VERSION 5.8 ;
BUSBITCHARS "[]" ;
DIVIDERCHAR "/" ;
UNITS
    DATABASE MICRONS 1000 ;
END UNITS

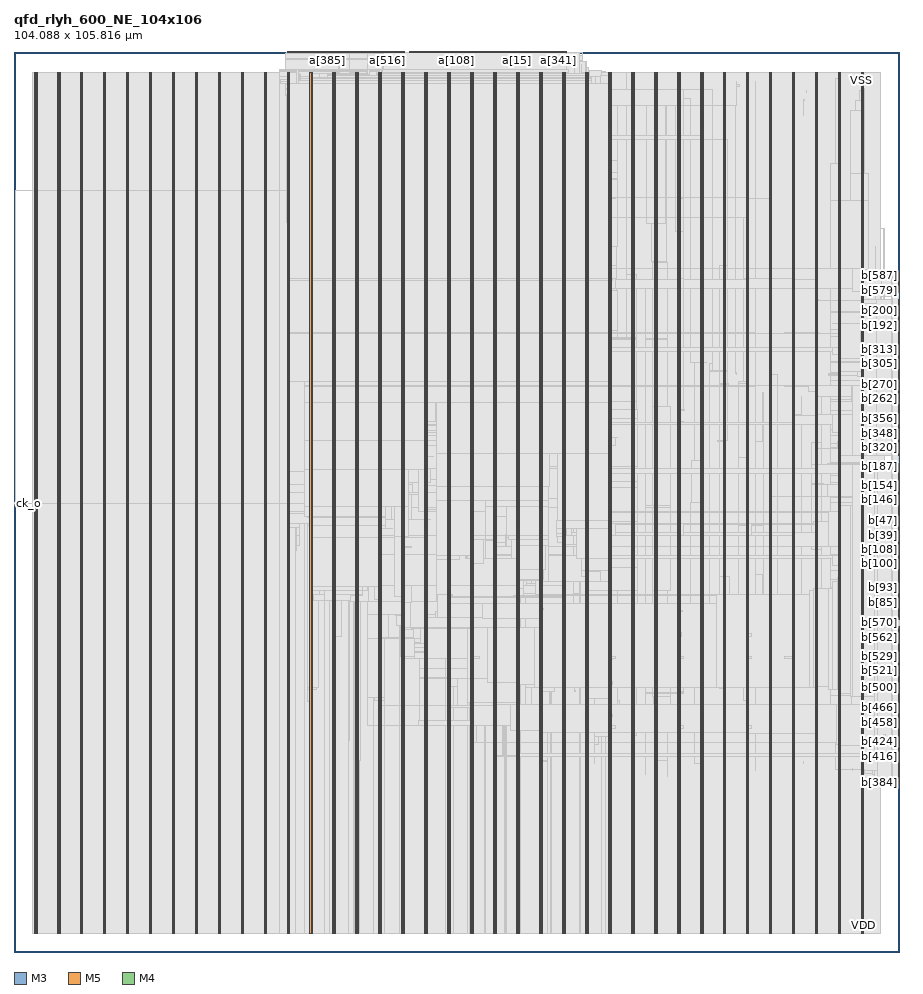
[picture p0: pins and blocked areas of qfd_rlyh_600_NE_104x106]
MACRO qfd_rlyh_600_NE_104x106
  FOREIGN qfd_rlyh_600_NE_104x106 0 0 ;
  CLASS BLOCK ;
  SIZE 104.088 BY 105.816 ;
  PIN a[0]
    DIRECTION INPUT ;
    USE SIGNAL ;
    PORT
      LAYER M3 ;
        RECT  58.068 105.779 58.086 105.816 ;
    END
  END a[0]
  PIN a[100]
    DIRECTION INPUT ;
    USE SIGNAL ;
    PORT
      LAYER M3 ;
        RECT  51.444 105.779 51.462 105.816 ;
    END
  END a[100]
  PIN a[101]
    DIRECTION INPUT ;
    USE SIGNAL ;
    PORT
      LAYER M3 ;
        RECT  51.516 105.779 51.534 105.816 ;
    END
  END a[101]
  PIN a[102]
    DIRECTION INPUT ;
    USE SIGNAL ;
    PORT
      LAYER M3 ;
        RECT  51.588 105.779 51.606 105.816 ;
    END
  END a[102]
  PIN a[103]
    DIRECTION INPUT ;
    USE SIGNAL ;
    PORT
      LAYER M3 ;
        RECT  51.66 105.779 51.678 105.816 ;
    END
  END a[103]
  PIN a[104]
    DIRECTION INPUT ;
    USE SIGNAL ;
    PORT
      LAYER M3 ;
        RECT  51.732 105.779 51.75 105.816 ;
    END
  END a[104]
  PIN a[105]
    DIRECTION INPUT ;
    USE SIGNAL ;
    PORT
      LAYER M3 ;
        RECT  51.804 105.779 51.822 105.816 ;
    END
  END a[105]
  PIN a[106]
    DIRECTION INPUT ;
    USE SIGNAL ;
    PORT
      LAYER M3 ;
        RECT  51.876 105.779 51.894 105.816 ;
    END
  END a[106]
  PIN a[107]
    DIRECTION INPUT ;
    USE SIGNAL ;
    PORT
      LAYER M3 ;
        RECT  51.948 105.779 51.966 105.816 ;
    END
  END a[107]
  PIN a[108]
    DIRECTION INPUT ;
    USE SIGNAL ;
    PORT
      LAYER M3 ;
        RECT  52.02 105.779 52.038 105.816 ;
    END
  END a[108]
  PIN a[109]
    DIRECTION INPUT ;
    USE SIGNAL ;
    PORT
      LAYER M3 ;
        RECT  52.092 105.779 52.11 105.816 ;
    END
  END a[109]
  PIN a[10]
    DIRECTION INPUT ;
    USE SIGNAL ;
    PORT
      LAYER M3 ;
        RECT  58.788 105.779 58.806 105.816 ;
    END
  END a[10]
  PIN a[110]
    DIRECTION INPUT ;
    USE SIGNAL ;
    PORT
      LAYER M3 ;
        RECT  52.164 105.779 52.182 105.816 ;
    END
  END a[110]
  PIN a[111]
    DIRECTION INPUT ;
    USE SIGNAL ;
    PORT
      LAYER M3 ;
        RECT  52.236 105.779 52.254 105.816 ;
    END
  END a[111]
  PIN a[112]
    DIRECTION INPUT ;
    USE SIGNAL ;
    PORT
      LAYER M3 ;
        RECT  52.308 105.779 52.326 105.816 ;
    END
  END a[112]
  PIN a[113]
    DIRECTION INPUT ;
    USE SIGNAL ;
    PORT
      LAYER M3 ;
        RECT  52.38 105.779 52.398 105.816 ;
    END
  END a[113]
  PIN a[114]
    DIRECTION INPUT ;
    USE SIGNAL ;
    PORT
      LAYER M3 ;
        RECT  52.452 105.779 52.47 105.816 ;
    END
  END a[114]
  PIN a[115]
    DIRECTION INPUT ;
    USE SIGNAL ;
    PORT
      LAYER M3 ;
        RECT  52.524 105.779 52.542 105.816 ;
    END
  END a[115]
  PIN a[116]
    DIRECTION INPUT ;
    USE SIGNAL ;
    PORT
      LAYER M3 ;
        RECT  52.596 105.779 52.614 105.816 ;
    END
  END a[116]
  PIN a[117]
    DIRECTION INPUT ;
    USE SIGNAL ;
    PORT
      LAYER M3 ;
        RECT  52.668 105.779 52.686 105.816 ;
    END
  END a[117]
  PIN a[118]
    DIRECTION INPUT ;
    USE SIGNAL ;
    PORT
      LAYER M3 ;
        RECT  52.74 105.779 52.758 105.816 ;
    END
  END a[118]
  PIN a[119]
    DIRECTION INPUT ;
    USE SIGNAL ;
    PORT
      LAYER M3 ;
        RECT  52.812 105.779 52.83 105.816 ;
    END
  END a[119]
  PIN a[11]
    DIRECTION INPUT ;
    USE SIGNAL ;
    PORT
      LAYER M3 ;
        RECT  58.86 105.779 58.878 105.816 ;
    END
  END a[11]
  PIN a[120]
    DIRECTION INPUT ;
    USE SIGNAL ;
    PORT
      LAYER M3 ;
        RECT  52.884 105.779 52.902 105.816 ;
    END
  END a[120]
  PIN a[121]
    DIRECTION INPUT ;
    USE SIGNAL ;
    PORT
      LAYER M3 ;
        RECT  52.956 105.779 52.974 105.816 ;
    END
  END a[121]
  PIN a[122]
    DIRECTION INPUT ;
    USE SIGNAL ;
    PORT
      LAYER M3 ;
        RECT  53.028 105.779 53.046 105.816 ;
    END
  END a[122]
  PIN a[123]
    DIRECTION INPUT ;
    USE SIGNAL ;
    PORT
      LAYER M3 ;
        RECT  53.1 105.779 53.118 105.816 ;
    END
  END a[123]
  PIN a[124]
    DIRECTION INPUT ;
    USE SIGNAL ;
    PORT
      LAYER M3 ;
        RECT  53.172 105.779 53.19 105.816 ;
    END
  END a[124]
  PIN a[125]
    DIRECTION INPUT ;
    USE SIGNAL ;
    PORT
      LAYER M3 ;
        RECT  53.244 105.779 53.262 105.816 ;
    END
  END a[125]
  PIN a[126]
    DIRECTION INPUT ;
    USE SIGNAL ;
    PORT
      LAYER M3 ;
        RECT  53.316 105.779 53.334 105.816 ;
    END
  END a[126]
  PIN a[127]
    DIRECTION INPUT ;
    USE SIGNAL ;
    PORT
      LAYER M3 ;
        RECT  53.388 105.779 53.406 105.816 ;
    END
  END a[127]
  PIN a[128]
    DIRECTION INPUT ;
    USE SIGNAL ;
    PORT
      LAYER M3 ;
        RECT  53.46 105.779 53.478 105.816 ;
    END
  END a[128]
  PIN a[129]
    DIRECTION INPUT ;
    USE SIGNAL ;
    PORT
      LAYER M3 ;
        RECT  53.532 105.779 53.55 105.816 ;
    END
  END a[129]
  PIN a[12]
    DIRECTION INPUT ;
    USE SIGNAL ;
    PORT
      LAYER M3 ;
        RECT  58.932 105.779 58.95 105.816 ;
    END
  END a[12]
  PIN a[130]
    DIRECTION INPUT ;
    USE SIGNAL ;
    PORT
      LAYER M3 ;
        RECT  53.604 105.779 53.622 105.816 ;
    END
  END a[130]
  PIN a[131]
    DIRECTION INPUT ;
    USE SIGNAL ;
    PORT
      LAYER M3 ;
        RECT  53.676 105.779 53.694 105.816 ;
    END
  END a[131]
  PIN a[132]
    DIRECTION INPUT ;
    USE SIGNAL ;
    PORT
      LAYER M3 ;
        RECT  53.748 105.779 53.766 105.816 ;
    END
  END a[132]
  PIN a[133]
    DIRECTION INPUT ;
    USE SIGNAL ;
    PORT
      LAYER M3 ;
        RECT  53.82 105.779 53.838 105.816 ;
    END
  END a[133]
  PIN a[134]
    DIRECTION INPUT ;
    USE SIGNAL ;
    PORT
      LAYER M3 ;
        RECT  53.892 105.779 53.91 105.816 ;
    END
  END a[134]
  PIN a[135]
    DIRECTION INPUT ;
    USE SIGNAL ;
    PORT
      LAYER M3 ;
        RECT  53.964 105.779 53.982 105.816 ;
    END
  END a[135]
  PIN a[136]
    DIRECTION INPUT ;
    USE SIGNAL ;
    PORT
      LAYER M3 ;
        RECT  54.036 105.779 54.054 105.816 ;
    END
  END a[136]
  PIN a[137]
    DIRECTION INPUT ;
    USE SIGNAL ;
    PORT
      LAYER M3 ;
        RECT  54.108 105.779 54.126 105.816 ;
    END
  END a[137]
  PIN a[138]
    DIRECTION INPUT ;
    USE SIGNAL ;
    PORT
      LAYER M3 ;
        RECT  54.18 105.779 54.198 105.816 ;
    END
  END a[138]
  PIN a[139]
    DIRECTION INPUT ;
    USE SIGNAL ;
    PORT
      LAYER M3 ;
        RECT  54.252 105.779 54.27 105.816 ;
    END
  END a[139]
  PIN a[13]
    DIRECTION INPUT ;
    USE SIGNAL ;
    PORT
      LAYER M3 ;
        RECT  59.004 105.779 59.022 105.816 ;
    END
  END a[13]
  PIN a[140]
    DIRECTION INPUT ;
    USE SIGNAL ;
    PORT
      LAYER M3 ;
        RECT  54.324 105.779 54.342 105.816 ;
    END
  END a[140]
  PIN a[141]
    DIRECTION INPUT ;
    USE SIGNAL ;
    PORT
      LAYER M3 ;
        RECT  54.396 105.779 54.414 105.816 ;
    END
  END a[141]
  PIN a[142]
    DIRECTION INPUT ;
    USE SIGNAL ;
    PORT
      LAYER M3 ;
        RECT  54.468 105.779 54.486 105.816 ;
    END
  END a[142]
  PIN a[143]
    DIRECTION INPUT ;
    USE SIGNAL ;
    PORT
      LAYER M3 ;
        RECT  54.54 105.779 54.558 105.816 ;
    END
  END a[143]
  PIN a[144]
    DIRECTION INPUT ;
    USE SIGNAL ;
    PORT
      LAYER M3 ;
        RECT  54.612 105.779 54.63 105.816 ;
    END
  END a[144]
  PIN a[145]
    DIRECTION INPUT ;
    USE SIGNAL ;
    PORT
      LAYER M3 ;
        RECT  54.684 105.779 54.702 105.816 ;
    END
  END a[145]
  PIN a[146]
    DIRECTION INPUT ;
    USE SIGNAL ;
    PORT
      LAYER M3 ;
        RECT  54.756 105.779 54.774 105.816 ;
    END
  END a[146]
  PIN a[147]
    DIRECTION INPUT ;
    USE SIGNAL ;
    PORT
      LAYER M3 ;
        RECT  54.828 105.779 54.846 105.816 ;
    END
  END a[147]
  PIN a[148]
    DIRECTION INPUT ;
    USE SIGNAL ;
    PORT
      LAYER M3 ;
        RECT  54.9 105.779 54.918 105.816 ;
    END
  END a[148]
  PIN a[149]
    DIRECTION INPUT ;
    USE SIGNAL ;
    PORT
      LAYER M3 ;
        RECT  54.972 105.779 54.99 105.816 ;
    END
  END a[149]
  PIN a[14]
    DIRECTION INPUT ;
    USE SIGNAL ;
    PORT
      LAYER M3 ;
        RECT  59.076 105.779 59.094 105.816 ;
    END
  END a[14]
  PIN a[150]
    DIRECTION INPUT ;
    USE SIGNAL ;
    PORT
      LAYER M3 ;
        RECT  55.044 105.779 55.062 105.816 ;
    END
  END a[150]
  PIN a[151]
    DIRECTION INPUT ;
    USE SIGNAL ;
    PORT
      LAYER M3 ;
        RECT  55.116 105.779 55.134 105.816 ;
    END
  END a[151]
  PIN a[152]
    DIRECTION INPUT ;
    USE SIGNAL ;
    PORT
      LAYER M3 ;
        RECT  55.188 105.779 55.206 105.816 ;
    END
  END a[152]
  PIN a[153]
    DIRECTION INPUT ;
    USE SIGNAL ;
    PORT
      LAYER M3 ;
        RECT  55.26 105.779 55.278 105.816 ;
    END
  END a[153]
  PIN a[154]
    DIRECTION INPUT ;
    USE SIGNAL ;
    PORT
      LAYER M3 ;
        RECT  55.332 105.779 55.35 105.816 ;
    END
  END a[154]
  PIN a[155]
    DIRECTION INPUT ;
    USE SIGNAL ;
    PORT
      LAYER M3 ;
        RECT  55.404 105.779 55.422 105.816 ;
    END
  END a[155]
  PIN a[156]
    DIRECTION INPUT ;
    USE SIGNAL ;
    PORT
      LAYER M3 ;
        RECT  55.476 105.779 55.494 105.816 ;
    END
  END a[156]
  PIN a[157]
    DIRECTION INPUT ;
    USE SIGNAL ;
    PORT
      LAYER M3 ;
        RECT  55.548 105.779 55.566 105.816 ;
    END
  END a[157]
  PIN a[158]
    DIRECTION INPUT ;
    USE SIGNAL ;
    PORT
      LAYER M3 ;
        RECT  55.62 105.779 55.638 105.816 ;
    END
  END a[158]
  PIN a[159]
    DIRECTION INPUT ;
    USE SIGNAL ;
    PORT
      LAYER M3 ;
        RECT  55.692 105.779 55.71 105.816 ;
    END
  END a[159]
  PIN a[15]
    DIRECTION INPUT ;
    USE SIGNAL ;
    PORT
      LAYER M3 ;
        RECT  59.148 105.779 59.166 105.816 ;
    END
  END a[15]
  PIN a[160]
    DIRECTION INPUT ;
    USE SIGNAL ;
    PORT
      LAYER M3 ;
        RECT  48.852 105.779 48.87 105.816 ;
    END
  END a[160]
  PIN a[161]
    DIRECTION INPUT ;
    USE SIGNAL ;
    PORT
      LAYER M3 ;
        RECT  48.924 105.779 48.942 105.816 ;
    END
  END a[161]
  PIN a[162]
    DIRECTION INPUT ;
    USE SIGNAL ;
    PORT
      LAYER M3 ;
        RECT  48.996 105.779 49.014 105.816 ;
    END
  END a[162]
  PIN a[163]
    DIRECTION INPUT ;
    USE SIGNAL ;
    PORT
      LAYER M3 ;
        RECT  49.068 105.779 49.086 105.816 ;
    END
  END a[163]
  PIN a[164]
    DIRECTION INPUT ;
    USE SIGNAL ;
    PORT
      LAYER M3 ;
        RECT  49.14 105.779 49.158 105.816 ;
    END
  END a[164]
  PIN a[165]
    DIRECTION INPUT ;
    USE SIGNAL ;
    PORT
      LAYER M3 ;
        RECT  49.212 105.779 49.23 105.816 ;
    END
  END a[165]
  PIN a[166]
    DIRECTION INPUT ;
    USE SIGNAL ;
    PORT
      LAYER M3 ;
        RECT  49.284 105.779 49.302 105.816 ;
    END
  END a[166]
  PIN a[167]
    DIRECTION INPUT ;
    USE SIGNAL ;
    PORT
      LAYER M3 ;
        RECT  49.356 105.779 49.374 105.816 ;
    END
  END a[167]
  PIN a[168]
    DIRECTION INPUT ;
    USE SIGNAL ;
    PORT
      LAYER M3 ;
        RECT  49.428 105.779 49.446 105.816 ;
    END
  END a[168]
  PIN a[169]
    DIRECTION INPUT ;
    USE SIGNAL ;
    PORT
      LAYER M3 ;
        RECT  49.5 105.779 49.518 105.816 ;
    END
  END a[169]
  PIN a[16]
    DIRECTION INPUT ;
    USE SIGNAL ;
    PORT
      LAYER M3 ;
        RECT  59.22 105.779 59.238 105.816 ;
    END
  END a[16]
  PIN a[170]
    DIRECTION INPUT ;
    USE SIGNAL ;
    PORT
      LAYER M3 ;
        RECT  49.572 105.779 49.59 105.816 ;
    END
  END a[170]
  PIN a[171]
    DIRECTION INPUT ;
    USE SIGNAL ;
    PORT
      LAYER M3 ;
        RECT  49.644 105.779 49.662 105.816 ;
    END
  END a[171]
  PIN a[172]
    DIRECTION INPUT ;
    USE SIGNAL ;
    PORT
      LAYER M3 ;
        RECT  49.716 105.779 49.734 105.816 ;
    END
  END a[172]
  PIN a[173]
    DIRECTION INPUT ;
    USE SIGNAL ;
    PORT
      LAYER M3 ;
        RECT  49.788 105.779 49.806 105.816 ;
    END
  END a[173]
  PIN a[174]
    DIRECTION INPUT ;
    USE SIGNAL ;
    PORT
      LAYER M3 ;
        RECT  49.86 105.779 49.878 105.816 ;
    END
  END a[174]
  PIN a[175]
    DIRECTION INPUT ;
    USE SIGNAL ;
    PORT
      LAYER M3 ;
        RECT  49.932 105.779 49.95 105.816 ;
    END
  END a[175]
  PIN a[176]
    DIRECTION INPUT ;
    USE SIGNAL ;
    PORT
      LAYER M3 ;
        RECT  50.004 105.779 50.022 105.816 ;
    END
  END a[176]
  PIN a[177]
    DIRECTION INPUT ;
    USE SIGNAL ;
    PORT
      LAYER M3 ;
        RECT  50.076 105.779 50.094 105.816 ;
    END
  END a[177]
  PIN a[178]
    DIRECTION INPUT ;
    USE SIGNAL ;
    PORT
      LAYER M3 ;
        RECT  50.148 105.779 50.166 105.816 ;
    END
  END a[178]
  PIN a[179]
    DIRECTION INPUT ;
    USE SIGNAL ;
    PORT
      LAYER M3 ;
        RECT  50.22 105.779 50.238 105.816 ;
    END
  END a[179]
  PIN a[17]
    DIRECTION INPUT ;
    USE SIGNAL ;
    PORT
      LAYER M3 ;
        RECT  59.292 105.779 59.31 105.816 ;
    END
  END a[17]
  PIN a[180]
    DIRECTION INPUT ;
    USE SIGNAL ;
    PORT
      LAYER M3 ;
        RECT  50.292 105.779 50.31 105.816 ;
    END
  END a[180]
  PIN a[181]
    DIRECTION INPUT ;
    USE SIGNAL ;
    PORT
      LAYER M3 ;
        RECT  50.364 105.779 50.382 105.816 ;
    END
  END a[181]
  PIN a[182]
    DIRECTION INPUT ;
    USE SIGNAL ;
    PORT
      LAYER M3 ;
        RECT  50.436 105.779 50.454 105.816 ;
    END
  END a[182]
  PIN a[183]
    DIRECTION INPUT ;
    USE SIGNAL ;
    PORT
      LAYER M3 ;
        RECT  50.508 105.779 50.526 105.816 ;
    END
  END a[183]
  PIN a[184]
    DIRECTION INPUT ;
    USE SIGNAL ;
    PORT
      LAYER M3 ;
        RECT  50.58 105.779 50.598 105.816 ;
    END
  END a[184]
  PIN a[185]
    DIRECTION INPUT ;
    USE SIGNAL ;
    PORT
      LAYER M3 ;
        RECT  50.652 105.779 50.67 105.816 ;
    END
  END a[185]
  PIN a[186]
    DIRECTION INPUT ;
    USE SIGNAL ;
    PORT
      LAYER M3 ;
        RECT  50.724 105.779 50.742 105.816 ;
    END
  END a[186]
  PIN a[187]
    DIRECTION INPUT ;
    USE SIGNAL ;
    PORT
      LAYER M3 ;
        RECT  50.796 105.779 50.814 105.816 ;
    END
  END a[187]
  PIN a[188]
    DIRECTION INPUT ;
    USE SIGNAL ;
    PORT
      LAYER M3 ;
        RECT  50.868 105.779 50.886 105.816 ;
    END
  END a[188]
  PIN a[189]
    DIRECTION INPUT ;
    USE SIGNAL ;
    PORT
      LAYER M3 ;
        RECT  50.94 105.779 50.958 105.816 ;
    END
  END a[189]
  PIN a[18]
    DIRECTION INPUT ;
    USE SIGNAL ;
    PORT
      LAYER M3 ;
        RECT  59.364 105.779 59.382 105.816 ;
    END
  END a[18]
  PIN a[190]
    DIRECTION INPUT ;
    USE SIGNAL ;
    PORT
      LAYER M3 ;
        RECT  51.012 105.779 51.03 105.816 ;
    END
  END a[190]
  PIN a[191]
    DIRECTION INPUT ;
    USE SIGNAL ;
    PORT
      LAYER M3 ;
        RECT  51.084 105.779 51.102 105.816 ;
    END
  END a[191]
  PIN a[192]
    DIRECTION INPUT ;
    USE SIGNAL ;
    PORT
      LAYER M5 ;
        RECT  49.68 105.732 49.704 105.816 ;
    END
  END a[192]
  PIN a[193]
    DIRECTION INPUT ;
    USE SIGNAL ;
    PORT
      LAYER M5 ;
        RECT  49.776 105.732 49.8 105.816 ;
    END
  END a[193]
  PIN a[194]
    DIRECTION INPUT ;
    USE SIGNAL ;
    PORT
      LAYER M5 ;
        RECT  49.872 105.732 49.896 105.816 ;
    END
  END a[194]
  PIN a[195]
    DIRECTION INPUT ;
    USE SIGNAL ;
    PORT
      LAYER M5 ;
        RECT  49.968 105.732 49.992 105.816 ;
    END
  END a[195]
  PIN a[196]
    DIRECTION INPUT ;
    USE SIGNAL ;
    PORT
      LAYER M5 ;
        RECT  50.064 105.732 50.088 105.816 ;
    END
  END a[196]
  PIN a[197]
    DIRECTION INPUT ;
    USE SIGNAL ;
    PORT
      LAYER M5 ;
        RECT  50.16 105.732 50.184 105.816 ;
    END
  END a[197]
  PIN a[198]
    DIRECTION INPUT ;
    USE SIGNAL ;
    PORT
      LAYER M5 ;
        RECT  50.256 105.732 50.28 105.816 ;
    END
  END a[198]
  PIN a[199]
    DIRECTION INPUT ;
    USE SIGNAL ;
    PORT
      LAYER M5 ;
        RECT  50.352 105.732 50.376 105.816 ;
    END
  END a[199]
  PIN a[19]
    DIRECTION INPUT ;
    USE SIGNAL ;
    PORT
      LAYER M3 ;
        RECT  59.436 105.779 59.454 105.816 ;
    END
  END a[19]
  PIN a[1]
    DIRECTION INPUT ;
    USE SIGNAL ;
    PORT
      LAYER M3 ;
        RECT  58.14 105.779 58.158 105.816 ;
    END
  END a[1]
  PIN a[200]
    DIRECTION INPUT ;
    USE SIGNAL ;
    PORT
      LAYER M5 ;
        RECT  50.448 105.732 50.472 105.816 ;
    END
  END a[200]
  PIN a[201]
    DIRECTION INPUT ;
    USE SIGNAL ;
    PORT
      LAYER M5 ;
        RECT  50.544 105.732 50.568 105.816 ;
    END
  END a[201]
  PIN a[202]
    DIRECTION INPUT ;
    USE SIGNAL ;
    PORT
      LAYER M5 ;
        RECT  50.64 105.732 50.664 105.816 ;
    END
  END a[202]
  PIN a[203]
    DIRECTION INPUT ;
    USE SIGNAL ;
    PORT
      LAYER M5 ;
        RECT  50.736 105.732 50.76 105.816 ;
    END
  END a[203]
  PIN a[204]
    DIRECTION INPUT ;
    USE SIGNAL ;
    PORT
      LAYER M5 ;
        RECT  50.832 105.732 50.856 105.816 ;
    END
  END a[204]
  PIN a[205]
    DIRECTION INPUT ;
    USE SIGNAL ;
    PORT
      LAYER M5 ;
        RECT  50.928 105.732 50.952 105.816 ;
    END
  END a[205]
  PIN a[206]
    DIRECTION INPUT ;
    USE SIGNAL ;
    PORT
      LAYER M5 ;
        RECT  51.024 105.732 51.048 105.816 ;
    END
  END a[206]
  PIN a[207]
    DIRECTION INPUT ;
    USE SIGNAL ;
    PORT
      LAYER M5 ;
        RECT  51.12 105.732 51.144 105.816 ;
    END
  END a[207]
  PIN a[208]
    DIRECTION INPUT ;
    USE SIGNAL ;
    PORT
      LAYER M5 ;
        RECT  51.216 105.732 51.24 105.816 ;
    END
  END a[208]
  PIN a[209]
    DIRECTION INPUT ;
    USE SIGNAL ;
    PORT
      LAYER M5 ;
        RECT  51.312 105.732 51.336 105.816 ;
    END
  END a[209]
  PIN a[20]
    DIRECTION INPUT ;
    USE SIGNAL ;
    PORT
      LAYER M3 ;
        RECT  59.508 105.779 59.526 105.816 ;
    END
  END a[20]
  PIN a[210]
    DIRECTION INPUT ;
    USE SIGNAL ;
    PORT
      LAYER M5 ;
        RECT  51.408 105.732 51.432 105.816 ;
    END
  END a[210]
  PIN a[211]
    DIRECTION INPUT ;
    USE SIGNAL ;
    PORT
      LAYER M5 ;
        RECT  51.504 105.732 51.528 105.816 ;
    END
  END a[211]
  PIN a[212]
    DIRECTION INPUT ;
    USE SIGNAL ;
    PORT
      LAYER M5 ;
        RECT  51.6 105.732 51.624 105.816 ;
    END
  END a[212]
  PIN a[213]
    DIRECTION INPUT ;
    USE SIGNAL ;
    PORT
      LAYER M5 ;
        RECT  51.696 105.732 51.72 105.816 ;
    END
  END a[213]
  PIN a[214]
    DIRECTION INPUT ;
    USE SIGNAL ;
    PORT
      LAYER M5 ;
        RECT  51.792 105.732 51.816 105.816 ;
    END
  END a[214]
  PIN a[215]
    DIRECTION INPUT ;
    USE SIGNAL ;
    PORT
      LAYER M5 ;
        RECT  51.888 105.732 51.912 105.816 ;
    END
  END a[215]
  PIN a[216]
    DIRECTION INPUT ;
    USE SIGNAL ;
    PORT
      LAYER M5 ;
        RECT  51.984 105.732 52.008 105.816 ;
    END
  END a[216]
  PIN a[217]
    DIRECTION INPUT ;
    USE SIGNAL ;
    PORT
      LAYER M5 ;
        RECT  52.08 105.732 52.104 105.816 ;
    END
  END a[217]
  PIN a[218]
    DIRECTION INPUT ;
    USE SIGNAL ;
    PORT
      LAYER M5 ;
        RECT  52.176 105.732 52.2 105.816 ;
    END
  END a[218]
  PIN a[219]
    DIRECTION INPUT ;
    USE SIGNAL ;
    PORT
      LAYER M5 ;
        RECT  52.272 105.732 52.296 105.816 ;
    END
  END a[219]
  PIN a[21]
    DIRECTION INPUT ;
    USE SIGNAL ;
    PORT
      LAYER M3 ;
        RECT  59.58 105.779 59.598 105.816 ;
    END
  END a[21]
  PIN a[220]
    DIRECTION INPUT ;
    USE SIGNAL ;
    PORT
      LAYER M5 ;
        RECT  52.368 105.732 52.392 105.816 ;
    END
  END a[220]
  PIN a[221]
    DIRECTION INPUT ;
    USE SIGNAL ;
    PORT
      LAYER M5 ;
        RECT  52.464 105.732 52.488 105.816 ;
    END
  END a[221]
  PIN a[222]
    DIRECTION INPUT ;
    USE SIGNAL ;
    PORT
      LAYER M5 ;
        RECT  52.56 105.732 52.584 105.816 ;
    END
  END a[222]
  PIN a[223]
    DIRECTION INPUT ;
    USE SIGNAL ;
    PORT
      LAYER M5 ;
        RECT  52.656 105.732 52.68 105.816 ;
    END
  END a[223]
  PIN a[224]
    DIRECTION INPUT ;
    USE SIGNAL ;
    PORT
      LAYER M5 ;
        RECT  46.608 105.732 46.632 105.816 ;
    END
  END a[224]
  PIN a[225]
    DIRECTION INPUT ;
    USE SIGNAL ;
    PORT
      LAYER M5 ;
        RECT  46.704 105.732 46.728 105.816 ;
    END
  END a[225]
  PIN a[226]
    DIRECTION INPUT ;
    USE SIGNAL ;
    PORT
      LAYER M5 ;
        RECT  46.8 105.732 46.824 105.816 ;
    END
  END a[226]
  PIN a[227]
    DIRECTION INPUT ;
    USE SIGNAL ;
    PORT
      LAYER M5 ;
        RECT  46.896 105.732 46.92 105.816 ;
    END
  END a[227]
  PIN a[228]
    DIRECTION INPUT ;
    USE SIGNAL ;
    PORT
      LAYER M5 ;
        RECT  46.992 105.732 47.016 105.816 ;
    END
  END a[228]
  PIN a[229]
    DIRECTION INPUT ;
    USE SIGNAL ;
    PORT
      LAYER M5 ;
        RECT  47.088 105.732 47.112 105.816 ;
    END
  END a[229]
  PIN a[22]
    DIRECTION INPUT ;
    USE SIGNAL ;
    PORT
      LAYER M3 ;
        RECT  59.652 105.779 59.67 105.816 ;
    END
  END a[22]
  PIN a[230]
    DIRECTION INPUT ;
    USE SIGNAL ;
    PORT
      LAYER M5 ;
        RECT  47.184 105.732 47.208 105.816 ;
    END
  END a[230]
  PIN a[231]
    DIRECTION INPUT ;
    USE SIGNAL ;
    PORT
      LAYER M5 ;
        RECT  47.28 105.732 47.304 105.816 ;
    END
  END a[231]
  PIN a[232]
    DIRECTION INPUT ;
    USE SIGNAL ;
    PORT
      LAYER M5 ;
        RECT  47.376 105.732 47.4 105.816 ;
    END
  END a[232]
  PIN a[233]
    DIRECTION INPUT ;
    USE SIGNAL ;
    PORT
      LAYER M5 ;
        RECT  47.472 105.732 47.496 105.816 ;
    END
  END a[233]
  PIN a[234]
    DIRECTION INPUT ;
    USE SIGNAL ;
    PORT
      LAYER M5 ;
        RECT  47.568 105.732 47.592 105.816 ;
    END
  END a[234]
  PIN a[235]
    DIRECTION INPUT ;
    USE SIGNAL ;
    PORT
      LAYER M5 ;
        RECT  47.664 105.732 47.688 105.816 ;
    END
  END a[235]
  PIN a[236]
    DIRECTION INPUT ;
    USE SIGNAL ;
    PORT
      LAYER M5 ;
        RECT  47.76 105.732 47.784 105.816 ;
    END
  END a[236]
  PIN a[237]
    DIRECTION INPUT ;
    USE SIGNAL ;
    PORT
      LAYER M5 ;
        RECT  47.856 105.732 47.88 105.816 ;
    END
  END a[237]
  PIN a[238]
    DIRECTION INPUT ;
    USE SIGNAL ;
    PORT
      LAYER M5 ;
        RECT  47.952 105.732 47.976 105.816 ;
    END
  END a[238]
  PIN a[239]
    DIRECTION INPUT ;
    USE SIGNAL ;
    PORT
      LAYER M5 ;
        RECT  48.048 105.732 48.072 105.816 ;
    END
  END a[239]
  PIN a[23]
    DIRECTION INPUT ;
    USE SIGNAL ;
    PORT
      LAYER M3 ;
        RECT  59.724 105.779 59.742 105.816 ;
    END
  END a[23]
  PIN a[240]
    DIRECTION INPUT ;
    USE SIGNAL ;
    PORT
      LAYER M5 ;
        RECT  48.144 105.732 48.168 105.816 ;
    END
  END a[240]
  PIN a[241]
    DIRECTION INPUT ;
    USE SIGNAL ;
    PORT
      LAYER M5 ;
        RECT  48.24 105.732 48.264 105.816 ;
    END
  END a[241]
  PIN a[242]
    DIRECTION INPUT ;
    USE SIGNAL ;
    PORT
      LAYER M5 ;
        RECT  48.336 105.732 48.36 105.816 ;
    END
  END a[242]
  PIN a[243]
    DIRECTION INPUT ;
    USE SIGNAL ;
    PORT
      LAYER M5 ;
        RECT  48.432 105.732 48.456 105.816 ;
    END
  END a[243]
  PIN a[244]
    DIRECTION INPUT ;
    USE SIGNAL ;
    PORT
      LAYER M5 ;
        RECT  48.528 105.732 48.552 105.816 ;
    END
  END a[244]
  PIN a[245]
    DIRECTION INPUT ;
    USE SIGNAL ;
    PORT
      LAYER M5 ;
        RECT  48.624 105.732 48.648 105.816 ;
    END
  END a[245]
  PIN a[246]
    DIRECTION INPUT ;
    USE SIGNAL ;
    PORT
      LAYER M5 ;
        RECT  48.72 105.732 48.744 105.816 ;
    END
  END a[246]
  PIN a[247]
    DIRECTION INPUT ;
    USE SIGNAL ;
    PORT
      LAYER M5 ;
        RECT  48.816 105.732 48.84 105.816 ;
    END
  END a[247]
  PIN a[248]
    DIRECTION INPUT ;
    USE SIGNAL ;
    PORT
      LAYER M5 ;
        RECT  48.912 105.732 48.936 105.816 ;
    END
  END a[248]
  PIN a[249]
    DIRECTION INPUT ;
    USE SIGNAL ;
    PORT
      LAYER M5 ;
        RECT  49.008 105.732 49.032 105.816 ;
    END
  END a[249]
  PIN a[24]
    DIRECTION INPUT ;
    USE SIGNAL ;
    PORT
      LAYER M3 ;
        RECT  59.796 105.779 59.814 105.816 ;
    END
  END a[24]
  PIN a[250]
    DIRECTION INPUT ;
    USE SIGNAL ;
    PORT
      LAYER M5 ;
        RECT  49.104 105.732 49.128 105.816 ;
    END
  END a[250]
  PIN a[251]
    DIRECTION INPUT ;
    USE SIGNAL ;
    PORT
      LAYER M5 ;
        RECT  49.2 105.732 49.224 105.816 ;
    END
  END a[251]
  PIN a[252]
    DIRECTION INPUT ;
    USE SIGNAL ;
    PORT
      LAYER M5 ;
        RECT  49.296 105.732 49.32 105.816 ;
    END
  END a[252]
  PIN a[253]
    DIRECTION INPUT ;
    USE SIGNAL ;
    PORT
      LAYER M5 ;
        RECT  49.392 105.732 49.416 105.816 ;
    END
  END a[253]
  PIN a[254]
    DIRECTION INPUT ;
    USE SIGNAL ;
    PORT
      LAYER M5 ;
        RECT  49.488 105.732 49.512 105.816 ;
    END
  END a[254]
  PIN a[255]
    DIRECTION INPUT ;
    USE SIGNAL ;
    PORT
      LAYER M5 ;
        RECT  49.584 105.732 49.608 105.816 ;
    END
  END a[255]
  PIN a[256]
    DIRECTION INPUT ;
    USE SIGNAL ;
    PORT
      LAYER M5 ;
        RECT  55.824 105.732 55.848 105.816 ;
    END
  END a[256]
  PIN a[257]
    DIRECTION INPUT ;
    USE SIGNAL ;
    PORT
      LAYER M5 ;
        RECT  55.92 105.732 55.944 105.816 ;
    END
  END a[257]
  PIN a[258]
    DIRECTION INPUT ;
    USE SIGNAL ;
    PORT
      LAYER M5 ;
        RECT  56.016 105.732 56.04 105.816 ;
    END
  END a[258]
  PIN a[259]
    DIRECTION INPUT ;
    USE SIGNAL ;
    PORT
      LAYER M5 ;
        RECT  56.112 105.732 56.136 105.816 ;
    END
  END a[259]
  PIN a[25]
    DIRECTION INPUT ;
    USE SIGNAL ;
    PORT
      LAYER M3 ;
        RECT  59.868 105.779 59.886 105.816 ;
    END
  END a[25]
  PIN a[260]
    DIRECTION INPUT ;
    USE SIGNAL ;
    PORT
      LAYER M5 ;
        RECT  56.208 105.732 56.232 105.816 ;
    END
  END a[260]
  PIN a[261]
    DIRECTION INPUT ;
    USE SIGNAL ;
    PORT
      LAYER M5 ;
        RECT  56.304 105.732 56.328 105.816 ;
    END
  END a[261]
  PIN a[262]
    DIRECTION INPUT ;
    USE SIGNAL ;
    PORT
      LAYER M5 ;
        RECT  56.4 105.732 56.424 105.816 ;
    END
  END a[262]
  PIN a[263]
    DIRECTION INPUT ;
    USE SIGNAL ;
    PORT
      LAYER M5 ;
        RECT  56.496 105.732 56.52 105.816 ;
    END
  END a[263]
  PIN a[264]
    DIRECTION INPUT ;
    USE SIGNAL ;
    PORT
      LAYER M5 ;
        RECT  56.592 105.732 56.616 105.816 ;
    END
  END a[264]
  PIN a[265]
    DIRECTION INPUT ;
    USE SIGNAL ;
    PORT
      LAYER M5 ;
        RECT  56.688 105.732 56.712 105.816 ;
    END
  END a[265]
  PIN a[266]
    DIRECTION INPUT ;
    USE SIGNAL ;
    PORT
      LAYER M5 ;
        RECT  56.784 105.732 56.808 105.816 ;
    END
  END a[266]
  PIN a[267]
    DIRECTION INPUT ;
    USE SIGNAL ;
    PORT
      LAYER M5 ;
        RECT  56.88 105.732 56.904 105.816 ;
    END
  END a[267]
  PIN a[268]
    DIRECTION INPUT ;
    USE SIGNAL ;
    PORT
      LAYER M5 ;
        RECT  56.976 105.732 57 105.816 ;
    END
  END a[268]
  PIN a[269]
    DIRECTION INPUT ;
    USE SIGNAL ;
    PORT
      LAYER M5 ;
        RECT  57.072 105.732 57.096 105.816 ;
    END
  END a[269]
  PIN a[26]
    DIRECTION INPUT ;
    USE SIGNAL ;
    PORT
      LAYER M3 ;
        RECT  59.94 105.779 59.958 105.816 ;
    END
  END a[26]
  PIN a[270]
    DIRECTION INPUT ;
    USE SIGNAL ;
    PORT
      LAYER M5 ;
        RECT  57.168 105.732 57.192 105.816 ;
    END
  END a[270]
  PIN a[271]
    DIRECTION INPUT ;
    USE SIGNAL ;
    PORT
      LAYER M5 ;
        RECT  57.264 105.732 57.288 105.816 ;
    END
  END a[271]
  PIN a[272]
    DIRECTION INPUT ;
    USE SIGNAL ;
    PORT
      LAYER M5 ;
        RECT  57.36 105.732 57.384 105.816 ;
    END
  END a[272]
  PIN a[273]
    DIRECTION INPUT ;
    USE SIGNAL ;
    PORT
      LAYER M5 ;
        RECT  57.456 105.732 57.48 105.816 ;
    END
  END a[273]
  PIN a[274]
    DIRECTION INPUT ;
    USE SIGNAL ;
    PORT
      LAYER M5 ;
        RECT  57.552 105.732 57.576 105.816 ;
    END
  END a[274]
  PIN a[275]
    DIRECTION INPUT ;
    USE SIGNAL ;
    PORT
      LAYER M5 ;
        RECT  57.648 105.732 57.672 105.816 ;
    END
  END a[275]
  PIN a[276]
    DIRECTION INPUT ;
    USE SIGNAL ;
    PORT
      LAYER M5 ;
        RECT  57.744 105.732 57.768 105.816 ;
    END
  END a[276]
  PIN a[277]
    DIRECTION INPUT ;
    USE SIGNAL ;
    PORT
      LAYER M5 ;
        RECT  57.84 105.732 57.864 105.816 ;
    END
  END a[277]
  PIN a[278]
    DIRECTION INPUT ;
    USE SIGNAL ;
    PORT
      LAYER M5 ;
        RECT  57.936 105.732 57.96 105.816 ;
    END
  END a[278]
  PIN a[279]
    DIRECTION INPUT ;
    USE SIGNAL ;
    PORT
      LAYER M5 ;
        RECT  58.032 105.732 58.056 105.816 ;
    END
  END a[279]
  PIN a[27]
    DIRECTION INPUT ;
    USE SIGNAL ;
    PORT
      LAYER M3 ;
        RECT  60.012 105.779 60.03 105.816 ;
    END
  END a[27]
  PIN a[280]
    DIRECTION INPUT ;
    USE SIGNAL ;
    PORT
      LAYER M5 ;
        RECT  58.128 105.732 58.152 105.816 ;
    END
  END a[280]
  PIN a[281]
    DIRECTION INPUT ;
    USE SIGNAL ;
    PORT
      LAYER M5 ;
        RECT  58.224 105.732 58.248 105.816 ;
    END
  END a[281]
  PIN a[282]
    DIRECTION INPUT ;
    USE SIGNAL ;
    PORT
      LAYER M5 ;
        RECT  58.32 105.732 58.344 105.816 ;
    END
  END a[282]
  PIN a[283]
    DIRECTION INPUT ;
    USE SIGNAL ;
    PORT
      LAYER M5 ;
        RECT  58.416 105.732 58.44 105.816 ;
    END
  END a[283]
  PIN a[284]
    DIRECTION INPUT ;
    USE SIGNAL ;
    PORT
      LAYER M5 ;
        RECT  58.512 105.732 58.536 105.816 ;
    END
  END a[284]
  PIN a[285]
    DIRECTION INPUT ;
    USE SIGNAL ;
    PORT
      LAYER M5 ;
        RECT  58.608 105.732 58.632 105.816 ;
    END
  END a[285]
  PIN a[286]
    DIRECTION INPUT ;
    USE SIGNAL ;
    PORT
      LAYER M5 ;
        RECT  58.704 105.732 58.728 105.816 ;
    END
  END a[286]
  PIN a[287]
    DIRECTION INPUT ;
    USE SIGNAL ;
    PORT
      LAYER M5 ;
        RECT  58.8 105.732 58.824 105.816 ;
    END
  END a[287]
  PIN a[288]
    DIRECTION INPUT ;
    USE SIGNAL ;
    PORT
      LAYER M5 ;
        RECT  58.896 105.732 58.92 105.816 ;
    END
  END a[288]
  PIN a[289]
    DIRECTION INPUT ;
    USE SIGNAL ;
    PORT
      LAYER M5 ;
        RECT  58.992 105.732 59.016 105.816 ;
    END
  END a[289]
  PIN a[28]
    DIRECTION INPUT ;
    USE SIGNAL ;
    PORT
      LAYER M3 ;
        RECT  60.084 105.779 60.102 105.816 ;
    END
  END a[28]
  PIN a[290]
    DIRECTION INPUT ;
    USE SIGNAL ;
    PORT
      LAYER M5 ;
        RECT  59.088 105.732 59.112 105.816 ;
    END
  END a[290]
  PIN a[291]
    DIRECTION INPUT ;
    USE SIGNAL ;
    PORT
      LAYER M5 ;
        RECT  59.184 105.732 59.208 105.816 ;
    END
  END a[291]
  PIN a[292]
    DIRECTION INPUT ;
    USE SIGNAL ;
    PORT
      LAYER M5 ;
        RECT  59.28 105.732 59.304 105.816 ;
    END
  END a[292]
  PIN a[293]
    DIRECTION INPUT ;
    USE SIGNAL ;
    PORT
      LAYER M5 ;
        RECT  59.376 105.732 59.4 105.816 ;
    END
  END a[293]
  PIN a[294]
    DIRECTION INPUT ;
    USE SIGNAL ;
    PORT
      LAYER M5 ;
        RECT  59.472 105.732 59.496 105.816 ;
    END
  END a[294]
  PIN a[295]
    DIRECTION INPUT ;
    USE SIGNAL ;
    PORT
      LAYER M5 ;
        RECT  59.568 105.732 59.592 105.816 ;
    END
  END a[295]
  PIN a[296]
    DIRECTION INPUT ;
    USE SIGNAL ;
    PORT
      LAYER M5 ;
        RECT  59.664 105.732 59.688 105.816 ;
    END
  END a[296]
  PIN a[297]
    DIRECTION INPUT ;
    USE SIGNAL ;
    PORT
      LAYER M5 ;
        RECT  59.76 105.732 59.784 105.816 ;
    END
  END a[297]
  PIN a[298]
    DIRECTION INPUT ;
    USE SIGNAL ;
    PORT
      LAYER M5 ;
        RECT  59.856 105.732 59.88 105.816 ;
    END
  END a[298]
  PIN a[299]
    DIRECTION INPUT ;
    USE SIGNAL ;
    PORT
      LAYER M5 ;
        RECT  59.952 105.732 59.976 105.816 ;
    END
  END a[299]
  PIN a[29]
    DIRECTION INPUT ;
    USE SIGNAL ;
    PORT
      LAYER M3 ;
        RECT  60.156 105.779 60.174 105.816 ;
    END
  END a[29]
  PIN a[2]
    DIRECTION INPUT ;
    USE SIGNAL ;
    PORT
      LAYER M3 ;
        RECT  58.212 105.779 58.23 105.816 ;
    END
  END a[2]
  PIN a[300]
    DIRECTION INPUT ;
    USE SIGNAL ;
    PORT
      LAYER M5 ;
        RECT  60.048 105.732 60.072 105.816 ;
    END
  END a[300]
  PIN a[301]
    DIRECTION INPUT ;
    USE SIGNAL ;
    PORT
      LAYER M5 ;
        RECT  60.144 105.732 60.168 105.816 ;
    END
  END a[301]
  PIN a[302]
    DIRECTION INPUT ;
    USE SIGNAL ;
    PORT
      LAYER M5 ;
        RECT  60.24 105.732 60.264 105.816 ;
    END
  END a[302]
  PIN a[303]
    DIRECTION INPUT ;
    USE SIGNAL ;
    PORT
      LAYER M5 ;
        RECT  60.336 105.732 60.36 105.816 ;
    END
  END a[303]
  PIN a[304]
    DIRECTION INPUT ;
    USE SIGNAL ;
    PORT
      LAYER M5 ;
        RECT  60.432 105.732 60.456 105.816 ;
    END
  END a[304]
  PIN a[305]
    DIRECTION INPUT ;
    USE SIGNAL ;
    PORT
      LAYER M5 ;
        RECT  60.528 105.732 60.552 105.816 ;
    END
  END a[305]
  PIN a[306]
    DIRECTION INPUT ;
    USE SIGNAL ;
    PORT
      LAYER M5 ;
        RECT  60.624 105.732 60.648 105.816 ;
    END
  END a[306]
  PIN a[307]
    DIRECTION INPUT ;
    USE SIGNAL ;
    PORT
      LAYER M5 ;
        RECT  60.72 105.732 60.744 105.816 ;
    END
  END a[307]
  PIN a[308]
    DIRECTION INPUT ;
    USE SIGNAL ;
    PORT
      LAYER M5 ;
        RECT  60.816 105.732 60.84 105.816 ;
    END
  END a[308]
  PIN a[309]
    DIRECTION INPUT ;
    USE SIGNAL ;
    PORT
      LAYER M5 ;
        RECT  60.912 105.732 60.936 105.816 ;
    END
  END a[309]
  PIN a[30]
    DIRECTION INPUT ;
    USE SIGNAL ;
    PORT
      LAYER M3 ;
        RECT  60.228 105.779 60.246 105.816 ;
    END
  END a[30]
  PIN a[310]
    DIRECTION INPUT ;
    USE SIGNAL ;
    PORT
      LAYER M5 ;
        RECT  61.008 105.732 61.032 105.816 ;
    END
  END a[310]
  PIN a[311]
    DIRECTION INPUT ;
    USE SIGNAL ;
    PORT
      LAYER M5 ;
        RECT  61.104 105.732 61.128 105.816 ;
    END
  END a[311]
  PIN a[312]
    DIRECTION INPUT ;
    USE SIGNAL ;
    PORT
      LAYER M5 ;
        RECT  61.2 105.732 61.224 105.816 ;
    END
  END a[312]
  PIN a[313]
    DIRECTION INPUT ;
    USE SIGNAL ;
    PORT
      LAYER M5 ;
        RECT  61.296 105.732 61.32 105.816 ;
    END
  END a[313]
  PIN a[314]
    DIRECTION INPUT ;
    USE SIGNAL ;
    PORT
      LAYER M5 ;
        RECT  61.392 105.732 61.416 105.816 ;
    END
  END a[314]
  PIN a[315]
    DIRECTION INPUT ;
    USE SIGNAL ;
    PORT
      LAYER M5 ;
        RECT  61.488 105.732 61.512 105.816 ;
    END
  END a[315]
  PIN a[316]
    DIRECTION INPUT ;
    USE SIGNAL ;
    PORT
      LAYER M5 ;
        RECT  61.584 105.732 61.608 105.816 ;
    END
  END a[316]
  PIN a[317]
    DIRECTION INPUT ;
    USE SIGNAL ;
    PORT
      LAYER M5 ;
        RECT  61.68 105.732 61.704 105.816 ;
    END
  END a[317]
  PIN a[318]
    DIRECTION INPUT ;
    USE SIGNAL ;
    PORT
      LAYER M5 ;
        RECT  61.776 105.732 61.8 105.816 ;
    END
  END a[318]
  PIN a[319]
    DIRECTION INPUT ;
    USE SIGNAL ;
    PORT
      LAYER M5 ;
        RECT  61.872 105.732 61.896 105.816 ;
    END
  END a[319]
  PIN a[31]
    DIRECTION INPUT ;
    USE SIGNAL ;
    PORT
      LAYER M3 ;
        RECT  60.3 105.779 60.318 105.816 ;
    END
  END a[31]
  PIN a[320]
    DIRECTION INPUT ;
    USE SIGNAL ;
    PORT
      LAYER M5 ;
        RECT  61.968 105.732 61.992 105.816 ;
    END
  END a[320]
  PIN a[321]
    DIRECTION INPUT ;
    USE SIGNAL ;
    PORT
      LAYER M5 ;
        RECT  62.064 105.732 62.088 105.816 ;
    END
  END a[321]
  PIN a[322]
    DIRECTION INPUT ;
    USE SIGNAL ;
    PORT
      LAYER M5 ;
        RECT  62.16 105.732 62.184 105.816 ;
    END
  END a[322]
  PIN a[323]
    DIRECTION INPUT ;
    USE SIGNAL ;
    PORT
      LAYER M5 ;
        RECT  62.256 105.732 62.28 105.816 ;
    END
  END a[323]
  PIN a[324]
    DIRECTION INPUT ;
    USE SIGNAL ;
    PORT
      LAYER M5 ;
        RECT  62.352 105.732 62.376 105.816 ;
    END
  END a[324]
  PIN a[325]
    DIRECTION INPUT ;
    USE SIGNAL ;
    PORT
      LAYER M5 ;
        RECT  62.448 105.732 62.472 105.816 ;
    END
  END a[325]
  PIN a[326]
    DIRECTION INPUT ;
    USE SIGNAL ;
    PORT
      LAYER M5 ;
        RECT  62.544 105.732 62.568 105.816 ;
    END
  END a[326]
  PIN a[327]
    DIRECTION INPUT ;
    USE SIGNAL ;
    PORT
      LAYER M5 ;
        RECT  62.64 105.732 62.664 105.816 ;
    END
  END a[327]
  PIN a[328]
    DIRECTION INPUT ;
    USE SIGNAL ;
    PORT
      LAYER M5 ;
        RECT  62.736 105.732 62.76 105.816 ;
    END
  END a[328]
  PIN a[329]
    DIRECTION INPUT ;
    USE SIGNAL ;
    PORT
      LAYER M5 ;
        RECT  62.832 105.732 62.856 105.816 ;
    END
  END a[329]
  PIN a[32]
    DIRECTION INPUT ;
    USE SIGNAL ;
    PORT
      LAYER M3 ;
        RECT  55.764 105.779 55.782 105.816 ;
    END
  END a[32]
  PIN a[330]
    DIRECTION INPUT ;
    USE SIGNAL ;
    PORT
      LAYER M5 ;
        RECT  62.928 105.732 62.952 105.816 ;
    END
  END a[330]
  PIN a[331]
    DIRECTION INPUT ;
    USE SIGNAL ;
    PORT
      LAYER M5 ;
        RECT  63.024 105.732 63.048 105.816 ;
    END
  END a[331]
  PIN a[332]
    DIRECTION INPUT ;
    USE SIGNAL ;
    PORT
      LAYER M5 ;
        RECT  63.12 105.732 63.144 105.816 ;
    END
  END a[332]
  PIN a[333]
    DIRECTION INPUT ;
    USE SIGNAL ;
    PORT
      LAYER M5 ;
        RECT  63.216 105.732 63.24 105.816 ;
    END
  END a[333]
  PIN a[334]
    DIRECTION INPUT ;
    USE SIGNAL ;
    PORT
      LAYER M5 ;
        RECT  63.312 105.732 63.336 105.816 ;
    END
  END a[334]
  PIN a[335]
    DIRECTION INPUT ;
    USE SIGNAL ;
    PORT
      LAYER M5 ;
        RECT  63.408 105.732 63.432 105.816 ;
    END
  END a[335]
  PIN a[336]
    DIRECTION INPUT ;
    USE SIGNAL ;
    PORT
      LAYER M5 ;
        RECT  63.504 105.732 63.528 105.816 ;
    END
  END a[336]
  PIN a[337]
    DIRECTION INPUT ;
    USE SIGNAL ;
    PORT
      LAYER M5 ;
        RECT  63.6 105.732 63.624 105.816 ;
    END
  END a[337]
  PIN a[338]
    DIRECTION INPUT ;
    USE SIGNAL ;
    PORT
      LAYER M5 ;
        RECT  63.696 105.732 63.72 105.816 ;
    END
  END a[338]
  PIN a[339]
    DIRECTION INPUT ;
    USE SIGNAL ;
    PORT
      LAYER M5 ;
        RECT  63.792 105.732 63.816 105.816 ;
    END
  END a[339]
  PIN a[33]
    DIRECTION INPUT ;
    USE SIGNAL ;
    PORT
      LAYER M3 ;
        RECT  55.836 105.779 55.854 105.816 ;
    END
  END a[33]
  PIN a[340]
    DIRECTION INPUT ;
    USE SIGNAL ;
    PORT
      LAYER M5 ;
        RECT  63.888 105.732 63.912 105.816 ;
    END
  END a[340]
  PIN a[341]
    DIRECTION INPUT ;
    USE SIGNAL ;
    PORT
      LAYER M5 ;
        RECT  63.984 105.732 64.008 105.816 ;
    END
  END a[341]
  PIN a[342]
    DIRECTION INPUT ;
    USE SIGNAL ;
    PORT
      LAYER M5 ;
        RECT  64.08 105.732 64.104 105.816 ;
    END
  END a[342]
  PIN a[343]
    DIRECTION INPUT ;
    USE SIGNAL ;
    PORT
      LAYER M5 ;
        RECT  64.176 105.732 64.2 105.816 ;
    END
  END a[343]
  PIN a[344]
    DIRECTION INPUT ;
    USE SIGNAL ;
    PORT
      LAYER M5 ;
        RECT  64.272 105.732 64.296 105.816 ;
    END
  END a[344]
  PIN a[345]
    DIRECTION INPUT ;
    USE SIGNAL ;
    PORT
      LAYER M5 ;
        RECT  64.368 105.732 64.392 105.816 ;
    END
  END a[345]
  PIN a[346]
    DIRECTION INPUT ;
    USE SIGNAL ;
    PORT
      LAYER M5 ;
        RECT  64.464 105.732 64.488 105.816 ;
    END
  END a[346]
  PIN a[347]
    DIRECTION INPUT ;
    USE SIGNAL ;
    PORT
      LAYER M5 ;
        RECT  64.56 105.732 64.584 105.816 ;
    END
  END a[347]
  PIN a[348]
    DIRECTION INPUT ;
    USE SIGNAL ;
    PORT
      LAYER M5 ;
        RECT  64.656 105.732 64.68 105.816 ;
    END
  END a[348]
  PIN a[349]
    DIRECTION INPUT ;
    USE SIGNAL ;
    PORT
      LAYER M5 ;
        RECT  64.752 105.732 64.776 105.816 ;
    END
  END a[349]
  PIN a[34]
    DIRECTION INPUT ;
    USE SIGNAL ;
    PORT
      LAYER M3 ;
        RECT  55.908 105.779 55.926 105.816 ;
    END
  END a[34]
  PIN a[350]
    DIRECTION INPUT ;
    USE SIGNAL ;
    PORT
      LAYER M5 ;
        RECT  64.848 105.732 64.872 105.816 ;
    END
  END a[350]
  PIN a[351]
    DIRECTION INPUT ;
    USE SIGNAL ;
    PORT
      LAYER M5 ;
        RECT  64.944 105.732 64.968 105.816 ;
    END
  END a[351]
  PIN a[352]
    DIRECTION INPUT ;
    USE SIGNAL ;
    PORT
      LAYER M5 ;
        RECT  52.752 105.732 52.776 105.816 ;
    END
  END a[352]
  PIN a[353]
    DIRECTION INPUT ;
    USE SIGNAL ;
    PORT
      LAYER M5 ;
        RECT  52.848 105.732 52.872 105.816 ;
    END
  END a[353]
  PIN a[354]
    DIRECTION INPUT ;
    USE SIGNAL ;
    PORT
      LAYER M5 ;
        RECT  52.944 105.732 52.968 105.816 ;
    END
  END a[354]
  PIN a[355]
    DIRECTION INPUT ;
    USE SIGNAL ;
    PORT
      LAYER M5 ;
        RECT  53.04 105.732 53.064 105.816 ;
    END
  END a[355]
  PIN a[356]
    DIRECTION INPUT ;
    USE SIGNAL ;
    PORT
      LAYER M5 ;
        RECT  53.136 105.732 53.16 105.816 ;
    END
  END a[356]
  PIN a[357]
    DIRECTION INPUT ;
    USE SIGNAL ;
    PORT
      LAYER M5 ;
        RECT  53.232 105.732 53.256 105.816 ;
    END
  END a[357]
  PIN a[358]
    DIRECTION INPUT ;
    USE SIGNAL ;
    PORT
      LAYER M5 ;
        RECT  53.328 105.732 53.352 105.816 ;
    END
  END a[358]
  PIN a[359]
    DIRECTION INPUT ;
    USE SIGNAL ;
    PORT
      LAYER M5 ;
        RECT  53.424 105.732 53.448 105.816 ;
    END
  END a[359]
  PIN a[35]
    DIRECTION INPUT ;
    USE SIGNAL ;
    PORT
      LAYER M3 ;
        RECT  55.98 105.779 55.998 105.816 ;
    END
  END a[35]
  PIN a[360]
    DIRECTION INPUT ;
    USE SIGNAL ;
    PORT
      LAYER M5 ;
        RECT  53.52 105.732 53.544 105.816 ;
    END
  END a[360]
  PIN a[361]
    DIRECTION INPUT ;
    USE SIGNAL ;
    PORT
      LAYER M5 ;
        RECT  53.616 105.732 53.64 105.816 ;
    END
  END a[361]
  PIN a[362]
    DIRECTION INPUT ;
    USE SIGNAL ;
    PORT
      LAYER M5 ;
        RECT  53.712 105.732 53.736 105.816 ;
    END
  END a[362]
  PIN a[363]
    DIRECTION INPUT ;
    USE SIGNAL ;
    PORT
      LAYER M5 ;
        RECT  53.808 105.732 53.832 105.816 ;
    END
  END a[363]
  PIN a[364]
    DIRECTION INPUT ;
    USE SIGNAL ;
    PORT
      LAYER M5 ;
        RECT  53.904 105.732 53.928 105.816 ;
    END
  END a[364]
  PIN a[365]
    DIRECTION INPUT ;
    USE SIGNAL ;
    PORT
      LAYER M5 ;
        RECT  54 105.732 54.024 105.816 ;
    END
  END a[365]
  PIN a[366]
    DIRECTION INPUT ;
    USE SIGNAL ;
    PORT
      LAYER M5 ;
        RECT  54.096 105.732 54.12 105.816 ;
    END
  END a[366]
  PIN a[367]
    DIRECTION INPUT ;
    USE SIGNAL ;
    PORT
      LAYER M5 ;
        RECT  54.192 105.732 54.216 105.816 ;
    END
  END a[367]
  PIN a[368]
    DIRECTION INPUT ;
    USE SIGNAL ;
    PORT
      LAYER M5 ;
        RECT  54.288 105.732 54.312 105.816 ;
    END
  END a[368]
  PIN a[369]
    DIRECTION INPUT ;
    USE SIGNAL ;
    PORT
      LAYER M5 ;
        RECT  54.384 105.732 54.408 105.816 ;
    END
  END a[369]
  PIN a[36]
    DIRECTION INPUT ;
    USE SIGNAL ;
    PORT
      LAYER M3 ;
        RECT  56.052 105.779 56.07 105.816 ;
    END
  END a[36]
  PIN a[370]
    DIRECTION INPUT ;
    USE SIGNAL ;
    PORT
      LAYER M5 ;
        RECT  54.48 105.732 54.504 105.816 ;
    END
  END a[370]
  PIN a[371]
    DIRECTION INPUT ;
    USE SIGNAL ;
    PORT
      LAYER M5 ;
        RECT  54.576 105.732 54.6 105.816 ;
    END
  END a[371]
  PIN a[372]
    DIRECTION INPUT ;
    USE SIGNAL ;
    PORT
      LAYER M5 ;
        RECT  54.672 105.732 54.696 105.816 ;
    END
  END a[372]
  PIN a[373]
    DIRECTION INPUT ;
    USE SIGNAL ;
    PORT
      LAYER M5 ;
        RECT  54.768 105.732 54.792 105.816 ;
    END
  END a[373]
  PIN a[374]
    DIRECTION INPUT ;
    USE SIGNAL ;
    PORT
      LAYER M5 ;
        RECT  54.864 105.732 54.888 105.816 ;
    END
  END a[374]
  PIN a[375]
    DIRECTION INPUT ;
    USE SIGNAL ;
    PORT
      LAYER M5 ;
        RECT  54.96 105.732 54.984 105.816 ;
    END
  END a[375]
  PIN a[376]
    DIRECTION INPUT ;
    USE SIGNAL ;
    PORT
      LAYER M5 ;
        RECT  55.056 105.732 55.08 105.816 ;
    END
  END a[376]
  PIN a[377]
    DIRECTION INPUT ;
    USE SIGNAL ;
    PORT
      LAYER M5 ;
        RECT  55.152 105.732 55.176 105.816 ;
    END
  END a[377]
  PIN a[378]
    DIRECTION INPUT ;
    USE SIGNAL ;
    PORT
      LAYER M5 ;
        RECT  55.248 105.732 55.272 105.816 ;
    END
  END a[378]
  PIN a[379]
    DIRECTION INPUT ;
    USE SIGNAL ;
    PORT
      LAYER M5 ;
        RECT  55.344 105.732 55.368 105.816 ;
    END
  END a[379]
  PIN a[37]
    DIRECTION INPUT ;
    USE SIGNAL ;
    PORT
      LAYER M3 ;
        RECT  56.124 105.779 56.142 105.816 ;
    END
  END a[37]
  PIN a[380]
    DIRECTION INPUT ;
    USE SIGNAL ;
    PORT
      LAYER M5 ;
        RECT  55.44 105.732 55.464 105.816 ;
    END
  END a[380]
  PIN a[381]
    DIRECTION INPUT ;
    USE SIGNAL ;
    PORT
      LAYER M5 ;
        RECT  55.536 105.732 55.56 105.816 ;
    END
  END a[381]
  PIN a[382]
    DIRECTION INPUT ;
    USE SIGNAL ;
    PORT
      LAYER M5 ;
        RECT  55.632 105.732 55.656 105.816 ;
    END
  END a[382]
  PIN a[383]
    DIRECTION INPUT ;
    USE SIGNAL ;
    PORT
      LAYER M5 ;
        RECT  55.728 105.732 55.752 105.816 ;
    END
  END a[383]
  PIN a[384]
    DIRECTION INPUT ;
    USE SIGNAL ;
    PORT
      LAYER M3 ;
        RECT  36.756 105.779 36.774 105.816 ;
    END
  END a[384]
  PIN a[385]
    DIRECTION INPUT ;
    USE SIGNAL ;
    PORT
      LAYER M3 ;
        RECT  36.828 105.779 36.846 105.816 ;
    END
  END a[385]
  PIN a[386]
    DIRECTION INPUT ;
    USE SIGNAL ;
    PORT
      LAYER M3 ;
        RECT  36.9 105.779 36.918 105.816 ;
    END
  END a[386]
  PIN a[387]
    DIRECTION INPUT ;
    USE SIGNAL ;
    PORT
      LAYER M3 ;
        RECT  36.972 105.779 36.99 105.816 ;
    END
  END a[387]
  PIN a[388]
    DIRECTION INPUT ;
    USE SIGNAL ;
    PORT
      LAYER M3 ;
        RECT  37.044 105.779 37.062 105.816 ;
    END
  END a[388]
  PIN a[389]
    DIRECTION INPUT ;
    USE SIGNAL ;
    PORT
      LAYER M3 ;
        RECT  37.116 105.779 37.134 105.816 ;
    END
  END a[389]
  PIN a[38]
    DIRECTION INPUT ;
    USE SIGNAL ;
    PORT
      LAYER M3 ;
        RECT  56.196 105.779 56.214 105.816 ;
    END
  END a[38]
  PIN a[390]
    DIRECTION INPUT ;
    USE SIGNAL ;
    PORT
      LAYER M3 ;
        RECT  37.188 105.779 37.206 105.816 ;
    END
  END a[390]
  PIN a[391]
    DIRECTION INPUT ;
    USE SIGNAL ;
    PORT
      LAYER M3 ;
        RECT  37.26 105.779 37.278 105.816 ;
    END
  END a[391]
  PIN a[392]
    DIRECTION INPUT ;
    USE SIGNAL ;
    PORT
      LAYER M3 ;
        RECT  37.332 105.779 37.35 105.816 ;
    END
  END a[392]
  PIN a[393]
    DIRECTION INPUT ;
    USE SIGNAL ;
    PORT
      LAYER M3 ;
        RECT  37.404 105.779 37.422 105.816 ;
    END
  END a[393]
  PIN a[394]
    DIRECTION INPUT ;
    USE SIGNAL ;
    PORT
      LAYER M3 ;
        RECT  37.476 105.779 37.494 105.816 ;
    END
  END a[394]
  PIN a[395]
    DIRECTION INPUT ;
    USE SIGNAL ;
    PORT
      LAYER M3 ;
        RECT  37.548 105.779 37.566 105.816 ;
    END
  END a[395]
  PIN a[396]
    DIRECTION INPUT ;
    USE SIGNAL ;
    PORT
      LAYER M3 ;
        RECT  37.62 105.779 37.638 105.816 ;
    END
  END a[396]
  PIN a[397]
    DIRECTION INPUT ;
    USE SIGNAL ;
    PORT
      LAYER M3 ;
        RECT  37.692 105.779 37.71 105.816 ;
    END
  END a[397]
  PIN a[398]
    DIRECTION INPUT ;
    USE SIGNAL ;
    PORT
      LAYER M3 ;
        RECT  37.764 105.779 37.782 105.816 ;
    END
  END a[398]
  PIN a[399]
    DIRECTION INPUT ;
    USE SIGNAL ;
    PORT
      LAYER M3 ;
        RECT  37.836 105.779 37.854 105.816 ;
    END
  END a[399]
  PIN a[39]
    DIRECTION INPUT ;
    USE SIGNAL ;
    PORT
      LAYER M3 ;
        RECT  56.268 105.779 56.286 105.816 ;
    END
  END a[39]
  PIN a[3]
    DIRECTION INPUT ;
    USE SIGNAL ;
    PORT
      LAYER M3 ;
        RECT  58.284 105.779 58.302 105.816 ;
    END
  END a[3]
  PIN a[400]
    DIRECTION INPUT ;
    USE SIGNAL ;
    PORT
      LAYER M3 ;
        RECT  37.908 105.779 37.926 105.816 ;
    END
  END a[400]
  PIN a[401]
    DIRECTION INPUT ;
    USE SIGNAL ;
    PORT
      LAYER M3 ;
        RECT  37.98 105.779 37.998 105.816 ;
    END
  END a[401]
  PIN a[402]
    DIRECTION INPUT ;
    USE SIGNAL ;
    PORT
      LAYER M3 ;
        RECT  38.052 105.779 38.07 105.816 ;
    END
  END a[402]
  PIN a[403]
    DIRECTION INPUT ;
    USE SIGNAL ;
    PORT
      LAYER M3 ;
        RECT  38.124 105.779 38.142 105.816 ;
    END
  END a[403]
  PIN a[404]
    DIRECTION INPUT ;
    USE SIGNAL ;
    PORT
      LAYER M3 ;
        RECT  38.196 105.779 38.214 105.816 ;
    END
  END a[404]
  PIN a[405]
    DIRECTION INPUT ;
    USE SIGNAL ;
    PORT
      LAYER M3 ;
        RECT  38.268 105.779 38.286 105.816 ;
    END
  END a[405]
  PIN a[406]
    DIRECTION INPUT ;
    USE SIGNAL ;
    PORT
      LAYER M3 ;
        RECT  38.34 105.779 38.358 105.816 ;
    END
  END a[406]
  PIN a[407]
    DIRECTION INPUT ;
    USE SIGNAL ;
    PORT
      LAYER M3 ;
        RECT  38.412 105.779 38.43 105.816 ;
    END
  END a[407]
  PIN a[408]
    DIRECTION INPUT ;
    USE SIGNAL ;
    PORT
      LAYER M3 ;
        RECT  38.484 105.779 38.502 105.816 ;
    END
  END a[408]
  PIN a[409]
    DIRECTION INPUT ;
    USE SIGNAL ;
    PORT
      LAYER M3 ;
        RECT  38.556 105.779 38.574 105.816 ;
    END
  END a[409]
  PIN a[40]
    DIRECTION INPUT ;
    USE SIGNAL ;
    PORT
      LAYER M3 ;
        RECT  56.34 105.779 56.358 105.816 ;
    END
  END a[40]
  PIN a[410]
    DIRECTION INPUT ;
    USE SIGNAL ;
    PORT
      LAYER M3 ;
        RECT  38.628 105.779 38.646 105.816 ;
    END
  END a[410]
  PIN a[411]
    DIRECTION INPUT ;
    USE SIGNAL ;
    PORT
      LAYER M3 ;
        RECT  38.7 105.779 38.718 105.816 ;
    END
  END a[411]
  PIN a[412]
    DIRECTION INPUT ;
    USE SIGNAL ;
    PORT
      LAYER M3 ;
        RECT  38.772 105.779 38.79 105.816 ;
    END
  END a[412]
  PIN a[413]
    DIRECTION INPUT ;
    USE SIGNAL ;
    PORT
      LAYER M3 ;
        RECT  38.844 105.779 38.862 105.816 ;
    END
  END a[413]
  PIN a[414]
    DIRECTION INPUT ;
    USE SIGNAL ;
    PORT
      LAYER M3 ;
        RECT  38.916 105.779 38.934 105.816 ;
    END
  END a[414]
  PIN a[415]
    DIRECTION INPUT ;
    USE SIGNAL ;
    PORT
      LAYER M3 ;
        RECT  38.988 105.779 39.006 105.816 ;
    END
  END a[415]
  PIN a[416]
    DIRECTION INPUT ;
    USE SIGNAL ;
    PORT
      LAYER M3 ;
        RECT  34.452 105.779 34.47 105.816 ;
    END
  END a[416]
  PIN a[417]
    DIRECTION INPUT ;
    USE SIGNAL ;
    PORT
      LAYER M3 ;
        RECT  34.524 105.779 34.542 105.816 ;
    END
  END a[417]
  PIN a[418]
    DIRECTION INPUT ;
    USE SIGNAL ;
    PORT
      LAYER M3 ;
        RECT  34.596 105.779 34.614 105.816 ;
    END
  END a[418]
  PIN a[419]
    DIRECTION INPUT ;
    USE SIGNAL ;
    PORT
      LAYER M3 ;
        RECT  34.668 105.779 34.686 105.816 ;
    END
  END a[419]
  PIN a[41]
    DIRECTION INPUT ;
    USE SIGNAL ;
    PORT
      LAYER M3 ;
        RECT  56.412 105.779 56.43 105.816 ;
    END
  END a[41]
  PIN a[420]
    DIRECTION INPUT ;
    USE SIGNAL ;
    PORT
      LAYER M3 ;
        RECT  34.74 105.779 34.758 105.816 ;
    END
  END a[420]
  PIN a[421]
    DIRECTION INPUT ;
    USE SIGNAL ;
    PORT
      LAYER M3 ;
        RECT  34.812 105.779 34.83 105.816 ;
    END
  END a[421]
  PIN a[422]
    DIRECTION INPUT ;
    USE SIGNAL ;
    PORT
      LAYER M3 ;
        RECT  34.884 105.779 34.902 105.816 ;
    END
  END a[422]
  PIN a[423]
    DIRECTION INPUT ;
    USE SIGNAL ;
    PORT
      LAYER M3 ;
        RECT  34.956 105.779 34.974 105.816 ;
    END
  END a[423]
  PIN a[424]
    DIRECTION INPUT ;
    USE SIGNAL ;
    PORT
      LAYER M3 ;
        RECT  35.028 105.779 35.046 105.816 ;
    END
  END a[424]
  PIN a[425]
    DIRECTION INPUT ;
    USE SIGNAL ;
    PORT
      LAYER M3 ;
        RECT  35.1 105.779 35.118 105.816 ;
    END
  END a[425]
  PIN a[426]
    DIRECTION INPUT ;
    USE SIGNAL ;
    PORT
      LAYER M3 ;
        RECT  35.172 105.779 35.19 105.816 ;
    END
  END a[426]
  PIN a[427]
    DIRECTION INPUT ;
    USE SIGNAL ;
    PORT
      LAYER M3 ;
        RECT  35.244 105.779 35.262 105.816 ;
    END
  END a[427]
  PIN a[428]
    DIRECTION INPUT ;
    USE SIGNAL ;
    PORT
      LAYER M3 ;
        RECT  35.316 105.779 35.334 105.816 ;
    END
  END a[428]
  PIN a[429]
    DIRECTION INPUT ;
    USE SIGNAL ;
    PORT
      LAYER M3 ;
        RECT  35.388 105.779 35.406 105.816 ;
    END
  END a[429]
  PIN a[42]
    DIRECTION INPUT ;
    USE SIGNAL ;
    PORT
      LAYER M3 ;
        RECT  56.484 105.779 56.502 105.816 ;
    END
  END a[42]
  PIN a[430]
    DIRECTION INPUT ;
    USE SIGNAL ;
    PORT
      LAYER M3 ;
        RECT  35.46 105.779 35.478 105.816 ;
    END
  END a[430]
  PIN a[431]
    DIRECTION INPUT ;
    USE SIGNAL ;
    PORT
      LAYER M3 ;
        RECT  35.532 105.779 35.55 105.816 ;
    END
  END a[431]
  PIN a[432]
    DIRECTION INPUT ;
    USE SIGNAL ;
    PORT
      LAYER M3 ;
        RECT  35.604 105.779 35.622 105.816 ;
    END
  END a[432]
  PIN a[433]
    DIRECTION INPUT ;
    USE SIGNAL ;
    PORT
      LAYER M3 ;
        RECT  35.676 105.779 35.694 105.816 ;
    END
  END a[433]
  PIN a[434]
    DIRECTION INPUT ;
    USE SIGNAL ;
    PORT
      LAYER M3 ;
        RECT  35.748 105.779 35.766 105.816 ;
    END
  END a[434]
  PIN a[435]
    DIRECTION INPUT ;
    USE SIGNAL ;
    PORT
      LAYER M3 ;
        RECT  35.82 105.779 35.838 105.816 ;
    END
  END a[435]
  PIN a[436]
    DIRECTION INPUT ;
    USE SIGNAL ;
    PORT
      LAYER M3 ;
        RECT  35.892 105.779 35.91 105.816 ;
    END
  END a[436]
  PIN a[437]
    DIRECTION INPUT ;
    USE SIGNAL ;
    PORT
      LAYER M3 ;
        RECT  35.964 105.779 35.982 105.816 ;
    END
  END a[437]
  PIN a[438]
    DIRECTION INPUT ;
    USE SIGNAL ;
    PORT
      LAYER M3 ;
        RECT  36.036 105.779 36.054 105.816 ;
    END
  END a[438]
  PIN a[439]
    DIRECTION INPUT ;
    USE SIGNAL ;
    PORT
      LAYER M3 ;
        RECT  36.108 105.779 36.126 105.816 ;
    END
  END a[439]
  PIN a[43]
    DIRECTION INPUT ;
    USE SIGNAL ;
    PORT
      LAYER M3 ;
        RECT  56.556 105.779 56.574 105.816 ;
    END
  END a[43]
  PIN a[440]
    DIRECTION INPUT ;
    USE SIGNAL ;
    PORT
      LAYER M3 ;
        RECT  36.18 105.779 36.198 105.816 ;
    END
  END a[440]
  PIN a[441]
    DIRECTION INPUT ;
    USE SIGNAL ;
    PORT
      LAYER M3 ;
        RECT  36.252 105.779 36.27 105.816 ;
    END
  END a[441]
  PIN a[442]
    DIRECTION INPUT ;
    USE SIGNAL ;
    PORT
      LAYER M3 ;
        RECT  36.324 105.779 36.342 105.816 ;
    END
  END a[442]
  PIN a[443]
    DIRECTION INPUT ;
    USE SIGNAL ;
    PORT
      LAYER M3 ;
        RECT  36.396 105.779 36.414 105.816 ;
    END
  END a[443]
  PIN a[444]
    DIRECTION INPUT ;
    USE SIGNAL ;
    PORT
      LAYER M3 ;
        RECT  36.468 105.779 36.486 105.816 ;
    END
  END a[444]
  PIN a[445]
    DIRECTION INPUT ;
    USE SIGNAL ;
    PORT
      LAYER M3 ;
        RECT  36.54 105.779 36.558 105.816 ;
    END
  END a[445]
  PIN a[446]
    DIRECTION INPUT ;
    USE SIGNAL ;
    PORT
      LAYER M3 ;
        RECT  36.612 105.779 36.63 105.816 ;
    END
  END a[446]
  PIN a[447]
    DIRECTION INPUT ;
    USE SIGNAL ;
    PORT
      LAYER M3 ;
        RECT  36.684 105.779 36.702 105.816 ;
    END
  END a[447]
  PIN a[448]
    DIRECTION INPUT ;
    USE SIGNAL ;
    PORT
      LAYER M3 ;
        RECT  39.06 105.779 39.078 105.816 ;
    END
  END a[448]
  PIN a[449]
    DIRECTION INPUT ;
    USE SIGNAL ;
    PORT
      LAYER M3 ;
        RECT  39.132 105.779 39.15 105.816 ;
    END
  END a[449]
  PIN a[44]
    DIRECTION INPUT ;
    USE SIGNAL ;
    PORT
      LAYER M3 ;
        RECT  56.628 105.779 56.646 105.816 ;
    END
  END a[44]
  PIN a[450]
    DIRECTION INPUT ;
    USE SIGNAL ;
    PORT
      LAYER M3 ;
        RECT  39.204 105.779 39.222 105.816 ;
    END
  END a[450]
  PIN a[451]
    DIRECTION INPUT ;
    USE SIGNAL ;
    PORT
      LAYER M3 ;
        RECT  39.276 105.779 39.294 105.816 ;
    END
  END a[451]
  PIN a[452]
    DIRECTION INPUT ;
    USE SIGNAL ;
    PORT
      LAYER M3 ;
        RECT  39.348 105.779 39.366 105.816 ;
    END
  END a[452]
  PIN a[453]
    DIRECTION INPUT ;
    USE SIGNAL ;
    PORT
      LAYER M3 ;
        RECT  39.42 105.779 39.438 105.816 ;
    END
  END a[453]
  PIN a[454]
    DIRECTION INPUT ;
    USE SIGNAL ;
    PORT
      LAYER M3 ;
        RECT  39.492 105.779 39.51 105.816 ;
    END
  END a[454]
  PIN a[455]
    DIRECTION INPUT ;
    USE SIGNAL ;
    PORT
      LAYER M3 ;
        RECT  39.564 105.779 39.582 105.816 ;
    END
  END a[455]
  PIN a[456]
    DIRECTION INPUT ;
    USE SIGNAL ;
    PORT
      LAYER M3 ;
        RECT  39.636 105.779 39.654 105.816 ;
    END
  END a[456]
  PIN a[457]
    DIRECTION INPUT ;
    USE SIGNAL ;
    PORT
      LAYER M3 ;
        RECT  39.708 105.779 39.726 105.816 ;
    END
  END a[457]
  PIN a[458]
    DIRECTION INPUT ;
    USE SIGNAL ;
    PORT
      LAYER M3 ;
        RECT  39.78 105.779 39.798 105.816 ;
    END
  END a[458]
  PIN a[459]
    DIRECTION INPUT ;
    USE SIGNAL ;
    PORT
      LAYER M3 ;
        RECT  39.852 105.779 39.87 105.816 ;
    END
  END a[459]
  PIN a[45]
    DIRECTION INPUT ;
    USE SIGNAL ;
    PORT
      LAYER M3 ;
        RECT  56.7 105.779 56.718 105.816 ;
    END
  END a[45]
  PIN a[460]
    DIRECTION INPUT ;
    USE SIGNAL ;
    PORT
      LAYER M3 ;
        RECT  39.924 105.779 39.942 105.816 ;
    END
  END a[460]
  PIN a[461]
    DIRECTION INPUT ;
    USE SIGNAL ;
    PORT
      LAYER M3 ;
        RECT  39.996 105.779 40.014 105.816 ;
    END
  END a[461]
  PIN a[462]
    DIRECTION INPUT ;
    USE SIGNAL ;
    PORT
      LAYER M3 ;
        RECT  40.068 105.779 40.086 105.816 ;
    END
  END a[462]
  PIN a[463]
    DIRECTION INPUT ;
    USE SIGNAL ;
    PORT
      LAYER M3 ;
        RECT  40.14 105.779 40.158 105.816 ;
    END
  END a[463]
  PIN a[464]
    DIRECTION INPUT ;
    USE SIGNAL ;
    PORT
      LAYER M3 ;
        RECT  40.212 105.779 40.23 105.816 ;
    END
  END a[464]
  PIN a[465]
    DIRECTION INPUT ;
    USE SIGNAL ;
    PORT
      LAYER M3 ;
        RECT  40.284 105.779 40.302 105.816 ;
    END
  END a[465]
  PIN a[466]
    DIRECTION INPUT ;
    USE SIGNAL ;
    PORT
      LAYER M3 ;
        RECT  40.356 105.779 40.374 105.816 ;
    END
  END a[466]
  PIN a[467]
    DIRECTION INPUT ;
    USE SIGNAL ;
    PORT
      LAYER M3 ;
        RECT  40.428 105.779 40.446 105.816 ;
    END
  END a[467]
  PIN a[468]
    DIRECTION INPUT ;
    USE SIGNAL ;
    PORT
      LAYER M3 ;
        RECT  40.5 105.779 40.518 105.816 ;
    END
  END a[468]
  PIN a[469]
    DIRECTION INPUT ;
    USE SIGNAL ;
    PORT
      LAYER M3 ;
        RECT  40.572 105.779 40.59 105.816 ;
    END
  END a[469]
  PIN a[46]
    DIRECTION INPUT ;
    USE SIGNAL ;
    PORT
      LAYER M3 ;
        RECT  56.772 105.779 56.79 105.816 ;
    END
  END a[46]
  PIN a[470]
    DIRECTION INPUT ;
    USE SIGNAL ;
    PORT
      LAYER M3 ;
        RECT  40.644 105.779 40.662 105.816 ;
    END
  END a[470]
  PIN a[471]
    DIRECTION INPUT ;
    USE SIGNAL ;
    PORT
      LAYER M3 ;
        RECT  40.716 105.779 40.734 105.816 ;
    END
  END a[471]
  PIN a[472]
    DIRECTION INPUT ;
    USE SIGNAL ;
    PORT
      LAYER M3 ;
        RECT  40.788 105.779 40.806 105.816 ;
    END
  END a[472]
  PIN a[473]
    DIRECTION INPUT ;
    USE SIGNAL ;
    PORT
      LAYER M3 ;
        RECT  40.86 105.779 40.878 105.816 ;
    END
  END a[473]
  PIN a[474]
    DIRECTION INPUT ;
    USE SIGNAL ;
    PORT
      LAYER M3 ;
        RECT  40.932 105.779 40.95 105.816 ;
    END
  END a[474]
  PIN a[475]
    DIRECTION INPUT ;
    USE SIGNAL ;
    PORT
      LAYER M3 ;
        RECT  41.004 105.779 41.022 105.816 ;
    END
  END a[475]
  PIN a[476]
    DIRECTION INPUT ;
    USE SIGNAL ;
    PORT
      LAYER M3 ;
        RECT  41.076 105.779 41.094 105.816 ;
    END
  END a[476]
  PIN a[477]
    DIRECTION INPUT ;
    USE SIGNAL ;
    PORT
      LAYER M3 ;
        RECT  41.148 105.779 41.166 105.816 ;
    END
  END a[477]
  PIN a[478]
    DIRECTION INPUT ;
    USE SIGNAL ;
    PORT
      LAYER M3 ;
        RECT  41.22 105.779 41.238 105.816 ;
    END
  END a[478]
  PIN a[479]
    DIRECTION INPUT ;
    USE SIGNAL ;
    PORT
      LAYER M3 ;
        RECT  41.292 105.779 41.31 105.816 ;
    END
  END a[479]
  PIN a[47]
    DIRECTION INPUT ;
    USE SIGNAL ;
    PORT
      LAYER M3 ;
        RECT  56.844 105.779 56.862 105.816 ;
    END
  END a[47]
  PIN a[480]
    DIRECTION INPUT ;
    USE SIGNAL ;
    PORT
      LAYER M3 ;
        RECT  32.148 105.779 32.166 105.816 ;
    END
  END a[480]
  PIN a[481]
    DIRECTION INPUT ;
    USE SIGNAL ;
    PORT
      LAYER M3 ;
        RECT  32.22 105.779 32.238 105.816 ;
    END
  END a[481]
  PIN a[482]
    DIRECTION INPUT ;
    USE SIGNAL ;
    PORT
      LAYER M3 ;
        RECT  32.292 105.779 32.31 105.816 ;
    END
  END a[482]
  PIN a[483]
    DIRECTION INPUT ;
    USE SIGNAL ;
    PORT
      LAYER M3 ;
        RECT  32.364 105.779 32.382 105.816 ;
    END
  END a[483]
  PIN a[484]
    DIRECTION INPUT ;
    USE SIGNAL ;
    PORT
      LAYER M3 ;
        RECT  32.436 105.779 32.454 105.816 ;
    END
  END a[484]
  PIN a[485]
    DIRECTION INPUT ;
    USE SIGNAL ;
    PORT
      LAYER M3 ;
        RECT  32.508 105.779 32.526 105.816 ;
    END
  END a[485]
  PIN a[486]
    DIRECTION INPUT ;
    USE SIGNAL ;
    PORT
      LAYER M3 ;
        RECT  32.58 105.779 32.598 105.816 ;
    END
  END a[486]
  PIN a[487]
    DIRECTION INPUT ;
    USE SIGNAL ;
    PORT
      LAYER M3 ;
        RECT  32.652 105.779 32.67 105.816 ;
    END
  END a[487]
  PIN a[488]
    DIRECTION INPUT ;
    USE SIGNAL ;
    PORT
      LAYER M3 ;
        RECT  32.724 105.779 32.742 105.816 ;
    END
  END a[488]
  PIN a[489]
    DIRECTION INPUT ;
    USE SIGNAL ;
    PORT
      LAYER M3 ;
        RECT  32.796 105.779 32.814 105.816 ;
    END
  END a[489]
  PIN a[48]
    DIRECTION INPUT ;
    USE SIGNAL ;
    PORT
      LAYER M3 ;
        RECT  56.916 105.779 56.934 105.816 ;
    END
  END a[48]
  PIN a[490]
    DIRECTION INPUT ;
    USE SIGNAL ;
    PORT
      LAYER M3 ;
        RECT  32.868 105.779 32.886 105.816 ;
    END
  END a[490]
  PIN a[491]
    DIRECTION INPUT ;
    USE SIGNAL ;
    PORT
      LAYER M3 ;
        RECT  32.94 105.779 32.958 105.816 ;
    END
  END a[491]
  PIN a[492]
    DIRECTION INPUT ;
    USE SIGNAL ;
    PORT
      LAYER M3 ;
        RECT  33.012 105.779 33.03 105.816 ;
    END
  END a[492]
  PIN a[493]
    DIRECTION INPUT ;
    USE SIGNAL ;
    PORT
      LAYER M3 ;
        RECT  33.084 105.779 33.102 105.816 ;
    END
  END a[493]
  PIN a[494]
    DIRECTION INPUT ;
    USE SIGNAL ;
    PORT
      LAYER M3 ;
        RECT  33.156 105.779 33.174 105.816 ;
    END
  END a[494]
  PIN a[495]
    DIRECTION INPUT ;
    USE SIGNAL ;
    PORT
      LAYER M3 ;
        RECT  33.228 105.779 33.246 105.816 ;
    END
  END a[495]
  PIN a[496]
    DIRECTION INPUT ;
    USE SIGNAL ;
    PORT
      LAYER M3 ;
        RECT  33.3 105.779 33.318 105.816 ;
    END
  END a[496]
  PIN a[497]
    DIRECTION INPUT ;
    USE SIGNAL ;
    PORT
      LAYER M3 ;
        RECT  33.372 105.779 33.39 105.816 ;
    END
  END a[497]
  PIN a[498]
    DIRECTION INPUT ;
    USE SIGNAL ;
    PORT
      LAYER M3 ;
        RECT  33.444 105.779 33.462 105.816 ;
    END
  END a[498]
  PIN a[499]
    DIRECTION INPUT ;
    USE SIGNAL ;
    PORT
      LAYER M3 ;
        RECT  33.516 105.779 33.534 105.816 ;
    END
  END a[499]
  PIN a[49]
    DIRECTION INPUT ;
    USE SIGNAL ;
    PORT
      LAYER M3 ;
        RECT  56.988 105.779 57.006 105.816 ;
    END
  END a[49]
  PIN a[4]
    DIRECTION INPUT ;
    USE SIGNAL ;
    PORT
      LAYER M3 ;
        RECT  58.356 105.779 58.374 105.816 ;
    END
  END a[4]
  PIN a[500]
    DIRECTION INPUT ;
    USE SIGNAL ;
    PORT
      LAYER M3 ;
        RECT  33.588 105.779 33.606 105.816 ;
    END
  END a[500]
  PIN a[501]
    DIRECTION INPUT ;
    USE SIGNAL ;
    PORT
      LAYER M3 ;
        RECT  33.66 105.779 33.678 105.816 ;
    END
  END a[501]
  PIN a[502]
    DIRECTION INPUT ;
    USE SIGNAL ;
    PORT
      LAYER M3 ;
        RECT  33.732 105.779 33.75 105.816 ;
    END
  END a[502]
  PIN a[503]
    DIRECTION INPUT ;
    USE SIGNAL ;
    PORT
      LAYER M3 ;
        RECT  33.804 105.779 33.822 105.816 ;
    END
  END a[503]
  PIN a[504]
    DIRECTION INPUT ;
    USE SIGNAL ;
    PORT
      LAYER M3 ;
        RECT  33.876 105.779 33.894 105.816 ;
    END
  END a[504]
  PIN a[505]
    DIRECTION INPUT ;
    USE SIGNAL ;
    PORT
      LAYER M3 ;
        RECT  33.948 105.779 33.966 105.816 ;
    END
  END a[505]
  PIN a[506]
    DIRECTION INPUT ;
    USE SIGNAL ;
    PORT
      LAYER M3 ;
        RECT  34.02 105.779 34.038 105.816 ;
    END
  END a[506]
  PIN a[507]
    DIRECTION INPUT ;
    USE SIGNAL ;
    PORT
      LAYER M3 ;
        RECT  34.092 105.779 34.11 105.816 ;
    END
  END a[507]
  PIN a[508]
    DIRECTION INPUT ;
    USE SIGNAL ;
    PORT
      LAYER M3 ;
        RECT  34.164 105.779 34.182 105.816 ;
    END
  END a[508]
  PIN a[509]
    DIRECTION INPUT ;
    USE SIGNAL ;
    PORT
      LAYER M3 ;
        RECT  34.236 105.779 34.254 105.816 ;
    END
  END a[509]
  PIN a[50]
    DIRECTION INPUT ;
    USE SIGNAL ;
    PORT
      LAYER M3 ;
        RECT  57.06 105.779 57.078 105.816 ;
    END
  END a[50]
  PIN a[510]
    DIRECTION INPUT ;
    USE SIGNAL ;
    PORT
      LAYER M3 ;
        RECT  34.308 105.779 34.326 105.816 ;
    END
  END a[510]
  PIN a[511]
    DIRECTION INPUT ;
    USE SIGNAL ;
    PORT
      LAYER M3 ;
        RECT  34.38 105.779 34.398 105.816 ;
    END
  END a[511]
  PIN a[512]
    DIRECTION INPUT ;
    USE SIGNAL ;
    PORT
      LAYER M3 ;
        RECT  43.668 105.779 43.686 105.816 ;
    END
  END a[512]
  PIN a[513]
    DIRECTION INPUT ;
    USE SIGNAL ;
    PORT
      LAYER M3 ;
        RECT  43.74 105.779 43.758 105.816 ;
    END
  END a[513]
  PIN a[514]
    DIRECTION INPUT ;
    USE SIGNAL ;
    PORT
      LAYER M3 ;
        RECT  43.812 105.779 43.83 105.816 ;
    END
  END a[514]
  PIN a[515]
    DIRECTION INPUT ;
    USE SIGNAL ;
    PORT
      LAYER M3 ;
        RECT  43.884 105.779 43.902 105.816 ;
    END
  END a[515]
  PIN a[516]
    DIRECTION INPUT ;
    USE SIGNAL ;
    PORT
      LAYER M3 ;
        RECT  43.956 105.779 43.974 105.816 ;
    END
  END a[516]
  PIN a[517]
    DIRECTION INPUT ;
    USE SIGNAL ;
    PORT
      LAYER M3 ;
        RECT  44.028 105.779 44.046 105.816 ;
    END
  END a[517]
  PIN a[518]
    DIRECTION INPUT ;
    USE SIGNAL ;
    PORT
      LAYER M3 ;
        RECT  44.1 105.779 44.118 105.816 ;
    END
  END a[518]
  PIN a[519]
    DIRECTION INPUT ;
    USE SIGNAL ;
    PORT
      LAYER M3 ;
        RECT  44.172 105.779 44.19 105.816 ;
    END
  END a[519]
  PIN a[51]
    DIRECTION INPUT ;
    USE SIGNAL ;
    PORT
      LAYER M3 ;
        RECT  57.132 105.779 57.15 105.816 ;
    END
  END a[51]
  PIN a[520]
    DIRECTION INPUT ;
    USE SIGNAL ;
    PORT
      LAYER M3 ;
        RECT  44.244 105.779 44.262 105.816 ;
    END
  END a[520]
  PIN a[521]
    DIRECTION INPUT ;
    USE SIGNAL ;
    PORT
      LAYER M3 ;
        RECT  44.316 105.779 44.334 105.816 ;
    END
  END a[521]
  PIN a[522]
    DIRECTION INPUT ;
    USE SIGNAL ;
    PORT
      LAYER M3 ;
        RECT  44.388 105.779 44.406 105.816 ;
    END
  END a[522]
  PIN a[523]
    DIRECTION INPUT ;
    USE SIGNAL ;
    PORT
      LAYER M3 ;
        RECT  44.46 105.779 44.478 105.816 ;
    END
  END a[523]
  PIN a[524]
    DIRECTION INPUT ;
    USE SIGNAL ;
    PORT
      LAYER M3 ;
        RECT  44.532 105.779 44.55 105.816 ;
    END
  END a[524]
  PIN a[525]
    DIRECTION INPUT ;
    USE SIGNAL ;
    PORT
      LAYER M3 ;
        RECT  44.604 105.779 44.622 105.816 ;
    END
  END a[525]
  PIN a[526]
    DIRECTION INPUT ;
    USE SIGNAL ;
    PORT
      LAYER M3 ;
        RECT  44.676 105.779 44.694 105.816 ;
    END
  END a[526]
  PIN a[527]
    DIRECTION INPUT ;
    USE SIGNAL ;
    PORT
      LAYER M3 ;
        RECT  44.748 105.779 44.766 105.816 ;
    END
  END a[527]
  PIN a[528]
    DIRECTION INPUT ;
    USE SIGNAL ;
    PORT
      LAYER M3 ;
        RECT  44.82 105.779 44.838 105.816 ;
    END
  END a[528]
  PIN a[529]
    DIRECTION INPUT ;
    USE SIGNAL ;
    PORT
      LAYER M3 ;
        RECT  44.892 105.779 44.91 105.816 ;
    END
  END a[529]
  PIN a[52]
    DIRECTION INPUT ;
    USE SIGNAL ;
    PORT
      LAYER M3 ;
        RECT  57.204 105.779 57.222 105.816 ;
    END
  END a[52]
  PIN a[530]
    DIRECTION INPUT ;
    USE SIGNAL ;
    PORT
      LAYER M3 ;
        RECT  44.964 105.779 44.982 105.816 ;
    END
  END a[530]
  PIN a[531]
    DIRECTION INPUT ;
    USE SIGNAL ;
    PORT
      LAYER M3 ;
        RECT  45.036 105.779 45.054 105.816 ;
    END
  END a[531]
  PIN a[532]
    DIRECTION INPUT ;
    USE SIGNAL ;
    PORT
      LAYER M3 ;
        RECT  45.108 105.779 45.126 105.816 ;
    END
  END a[532]
  PIN a[533]
    DIRECTION INPUT ;
    USE SIGNAL ;
    PORT
      LAYER M3 ;
        RECT  45.18 105.779 45.198 105.816 ;
    END
  END a[533]
  PIN a[534]
    DIRECTION INPUT ;
    USE SIGNAL ;
    PORT
      LAYER M3 ;
        RECT  45.252 105.779 45.27 105.816 ;
    END
  END a[534]
  PIN a[535]
    DIRECTION INPUT ;
    USE SIGNAL ;
    PORT
      LAYER M3 ;
        RECT  45.324 105.779 45.342 105.816 ;
    END
  END a[535]
  PIN a[536]
    DIRECTION INPUT ;
    USE SIGNAL ;
    PORT
      LAYER M3 ;
        RECT  45.396 105.779 45.414 105.816 ;
    END
  END a[536]
  PIN a[537]
    DIRECTION INPUT ;
    USE SIGNAL ;
    PORT
      LAYER M3 ;
        RECT  45.468 105.779 45.486 105.816 ;
    END
  END a[537]
  PIN a[538]
    DIRECTION INPUT ;
    USE SIGNAL ;
    PORT
      LAYER M3 ;
        RECT  45.54 105.779 45.558 105.816 ;
    END
  END a[538]
  PIN a[539]
    DIRECTION INPUT ;
    USE SIGNAL ;
    PORT
      LAYER M3 ;
        RECT  45.612 105.779 45.63 105.816 ;
    END
  END a[539]
  PIN a[53]
    DIRECTION INPUT ;
    USE SIGNAL ;
    PORT
      LAYER M3 ;
        RECT  57.276 105.779 57.294 105.816 ;
    END
  END a[53]
  PIN a[540]
    DIRECTION INPUT ;
    USE SIGNAL ;
    PORT
      LAYER M3 ;
        RECT  45.684 105.779 45.702 105.816 ;
    END
  END a[540]
  PIN a[541]
    DIRECTION INPUT ;
    USE SIGNAL ;
    PORT
      LAYER M3 ;
        RECT  45.756 105.779 45.774 105.816 ;
    END
  END a[541]
  PIN a[542]
    DIRECTION INPUT ;
    USE SIGNAL ;
    PORT
      LAYER M3 ;
        RECT  45.828 105.779 45.846 105.816 ;
    END
  END a[542]
  PIN a[543]
    DIRECTION INPUT ;
    USE SIGNAL ;
    PORT
      LAYER M3 ;
        RECT  45.9 105.779 45.918 105.816 ;
    END
  END a[543]
  PIN a[544]
    DIRECTION INPUT ;
    USE SIGNAL ;
    PORT
      LAYER M3 ;
        RECT  41.364 105.779 41.382 105.816 ;
    END
  END a[544]
  PIN a[545]
    DIRECTION INPUT ;
    USE SIGNAL ;
    PORT
      LAYER M3 ;
        RECT  41.436 105.779 41.454 105.816 ;
    END
  END a[545]
  PIN a[546]
    DIRECTION INPUT ;
    USE SIGNAL ;
    PORT
      LAYER M3 ;
        RECT  41.508 105.779 41.526 105.816 ;
    END
  END a[546]
  PIN a[547]
    DIRECTION INPUT ;
    USE SIGNAL ;
    PORT
      LAYER M3 ;
        RECT  41.58 105.779 41.598 105.816 ;
    END
  END a[547]
  PIN a[548]
    DIRECTION INPUT ;
    USE SIGNAL ;
    PORT
      LAYER M3 ;
        RECT  41.652 105.779 41.67 105.816 ;
    END
  END a[548]
  PIN a[549]
    DIRECTION INPUT ;
    USE SIGNAL ;
    PORT
      LAYER M3 ;
        RECT  41.724 105.779 41.742 105.816 ;
    END
  END a[549]
  PIN a[54]
    DIRECTION INPUT ;
    USE SIGNAL ;
    PORT
      LAYER M3 ;
        RECT  57.348 105.779 57.366 105.816 ;
    END
  END a[54]
  PIN a[550]
    DIRECTION INPUT ;
    USE SIGNAL ;
    PORT
      LAYER M3 ;
        RECT  41.796 105.779 41.814 105.816 ;
    END
  END a[550]
  PIN a[551]
    DIRECTION INPUT ;
    USE SIGNAL ;
    PORT
      LAYER M3 ;
        RECT  41.868 105.779 41.886 105.816 ;
    END
  END a[551]
  PIN a[552]
    DIRECTION INPUT ;
    USE SIGNAL ;
    PORT
      LAYER M3 ;
        RECT  41.94 105.779 41.958 105.816 ;
    END
  END a[552]
  PIN a[553]
    DIRECTION INPUT ;
    USE SIGNAL ;
    PORT
      LAYER M3 ;
        RECT  42.012 105.779 42.03 105.816 ;
    END
  END a[553]
  PIN a[554]
    DIRECTION INPUT ;
    USE SIGNAL ;
    PORT
      LAYER M3 ;
        RECT  42.084 105.779 42.102 105.816 ;
    END
  END a[554]
  PIN a[555]
    DIRECTION INPUT ;
    USE SIGNAL ;
    PORT
      LAYER M3 ;
        RECT  42.156 105.779 42.174 105.816 ;
    END
  END a[555]
  PIN a[556]
    DIRECTION INPUT ;
    USE SIGNAL ;
    PORT
      LAYER M3 ;
        RECT  42.228 105.779 42.246 105.816 ;
    END
  END a[556]
  PIN a[557]
    DIRECTION INPUT ;
    USE SIGNAL ;
    PORT
      LAYER M3 ;
        RECT  42.3 105.779 42.318 105.816 ;
    END
  END a[557]
  PIN a[558]
    DIRECTION INPUT ;
    USE SIGNAL ;
    PORT
      LAYER M3 ;
        RECT  42.372 105.779 42.39 105.816 ;
    END
  END a[558]
  PIN a[559]
    DIRECTION INPUT ;
    USE SIGNAL ;
    PORT
      LAYER M3 ;
        RECT  42.444 105.779 42.462 105.816 ;
    END
  END a[559]
  PIN a[55]
    DIRECTION INPUT ;
    USE SIGNAL ;
    PORT
      LAYER M3 ;
        RECT  57.42 105.779 57.438 105.816 ;
    END
  END a[55]
  PIN a[560]
    DIRECTION INPUT ;
    USE SIGNAL ;
    PORT
      LAYER M3 ;
        RECT  42.516 105.779 42.534 105.816 ;
    END
  END a[560]
  PIN a[561]
    DIRECTION INPUT ;
    USE SIGNAL ;
    PORT
      LAYER M3 ;
        RECT  42.588 105.779 42.606 105.816 ;
    END
  END a[561]
  PIN a[562]
    DIRECTION INPUT ;
    USE SIGNAL ;
    PORT
      LAYER M3 ;
        RECT  42.66 105.779 42.678 105.816 ;
    END
  END a[562]
  PIN a[563]
    DIRECTION INPUT ;
    USE SIGNAL ;
    PORT
      LAYER M3 ;
        RECT  42.732 105.779 42.75 105.816 ;
    END
  END a[563]
  PIN a[564]
    DIRECTION INPUT ;
    USE SIGNAL ;
    PORT
      LAYER M3 ;
        RECT  42.804 105.779 42.822 105.816 ;
    END
  END a[564]
  PIN a[565]
    DIRECTION INPUT ;
    USE SIGNAL ;
    PORT
      LAYER M3 ;
        RECT  42.876 105.779 42.894 105.816 ;
    END
  END a[565]
  PIN a[566]
    DIRECTION INPUT ;
    USE SIGNAL ;
    PORT
      LAYER M3 ;
        RECT  42.948 105.779 42.966 105.816 ;
    END
  END a[566]
  PIN a[567]
    DIRECTION INPUT ;
    USE SIGNAL ;
    PORT
      LAYER M3 ;
        RECT  43.02 105.779 43.038 105.816 ;
    END
  END a[567]
  PIN a[568]
    DIRECTION INPUT ;
    USE SIGNAL ;
    PORT
      LAYER M3 ;
        RECT  43.092 105.779 43.11 105.816 ;
    END
  END a[568]
  PIN a[569]
    DIRECTION INPUT ;
    USE SIGNAL ;
    PORT
      LAYER M3 ;
        RECT  43.164 105.779 43.182 105.816 ;
    END
  END a[569]
  PIN a[56]
    DIRECTION INPUT ;
    USE SIGNAL ;
    PORT
      LAYER M3 ;
        RECT  57.492 105.779 57.51 105.816 ;
    END
  END a[56]
  PIN a[570]
    DIRECTION INPUT ;
    USE SIGNAL ;
    PORT
      LAYER M3 ;
        RECT  43.236 105.779 43.254 105.816 ;
    END
  END a[570]
  PIN a[571]
    DIRECTION INPUT ;
    USE SIGNAL ;
    PORT
      LAYER M3 ;
        RECT  43.308 105.779 43.326 105.816 ;
    END
  END a[571]
  PIN a[572]
    DIRECTION INPUT ;
    USE SIGNAL ;
    PORT
      LAYER M3 ;
        RECT  43.38 105.779 43.398 105.816 ;
    END
  END a[572]
  PIN a[573]
    DIRECTION INPUT ;
    USE SIGNAL ;
    PORT
      LAYER M3 ;
        RECT  43.452 105.779 43.47 105.816 ;
    END
  END a[573]
  PIN a[574]
    DIRECTION INPUT ;
    USE SIGNAL ;
    PORT
      LAYER M3 ;
        RECT  43.524 105.779 43.542 105.816 ;
    END
  END a[574]
  PIN a[575]
    DIRECTION INPUT ;
    USE SIGNAL ;
    PORT
      LAYER M3 ;
        RECT  43.596 105.779 43.614 105.816 ;
    END
  END a[575]
  PIN a[576]
    DIRECTION INPUT ;
    USE SIGNAL ;
    PORT
      LAYER M5 ;
        RECT  43.44 105.732 43.464 105.816 ;
    END
  END a[576]
  PIN a[577]
    DIRECTION INPUT ;
    USE SIGNAL ;
    PORT
      LAYER M5 ;
        RECT  43.536 105.732 43.56 105.816 ;
    END
  END a[577]
  PIN a[578]
    DIRECTION INPUT ;
    USE SIGNAL ;
    PORT
      LAYER M5 ;
        RECT  43.632 105.732 43.656 105.816 ;
    END
  END a[578]
  PIN a[579]
    DIRECTION INPUT ;
    USE SIGNAL ;
    PORT
      LAYER M5 ;
        RECT  43.728 105.732 43.752 105.816 ;
    END
  END a[579]
  PIN a[57]
    DIRECTION INPUT ;
    USE SIGNAL ;
    PORT
      LAYER M3 ;
        RECT  57.564 105.779 57.582 105.816 ;
    END
  END a[57]
  PIN a[580]
    DIRECTION INPUT ;
    USE SIGNAL ;
    PORT
      LAYER M5 ;
        RECT  43.824 105.732 43.848 105.816 ;
    END
  END a[580]
  PIN a[581]
    DIRECTION INPUT ;
    USE SIGNAL ;
    PORT
      LAYER M5 ;
        RECT  43.92 105.732 43.944 105.816 ;
    END
  END a[581]
  PIN a[582]
    DIRECTION INPUT ;
    USE SIGNAL ;
    PORT
      LAYER M5 ;
        RECT  44.016 105.732 44.04 105.816 ;
    END
  END a[582]
  PIN a[583]
    DIRECTION INPUT ;
    USE SIGNAL ;
    PORT
      LAYER M5 ;
        RECT  44.112 105.732 44.136 105.816 ;
    END
  END a[583]
  PIN a[584]
    DIRECTION INPUT ;
    USE SIGNAL ;
    PORT
      LAYER M5 ;
        RECT  44.208 105.732 44.232 105.816 ;
    END
  END a[584]
  PIN a[585]
    DIRECTION INPUT ;
    USE SIGNAL ;
    PORT
      LAYER M5 ;
        RECT  44.304 105.732 44.328 105.816 ;
    END
  END a[585]
  PIN a[586]
    DIRECTION INPUT ;
    USE SIGNAL ;
    PORT
      LAYER M5 ;
        RECT  44.4 105.732 44.424 105.816 ;
    END
  END a[586]
  PIN a[587]
    DIRECTION INPUT ;
    USE SIGNAL ;
    PORT
      LAYER M5 ;
        RECT  44.496 105.732 44.52 105.816 ;
    END
  END a[587]
  PIN a[588]
    DIRECTION INPUT ;
    USE SIGNAL ;
    PORT
      LAYER M5 ;
        RECT  44.592 105.732 44.616 105.816 ;
    END
  END a[588]
  PIN a[589]
    DIRECTION INPUT ;
    USE SIGNAL ;
    PORT
      LAYER M5 ;
        RECT  44.688 105.732 44.712 105.816 ;
    END
  END a[589]
  PIN a[58]
    DIRECTION INPUT ;
    USE SIGNAL ;
    PORT
      LAYER M3 ;
        RECT  57.636 105.779 57.654 105.816 ;
    END
  END a[58]
  PIN a[590]
    DIRECTION INPUT ;
    USE SIGNAL ;
    PORT
      LAYER M5 ;
        RECT  44.784 105.732 44.808 105.816 ;
    END
  END a[590]
  PIN a[591]
    DIRECTION INPUT ;
    USE SIGNAL ;
    PORT
      LAYER M5 ;
        RECT  44.88 105.732 44.904 105.816 ;
    END
  END a[591]
  PIN a[592]
    DIRECTION INPUT ;
    USE SIGNAL ;
    PORT
      LAYER M5 ;
        RECT  44.976 105.732 45 105.816 ;
    END
  END a[592]
  PIN a[593]
    DIRECTION INPUT ;
    USE SIGNAL ;
    PORT
      LAYER M5 ;
        RECT  45.072 105.732 45.096 105.816 ;
    END
  END a[593]
  PIN a[594]
    DIRECTION INPUT ;
    USE SIGNAL ;
    PORT
      LAYER M5 ;
        RECT  45.168 105.732 45.192 105.816 ;
    END
  END a[594]
  PIN a[595]
    DIRECTION INPUT ;
    USE SIGNAL ;
    PORT
      LAYER M5 ;
        RECT  45.264 105.732 45.288 105.816 ;
    END
  END a[595]
  PIN a[596]
    DIRECTION INPUT ;
    USE SIGNAL ;
    PORT
      LAYER M5 ;
        RECT  45.36 105.732 45.384 105.816 ;
    END
  END a[596]
  PIN a[597]
    DIRECTION INPUT ;
    USE SIGNAL ;
    PORT
      LAYER M5 ;
        RECT  45.456 105.732 45.48 105.816 ;
    END
  END a[597]
  PIN a[598]
    DIRECTION INPUT ;
    USE SIGNAL ;
    PORT
      LAYER M5 ;
        RECT  45.552 105.732 45.576 105.816 ;
    END
  END a[598]
  PIN a[599]
    DIRECTION INPUT ;
    USE SIGNAL ;
    PORT
      LAYER M5 ;
        RECT  45.648 105.732 45.672 105.816 ;
    END
  END a[599]
  PIN a[59]
    DIRECTION INPUT ;
    USE SIGNAL ;
    PORT
      LAYER M3 ;
        RECT  57.708 105.779 57.726 105.816 ;
    END
  END a[59]
  PIN a[5]
    DIRECTION INPUT ;
    USE SIGNAL ;
    PORT
      LAYER M3 ;
        RECT  58.428 105.779 58.446 105.816 ;
    END
  END a[5]
  PIN a[60]
    DIRECTION INPUT ;
    USE SIGNAL ;
    PORT
      LAYER M3 ;
        RECT  57.78 105.779 57.798 105.816 ;
    END
  END a[60]
  PIN a[61]
    DIRECTION INPUT ;
    USE SIGNAL ;
    PORT
      LAYER M3 ;
        RECT  57.852 105.779 57.87 105.816 ;
    END
  END a[61]
  PIN a[62]
    DIRECTION INPUT ;
    USE SIGNAL ;
    PORT
      LAYER M3 ;
        RECT  57.924 105.779 57.942 105.816 ;
    END
  END a[62]
  PIN a[63]
    DIRECTION INPUT ;
    USE SIGNAL ;
    PORT
      LAYER M3 ;
        RECT  57.996 105.779 58.014 105.816 ;
    END
  END a[63]
  PIN a[64]
    DIRECTION INPUT ;
    USE SIGNAL ;
    PORT
      LAYER M3 ;
        RECT  46.548 105.779 46.566 105.816 ;
    END
  END a[64]
  PIN a[65]
    DIRECTION INPUT ;
    USE SIGNAL ;
    PORT
      LAYER M3 ;
        RECT  46.62 105.779 46.638 105.816 ;
    END
  END a[65]
  PIN a[66]
    DIRECTION INPUT ;
    USE SIGNAL ;
    PORT
      LAYER M3 ;
        RECT  46.692 105.779 46.71 105.816 ;
    END
  END a[66]
  PIN a[67]
    DIRECTION INPUT ;
    USE SIGNAL ;
    PORT
      LAYER M3 ;
        RECT  46.764 105.779 46.782 105.816 ;
    END
  END a[67]
  PIN a[68]
    DIRECTION INPUT ;
    USE SIGNAL ;
    PORT
      LAYER M3 ;
        RECT  46.836 105.779 46.854 105.816 ;
    END
  END a[68]
  PIN a[69]
    DIRECTION INPUT ;
    USE SIGNAL ;
    PORT
      LAYER M3 ;
        RECT  46.908 105.779 46.926 105.816 ;
    END
  END a[69]
  PIN a[6]
    DIRECTION INPUT ;
    USE SIGNAL ;
    PORT
      LAYER M3 ;
        RECT  58.5 105.779 58.518 105.816 ;
    END
  END a[6]
  PIN a[70]
    DIRECTION INPUT ;
    USE SIGNAL ;
    PORT
      LAYER M3 ;
        RECT  46.98 105.779 46.998 105.816 ;
    END
  END a[70]
  PIN a[71]
    DIRECTION INPUT ;
    USE SIGNAL ;
    PORT
      LAYER M3 ;
        RECT  47.052 105.779 47.07 105.816 ;
    END
  END a[71]
  PIN a[72]
    DIRECTION INPUT ;
    USE SIGNAL ;
    PORT
      LAYER M3 ;
        RECT  47.124 105.779 47.142 105.816 ;
    END
  END a[72]
  PIN a[73]
    DIRECTION INPUT ;
    USE SIGNAL ;
    PORT
      LAYER M3 ;
        RECT  47.196 105.779 47.214 105.816 ;
    END
  END a[73]
  PIN a[74]
    DIRECTION INPUT ;
    USE SIGNAL ;
    PORT
      LAYER M3 ;
        RECT  47.268 105.779 47.286 105.816 ;
    END
  END a[74]
  PIN a[75]
    DIRECTION INPUT ;
    USE SIGNAL ;
    PORT
      LAYER M3 ;
        RECT  47.34 105.779 47.358 105.816 ;
    END
  END a[75]
  PIN a[76]
    DIRECTION INPUT ;
    USE SIGNAL ;
    PORT
      LAYER M3 ;
        RECT  47.412 105.779 47.43 105.816 ;
    END
  END a[76]
  PIN a[77]
    DIRECTION INPUT ;
    USE SIGNAL ;
    PORT
      LAYER M3 ;
        RECT  47.484 105.779 47.502 105.816 ;
    END
  END a[77]
  PIN a[78]
    DIRECTION INPUT ;
    USE SIGNAL ;
    PORT
      LAYER M3 ;
        RECT  47.556 105.779 47.574 105.816 ;
    END
  END a[78]
  PIN a[79]
    DIRECTION INPUT ;
    USE SIGNAL ;
    PORT
      LAYER M3 ;
        RECT  47.628 105.779 47.646 105.816 ;
    END
  END a[79]
  PIN a[7]
    DIRECTION INPUT ;
    USE SIGNAL ;
    PORT
      LAYER M3 ;
        RECT  58.572 105.779 58.59 105.816 ;
    END
  END a[7]
  PIN a[80]
    DIRECTION INPUT ;
    USE SIGNAL ;
    PORT
      LAYER M3 ;
        RECT  47.7 105.779 47.718 105.816 ;
    END
  END a[80]
  PIN a[81]
    DIRECTION INPUT ;
    USE SIGNAL ;
    PORT
      LAYER M3 ;
        RECT  47.772 105.779 47.79 105.816 ;
    END
  END a[81]
  PIN a[82]
    DIRECTION INPUT ;
    USE SIGNAL ;
    PORT
      LAYER M3 ;
        RECT  47.844 105.779 47.862 105.816 ;
    END
  END a[82]
  PIN a[83]
    DIRECTION INPUT ;
    USE SIGNAL ;
    PORT
      LAYER M3 ;
        RECT  47.916 105.779 47.934 105.816 ;
    END
  END a[83]
  PIN a[84]
    DIRECTION INPUT ;
    USE SIGNAL ;
    PORT
      LAYER M3 ;
        RECT  47.988 105.779 48.006 105.816 ;
    END
  END a[84]
  PIN a[85]
    DIRECTION INPUT ;
    USE SIGNAL ;
    PORT
      LAYER M3 ;
        RECT  48.06 105.779 48.078 105.816 ;
    END
  END a[85]
  PIN a[86]
    DIRECTION INPUT ;
    USE SIGNAL ;
    PORT
      LAYER M3 ;
        RECT  48.132 105.779 48.15 105.816 ;
    END
  END a[86]
  PIN a[87]
    DIRECTION INPUT ;
    USE SIGNAL ;
    PORT
      LAYER M3 ;
        RECT  48.204 105.779 48.222 105.816 ;
    END
  END a[87]
  PIN a[88]
    DIRECTION INPUT ;
    USE SIGNAL ;
    PORT
      LAYER M3 ;
        RECT  48.276 105.779 48.294 105.816 ;
    END
  END a[88]
  PIN a[89]
    DIRECTION INPUT ;
    USE SIGNAL ;
    PORT
      LAYER M3 ;
        RECT  48.348 105.779 48.366 105.816 ;
    END
  END a[89]
  PIN a[8]
    DIRECTION INPUT ;
    USE SIGNAL ;
    PORT
      LAYER M3 ;
        RECT  58.644 105.779 58.662 105.816 ;
    END
  END a[8]
  PIN a[90]
    DIRECTION INPUT ;
    USE SIGNAL ;
    PORT
      LAYER M3 ;
        RECT  48.42 105.779 48.438 105.816 ;
    END
  END a[90]
  PIN a[91]
    DIRECTION INPUT ;
    USE SIGNAL ;
    PORT
      LAYER M3 ;
        RECT  48.492 105.779 48.51 105.816 ;
    END
  END a[91]
  PIN a[92]
    DIRECTION INPUT ;
    USE SIGNAL ;
    PORT
      LAYER M3 ;
        RECT  48.564 105.779 48.582 105.816 ;
    END
  END a[92]
  PIN a[93]
    DIRECTION INPUT ;
    USE SIGNAL ;
    PORT
      LAYER M3 ;
        RECT  48.636 105.779 48.654 105.816 ;
    END
  END a[93]
  PIN a[94]
    DIRECTION INPUT ;
    USE SIGNAL ;
    PORT
      LAYER M3 ;
        RECT  48.708 105.779 48.726 105.816 ;
    END
  END a[94]
  PIN a[95]
    DIRECTION INPUT ;
    USE SIGNAL ;
    PORT
      LAYER M3 ;
        RECT  48.78 105.779 48.798 105.816 ;
    END
  END a[95]
  PIN a[96]
    DIRECTION INPUT ;
    USE SIGNAL ;
    PORT
      LAYER M3 ;
        RECT  51.156 105.779 51.174 105.816 ;
    END
  END a[96]
  PIN a[97]
    DIRECTION INPUT ;
    USE SIGNAL ;
    PORT
      LAYER M3 ;
        RECT  51.228 105.779 51.246 105.816 ;
    END
  END a[97]
  PIN a[98]
    DIRECTION INPUT ;
    USE SIGNAL ;
    PORT
      LAYER M3 ;
        RECT  51.3 105.779 51.318 105.816 ;
    END
  END a[98]
  PIN a[99]
    DIRECTION INPUT ;
    USE SIGNAL ;
    PORT
      LAYER M3 ;
        RECT  51.372 105.779 51.39 105.816 ;
    END
  END a[99]
  PIN a[9]
    DIRECTION INPUT ;
    USE SIGNAL ;
    PORT
      LAYER M3 ;
        RECT  58.716 105.779 58.734 105.816 ;
    END
  END a[9]
  PIN b[0]
    DIRECTION OUTPUT ;
    USE SIGNAL ;
    PORT
      LAYER M4 ;
        RECT  104.004 42.192 104.088 42.216 ;
    END
  END b[0]
  PIN b[100]
    DIRECTION OUTPUT ;
    USE SIGNAL ;
    PORT
      LAYER M4 ;
        RECT  104.004 45.648 104.088 45.672 ;
    END
  END b[100]
  PIN b[101]
    DIRECTION OUTPUT ;
    USE SIGNAL ;
    PORT
      LAYER M4 ;
        RECT  104.004 45.744 104.088 45.768 ;
    END
  END b[101]
  PIN b[102]
    DIRECTION OUTPUT ;
    USE SIGNAL ;
    PORT
      LAYER M4 ;
        RECT  104.004 45.84 104.088 45.864 ;
    END
  END b[102]
  PIN b[103]
    DIRECTION OUTPUT ;
    USE SIGNAL ;
    PORT
      LAYER M4 ;
        RECT  104.004 45.936 104.088 45.96 ;
    END
  END b[103]
  PIN b[104]
    DIRECTION OUTPUT ;
    USE SIGNAL ;
    PORT
      LAYER M4 ;
        RECT  104.004 46.032 104.088 46.056 ;
    END
  END b[104]
  PIN b[105]
    DIRECTION OUTPUT ;
    USE SIGNAL ;
    PORT
      LAYER M4 ;
        RECT  104.004 46.128 104.088 46.152 ;
    END
  END b[105]
  PIN b[106]
    DIRECTION OUTPUT ;
    USE SIGNAL ;
    PORT
      LAYER M4 ;
        RECT  104.004 46.224 104.088 46.248 ;
    END
  END b[106]
  PIN b[107]
    DIRECTION OUTPUT ;
    USE SIGNAL ;
    PORT
      LAYER M4 ;
        RECT  104.004 46.32 104.088 46.344 ;
    END
  END b[107]
  PIN b[108]
    DIRECTION OUTPUT ;
    USE SIGNAL ;
    PORT
      LAYER M4 ;
        RECT  104.004 46.416 104.088 46.44 ;
    END
  END b[108]
  PIN b[109]
    DIRECTION OUTPUT ;
    USE SIGNAL ;
    PORT
      LAYER M4 ;
        RECT  104.004 46.512 104.088 46.536 ;
    END
  END b[109]
  PIN b[10]
    DIRECTION OUTPUT ;
    USE SIGNAL ;
    PORT
      LAYER M4 ;
        RECT  104.004 43.152 104.088 43.176 ;
    END
  END b[10]
  PIN b[110]
    DIRECTION OUTPUT ;
    USE SIGNAL ;
    PORT
      LAYER M4 ;
        RECT  104.004 46.608 104.088 46.632 ;
    END
  END b[110]
  PIN b[111]
    DIRECTION OUTPUT ;
    USE SIGNAL ;
    PORT
      LAYER M4 ;
        RECT  104.004 46.704 104.088 46.728 ;
    END
  END b[111]
  PIN b[112]
    DIRECTION OUTPUT ;
    USE SIGNAL ;
    PORT
      LAYER M4 ;
        RECT  104.004 46.8 104.088 46.824 ;
    END
  END b[112]
  PIN b[113]
    DIRECTION OUTPUT ;
    USE SIGNAL ;
    PORT
      LAYER M4 ;
        RECT  104.004 46.896 104.088 46.92 ;
    END
  END b[113]
  PIN b[114]
    DIRECTION OUTPUT ;
    USE SIGNAL ;
    PORT
      LAYER M4 ;
        RECT  104.004 46.992 104.088 47.016 ;
    END
  END b[114]
  PIN b[115]
    DIRECTION OUTPUT ;
    USE SIGNAL ;
    PORT
      LAYER M4 ;
        RECT  104.004 47.088 104.088 47.112 ;
    END
  END b[115]
  PIN b[116]
    DIRECTION OUTPUT ;
    USE SIGNAL ;
    PORT
      LAYER M4 ;
        RECT  104.004 47.184 104.088 47.208 ;
    END
  END b[116]
  PIN b[117]
    DIRECTION OUTPUT ;
    USE SIGNAL ;
    PORT
      LAYER M4 ;
        RECT  104.004 47.28 104.088 47.304 ;
    END
  END b[117]
  PIN b[118]
    DIRECTION OUTPUT ;
    USE SIGNAL ;
    PORT
      LAYER M4 ;
        RECT  104.004 47.376 104.088 47.4 ;
    END
  END b[118]
  PIN b[119]
    DIRECTION OUTPUT ;
    USE SIGNAL ;
    PORT
      LAYER M4 ;
        RECT  104.004 47.472 104.088 47.496 ;
    END
  END b[119]
  PIN b[11]
    DIRECTION OUTPUT ;
    USE SIGNAL ;
    PORT
      LAYER M4 ;
        RECT  104.004 43.248 104.088 43.272 ;
    END
  END b[11]
  PIN b[120]
    DIRECTION OUTPUT ;
    USE SIGNAL ;
    PORT
      LAYER M4 ;
        RECT  104.004 47.568 104.088 47.592 ;
    END
  END b[120]
  PIN b[121]
    DIRECTION OUTPUT ;
    USE SIGNAL ;
    PORT
      LAYER M4 ;
        RECT  104.004 47.664 104.088 47.688 ;
    END
  END b[121]
  PIN b[122]
    DIRECTION OUTPUT ;
    USE SIGNAL ;
    PORT
      LAYER M4 ;
        RECT  104.004 47.76 104.088 47.784 ;
    END
  END b[122]
  PIN b[123]
    DIRECTION OUTPUT ;
    USE SIGNAL ;
    PORT
      LAYER M4 ;
        RECT  104.004 47.856 104.088 47.88 ;
    END
  END b[123]
  PIN b[124]
    DIRECTION OUTPUT ;
    USE SIGNAL ;
    PORT
      LAYER M4 ;
        RECT  104.004 47.952 104.088 47.976 ;
    END
  END b[124]
  PIN b[125]
    DIRECTION OUTPUT ;
    USE SIGNAL ;
    PORT
      LAYER M4 ;
        RECT  104.004 48.048 104.088 48.072 ;
    END
  END b[125]
  PIN b[126]
    DIRECTION OUTPUT ;
    USE SIGNAL ;
    PORT
      LAYER M4 ;
        RECT  104.004 48.144 104.088 48.168 ;
    END
  END b[126]
  PIN b[127]
    DIRECTION OUTPUT ;
    USE SIGNAL ;
    PORT
      LAYER M4 ;
        RECT  104.004 48.24 104.088 48.264 ;
    END
  END b[127]
  PIN b[128]
    DIRECTION OUTPUT ;
    USE SIGNAL ;
    PORT
      LAYER M4 ;
        RECT  104.004 51.408 104.088 51.432 ;
    END
  END b[128]
  PIN b[129]
    DIRECTION OUTPUT ;
    USE SIGNAL ;
    PORT
      LAYER M4 ;
        RECT  104.004 51.504 104.088 51.528 ;
    END
  END b[129]
  PIN b[12]
    DIRECTION OUTPUT ;
    USE SIGNAL ;
    PORT
      LAYER M4 ;
        RECT  104.004 43.344 104.088 43.368 ;
    END
  END b[12]
  PIN b[130]
    DIRECTION OUTPUT ;
    USE SIGNAL ;
    PORT
      LAYER M4 ;
        RECT  104.004 51.6 104.088 51.624 ;
    END
  END b[130]
  PIN b[131]
    DIRECTION OUTPUT ;
    USE SIGNAL ;
    PORT
      LAYER M4 ;
        RECT  104.004 51.696 104.088 51.72 ;
    END
  END b[131]
  PIN b[132]
    DIRECTION OUTPUT ;
    USE SIGNAL ;
    PORT
      LAYER M4 ;
        RECT  104.004 51.792 104.088 51.816 ;
    END
  END b[132]
  PIN b[133]
    DIRECTION OUTPUT ;
    USE SIGNAL ;
    PORT
      LAYER M4 ;
        RECT  104.004 51.888 104.088 51.912 ;
    END
  END b[133]
  PIN b[134]
    DIRECTION OUTPUT ;
    USE SIGNAL ;
    PORT
      LAYER M4 ;
        RECT  104.004 51.984 104.088 52.008 ;
    END
  END b[134]
  PIN b[135]
    DIRECTION OUTPUT ;
    USE SIGNAL ;
    PORT
      LAYER M4 ;
        RECT  104.004 52.08 104.088 52.104 ;
    END
  END b[135]
  PIN b[136]
    DIRECTION OUTPUT ;
    USE SIGNAL ;
    PORT
      LAYER M4 ;
        RECT  104.004 52.176 104.088 52.2 ;
    END
  END b[136]
  PIN b[137]
    DIRECTION OUTPUT ;
    USE SIGNAL ;
    PORT
      LAYER M4 ;
        RECT  104.004 52.272 104.088 52.296 ;
    END
  END b[137]
  PIN b[138]
    DIRECTION OUTPUT ;
    USE SIGNAL ;
    PORT
      LAYER M4 ;
        RECT  104.004 52.368 104.088 52.392 ;
    END
  END b[138]
  PIN b[139]
    DIRECTION OUTPUT ;
    USE SIGNAL ;
    PORT
      LAYER M4 ;
        RECT  104.004 52.464 104.088 52.488 ;
    END
  END b[139]
  PIN b[13]
    DIRECTION OUTPUT ;
    USE SIGNAL ;
    PORT
      LAYER M4 ;
        RECT  104.004 43.44 104.088 43.464 ;
    END
  END b[13]
  PIN b[140]
    DIRECTION OUTPUT ;
    USE SIGNAL ;
    PORT
      LAYER M4 ;
        RECT  104.004 52.56 104.088 52.584 ;
    END
  END b[140]
  PIN b[141]
    DIRECTION OUTPUT ;
    USE SIGNAL ;
    PORT
      LAYER M4 ;
        RECT  104.004 52.656 104.088 52.68 ;
    END
  END b[141]
  PIN b[142]
    DIRECTION OUTPUT ;
    USE SIGNAL ;
    PORT
      LAYER M4 ;
        RECT  104.004 52.752 104.088 52.776 ;
    END
  END b[142]
  PIN b[143]
    DIRECTION OUTPUT ;
    USE SIGNAL ;
    PORT
      LAYER M4 ;
        RECT  104.004 52.848 104.088 52.872 ;
    END
  END b[143]
  PIN b[144]
    DIRECTION OUTPUT ;
    USE SIGNAL ;
    PORT
      LAYER M4 ;
        RECT  104.004 52.944 104.088 52.968 ;
    END
  END b[144]
  PIN b[145]
    DIRECTION OUTPUT ;
    USE SIGNAL ;
    PORT
      LAYER M4 ;
        RECT  104.004 53.04 104.088 53.064 ;
    END
  END b[145]
  PIN b[146]
    DIRECTION OUTPUT ;
    USE SIGNAL ;
    PORT
      LAYER M4 ;
        RECT  104.004 53.136 104.088 53.16 ;
    END
  END b[146]
  PIN b[147]
    DIRECTION OUTPUT ;
    USE SIGNAL ;
    PORT
      LAYER M4 ;
        RECT  104.004 53.232 104.088 53.256 ;
    END
  END b[147]
  PIN b[148]
    DIRECTION OUTPUT ;
    USE SIGNAL ;
    PORT
      LAYER M4 ;
        RECT  104.004 53.328 104.088 53.352 ;
    END
  END b[148]
  PIN b[149]
    DIRECTION OUTPUT ;
    USE SIGNAL ;
    PORT
      LAYER M4 ;
        RECT  104.004 53.424 104.088 53.448 ;
    END
  END b[149]
  PIN b[14]
    DIRECTION OUTPUT ;
    USE SIGNAL ;
    PORT
      LAYER M4 ;
        RECT  104.004 43.536 104.088 43.56 ;
    END
  END b[14]
  PIN b[150]
    DIRECTION OUTPUT ;
    USE SIGNAL ;
    PORT
      LAYER M4 ;
        RECT  104.004 53.52 104.088 53.544 ;
    END
  END b[150]
  PIN b[151]
    DIRECTION OUTPUT ;
    USE SIGNAL ;
    PORT
      LAYER M4 ;
        RECT  104.004 53.616 104.088 53.64 ;
    END
  END b[151]
  PIN b[152]
    DIRECTION OUTPUT ;
    USE SIGNAL ;
    PORT
      LAYER M4 ;
        RECT  104.004 53.712 104.088 53.736 ;
    END
  END b[152]
  PIN b[153]
    DIRECTION OUTPUT ;
    USE SIGNAL ;
    PORT
      LAYER M4 ;
        RECT  104.004 53.808 104.088 53.832 ;
    END
  END b[153]
  PIN b[154]
    DIRECTION OUTPUT ;
    USE SIGNAL ;
    PORT
      LAYER M4 ;
        RECT  104.004 53.904 104.088 53.928 ;
    END
  END b[154]
  PIN b[155]
    DIRECTION OUTPUT ;
    USE SIGNAL ;
    PORT
      LAYER M4 ;
        RECT  104.004 54 104.088 54.024 ;
    END
  END b[155]
  PIN b[156]
    DIRECTION OUTPUT ;
    USE SIGNAL ;
    PORT
      LAYER M4 ;
        RECT  104.004 54.096 104.088 54.12 ;
    END
  END b[156]
  PIN b[157]
    DIRECTION OUTPUT ;
    USE SIGNAL ;
    PORT
      LAYER M4 ;
        RECT  104.004 54.192 104.088 54.216 ;
    END
  END b[157]
  PIN b[158]
    DIRECTION OUTPUT ;
    USE SIGNAL ;
    PORT
      LAYER M4 ;
        RECT  104.004 54.288 104.088 54.312 ;
    END
  END b[158]
  PIN b[159]
    DIRECTION OUTPUT ;
    USE SIGNAL ;
    PORT
      LAYER M4 ;
        RECT  104.004 54.384 104.088 54.408 ;
    END
  END b[159]
  PIN b[15]
    DIRECTION OUTPUT ;
    USE SIGNAL ;
    PORT
      LAYER M4 ;
        RECT  104.004 43.632 104.088 43.656 ;
    END
  END b[15]
  PIN b[160]
    DIRECTION OUTPUT ;
    USE SIGNAL ;
    PORT
      LAYER M4 ;
        RECT  104.004 54.48 104.088 54.504 ;
    END
  END b[160]
  PIN b[161]
    DIRECTION OUTPUT ;
    USE SIGNAL ;
    PORT
      LAYER M4 ;
        RECT  104.004 54.576 104.088 54.6 ;
    END
  END b[161]
  PIN b[162]
    DIRECTION OUTPUT ;
    USE SIGNAL ;
    PORT
      LAYER M4 ;
        RECT  104.004 54.672 104.088 54.696 ;
    END
  END b[162]
  PIN b[163]
    DIRECTION OUTPUT ;
    USE SIGNAL ;
    PORT
      LAYER M4 ;
        RECT  104.004 54.768 104.088 54.792 ;
    END
  END b[163]
  PIN b[164]
    DIRECTION OUTPUT ;
    USE SIGNAL ;
    PORT
      LAYER M4 ;
        RECT  104.004 54.864 104.088 54.888 ;
    END
  END b[164]
  PIN b[165]
    DIRECTION OUTPUT ;
    USE SIGNAL ;
    PORT
      LAYER M4 ;
        RECT  104.004 54.96 104.088 54.984 ;
    END
  END b[165]
  PIN b[166]
    DIRECTION OUTPUT ;
    USE SIGNAL ;
    PORT
      LAYER M4 ;
        RECT  104.004 55.056 104.088 55.08 ;
    END
  END b[166]
  PIN b[167]
    DIRECTION OUTPUT ;
    USE SIGNAL ;
    PORT
      LAYER M4 ;
        RECT  104.004 55.152 104.088 55.176 ;
    END
  END b[167]
  PIN b[168]
    DIRECTION OUTPUT ;
    USE SIGNAL ;
    PORT
      LAYER M4 ;
        RECT  104.004 55.248 104.088 55.272 ;
    END
  END b[168]
  PIN b[169]
    DIRECTION OUTPUT ;
    USE SIGNAL ;
    PORT
      LAYER M4 ;
        RECT  104.004 55.344 104.088 55.368 ;
    END
  END b[169]
  PIN b[16]
    DIRECTION OUTPUT ;
    USE SIGNAL ;
    PORT
      LAYER M4 ;
        RECT  104.004 43.728 104.088 43.752 ;
    END
  END b[16]
  PIN b[170]
    DIRECTION OUTPUT ;
    USE SIGNAL ;
    PORT
      LAYER M4 ;
        RECT  104.004 55.44 104.088 55.464 ;
    END
  END b[170]
  PIN b[171]
    DIRECTION OUTPUT ;
    USE SIGNAL ;
    PORT
      LAYER M4 ;
        RECT  104.004 55.536 104.088 55.56 ;
    END
  END b[171]
  PIN b[172]
    DIRECTION OUTPUT ;
    USE SIGNAL ;
    PORT
      LAYER M4 ;
        RECT  104.004 55.632 104.088 55.656 ;
    END
  END b[172]
  PIN b[173]
    DIRECTION OUTPUT ;
    USE SIGNAL ;
    PORT
      LAYER M4 ;
        RECT  104.004 55.728 104.088 55.752 ;
    END
  END b[173]
  PIN b[174]
    DIRECTION OUTPUT ;
    USE SIGNAL ;
    PORT
      LAYER M4 ;
        RECT  104.004 55.824 104.088 55.848 ;
    END
  END b[174]
  PIN b[175]
    DIRECTION OUTPUT ;
    USE SIGNAL ;
    PORT
      LAYER M4 ;
        RECT  104.004 55.92 104.088 55.944 ;
    END
  END b[175]
  PIN b[176]
    DIRECTION OUTPUT ;
    USE SIGNAL ;
    PORT
      LAYER M4 ;
        RECT  104.004 56.016 104.088 56.04 ;
    END
  END b[176]
  PIN b[177]
    DIRECTION OUTPUT ;
    USE SIGNAL ;
    PORT
      LAYER M4 ;
        RECT  104.004 56.112 104.088 56.136 ;
    END
  END b[177]
  PIN b[178]
    DIRECTION OUTPUT ;
    USE SIGNAL ;
    PORT
      LAYER M4 ;
        RECT  104.004 56.208 104.088 56.232 ;
    END
  END b[178]
  PIN b[179]
    DIRECTION OUTPUT ;
    USE SIGNAL ;
    PORT
      LAYER M4 ;
        RECT  104.004 56.304 104.088 56.328 ;
    END
  END b[179]
  PIN b[17]
    DIRECTION OUTPUT ;
    USE SIGNAL ;
    PORT
      LAYER M4 ;
        RECT  104.004 43.824 104.088 43.848 ;
    END
  END b[17]
  PIN b[180]
    DIRECTION OUTPUT ;
    USE SIGNAL ;
    PORT
      LAYER M4 ;
        RECT  104.004 56.4 104.088 56.424 ;
    END
  END b[180]
  PIN b[181]
    DIRECTION OUTPUT ;
    USE SIGNAL ;
    PORT
      LAYER M4 ;
        RECT  104.004 56.496 104.088 56.52 ;
    END
  END b[181]
  PIN b[182]
    DIRECTION OUTPUT ;
    USE SIGNAL ;
    PORT
      LAYER M4 ;
        RECT  104.004 56.592 104.088 56.616 ;
    END
  END b[182]
  PIN b[183]
    DIRECTION OUTPUT ;
    USE SIGNAL ;
    PORT
      LAYER M4 ;
        RECT  104.004 56.688 104.088 56.712 ;
    END
  END b[183]
  PIN b[184]
    DIRECTION OUTPUT ;
    USE SIGNAL ;
    PORT
      LAYER M4 ;
        RECT  104.004 56.784 104.088 56.808 ;
    END
  END b[184]
  PIN b[185]
    DIRECTION OUTPUT ;
    USE SIGNAL ;
    PORT
      LAYER M4 ;
        RECT  104.004 56.88 104.088 56.904 ;
    END
  END b[185]
  PIN b[186]
    DIRECTION OUTPUT ;
    USE SIGNAL ;
    PORT
      LAYER M4 ;
        RECT  104.004 56.976 104.088 57 ;
    END
  END b[186]
  PIN b[187]
    DIRECTION OUTPUT ;
    USE SIGNAL ;
    PORT
      LAYER M4 ;
        RECT  104.004 57.072 104.088 57.096 ;
    END
  END b[187]
  PIN b[188]
    DIRECTION OUTPUT ;
    USE SIGNAL ;
    PORT
      LAYER M4 ;
        RECT  104.004 57.168 104.088 57.192 ;
    END
  END b[188]
  PIN b[189]
    DIRECTION OUTPUT ;
    USE SIGNAL ;
    PORT
      LAYER M4 ;
        RECT  104.004 57.264 104.088 57.288 ;
    END
  END b[189]
  PIN b[18]
    DIRECTION OUTPUT ;
    USE SIGNAL ;
    PORT
      LAYER M4 ;
        RECT  104.004 43.92 104.088 43.944 ;
    END
  END b[18]
  PIN b[190]
    DIRECTION OUTPUT ;
    USE SIGNAL ;
    PORT
      LAYER M4 ;
        RECT  104.004 57.36 104.088 57.384 ;
    END
  END b[190]
  PIN b[191]
    DIRECTION OUTPUT ;
    USE SIGNAL ;
    PORT
      LAYER M4 ;
        RECT  104.004 57.456 104.088 57.48 ;
    END
  END b[191]
  PIN b[192]
    DIRECTION OUTPUT ;
    USE SIGNAL ;
    PORT
      LAYER M4 ;
        RECT  104.004 73.68 104.088 73.704 ;
    END
  END b[192]
  PIN b[193]
    DIRECTION OUTPUT ;
    USE SIGNAL ;
    PORT
      LAYER M4 ;
        RECT  104.004 73.776 104.088 73.8 ;
    END
  END b[193]
  PIN b[194]
    DIRECTION OUTPUT ;
    USE SIGNAL ;
    PORT
      LAYER M4 ;
        RECT  104.004 73.872 104.088 73.896 ;
    END
  END b[194]
  PIN b[195]
    DIRECTION OUTPUT ;
    USE SIGNAL ;
    PORT
      LAYER M4 ;
        RECT  104.004 73.968 104.088 73.992 ;
    END
  END b[195]
  PIN b[196]
    DIRECTION OUTPUT ;
    USE SIGNAL ;
    PORT
      LAYER M4 ;
        RECT  104.004 74.064 104.088 74.088 ;
    END
  END b[196]
  PIN b[197]
    DIRECTION OUTPUT ;
    USE SIGNAL ;
    PORT
      LAYER M4 ;
        RECT  104.004 74.16 104.088 74.184 ;
    END
  END b[197]
  PIN b[198]
    DIRECTION OUTPUT ;
    USE SIGNAL ;
    PORT
      LAYER M4 ;
        RECT  104.004 74.256 104.088 74.28 ;
    END
  END b[198]
  PIN b[199]
    DIRECTION OUTPUT ;
    USE SIGNAL ;
    PORT
      LAYER M4 ;
        RECT  104.004 74.352 104.088 74.376 ;
    END
  END b[199]
  PIN b[19]
    DIRECTION OUTPUT ;
    USE SIGNAL ;
    PORT
      LAYER M4 ;
        RECT  104.004 44.016 104.088 44.04 ;
    END
  END b[19]
  PIN b[1]
    DIRECTION OUTPUT ;
    USE SIGNAL ;
    PORT
      LAYER M4 ;
        RECT  104.004 42.288 104.088 42.312 ;
    END
  END b[1]
  PIN b[200]
    DIRECTION OUTPUT ;
    USE SIGNAL ;
    PORT
      LAYER M4 ;
        RECT  104.004 74.448 104.088 74.472 ;
    END
  END b[200]
  PIN b[201]
    DIRECTION OUTPUT ;
    USE SIGNAL ;
    PORT
      LAYER M4 ;
        RECT  104.004 74.544 104.088 74.568 ;
    END
  END b[201]
  PIN b[202]
    DIRECTION OUTPUT ;
    USE SIGNAL ;
    PORT
      LAYER M4 ;
        RECT  104.004 74.64 104.088 74.664 ;
    END
  END b[202]
  PIN b[203]
    DIRECTION OUTPUT ;
    USE SIGNAL ;
    PORT
      LAYER M4 ;
        RECT  104.004 74.736 104.088 74.76 ;
    END
  END b[203]
  PIN b[204]
    DIRECTION OUTPUT ;
    USE SIGNAL ;
    PORT
      LAYER M4 ;
        RECT  104.004 74.832 104.088 74.856 ;
    END
  END b[204]
  PIN b[205]
    DIRECTION OUTPUT ;
    USE SIGNAL ;
    PORT
      LAYER M4 ;
        RECT  104.004 74.928 104.088 74.952 ;
    END
  END b[205]
  PIN b[206]
    DIRECTION OUTPUT ;
    USE SIGNAL ;
    PORT
      LAYER M4 ;
        RECT  104.004 75.024 104.088 75.048 ;
    END
  END b[206]
  PIN b[207]
    DIRECTION OUTPUT ;
    USE SIGNAL ;
    PORT
      LAYER M4 ;
        RECT  104.004 75.12 104.088 75.144 ;
    END
  END b[207]
  PIN b[208]
    DIRECTION OUTPUT ;
    USE SIGNAL ;
    PORT
      LAYER M4 ;
        RECT  104.004 75.216 104.088 75.24 ;
    END
  END b[208]
  PIN b[209]
    DIRECTION OUTPUT ;
    USE SIGNAL ;
    PORT
      LAYER M4 ;
        RECT  104.004 75.312 104.088 75.336 ;
    END
  END b[209]
  PIN b[20]
    DIRECTION OUTPUT ;
    USE SIGNAL ;
    PORT
      LAYER M4 ;
        RECT  104.004 44.112 104.088 44.136 ;
    END
  END b[20]
  PIN b[210]
    DIRECTION OUTPUT ;
    USE SIGNAL ;
    PORT
      LAYER M4 ;
        RECT  104.004 75.408 104.088 75.432 ;
    END
  END b[210]
  PIN b[211]
    DIRECTION OUTPUT ;
    USE SIGNAL ;
    PORT
      LAYER M4 ;
        RECT  104.004 75.504 104.088 75.528 ;
    END
  END b[211]
  PIN b[212]
    DIRECTION OUTPUT ;
    USE SIGNAL ;
    PORT
      LAYER M4 ;
        RECT  104.004 75.6 104.088 75.624 ;
    END
  END b[212]
  PIN b[213]
    DIRECTION OUTPUT ;
    USE SIGNAL ;
    PORT
      LAYER M4 ;
        RECT  104.004 75.696 104.088 75.72 ;
    END
  END b[213]
  PIN b[214]
    DIRECTION OUTPUT ;
    USE SIGNAL ;
    PORT
      LAYER M4 ;
        RECT  104.004 75.792 104.088 75.816 ;
    END
  END b[214]
  PIN b[215]
    DIRECTION OUTPUT ;
    USE SIGNAL ;
    PORT
      LAYER M4 ;
        RECT  104.004 75.888 104.088 75.912 ;
    END
  END b[215]
  PIN b[216]
    DIRECTION OUTPUT ;
    USE SIGNAL ;
    PORT
      LAYER M4 ;
        RECT  104.004 75.984 104.088 76.008 ;
    END
  END b[216]
  PIN b[217]
    DIRECTION OUTPUT ;
    USE SIGNAL ;
    PORT
      LAYER M4 ;
        RECT  104.004 76.08 104.088 76.104 ;
    END
  END b[217]
  PIN b[218]
    DIRECTION OUTPUT ;
    USE SIGNAL ;
    PORT
      LAYER M4 ;
        RECT  104.004 76.176 104.088 76.2 ;
    END
  END b[218]
  PIN b[219]
    DIRECTION OUTPUT ;
    USE SIGNAL ;
    PORT
      LAYER M4 ;
        RECT  104.004 76.272 104.088 76.296 ;
    END
  END b[219]
  PIN b[21]
    DIRECTION OUTPUT ;
    USE SIGNAL ;
    PORT
      LAYER M4 ;
        RECT  104.004 44.208 104.088 44.232 ;
    END
  END b[21]
  PIN b[220]
    DIRECTION OUTPUT ;
    USE SIGNAL ;
    PORT
      LAYER M4 ;
        RECT  104.004 76.368 104.088 76.392 ;
    END
  END b[220]
  PIN b[221]
    DIRECTION OUTPUT ;
    USE SIGNAL ;
    PORT
      LAYER M4 ;
        RECT  104.004 76.464 104.088 76.488 ;
    END
  END b[221]
  PIN b[222]
    DIRECTION OUTPUT ;
    USE SIGNAL ;
    PORT
      LAYER M4 ;
        RECT  104.004 76.56 104.088 76.584 ;
    END
  END b[222]
  PIN b[223]
    DIRECTION OUTPUT ;
    USE SIGNAL ;
    PORT
      LAYER M4 ;
        RECT  104.004 76.656 104.088 76.68 ;
    END
  END b[223]
  PIN b[224]
    DIRECTION OUTPUT ;
    USE SIGNAL ;
    PORT
      LAYER M4 ;
        RECT  104.004 70.608 104.088 70.632 ;
    END
  END b[224]
  PIN b[225]
    DIRECTION OUTPUT ;
    USE SIGNAL ;
    PORT
      LAYER M4 ;
        RECT  104.004 70.704 104.088 70.728 ;
    END
  END b[225]
  PIN b[226]
    DIRECTION OUTPUT ;
    USE SIGNAL ;
    PORT
      LAYER M4 ;
        RECT  104.004 70.8 104.088 70.824 ;
    END
  END b[226]
  PIN b[227]
    DIRECTION OUTPUT ;
    USE SIGNAL ;
    PORT
      LAYER M4 ;
        RECT  104.004 70.896 104.088 70.92 ;
    END
  END b[227]
  PIN b[228]
    DIRECTION OUTPUT ;
    USE SIGNAL ;
    PORT
      LAYER M4 ;
        RECT  104.004 70.992 104.088 71.016 ;
    END
  END b[228]
  PIN b[229]
    DIRECTION OUTPUT ;
    USE SIGNAL ;
    PORT
      LAYER M4 ;
        RECT  104.004 71.088 104.088 71.112 ;
    END
  END b[229]
  PIN b[22]
    DIRECTION OUTPUT ;
    USE SIGNAL ;
    PORT
      LAYER M4 ;
        RECT  104.004 44.304 104.088 44.328 ;
    END
  END b[22]
  PIN b[230]
    DIRECTION OUTPUT ;
    USE SIGNAL ;
    PORT
      LAYER M4 ;
        RECT  104.004 71.184 104.088 71.208 ;
    END
  END b[230]
  PIN b[231]
    DIRECTION OUTPUT ;
    USE SIGNAL ;
    PORT
      LAYER M4 ;
        RECT  104.004 71.28 104.088 71.304 ;
    END
  END b[231]
  PIN b[232]
    DIRECTION OUTPUT ;
    USE SIGNAL ;
    PORT
      LAYER M4 ;
        RECT  104.004 71.376 104.088 71.4 ;
    END
  END b[232]
  PIN b[233]
    DIRECTION OUTPUT ;
    USE SIGNAL ;
    PORT
      LAYER M4 ;
        RECT  104.004 71.472 104.088 71.496 ;
    END
  END b[233]
  PIN b[234]
    DIRECTION OUTPUT ;
    USE SIGNAL ;
    PORT
      LAYER M4 ;
        RECT  104.004 71.568 104.088 71.592 ;
    END
  END b[234]
  PIN b[235]
    DIRECTION OUTPUT ;
    USE SIGNAL ;
    PORT
      LAYER M4 ;
        RECT  104.004 71.664 104.088 71.688 ;
    END
  END b[235]
  PIN b[236]
    DIRECTION OUTPUT ;
    USE SIGNAL ;
    PORT
      LAYER M4 ;
        RECT  104.004 71.76 104.088 71.784 ;
    END
  END b[236]
  PIN b[237]
    DIRECTION OUTPUT ;
    USE SIGNAL ;
    PORT
      LAYER M4 ;
        RECT  104.004 71.856 104.088 71.88 ;
    END
  END b[237]
  PIN b[238]
    DIRECTION OUTPUT ;
    USE SIGNAL ;
    PORT
      LAYER M4 ;
        RECT  104.004 71.952 104.088 71.976 ;
    END
  END b[238]
  PIN b[239]
    DIRECTION OUTPUT ;
    USE SIGNAL ;
    PORT
      LAYER M4 ;
        RECT  104.004 72.048 104.088 72.072 ;
    END
  END b[239]
  PIN b[23]
    DIRECTION OUTPUT ;
    USE SIGNAL ;
    PORT
      LAYER M4 ;
        RECT  104.004 44.4 104.088 44.424 ;
    END
  END b[23]
  PIN b[240]
    DIRECTION OUTPUT ;
    USE SIGNAL ;
    PORT
      LAYER M4 ;
        RECT  104.004 72.144 104.088 72.168 ;
    END
  END b[240]
  PIN b[241]
    DIRECTION OUTPUT ;
    USE SIGNAL ;
    PORT
      LAYER M4 ;
        RECT  104.004 72.24 104.088 72.264 ;
    END
  END b[241]
  PIN b[242]
    DIRECTION OUTPUT ;
    USE SIGNAL ;
    PORT
      LAYER M4 ;
        RECT  104.004 72.336 104.088 72.36 ;
    END
  END b[242]
  PIN b[243]
    DIRECTION OUTPUT ;
    USE SIGNAL ;
    PORT
      LAYER M4 ;
        RECT  104.004 72.432 104.088 72.456 ;
    END
  END b[243]
  PIN b[244]
    DIRECTION OUTPUT ;
    USE SIGNAL ;
    PORT
      LAYER M4 ;
        RECT  104.004 72.528 104.088 72.552 ;
    END
  END b[244]
  PIN b[245]
    DIRECTION OUTPUT ;
    USE SIGNAL ;
    PORT
      LAYER M4 ;
        RECT  104.004 72.624 104.088 72.648 ;
    END
  END b[245]
  PIN b[246]
    DIRECTION OUTPUT ;
    USE SIGNAL ;
    PORT
      LAYER M4 ;
        RECT  104.004 72.72 104.088 72.744 ;
    END
  END b[246]
  PIN b[247]
    DIRECTION OUTPUT ;
    USE SIGNAL ;
    PORT
      LAYER M4 ;
        RECT  104.004 72.816 104.088 72.84 ;
    END
  END b[247]
  PIN b[248]
    DIRECTION OUTPUT ;
    USE SIGNAL ;
    PORT
      LAYER M4 ;
        RECT  104.004 72.912 104.088 72.936 ;
    END
  END b[248]
  PIN b[249]
    DIRECTION OUTPUT ;
    USE SIGNAL ;
    PORT
      LAYER M4 ;
        RECT  104.004 73.008 104.088 73.032 ;
    END
  END b[249]
  PIN b[24]
    DIRECTION OUTPUT ;
    USE SIGNAL ;
    PORT
      LAYER M4 ;
        RECT  104.004 44.496 104.088 44.52 ;
    END
  END b[24]
  PIN b[250]
    DIRECTION OUTPUT ;
    USE SIGNAL ;
    PORT
      LAYER M4 ;
        RECT  104.004 73.104 104.088 73.128 ;
    END
  END b[250]
  PIN b[251]
    DIRECTION OUTPUT ;
    USE SIGNAL ;
    PORT
      LAYER M4 ;
        RECT  104.004 73.2 104.088 73.224 ;
    END
  END b[251]
  PIN b[252]
    DIRECTION OUTPUT ;
    USE SIGNAL ;
    PORT
      LAYER M4 ;
        RECT  104.004 73.296 104.088 73.32 ;
    END
  END b[252]
  PIN b[253]
    DIRECTION OUTPUT ;
    USE SIGNAL ;
    PORT
      LAYER M4 ;
        RECT  104.004 73.392 104.088 73.416 ;
    END
  END b[253]
  PIN b[254]
    DIRECTION OUTPUT ;
    USE SIGNAL ;
    PORT
      LAYER M4 ;
        RECT  104.004 73.488 104.088 73.512 ;
    END
  END b[254]
  PIN b[255]
    DIRECTION OUTPUT ;
    USE SIGNAL ;
    PORT
      LAYER M4 ;
        RECT  104.004 73.584 104.088 73.608 ;
    END
  END b[255]
  PIN b[256]
    DIRECTION OUTPUT ;
    USE SIGNAL ;
    PORT
      LAYER M4 ;
        RECT  104.004 64.464 104.088 64.488 ;
    END
  END b[256]
  PIN b[257]
    DIRECTION OUTPUT ;
    USE SIGNAL ;
    PORT
      LAYER M4 ;
        RECT  104.004 64.56 104.088 64.584 ;
    END
  END b[257]
  PIN b[258]
    DIRECTION OUTPUT ;
    USE SIGNAL ;
    PORT
      LAYER M4 ;
        RECT  104.004 64.656 104.088 64.68 ;
    END
  END b[258]
  PIN b[259]
    DIRECTION OUTPUT ;
    USE SIGNAL ;
    PORT
      LAYER M4 ;
        RECT  104.004 64.752 104.088 64.776 ;
    END
  END b[259]
  PIN b[25]
    DIRECTION OUTPUT ;
    USE SIGNAL ;
    PORT
      LAYER M4 ;
        RECT  104.004 44.592 104.088 44.616 ;
    END
  END b[25]
  PIN b[260]
    DIRECTION OUTPUT ;
    USE SIGNAL ;
    PORT
      LAYER M4 ;
        RECT  104.004 64.848 104.088 64.872 ;
    END
  END b[260]
  PIN b[261]
    DIRECTION OUTPUT ;
    USE SIGNAL ;
    PORT
      LAYER M4 ;
        RECT  104.004 64.944 104.088 64.968 ;
    END
  END b[261]
  PIN b[262]
    DIRECTION OUTPUT ;
    USE SIGNAL ;
    PORT
      LAYER M4 ;
        RECT  104.004 65.04 104.088 65.064 ;
    END
  END b[262]
  PIN b[263]
    DIRECTION OUTPUT ;
    USE SIGNAL ;
    PORT
      LAYER M4 ;
        RECT  104.004 65.136 104.088 65.16 ;
    END
  END b[263]
  PIN b[264]
    DIRECTION OUTPUT ;
    USE SIGNAL ;
    PORT
      LAYER M4 ;
        RECT  104.004 65.232 104.088 65.256 ;
    END
  END b[264]
  PIN b[265]
    DIRECTION OUTPUT ;
    USE SIGNAL ;
    PORT
      LAYER M4 ;
        RECT  104.004 65.328 104.088 65.352 ;
    END
  END b[265]
  PIN b[266]
    DIRECTION OUTPUT ;
    USE SIGNAL ;
    PORT
      LAYER M4 ;
        RECT  104.004 65.424 104.088 65.448 ;
    END
  END b[266]
  PIN b[267]
    DIRECTION OUTPUT ;
    USE SIGNAL ;
    PORT
      LAYER M4 ;
        RECT  104.004 65.52 104.088 65.544 ;
    END
  END b[267]
  PIN b[268]
    DIRECTION OUTPUT ;
    USE SIGNAL ;
    PORT
      LAYER M4 ;
        RECT  104.004 65.616 104.088 65.64 ;
    END
  END b[268]
  PIN b[269]
    DIRECTION OUTPUT ;
    USE SIGNAL ;
    PORT
      LAYER M4 ;
        RECT  104.004 65.712 104.088 65.736 ;
    END
  END b[269]
  PIN b[26]
    DIRECTION OUTPUT ;
    USE SIGNAL ;
    PORT
      LAYER M4 ;
        RECT  104.004 44.688 104.088 44.712 ;
    END
  END b[26]
  PIN b[270]
    DIRECTION OUTPUT ;
    USE SIGNAL ;
    PORT
      LAYER M4 ;
        RECT  104.004 65.808 104.088 65.832 ;
    END
  END b[270]
  PIN b[271]
    DIRECTION OUTPUT ;
    USE SIGNAL ;
    PORT
      LAYER M4 ;
        RECT  104.004 65.904 104.088 65.928 ;
    END
  END b[271]
  PIN b[272]
    DIRECTION OUTPUT ;
    USE SIGNAL ;
    PORT
      LAYER M4 ;
        RECT  104.004 66 104.088 66.024 ;
    END
  END b[272]
  PIN b[273]
    DIRECTION OUTPUT ;
    USE SIGNAL ;
    PORT
      LAYER M4 ;
        RECT  104.004 66.096 104.088 66.12 ;
    END
  END b[273]
  PIN b[274]
    DIRECTION OUTPUT ;
    USE SIGNAL ;
    PORT
      LAYER M4 ;
        RECT  104.004 66.192 104.088 66.216 ;
    END
  END b[274]
  PIN b[275]
    DIRECTION OUTPUT ;
    USE SIGNAL ;
    PORT
      LAYER M4 ;
        RECT  104.004 66.288 104.088 66.312 ;
    END
  END b[275]
  PIN b[276]
    DIRECTION OUTPUT ;
    USE SIGNAL ;
    PORT
      LAYER M4 ;
        RECT  104.004 66.384 104.088 66.408 ;
    END
  END b[276]
  PIN b[277]
    DIRECTION OUTPUT ;
    USE SIGNAL ;
    PORT
      LAYER M4 ;
        RECT  104.004 66.48 104.088 66.504 ;
    END
  END b[277]
  PIN b[278]
    DIRECTION OUTPUT ;
    USE SIGNAL ;
    PORT
      LAYER M4 ;
        RECT  104.004 66.576 104.088 66.6 ;
    END
  END b[278]
  PIN b[279]
    DIRECTION OUTPUT ;
    USE SIGNAL ;
    PORT
      LAYER M4 ;
        RECT  104.004 66.672 104.088 66.696 ;
    END
  END b[279]
  PIN b[27]
    DIRECTION OUTPUT ;
    USE SIGNAL ;
    PORT
      LAYER M4 ;
        RECT  104.004 44.784 104.088 44.808 ;
    END
  END b[27]
  PIN b[280]
    DIRECTION OUTPUT ;
    USE SIGNAL ;
    PORT
      LAYER M4 ;
        RECT  104.004 66.768 104.088 66.792 ;
    END
  END b[280]
  PIN b[281]
    DIRECTION OUTPUT ;
    USE SIGNAL ;
    PORT
      LAYER M4 ;
        RECT  104.004 66.864 104.088 66.888 ;
    END
  END b[281]
  PIN b[282]
    DIRECTION OUTPUT ;
    USE SIGNAL ;
    PORT
      LAYER M4 ;
        RECT  104.004 66.96 104.088 66.984 ;
    END
  END b[282]
  PIN b[283]
    DIRECTION OUTPUT ;
    USE SIGNAL ;
    PORT
      LAYER M4 ;
        RECT  104.004 67.056 104.088 67.08 ;
    END
  END b[283]
  PIN b[284]
    DIRECTION OUTPUT ;
    USE SIGNAL ;
    PORT
      LAYER M4 ;
        RECT  104.004 67.152 104.088 67.176 ;
    END
  END b[284]
  PIN b[285]
    DIRECTION OUTPUT ;
    USE SIGNAL ;
    PORT
      LAYER M4 ;
        RECT  104.004 67.248 104.088 67.272 ;
    END
  END b[285]
  PIN b[286]
    DIRECTION OUTPUT ;
    USE SIGNAL ;
    PORT
      LAYER M4 ;
        RECT  104.004 67.344 104.088 67.368 ;
    END
  END b[286]
  PIN b[287]
    DIRECTION OUTPUT ;
    USE SIGNAL ;
    PORT
      LAYER M4 ;
        RECT  104.004 67.44 104.088 67.464 ;
    END
  END b[287]
  PIN b[288]
    DIRECTION OUTPUT ;
    USE SIGNAL ;
    PORT
      LAYER M4 ;
        RECT  104.004 67.536 104.088 67.56 ;
    END
  END b[288]
  PIN b[289]
    DIRECTION OUTPUT ;
    USE SIGNAL ;
    PORT
      LAYER M4 ;
        RECT  104.004 67.632 104.088 67.656 ;
    END
  END b[289]
  PIN b[28]
    DIRECTION OUTPUT ;
    USE SIGNAL ;
    PORT
      LAYER M4 ;
        RECT  104.004 44.88 104.088 44.904 ;
    END
  END b[28]
  PIN b[290]
    DIRECTION OUTPUT ;
    USE SIGNAL ;
    PORT
      LAYER M4 ;
        RECT  104.004 67.728 104.088 67.752 ;
    END
  END b[290]
  PIN b[291]
    DIRECTION OUTPUT ;
    USE SIGNAL ;
    PORT
      LAYER M4 ;
        RECT  104.004 67.824 104.088 67.848 ;
    END
  END b[291]
  PIN b[292]
    DIRECTION OUTPUT ;
    USE SIGNAL ;
    PORT
      LAYER M4 ;
        RECT  104.004 67.92 104.088 67.944 ;
    END
  END b[292]
  PIN b[293]
    DIRECTION OUTPUT ;
    USE SIGNAL ;
    PORT
      LAYER M4 ;
        RECT  104.004 68.016 104.088 68.04 ;
    END
  END b[293]
  PIN b[294]
    DIRECTION OUTPUT ;
    USE SIGNAL ;
    PORT
      LAYER M4 ;
        RECT  104.004 68.112 104.088 68.136 ;
    END
  END b[294]
  PIN b[295]
    DIRECTION OUTPUT ;
    USE SIGNAL ;
    PORT
      LAYER M4 ;
        RECT  104.004 68.208 104.088 68.232 ;
    END
  END b[295]
  PIN b[296]
    DIRECTION OUTPUT ;
    USE SIGNAL ;
    PORT
      LAYER M4 ;
        RECT  104.004 68.304 104.088 68.328 ;
    END
  END b[296]
  PIN b[297]
    DIRECTION OUTPUT ;
    USE SIGNAL ;
    PORT
      LAYER M4 ;
        RECT  104.004 68.4 104.088 68.424 ;
    END
  END b[297]
  PIN b[298]
    DIRECTION OUTPUT ;
    USE SIGNAL ;
    PORT
      LAYER M4 ;
        RECT  104.004 68.496 104.088 68.52 ;
    END
  END b[298]
  PIN b[299]
    DIRECTION OUTPUT ;
    USE SIGNAL ;
    PORT
      LAYER M4 ;
        RECT  104.004 68.592 104.088 68.616 ;
    END
  END b[299]
  PIN b[29]
    DIRECTION OUTPUT ;
    USE SIGNAL ;
    PORT
      LAYER M4 ;
        RECT  104.004 44.976 104.088 45 ;
    END
  END b[29]
  PIN b[2]
    DIRECTION OUTPUT ;
    USE SIGNAL ;
    PORT
      LAYER M4 ;
        RECT  104.004 42.384 104.088 42.408 ;
    END
  END b[2]
  PIN b[300]
    DIRECTION OUTPUT ;
    USE SIGNAL ;
    PORT
      LAYER M4 ;
        RECT  104.004 68.688 104.088 68.712 ;
    END
  END b[300]
  PIN b[301]
    DIRECTION OUTPUT ;
    USE SIGNAL ;
    PORT
      LAYER M4 ;
        RECT  104.004 68.784 104.088 68.808 ;
    END
  END b[301]
  PIN b[302]
    DIRECTION OUTPUT ;
    USE SIGNAL ;
    PORT
      LAYER M4 ;
        RECT  104.004 68.88 104.088 68.904 ;
    END
  END b[302]
  PIN b[303]
    DIRECTION OUTPUT ;
    USE SIGNAL ;
    PORT
      LAYER M4 ;
        RECT  104.004 68.976 104.088 69 ;
    END
  END b[303]
  PIN b[304]
    DIRECTION OUTPUT ;
    USE SIGNAL ;
    PORT
      LAYER M4 ;
        RECT  104.004 69.072 104.088 69.096 ;
    END
  END b[304]
  PIN b[305]
    DIRECTION OUTPUT ;
    USE SIGNAL ;
    PORT
      LAYER M4 ;
        RECT  104.004 69.168 104.088 69.192 ;
    END
  END b[305]
  PIN b[306]
    DIRECTION OUTPUT ;
    USE SIGNAL ;
    PORT
      LAYER M4 ;
        RECT  104.004 69.264 104.088 69.288 ;
    END
  END b[306]
  PIN b[307]
    DIRECTION OUTPUT ;
    USE SIGNAL ;
    PORT
      LAYER M4 ;
        RECT  104.004 69.36 104.088 69.384 ;
    END
  END b[307]
  PIN b[308]
    DIRECTION OUTPUT ;
    USE SIGNAL ;
    PORT
      LAYER M4 ;
        RECT  104.004 69.456 104.088 69.48 ;
    END
  END b[308]
  PIN b[309]
    DIRECTION OUTPUT ;
    USE SIGNAL ;
    PORT
      LAYER M4 ;
        RECT  104.004 69.552 104.088 69.576 ;
    END
  END b[309]
  PIN b[30]
    DIRECTION OUTPUT ;
    USE SIGNAL ;
    PORT
      LAYER M4 ;
        RECT  104.004 45.072 104.088 45.096 ;
    END
  END b[30]
  PIN b[310]
    DIRECTION OUTPUT ;
    USE SIGNAL ;
    PORT
      LAYER M4 ;
        RECT  104.004 69.648 104.088 69.672 ;
    END
  END b[310]
  PIN b[311]
    DIRECTION OUTPUT ;
    USE SIGNAL ;
    PORT
      LAYER M4 ;
        RECT  104.004 69.744 104.088 69.768 ;
    END
  END b[311]
  PIN b[312]
    DIRECTION OUTPUT ;
    USE SIGNAL ;
    PORT
      LAYER M4 ;
        RECT  104.004 69.84 104.088 69.864 ;
    END
  END b[312]
  PIN b[313]
    DIRECTION OUTPUT ;
    USE SIGNAL ;
    PORT
      LAYER M4 ;
        RECT  104.004 69.936 104.088 69.96 ;
    END
  END b[313]
  PIN b[314]
    DIRECTION OUTPUT ;
    USE SIGNAL ;
    PORT
      LAYER M4 ;
        RECT  104.004 70.032 104.088 70.056 ;
    END
  END b[314]
  PIN b[315]
    DIRECTION OUTPUT ;
    USE SIGNAL ;
    PORT
      LAYER M4 ;
        RECT  104.004 70.128 104.088 70.152 ;
    END
  END b[315]
  PIN b[316]
    DIRECTION OUTPUT ;
    USE SIGNAL ;
    PORT
      LAYER M4 ;
        RECT  104.004 70.224 104.088 70.248 ;
    END
  END b[316]
  PIN b[317]
    DIRECTION OUTPUT ;
    USE SIGNAL ;
    PORT
      LAYER M4 ;
        RECT  104.004 70.32 104.088 70.344 ;
    END
  END b[317]
  PIN b[318]
    DIRECTION OUTPUT ;
    USE SIGNAL ;
    PORT
      LAYER M4 ;
        RECT  104.004 70.416 104.088 70.44 ;
    END
  END b[318]
  PIN b[319]
    DIRECTION OUTPUT ;
    USE SIGNAL ;
    PORT
      LAYER M4 ;
        RECT  104.004 70.512 104.088 70.536 ;
    END
  END b[319]
  PIN b[31]
    DIRECTION OUTPUT ;
    USE SIGNAL ;
    PORT
      LAYER M4 ;
        RECT  104.004 45.168 104.088 45.192 ;
    END
  END b[31]
  PIN b[320]
    DIRECTION OUTPUT ;
    USE SIGNAL ;
    PORT
      LAYER M4 ;
        RECT  104.004 58.32 104.088 58.344 ;
    END
  END b[320]
  PIN b[321]
    DIRECTION OUTPUT ;
    USE SIGNAL ;
    PORT
      LAYER M4 ;
        RECT  104.004 58.416 104.088 58.44 ;
    END
  END b[321]
  PIN b[322]
    DIRECTION OUTPUT ;
    USE SIGNAL ;
    PORT
      LAYER M4 ;
        RECT  104.004 58.512 104.088 58.536 ;
    END
  END b[322]
  PIN b[323]
    DIRECTION OUTPUT ;
    USE SIGNAL ;
    PORT
      LAYER M4 ;
        RECT  104.004 58.608 104.088 58.632 ;
    END
  END b[323]
  PIN b[324]
    DIRECTION OUTPUT ;
    USE SIGNAL ;
    PORT
      LAYER M4 ;
        RECT  104.004 58.704 104.088 58.728 ;
    END
  END b[324]
  PIN b[325]
    DIRECTION OUTPUT ;
    USE SIGNAL ;
    PORT
      LAYER M4 ;
        RECT  104.004 58.8 104.088 58.824 ;
    END
  END b[325]
  PIN b[326]
    DIRECTION OUTPUT ;
    USE SIGNAL ;
    PORT
      LAYER M4 ;
        RECT  104.004 58.896 104.088 58.92 ;
    END
  END b[326]
  PIN b[327]
    DIRECTION OUTPUT ;
    USE SIGNAL ;
    PORT
      LAYER M4 ;
        RECT  104.004 58.992 104.088 59.016 ;
    END
  END b[327]
  PIN b[328]
    DIRECTION OUTPUT ;
    USE SIGNAL ;
    PORT
      LAYER M4 ;
        RECT  104.004 59.088 104.088 59.112 ;
    END
  END b[328]
  PIN b[329]
    DIRECTION OUTPUT ;
    USE SIGNAL ;
    PORT
      LAYER M4 ;
        RECT  104.004 59.184 104.088 59.208 ;
    END
  END b[329]
  PIN b[32]
    DIRECTION OUTPUT ;
    USE SIGNAL ;
    PORT
      LAYER M4 ;
        RECT  104.004 48.336 104.088 48.36 ;
    END
  END b[32]
  PIN b[330]
    DIRECTION OUTPUT ;
    USE SIGNAL ;
    PORT
      LAYER M4 ;
        RECT  104.004 59.28 104.088 59.304 ;
    END
  END b[330]
  PIN b[331]
    DIRECTION OUTPUT ;
    USE SIGNAL ;
    PORT
      LAYER M4 ;
        RECT  104.004 59.376 104.088 59.4 ;
    END
  END b[331]
  PIN b[332]
    DIRECTION OUTPUT ;
    USE SIGNAL ;
    PORT
      LAYER M4 ;
        RECT  104.004 59.472 104.088 59.496 ;
    END
  END b[332]
  PIN b[333]
    DIRECTION OUTPUT ;
    USE SIGNAL ;
    PORT
      LAYER M4 ;
        RECT  104.004 59.568 104.088 59.592 ;
    END
  END b[333]
  PIN b[334]
    DIRECTION OUTPUT ;
    USE SIGNAL ;
    PORT
      LAYER M4 ;
        RECT  104.004 59.664 104.088 59.688 ;
    END
  END b[334]
  PIN b[335]
    DIRECTION OUTPUT ;
    USE SIGNAL ;
    PORT
      LAYER M4 ;
        RECT  104.004 59.76 104.088 59.784 ;
    END
  END b[335]
  PIN b[336]
    DIRECTION OUTPUT ;
    USE SIGNAL ;
    PORT
      LAYER M4 ;
        RECT  104.004 59.856 104.088 59.88 ;
    END
  END b[336]
  PIN b[337]
    DIRECTION OUTPUT ;
    USE SIGNAL ;
    PORT
      LAYER M4 ;
        RECT  104.004 59.952 104.088 59.976 ;
    END
  END b[337]
  PIN b[338]
    DIRECTION OUTPUT ;
    USE SIGNAL ;
    PORT
      LAYER M4 ;
        RECT  104.004 60.048 104.088 60.072 ;
    END
  END b[338]
  PIN b[339]
    DIRECTION OUTPUT ;
    USE SIGNAL ;
    PORT
      LAYER M4 ;
        RECT  104.004 60.144 104.088 60.168 ;
    END
  END b[339]
  PIN b[33]
    DIRECTION OUTPUT ;
    USE SIGNAL ;
    PORT
      LAYER M4 ;
        RECT  104.004 48.432 104.088 48.456 ;
    END
  END b[33]
  PIN b[340]
    DIRECTION OUTPUT ;
    USE SIGNAL ;
    PORT
      LAYER M4 ;
        RECT  104.004 60.24 104.088 60.264 ;
    END
  END b[340]
  PIN b[341]
    DIRECTION OUTPUT ;
    USE SIGNAL ;
    PORT
      LAYER M4 ;
        RECT  104.004 60.336 104.088 60.36 ;
    END
  END b[341]
  PIN b[342]
    DIRECTION OUTPUT ;
    USE SIGNAL ;
    PORT
      LAYER M4 ;
        RECT  104.004 60.432 104.088 60.456 ;
    END
  END b[342]
  PIN b[343]
    DIRECTION OUTPUT ;
    USE SIGNAL ;
    PORT
      LAYER M4 ;
        RECT  104.004 60.528 104.088 60.552 ;
    END
  END b[343]
  PIN b[344]
    DIRECTION OUTPUT ;
    USE SIGNAL ;
    PORT
      LAYER M4 ;
        RECT  104.004 60.624 104.088 60.648 ;
    END
  END b[344]
  PIN b[345]
    DIRECTION OUTPUT ;
    USE SIGNAL ;
    PORT
      LAYER M4 ;
        RECT  104.004 60.72 104.088 60.744 ;
    END
  END b[345]
  PIN b[346]
    DIRECTION OUTPUT ;
    USE SIGNAL ;
    PORT
      LAYER M4 ;
        RECT  104.004 60.816 104.088 60.84 ;
    END
  END b[346]
  PIN b[347]
    DIRECTION OUTPUT ;
    USE SIGNAL ;
    PORT
      LAYER M4 ;
        RECT  104.004 60.912 104.088 60.936 ;
    END
  END b[347]
  PIN b[348]
    DIRECTION OUTPUT ;
    USE SIGNAL ;
    PORT
      LAYER M4 ;
        RECT  104.004 61.008 104.088 61.032 ;
    END
  END b[348]
  PIN b[349]
    DIRECTION OUTPUT ;
    USE SIGNAL ;
    PORT
      LAYER M4 ;
        RECT  104.004 61.104 104.088 61.128 ;
    END
  END b[349]
  PIN b[34]
    DIRECTION OUTPUT ;
    USE SIGNAL ;
    PORT
      LAYER M4 ;
        RECT  104.004 48.528 104.088 48.552 ;
    END
  END b[34]
  PIN b[350]
    DIRECTION OUTPUT ;
    USE SIGNAL ;
    PORT
      LAYER M4 ;
        RECT  104.004 61.2 104.088 61.224 ;
    END
  END b[350]
  PIN b[351]
    DIRECTION OUTPUT ;
    USE SIGNAL ;
    PORT
      LAYER M4 ;
        RECT  104.004 61.296 104.088 61.32 ;
    END
  END b[351]
  PIN b[352]
    DIRECTION OUTPUT ;
    USE SIGNAL ;
    PORT
      LAYER M4 ;
        RECT  104.004 61.392 104.088 61.416 ;
    END
  END b[352]
  PIN b[353]
    DIRECTION OUTPUT ;
    USE SIGNAL ;
    PORT
      LAYER M4 ;
        RECT  104.004 61.488 104.088 61.512 ;
    END
  END b[353]
  PIN b[354]
    DIRECTION OUTPUT ;
    USE SIGNAL ;
    PORT
      LAYER M4 ;
        RECT  104.004 61.584 104.088 61.608 ;
    END
  END b[354]
  PIN b[355]
    DIRECTION OUTPUT ;
    USE SIGNAL ;
    PORT
      LAYER M4 ;
        RECT  104.004 61.68 104.088 61.704 ;
    END
  END b[355]
  PIN b[356]
    DIRECTION OUTPUT ;
    USE SIGNAL ;
    PORT
      LAYER M4 ;
        RECT  104.004 61.776 104.088 61.8 ;
    END
  END b[356]
  PIN b[357]
    DIRECTION OUTPUT ;
    USE SIGNAL ;
    PORT
      LAYER M4 ;
        RECT  104.004 61.872 104.088 61.896 ;
    END
  END b[357]
  PIN b[358]
    DIRECTION OUTPUT ;
    USE SIGNAL ;
    PORT
      LAYER M4 ;
        RECT  104.004 61.968 104.088 61.992 ;
    END
  END b[358]
  PIN b[359]
    DIRECTION OUTPUT ;
    USE SIGNAL ;
    PORT
      LAYER M4 ;
        RECT  104.004 62.064 104.088 62.088 ;
    END
  END b[359]
  PIN b[35]
    DIRECTION OUTPUT ;
    USE SIGNAL ;
    PORT
      LAYER M4 ;
        RECT  104.004 48.624 104.088 48.648 ;
    END
  END b[35]
  PIN b[360]
    DIRECTION OUTPUT ;
    USE SIGNAL ;
    PORT
      LAYER M4 ;
        RECT  104.004 62.16 104.088 62.184 ;
    END
  END b[360]
  PIN b[361]
    DIRECTION OUTPUT ;
    USE SIGNAL ;
    PORT
      LAYER M4 ;
        RECT  104.004 62.256 104.088 62.28 ;
    END
  END b[361]
  PIN b[362]
    DIRECTION OUTPUT ;
    USE SIGNAL ;
    PORT
      LAYER M4 ;
        RECT  104.004 62.352 104.088 62.376 ;
    END
  END b[362]
  PIN b[363]
    DIRECTION OUTPUT ;
    USE SIGNAL ;
    PORT
      LAYER M4 ;
        RECT  104.004 62.448 104.088 62.472 ;
    END
  END b[363]
  PIN b[364]
    DIRECTION OUTPUT ;
    USE SIGNAL ;
    PORT
      LAYER M4 ;
        RECT  104.004 62.544 104.088 62.568 ;
    END
  END b[364]
  PIN b[365]
    DIRECTION OUTPUT ;
    USE SIGNAL ;
    PORT
      LAYER M4 ;
        RECT  104.004 62.64 104.088 62.664 ;
    END
  END b[365]
  PIN b[366]
    DIRECTION OUTPUT ;
    USE SIGNAL ;
    PORT
      LAYER M4 ;
        RECT  104.004 62.736 104.088 62.76 ;
    END
  END b[366]
  PIN b[367]
    DIRECTION OUTPUT ;
    USE SIGNAL ;
    PORT
      LAYER M4 ;
        RECT  104.004 62.832 104.088 62.856 ;
    END
  END b[367]
  PIN b[368]
    DIRECTION OUTPUT ;
    USE SIGNAL ;
    PORT
      LAYER M4 ;
        RECT  104.004 62.928 104.088 62.952 ;
    END
  END b[368]
  PIN b[369]
    DIRECTION OUTPUT ;
    USE SIGNAL ;
    PORT
      LAYER M4 ;
        RECT  104.004 63.024 104.088 63.048 ;
    END
  END b[369]
  PIN b[36]
    DIRECTION OUTPUT ;
    USE SIGNAL ;
    PORT
      LAYER M4 ;
        RECT  104.004 48.72 104.088 48.744 ;
    END
  END b[36]
  PIN b[370]
    DIRECTION OUTPUT ;
    USE SIGNAL ;
    PORT
      LAYER M4 ;
        RECT  104.004 63.12 104.088 63.144 ;
    END
  END b[370]
  PIN b[371]
    DIRECTION OUTPUT ;
    USE SIGNAL ;
    PORT
      LAYER M4 ;
        RECT  104.004 63.216 104.088 63.24 ;
    END
  END b[371]
  PIN b[372]
    DIRECTION OUTPUT ;
    USE SIGNAL ;
    PORT
      LAYER M4 ;
        RECT  104.004 63.312 104.088 63.336 ;
    END
  END b[372]
  PIN b[373]
    DIRECTION OUTPUT ;
    USE SIGNAL ;
    PORT
      LAYER M4 ;
        RECT  104.004 63.408 104.088 63.432 ;
    END
  END b[373]
  PIN b[374]
    DIRECTION OUTPUT ;
    USE SIGNAL ;
    PORT
      LAYER M4 ;
        RECT  104.004 63.504 104.088 63.528 ;
    END
  END b[374]
  PIN b[375]
    DIRECTION OUTPUT ;
    USE SIGNAL ;
    PORT
      LAYER M4 ;
        RECT  104.004 63.6 104.088 63.624 ;
    END
  END b[375]
  PIN b[376]
    DIRECTION OUTPUT ;
    USE SIGNAL ;
    PORT
      LAYER M4 ;
        RECT  104.004 63.696 104.088 63.72 ;
    END
  END b[376]
  PIN b[377]
    DIRECTION OUTPUT ;
    USE SIGNAL ;
    PORT
      LAYER M4 ;
        RECT  104.004 63.792 104.088 63.816 ;
    END
  END b[377]
  PIN b[378]
    DIRECTION OUTPUT ;
    USE SIGNAL ;
    PORT
      LAYER M4 ;
        RECT  104.004 63.888 104.088 63.912 ;
    END
  END b[378]
  PIN b[379]
    DIRECTION OUTPUT ;
    USE SIGNAL ;
    PORT
      LAYER M4 ;
        RECT  104.004 63.984 104.088 64.008 ;
    END
  END b[379]
  PIN b[37]
    DIRECTION OUTPUT ;
    USE SIGNAL ;
    PORT
      LAYER M4 ;
        RECT  104.004 48.816 104.088 48.84 ;
    END
  END b[37]
  PIN b[380]
    DIRECTION OUTPUT ;
    USE SIGNAL ;
    PORT
      LAYER M4 ;
        RECT  104.004 64.08 104.088 64.104 ;
    END
  END b[380]
  PIN b[381]
    DIRECTION OUTPUT ;
    USE SIGNAL ;
    PORT
      LAYER M4 ;
        RECT  104.004 64.176 104.088 64.2 ;
    END
  END b[381]
  PIN b[382]
    DIRECTION OUTPUT ;
    USE SIGNAL ;
    PORT
      LAYER M4 ;
        RECT  104.004 64.272 104.088 64.296 ;
    END
  END b[382]
  PIN b[383]
    DIRECTION OUTPUT ;
    USE SIGNAL ;
    PORT
      LAYER M4 ;
        RECT  104.004 64.368 104.088 64.392 ;
    END
  END b[383]
  PIN b[384]
    DIRECTION OUTPUT ;
    USE SIGNAL ;
    PORT
      LAYER M4 ;
        RECT  104.004 19.92 104.088 19.944 ;
    END
  END b[384]
  PIN b[385]
    DIRECTION OUTPUT ;
    USE SIGNAL ;
    PORT
      LAYER M4 ;
        RECT  104.004 20.016 104.088 20.04 ;
    END
  END b[385]
  PIN b[386]
    DIRECTION OUTPUT ;
    USE SIGNAL ;
    PORT
      LAYER M4 ;
        RECT  104.004 20.112 104.088 20.136 ;
    END
  END b[386]
  PIN b[387]
    DIRECTION OUTPUT ;
    USE SIGNAL ;
    PORT
      LAYER M4 ;
        RECT  104.004 20.208 104.088 20.232 ;
    END
  END b[387]
  PIN b[388]
    DIRECTION OUTPUT ;
    USE SIGNAL ;
    PORT
      LAYER M4 ;
        RECT  104.004 20.304 104.088 20.328 ;
    END
  END b[388]
  PIN b[389]
    DIRECTION OUTPUT ;
    USE SIGNAL ;
    PORT
      LAYER M4 ;
        RECT  104.004 20.4 104.088 20.424 ;
    END
  END b[389]
  PIN b[38]
    DIRECTION OUTPUT ;
    USE SIGNAL ;
    PORT
      LAYER M4 ;
        RECT  104.004 48.912 104.088 48.936 ;
    END
  END b[38]
  PIN b[390]
    DIRECTION OUTPUT ;
    USE SIGNAL ;
    PORT
      LAYER M4 ;
        RECT  104.004 20.496 104.088 20.52 ;
    END
  END b[390]
  PIN b[391]
    DIRECTION OUTPUT ;
    USE SIGNAL ;
    PORT
      LAYER M4 ;
        RECT  104.004 20.592 104.088 20.616 ;
    END
  END b[391]
  PIN b[392]
    DIRECTION OUTPUT ;
    USE SIGNAL ;
    PORT
      LAYER M4 ;
        RECT  104.004 20.688 104.088 20.712 ;
    END
  END b[392]
  PIN b[393]
    DIRECTION OUTPUT ;
    USE SIGNAL ;
    PORT
      LAYER M4 ;
        RECT  104.004 20.784 104.088 20.808 ;
    END
  END b[393]
  PIN b[394]
    DIRECTION OUTPUT ;
    USE SIGNAL ;
    PORT
      LAYER M4 ;
        RECT  104.004 20.88 104.088 20.904 ;
    END
  END b[394]
  PIN b[395]
    DIRECTION OUTPUT ;
    USE SIGNAL ;
    PORT
      LAYER M4 ;
        RECT  104.004 20.976 104.088 21 ;
    END
  END b[395]
  PIN b[396]
    DIRECTION OUTPUT ;
    USE SIGNAL ;
    PORT
      LAYER M4 ;
        RECT  104.004 21.072 104.088 21.096 ;
    END
  END b[396]
  PIN b[397]
    DIRECTION OUTPUT ;
    USE SIGNAL ;
    PORT
      LAYER M4 ;
        RECT  104.004 21.168 104.088 21.192 ;
    END
  END b[397]
  PIN b[398]
    DIRECTION OUTPUT ;
    USE SIGNAL ;
    PORT
      LAYER M4 ;
        RECT  104.004 21.264 104.088 21.288 ;
    END
  END b[398]
  PIN b[399]
    DIRECTION OUTPUT ;
    USE SIGNAL ;
    PORT
      LAYER M4 ;
        RECT  104.004 21.36 104.088 21.384 ;
    END
  END b[399]
  PIN b[39]
    DIRECTION OUTPUT ;
    USE SIGNAL ;
    PORT
      LAYER M4 ;
        RECT  104.004 49.008 104.088 49.032 ;
    END
  END b[39]
  PIN b[3]
    DIRECTION OUTPUT ;
    USE SIGNAL ;
    PORT
      LAYER M4 ;
        RECT  104.004 42.48 104.088 42.504 ;
    END
  END b[3]
  PIN b[400]
    DIRECTION OUTPUT ;
    USE SIGNAL ;
    PORT
      LAYER M4 ;
        RECT  104.004 21.456 104.088 21.48 ;
    END
  END b[400]
  PIN b[401]
    DIRECTION OUTPUT ;
    USE SIGNAL ;
    PORT
      LAYER M4 ;
        RECT  104.004 21.552 104.088 21.576 ;
    END
  END b[401]
  PIN b[402]
    DIRECTION OUTPUT ;
    USE SIGNAL ;
    PORT
      LAYER M4 ;
        RECT  104.004 21.648 104.088 21.672 ;
    END
  END b[402]
  PIN b[403]
    DIRECTION OUTPUT ;
    USE SIGNAL ;
    PORT
      LAYER M4 ;
        RECT  104.004 21.744 104.088 21.768 ;
    END
  END b[403]
  PIN b[404]
    DIRECTION OUTPUT ;
    USE SIGNAL ;
    PORT
      LAYER M4 ;
        RECT  104.004 21.84 104.088 21.864 ;
    END
  END b[404]
  PIN b[405]
    DIRECTION OUTPUT ;
    USE SIGNAL ;
    PORT
      LAYER M4 ;
        RECT  104.004 21.936 104.088 21.96 ;
    END
  END b[405]
  PIN b[406]
    DIRECTION OUTPUT ;
    USE SIGNAL ;
    PORT
      LAYER M4 ;
        RECT  104.004 22.032 104.088 22.056 ;
    END
  END b[406]
  PIN b[407]
    DIRECTION OUTPUT ;
    USE SIGNAL ;
    PORT
      LAYER M4 ;
        RECT  104.004 22.128 104.088 22.152 ;
    END
  END b[407]
  PIN b[408]
    DIRECTION OUTPUT ;
    USE SIGNAL ;
    PORT
      LAYER M4 ;
        RECT  104.004 22.224 104.088 22.248 ;
    END
  END b[408]
  PIN b[409]
    DIRECTION OUTPUT ;
    USE SIGNAL ;
    PORT
      LAYER M4 ;
        RECT  104.004 22.32 104.088 22.344 ;
    END
  END b[409]
  PIN b[40]
    DIRECTION OUTPUT ;
    USE SIGNAL ;
    PORT
      LAYER M4 ;
        RECT  104.004 49.104 104.088 49.128 ;
    END
  END b[40]
  PIN b[410]
    DIRECTION OUTPUT ;
    USE SIGNAL ;
    PORT
      LAYER M4 ;
        RECT  104.004 22.416 104.088 22.44 ;
    END
  END b[410]
  PIN b[411]
    DIRECTION OUTPUT ;
    USE SIGNAL ;
    PORT
      LAYER M4 ;
        RECT  104.004 22.512 104.088 22.536 ;
    END
  END b[411]
  PIN b[412]
    DIRECTION OUTPUT ;
    USE SIGNAL ;
    PORT
      LAYER M4 ;
        RECT  104.004 22.608 104.088 22.632 ;
    END
  END b[412]
  PIN b[413]
    DIRECTION OUTPUT ;
    USE SIGNAL ;
    PORT
      LAYER M4 ;
        RECT  104.004 22.704 104.088 22.728 ;
    END
  END b[413]
  PIN b[414]
    DIRECTION OUTPUT ;
    USE SIGNAL ;
    PORT
      LAYER M4 ;
        RECT  104.004 22.8 104.088 22.824 ;
    END
  END b[414]
  PIN b[415]
    DIRECTION OUTPUT ;
    USE SIGNAL ;
    PORT
      LAYER M4 ;
        RECT  104.004 22.896 104.088 22.92 ;
    END
  END b[415]
  PIN b[416]
    DIRECTION OUTPUT ;
    USE SIGNAL ;
    PORT
      LAYER M4 ;
        RECT  104.004 22.992 104.088 23.016 ;
    END
  END b[416]
  PIN b[417]
    DIRECTION OUTPUT ;
    USE SIGNAL ;
    PORT
      LAYER M4 ;
        RECT  104.004 23.088 104.088 23.112 ;
    END
  END b[417]
  PIN b[418]
    DIRECTION OUTPUT ;
    USE SIGNAL ;
    PORT
      LAYER M4 ;
        RECT  104.004 23.184 104.088 23.208 ;
    END
  END b[418]
  PIN b[419]
    DIRECTION OUTPUT ;
    USE SIGNAL ;
    PORT
      LAYER M4 ;
        RECT  104.004 23.28 104.088 23.304 ;
    END
  END b[419]
  PIN b[41]
    DIRECTION OUTPUT ;
    USE SIGNAL ;
    PORT
      LAYER M4 ;
        RECT  104.004 49.2 104.088 49.224 ;
    END
  END b[41]
  PIN b[420]
    DIRECTION OUTPUT ;
    USE SIGNAL ;
    PORT
      LAYER M4 ;
        RECT  104.004 23.376 104.088 23.4 ;
    END
  END b[420]
  PIN b[421]
    DIRECTION OUTPUT ;
    USE SIGNAL ;
    PORT
      LAYER M4 ;
        RECT  104.004 23.472 104.088 23.496 ;
    END
  END b[421]
  PIN b[422]
    DIRECTION OUTPUT ;
    USE SIGNAL ;
    PORT
      LAYER M4 ;
        RECT  104.004 23.568 104.088 23.592 ;
    END
  END b[422]
  PIN b[423]
    DIRECTION OUTPUT ;
    USE SIGNAL ;
    PORT
      LAYER M4 ;
        RECT  104.004 23.664 104.088 23.688 ;
    END
  END b[423]
  PIN b[424]
    DIRECTION OUTPUT ;
    USE SIGNAL ;
    PORT
      LAYER M4 ;
        RECT  104.004 23.76 104.088 23.784 ;
    END
  END b[424]
  PIN b[425]
    DIRECTION OUTPUT ;
    USE SIGNAL ;
    PORT
      LAYER M4 ;
        RECT  104.004 23.856 104.088 23.88 ;
    END
  END b[425]
  PIN b[426]
    DIRECTION OUTPUT ;
    USE SIGNAL ;
    PORT
      LAYER M4 ;
        RECT  104.004 23.952 104.088 23.976 ;
    END
  END b[426]
  PIN b[427]
    DIRECTION OUTPUT ;
    USE SIGNAL ;
    PORT
      LAYER M4 ;
        RECT  104.004 24.048 104.088 24.072 ;
    END
  END b[427]
  PIN b[428]
    DIRECTION OUTPUT ;
    USE SIGNAL ;
    PORT
      LAYER M4 ;
        RECT  104.004 24.144 104.088 24.168 ;
    END
  END b[428]
  PIN b[429]
    DIRECTION OUTPUT ;
    USE SIGNAL ;
    PORT
      LAYER M4 ;
        RECT  104.004 24.24 104.088 24.264 ;
    END
  END b[429]
  PIN b[42]
    DIRECTION OUTPUT ;
    USE SIGNAL ;
    PORT
      LAYER M4 ;
        RECT  104.004 49.296 104.088 49.32 ;
    END
  END b[42]
  PIN b[430]
    DIRECTION OUTPUT ;
    USE SIGNAL ;
    PORT
      LAYER M4 ;
        RECT  104.004 24.336 104.088 24.36 ;
    END
  END b[430]
  PIN b[431]
    DIRECTION OUTPUT ;
    USE SIGNAL ;
    PORT
      LAYER M4 ;
        RECT  104.004 24.432 104.088 24.456 ;
    END
  END b[431]
  PIN b[432]
    DIRECTION OUTPUT ;
    USE SIGNAL ;
    PORT
      LAYER M4 ;
        RECT  104.004 24.528 104.088 24.552 ;
    END
  END b[432]
  PIN b[433]
    DIRECTION OUTPUT ;
    USE SIGNAL ;
    PORT
      LAYER M4 ;
        RECT  104.004 24.624 104.088 24.648 ;
    END
  END b[433]
  PIN b[434]
    DIRECTION OUTPUT ;
    USE SIGNAL ;
    PORT
      LAYER M4 ;
        RECT  104.004 24.72 104.088 24.744 ;
    END
  END b[434]
  PIN b[435]
    DIRECTION OUTPUT ;
    USE SIGNAL ;
    PORT
      LAYER M4 ;
        RECT  104.004 24.816 104.088 24.84 ;
    END
  END b[435]
  PIN b[436]
    DIRECTION OUTPUT ;
    USE SIGNAL ;
    PORT
      LAYER M4 ;
        RECT  104.004 24.912 104.088 24.936 ;
    END
  END b[436]
  PIN b[437]
    DIRECTION OUTPUT ;
    USE SIGNAL ;
    PORT
      LAYER M4 ;
        RECT  104.004 25.008 104.088 25.032 ;
    END
  END b[437]
  PIN b[438]
    DIRECTION OUTPUT ;
    USE SIGNAL ;
    PORT
      LAYER M4 ;
        RECT  104.004 25.104 104.088 25.128 ;
    END
  END b[438]
  PIN b[439]
    DIRECTION OUTPUT ;
    USE SIGNAL ;
    PORT
      LAYER M4 ;
        RECT  104.004 25.2 104.088 25.224 ;
    END
  END b[439]
  PIN b[43]
    DIRECTION OUTPUT ;
    USE SIGNAL ;
    PORT
      LAYER M4 ;
        RECT  104.004 49.392 104.088 49.416 ;
    END
  END b[43]
  PIN b[440]
    DIRECTION OUTPUT ;
    USE SIGNAL ;
    PORT
      LAYER M4 ;
        RECT  104.004 25.296 104.088 25.32 ;
    END
  END b[440]
  PIN b[441]
    DIRECTION OUTPUT ;
    USE SIGNAL ;
    PORT
      LAYER M4 ;
        RECT  104.004 25.392 104.088 25.416 ;
    END
  END b[441]
  PIN b[442]
    DIRECTION OUTPUT ;
    USE SIGNAL ;
    PORT
      LAYER M4 ;
        RECT  104.004 25.488 104.088 25.512 ;
    END
  END b[442]
  PIN b[443]
    DIRECTION OUTPUT ;
    USE SIGNAL ;
    PORT
      LAYER M4 ;
        RECT  104.004 25.584 104.088 25.608 ;
    END
  END b[443]
  PIN b[444]
    DIRECTION OUTPUT ;
    USE SIGNAL ;
    PORT
      LAYER M4 ;
        RECT  104.004 25.68 104.088 25.704 ;
    END
  END b[444]
  PIN b[445]
    DIRECTION OUTPUT ;
    USE SIGNAL ;
    PORT
      LAYER M4 ;
        RECT  104.004 25.776 104.088 25.8 ;
    END
  END b[445]
  PIN b[446]
    DIRECTION OUTPUT ;
    USE SIGNAL ;
    PORT
      LAYER M4 ;
        RECT  104.004 25.872 104.088 25.896 ;
    END
  END b[446]
  PIN b[447]
    DIRECTION OUTPUT ;
    USE SIGNAL ;
    PORT
      LAYER M4 ;
        RECT  104.004 25.968 104.088 25.992 ;
    END
  END b[447]
  PIN b[448]
    DIRECTION OUTPUT ;
    USE SIGNAL ;
    PORT
      LAYER M4 ;
        RECT  104.004 26.064 104.088 26.088 ;
    END
  END b[448]
  PIN b[449]
    DIRECTION OUTPUT ;
    USE SIGNAL ;
    PORT
      LAYER M4 ;
        RECT  104.004 26.16 104.088 26.184 ;
    END
  END b[449]
  PIN b[44]
    DIRECTION OUTPUT ;
    USE SIGNAL ;
    PORT
      LAYER M4 ;
        RECT  104.004 49.488 104.088 49.512 ;
    END
  END b[44]
  PIN b[450]
    DIRECTION OUTPUT ;
    USE SIGNAL ;
    PORT
      LAYER M4 ;
        RECT  104.004 26.256 104.088 26.28 ;
    END
  END b[450]
  PIN b[451]
    DIRECTION OUTPUT ;
    USE SIGNAL ;
    PORT
      LAYER M4 ;
        RECT  104.004 26.352 104.088 26.376 ;
    END
  END b[451]
  PIN b[452]
    DIRECTION OUTPUT ;
    USE SIGNAL ;
    PORT
      LAYER M4 ;
        RECT  104.004 26.448 104.088 26.472 ;
    END
  END b[452]
  PIN b[453]
    DIRECTION OUTPUT ;
    USE SIGNAL ;
    PORT
      LAYER M4 ;
        RECT  104.004 26.544 104.088 26.568 ;
    END
  END b[453]
  PIN b[454]
    DIRECTION OUTPUT ;
    USE SIGNAL ;
    PORT
      LAYER M4 ;
        RECT  104.004 26.64 104.088 26.664 ;
    END
  END b[454]
  PIN b[455]
    DIRECTION OUTPUT ;
    USE SIGNAL ;
    PORT
      LAYER M4 ;
        RECT  104.004 26.736 104.088 26.76 ;
    END
  END b[455]
  PIN b[456]
    DIRECTION OUTPUT ;
    USE SIGNAL ;
    PORT
      LAYER M4 ;
        RECT  104.004 26.832 104.088 26.856 ;
    END
  END b[456]
  PIN b[457]
    DIRECTION OUTPUT ;
    USE SIGNAL ;
    PORT
      LAYER M4 ;
        RECT  104.004 26.928 104.088 26.952 ;
    END
  END b[457]
  PIN b[458]
    DIRECTION OUTPUT ;
    USE SIGNAL ;
    PORT
      LAYER M4 ;
        RECT  104.004 27.024 104.088 27.048 ;
    END
  END b[458]
  PIN b[459]
    DIRECTION OUTPUT ;
    USE SIGNAL ;
    PORT
      LAYER M4 ;
        RECT  104.004 27.12 104.088 27.144 ;
    END
  END b[459]
  PIN b[45]
    DIRECTION OUTPUT ;
    USE SIGNAL ;
    PORT
      LAYER M4 ;
        RECT  104.004 49.584 104.088 49.608 ;
    END
  END b[45]
  PIN b[460]
    DIRECTION OUTPUT ;
    USE SIGNAL ;
    PORT
      LAYER M4 ;
        RECT  104.004 27.216 104.088 27.24 ;
    END
  END b[460]
  PIN b[461]
    DIRECTION OUTPUT ;
    USE SIGNAL ;
    PORT
      LAYER M4 ;
        RECT  104.004 27.312 104.088 27.336 ;
    END
  END b[461]
  PIN b[462]
    DIRECTION OUTPUT ;
    USE SIGNAL ;
    PORT
      LAYER M4 ;
        RECT  104.004 27.408 104.088 27.432 ;
    END
  END b[462]
  PIN b[463]
    DIRECTION OUTPUT ;
    USE SIGNAL ;
    PORT
      LAYER M4 ;
        RECT  104.004 27.504 104.088 27.528 ;
    END
  END b[463]
  PIN b[464]
    DIRECTION OUTPUT ;
    USE SIGNAL ;
    PORT
      LAYER M4 ;
        RECT  104.004 27.6 104.088 27.624 ;
    END
  END b[464]
  PIN b[465]
    DIRECTION OUTPUT ;
    USE SIGNAL ;
    PORT
      LAYER M4 ;
        RECT  104.004 27.696 104.088 27.72 ;
    END
  END b[465]
  PIN b[466]
    DIRECTION OUTPUT ;
    USE SIGNAL ;
    PORT
      LAYER M4 ;
        RECT  104.004 27.792 104.088 27.816 ;
    END
  END b[466]
  PIN b[467]
    DIRECTION OUTPUT ;
    USE SIGNAL ;
    PORT
      LAYER M4 ;
        RECT  104.004 27.888 104.088 27.912 ;
    END
  END b[467]
  PIN b[468]
    DIRECTION OUTPUT ;
    USE SIGNAL ;
    PORT
      LAYER M4 ;
        RECT  104.004 27.984 104.088 28.008 ;
    END
  END b[468]
  PIN b[469]
    DIRECTION OUTPUT ;
    USE SIGNAL ;
    PORT
      LAYER M4 ;
        RECT  104.004 28.08 104.088 28.104 ;
    END
  END b[469]
  PIN b[46]
    DIRECTION OUTPUT ;
    USE SIGNAL ;
    PORT
      LAYER M4 ;
        RECT  104.004 49.68 104.088 49.704 ;
    END
  END b[46]
  PIN b[470]
    DIRECTION OUTPUT ;
    USE SIGNAL ;
    PORT
      LAYER M4 ;
        RECT  104.004 28.176 104.088 28.2 ;
    END
  END b[470]
  PIN b[471]
    DIRECTION OUTPUT ;
    USE SIGNAL ;
    PORT
      LAYER M4 ;
        RECT  104.004 28.272 104.088 28.296 ;
    END
  END b[471]
  PIN b[472]
    DIRECTION OUTPUT ;
    USE SIGNAL ;
    PORT
      LAYER M4 ;
        RECT  104.004 28.368 104.088 28.392 ;
    END
  END b[472]
  PIN b[473]
    DIRECTION OUTPUT ;
    USE SIGNAL ;
    PORT
      LAYER M4 ;
        RECT  104.004 28.464 104.088 28.488 ;
    END
  END b[473]
  PIN b[474]
    DIRECTION OUTPUT ;
    USE SIGNAL ;
    PORT
      LAYER M4 ;
        RECT  104.004 28.56 104.088 28.584 ;
    END
  END b[474]
  PIN b[475]
    DIRECTION OUTPUT ;
    USE SIGNAL ;
    PORT
      LAYER M4 ;
        RECT  104.004 28.656 104.088 28.68 ;
    END
  END b[475]
  PIN b[476]
    DIRECTION OUTPUT ;
    USE SIGNAL ;
    PORT
      LAYER M4 ;
        RECT  104.004 28.752 104.088 28.776 ;
    END
  END b[476]
  PIN b[477]
    DIRECTION OUTPUT ;
    USE SIGNAL ;
    PORT
      LAYER M4 ;
        RECT  104.004 28.848 104.088 28.872 ;
    END
  END b[477]
  PIN b[478]
    DIRECTION OUTPUT ;
    USE SIGNAL ;
    PORT
      LAYER M4 ;
        RECT  104.004 28.944 104.088 28.968 ;
    END
  END b[478]
  PIN b[479]
    DIRECTION OUTPUT ;
    USE SIGNAL ;
    PORT
      LAYER M4 ;
        RECT  104.004 29.04 104.088 29.064 ;
    END
  END b[479]
  PIN b[47]
    DIRECTION OUTPUT ;
    USE SIGNAL ;
    PORT
      LAYER M4 ;
        RECT  104.004 49.776 104.088 49.8 ;
    END
  END b[47]
  PIN b[480]
    DIRECTION OUTPUT ;
    USE SIGNAL ;
    PORT
      LAYER M4 ;
        RECT  104.004 29.136 104.088 29.16 ;
    END
  END b[480]
  PIN b[481]
    DIRECTION OUTPUT ;
    USE SIGNAL ;
    PORT
      LAYER M4 ;
        RECT  104.004 29.232 104.088 29.256 ;
    END
  END b[481]
  PIN b[482]
    DIRECTION OUTPUT ;
    USE SIGNAL ;
    PORT
      LAYER M4 ;
        RECT  104.004 29.328 104.088 29.352 ;
    END
  END b[482]
  PIN b[483]
    DIRECTION OUTPUT ;
    USE SIGNAL ;
    PORT
      LAYER M4 ;
        RECT  104.004 29.424 104.088 29.448 ;
    END
  END b[483]
  PIN b[484]
    DIRECTION OUTPUT ;
    USE SIGNAL ;
    PORT
      LAYER M4 ;
        RECT  104.004 29.52 104.088 29.544 ;
    END
  END b[484]
  PIN b[485]
    DIRECTION OUTPUT ;
    USE SIGNAL ;
    PORT
      LAYER M4 ;
        RECT  104.004 29.616 104.088 29.64 ;
    END
  END b[485]
  PIN b[486]
    DIRECTION OUTPUT ;
    USE SIGNAL ;
    PORT
      LAYER M4 ;
        RECT  104.004 29.712 104.088 29.736 ;
    END
  END b[486]
  PIN b[487]
    DIRECTION OUTPUT ;
    USE SIGNAL ;
    PORT
      LAYER M4 ;
        RECT  104.004 29.808 104.088 29.832 ;
    END
  END b[487]
  PIN b[488]
    DIRECTION OUTPUT ;
    USE SIGNAL ;
    PORT
      LAYER M4 ;
        RECT  104.004 29.904 104.088 29.928 ;
    END
  END b[488]
  PIN b[489]
    DIRECTION OUTPUT ;
    USE SIGNAL ;
    PORT
      LAYER M4 ;
        RECT  104.004 30 104.088 30.024 ;
    END
  END b[489]
  PIN b[48]
    DIRECTION OUTPUT ;
    USE SIGNAL ;
    PORT
      LAYER M4 ;
        RECT  104.004 49.872 104.088 49.896 ;
    END
  END b[48]
  PIN b[490]
    DIRECTION OUTPUT ;
    USE SIGNAL ;
    PORT
      LAYER M4 ;
        RECT  104.004 30.096 104.088 30.12 ;
    END
  END b[490]
  PIN b[491]
    DIRECTION OUTPUT ;
    USE SIGNAL ;
    PORT
      LAYER M4 ;
        RECT  104.004 30.192 104.088 30.216 ;
    END
  END b[491]
  PIN b[492]
    DIRECTION OUTPUT ;
    USE SIGNAL ;
    PORT
      LAYER M4 ;
        RECT  104.004 30.288 104.088 30.312 ;
    END
  END b[492]
  PIN b[493]
    DIRECTION OUTPUT ;
    USE SIGNAL ;
    PORT
      LAYER M4 ;
        RECT  104.004 30.384 104.088 30.408 ;
    END
  END b[493]
  PIN b[494]
    DIRECTION OUTPUT ;
    USE SIGNAL ;
    PORT
      LAYER M4 ;
        RECT  104.004 30.48 104.088 30.504 ;
    END
  END b[494]
  PIN b[495]
    DIRECTION OUTPUT ;
    USE SIGNAL ;
    PORT
      LAYER M4 ;
        RECT  104.004 30.576 104.088 30.6 ;
    END
  END b[495]
  PIN b[496]
    DIRECTION OUTPUT ;
    USE SIGNAL ;
    PORT
      LAYER M4 ;
        RECT  104.004 30.672 104.088 30.696 ;
    END
  END b[496]
  PIN b[497]
    DIRECTION OUTPUT ;
    USE SIGNAL ;
    PORT
      LAYER M4 ;
        RECT  104.004 30.768 104.088 30.792 ;
    END
  END b[497]
  PIN b[498]
    DIRECTION OUTPUT ;
    USE SIGNAL ;
    PORT
      LAYER M4 ;
        RECT  104.004 30.864 104.088 30.888 ;
    END
  END b[498]
  PIN b[499]
    DIRECTION OUTPUT ;
    USE SIGNAL ;
    PORT
      LAYER M4 ;
        RECT  104.004 30.96 104.088 30.984 ;
    END
  END b[499]
  PIN b[49]
    DIRECTION OUTPUT ;
    USE SIGNAL ;
    PORT
      LAYER M4 ;
        RECT  104.004 49.968 104.088 49.992 ;
    END
  END b[49]
  PIN b[4]
    DIRECTION OUTPUT ;
    USE SIGNAL ;
    PORT
      LAYER M4 ;
        RECT  104.004 42.576 104.088 42.6 ;
    END
  END b[4]
  PIN b[500]
    DIRECTION OUTPUT ;
    USE SIGNAL ;
    PORT
      LAYER M4 ;
        RECT  104.004 31.056 104.088 31.08 ;
    END
  END b[500]
  PIN b[501]
    DIRECTION OUTPUT ;
    USE SIGNAL ;
    PORT
      LAYER M4 ;
        RECT  104.004 31.152 104.088 31.176 ;
    END
  END b[501]
  PIN b[502]
    DIRECTION OUTPUT ;
    USE SIGNAL ;
    PORT
      LAYER M4 ;
        RECT  104.004 31.248 104.088 31.272 ;
    END
  END b[502]
  PIN b[503]
    DIRECTION OUTPUT ;
    USE SIGNAL ;
    PORT
      LAYER M4 ;
        RECT  104.004 31.344 104.088 31.368 ;
    END
  END b[503]
  PIN b[504]
    DIRECTION OUTPUT ;
    USE SIGNAL ;
    PORT
      LAYER M4 ;
        RECT  104.004 31.44 104.088 31.464 ;
    END
  END b[504]
  PIN b[505]
    DIRECTION OUTPUT ;
    USE SIGNAL ;
    PORT
      LAYER M4 ;
        RECT  104.004 31.536 104.088 31.56 ;
    END
  END b[505]
  PIN b[506]
    DIRECTION OUTPUT ;
    USE SIGNAL ;
    PORT
      LAYER M4 ;
        RECT  104.004 31.632 104.088 31.656 ;
    END
  END b[506]
  PIN b[507]
    DIRECTION OUTPUT ;
    USE SIGNAL ;
    PORT
      LAYER M4 ;
        RECT  104.004 31.728 104.088 31.752 ;
    END
  END b[507]
  PIN b[508]
    DIRECTION OUTPUT ;
    USE SIGNAL ;
    PORT
      LAYER M4 ;
        RECT  104.004 31.824 104.088 31.848 ;
    END
  END b[508]
  PIN b[509]
    DIRECTION OUTPUT ;
    USE SIGNAL ;
    PORT
      LAYER M4 ;
        RECT  104.004 31.92 104.088 31.944 ;
    END
  END b[509]
  PIN b[50]
    DIRECTION OUTPUT ;
    USE SIGNAL ;
    PORT
      LAYER M4 ;
        RECT  104.004 50.064 104.088 50.088 ;
    END
  END b[50]
  PIN b[510]
    DIRECTION OUTPUT ;
    USE SIGNAL ;
    PORT
      LAYER M4 ;
        RECT  104.004 32.016 104.088 32.04 ;
    END
  END b[510]
  PIN b[511]
    DIRECTION OUTPUT ;
    USE SIGNAL ;
    PORT
      LAYER M4 ;
        RECT  104.004 32.112 104.088 32.136 ;
    END
  END b[511]
  PIN b[512]
    DIRECTION OUTPUT ;
    USE SIGNAL ;
    PORT
      LAYER M4 ;
        RECT  104.004 32.208 104.088 32.232 ;
    END
  END b[512]
  PIN b[513]
    DIRECTION OUTPUT ;
    USE SIGNAL ;
    PORT
      LAYER M4 ;
        RECT  104.004 32.304 104.088 32.328 ;
    END
  END b[513]
  PIN b[514]
    DIRECTION OUTPUT ;
    USE SIGNAL ;
    PORT
      LAYER M4 ;
        RECT  104.004 32.4 104.088 32.424 ;
    END
  END b[514]
  PIN b[515]
    DIRECTION OUTPUT ;
    USE SIGNAL ;
    PORT
      LAYER M4 ;
        RECT  104.004 32.496 104.088 32.52 ;
    END
  END b[515]
  PIN b[516]
    DIRECTION OUTPUT ;
    USE SIGNAL ;
    PORT
      LAYER M4 ;
        RECT  104.004 32.592 104.088 32.616 ;
    END
  END b[516]
  PIN b[517]
    DIRECTION OUTPUT ;
    USE SIGNAL ;
    PORT
      LAYER M4 ;
        RECT  104.004 32.688 104.088 32.712 ;
    END
  END b[517]
  PIN b[518]
    DIRECTION OUTPUT ;
    USE SIGNAL ;
    PORT
      LAYER M4 ;
        RECT  104.004 32.784 104.088 32.808 ;
    END
  END b[518]
  PIN b[519]
    DIRECTION OUTPUT ;
    USE SIGNAL ;
    PORT
      LAYER M4 ;
        RECT  104.004 32.88 104.088 32.904 ;
    END
  END b[519]
  PIN b[51]
    DIRECTION OUTPUT ;
    USE SIGNAL ;
    PORT
      LAYER M4 ;
        RECT  104.004 50.16 104.088 50.184 ;
    END
  END b[51]
  PIN b[520]
    DIRECTION OUTPUT ;
    USE SIGNAL ;
    PORT
      LAYER M4 ;
        RECT  104.004 32.976 104.088 33 ;
    END
  END b[520]
  PIN b[521]
    DIRECTION OUTPUT ;
    USE SIGNAL ;
    PORT
      LAYER M4 ;
        RECT  104.004 33.072 104.088 33.096 ;
    END
  END b[521]
  PIN b[522]
    DIRECTION OUTPUT ;
    USE SIGNAL ;
    PORT
      LAYER M4 ;
        RECT  104.004 33.168 104.088 33.192 ;
    END
  END b[522]
  PIN b[523]
    DIRECTION OUTPUT ;
    USE SIGNAL ;
    PORT
      LAYER M4 ;
        RECT  104.004 33.264 104.088 33.288 ;
    END
  END b[523]
  PIN b[524]
    DIRECTION OUTPUT ;
    USE SIGNAL ;
    PORT
      LAYER M4 ;
        RECT  104.004 33.36 104.088 33.384 ;
    END
  END b[524]
  PIN b[525]
    DIRECTION OUTPUT ;
    USE SIGNAL ;
    PORT
      LAYER M4 ;
        RECT  104.004 33.456 104.088 33.48 ;
    END
  END b[525]
  PIN b[526]
    DIRECTION OUTPUT ;
    USE SIGNAL ;
    PORT
      LAYER M4 ;
        RECT  104.004 33.552 104.088 33.576 ;
    END
  END b[526]
  PIN b[527]
    DIRECTION OUTPUT ;
    USE SIGNAL ;
    PORT
      LAYER M4 ;
        RECT  104.004 33.648 104.088 33.672 ;
    END
  END b[527]
  PIN b[528]
    DIRECTION OUTPUT ;
    USE SIGNAL ;
    PORT
      LAYER M4 ;
        RECT  104.004 33.744 104.088 33.768 ;
    END
  END b[528]
  PIN b[529]
    DIRECTION OUTPUT ;
    USE SIGNAL ;
    PORT
      LAYER M4 ;
        RECT  104.004 33.84 104.088 33.864 ;
    END
  END b[529]
  PIN b[52]
    DIRECTION OUTPUT ;
    USE SIGNAL ;
    PORT
      LAYER M4 ;
        RECT  104.004 50.256 104.088 50.28 ;
    END
  END b[52]
  PIN b[530]
    DIRECTION OUTPUT ;
    USE SIGNAL ;
    PORT
      LAYER M4 ;
        RECT  104.004 33.936 104.088 33.96 ;
    END
  END b[530]
  PIN b[531]
    DIRECTION OUTPUT ;
    USE SIGNAL ;
    PORT
      LAYER M4 ;
        RECT  104.004 34.032 104.088 34.056 ;
    END
  END b[531]
  PIN b[532]
    DIRECTION OUTPUT ;
    USE SIGNAL ;
    PORT
      LAYER M4 ;
        RECT  104.004 34.128 104.088 34.152 ;
    END
  END b[532]
  PIN b[533]
    DIRECTION OUTPUT ;
    USE SIGNAL ;
    PORT
      LAYER M4 ;
        RECT  104.004 34.224 104.088 34.248 ;
    END
  END b[533]
  PIN b[534]
    DIRECTION OUTPUT ;
    USE SIGNAL ;
    PORT
      LAYER M4 ;
        RECT  104.004 34.32 104.088 34.344 ;
    END
  END b[534]
  PIN b[535]
    DIRECTION OUTPUT ;
    USE SIGNAL ;
    PORT
      LAYER M4 ;
        RECT  104.004 34.416 104.088 34.44 ;
    END
  END b[535]
  PIN b[536]
    DIRECTION OUTPUT ;
    USE SIGNAL ;
    PORT
      LAYER M4 ;
        RECT  104.004 34.512 104.088 34.536 ;
    END
  END b[536]
  PIN b[537]
    DIRECTION OUTPUT ;
    USE SIGNAL ;
    PORT
      LAYER M4 ;
        RECT  104.004 34.608 104.088 34.632 ;
    END
  END b[537]
  PIN b[538]
    DIRECTION OUTPUT ;
    USE SIGNAL ;
    PORT
      LAYER M4 ;
        RECT  104.004 34.704 104.088 34.728 ;
    END
  END b[538]
  PIN b[539]
    DIRECTION OUTPUT ;
    USE SIGNAL ;
    PORT
      LAYER M4 ;
        RECT  104.004 34.8 104.088 34.824 ;
    END
  END b[539]
  PIN b[53]
    DIRECTION OUTPUT ;
    USE SIGNAL ;
    PORT
      LAYER M4 ;
        RECT  104.004 50.352 104.088 50.376 ;
    END
  END b[53]
  PIN b[540]
    DIRECTION OUTPUT ;
    USE SIGNAL ;
    PORT
      LAYER M4 ;
        RECT  104.004 34.896 104.088 34.92 ;
    END
  END b[540]
  PIN b[541]
    DIRECTION OUTPUT ;
    USE SIGNAL ;
    PORT
      LAYER M4 ;
        RECT  104.004 34.992 104.088 35.016 ;
    END
  END b[541]
  PIN b[542]
    DIRECTION OUTPUT ;
    USE SIGNAL ;
    PORT
      LAYER M4 ;
        RECT  104.004 35.088 104.088 35.112 ;
    END
  END b[542]
  PIN b[543]
    DIRECTION OUTPUT ;
    USE SIGNAL ;
    PORT
      LAYER M4 ;
        RECT  104.004 35.184 104.088 35.208 ;
    END
  END b[543]
  PIN b[544]
    DIRECTION OUTPUT ;
    USE SIGNAL ;
    PORT
      LAYER M4 ;
        RECT  104.004 35.28 104.088 35.304 ;
    END
  END b[544]
  PIN b[545]
    DIRECTION OUTPUT ;
    USE SIGNAL ;
    PORT
      LAYER M4 ;
        RECT  104.004 35.376 104.088 35.4 ;
    END
  END b[545]
  PIN b[546]
    DIRECTION OUTPUT ;
    USE SIGNAL ;
    PORT
      LAYER M4 ;
        RECT  104.004 35.472 104.088 35.496 ;
    END
  END b[546]
  PIN b[547]
    DIRECTION OUTPUT ;
    USE SIGNAL ;
    PORT
      LAYER M4 ;
        RECT  104.004 35.568 104.088 35.592 ;
    END
  END b[547]
  PIN b[548]
    DIRECTION OUTPUT ;
    USE SIGNAL ;
    PORT
      LAYER M4 ;
        RECT  104.004 35.664 104.088 35.688 ;
    END
  END b[548]
  PIN b[549]
    DIRECTION OUTPUT ;
    USE SIGNAL ;
    PORT
      LAYER M4 ;
        RECT  104.004 35.76 104.088 35.784 ;
    END
  END b[549]
  PIN b[54]
    DIRECTION OUTPUT ;
    USE SIGNAL ;
    PORT
      LAYER M4 ;
        RECT  104.004 50.448 104.088 50.472 ;
    END
  END b[54]
  PIN b[550]
    DIRECTION OUTPUT ;
    USE SIGNAL ;
    PORT
      LAYER M4 ;
        RECT  104.004 35.856 104.088 35.88 ;
    END
  END b[550]
  PIN b[551]
    DIRECTION OUTPUT ;
    USE SIGNAL ;
    PORT
      LAYER M4 ;
        RECT  104.004 35.952 104.088 35.976 ;
    END
  END b[551]
  PIN b[552]
    DIRECTION OUTPUT ;
    USE SIGNAL ;
    PORT
      LAYER M4 ;
        RECT  104.004 36.048 104.088 36.072 ;
    END
  END b[552]
  PIN b[553]
    DIRECTION OUTPUT ;
    USE SIGNAL ;
    PORT
      LAYER M4 ;
        RECT  104.004 36.144 104.088 36.168 ;
    END
  END b[553]
  PIN b[554]
    DIRECTION OUTPUT ;
    USE SIGNAL ;
    PORT
      LAYER M4 ;
        RECT  104.004 36.24 104.088 36.264 ;
    END
  END b[554]
  PIN b[555]
    DIRECTION OUTPUT ;
    USE SIGNAL ;
    PORT
      LAYER M4 ;
        RECT  104.004 36.336 104.088 36.36 ;
    END
  END b[555]
  PIN b[556]
    DIRECTION OUTPUT ;
    USE SIGNAL ;
    PORT
      LAYER M4 ;
        RECT  104.004 36.432 104.088 36.456 ;
    END
  END b[556]
  PIN b[557]
    DIRECTION OUTPUT ;
    USE SIGNAL ;
    PORT
      LAYER M4 ;
        RECT  104.004 36.528 104.088 36.552 ;
    END
  END b[557]
  PIN b[558]
    DIRECTION OUTPUT ;
    USE SIGNAL ;
    PORT
      LAYER M4 ;
        RECT  104.004 36.624 104.088 36.648 ;
    END
  END b[558]
  PIN b[559]
    DIRECTION OUTPUT ;
    USE SIGNAL ;
    PORT
      LAYER M4 ;
        RECT  104.004 36.72 104.088 36.744 ;
    END
  END b[559]
  PIN b[55]
    DIRECTION OUTPUT ;
    USE SIGNAL ;
    PORT
      LAYER M4 ;
        RECT  104.004 50.544 104.088 50.568 ;
    END
  END b[55]
  PIN b[560]
    DIRECTION OUTPUT ;
    USE SIGNAL ;
    PORT
      LAYER M4 ;
        RECT  104.004 36.816 104.088 36.84 ;
    END
  END b[560]
  PIN b[561]
    DIRECTION OUTPUT ;
    USE SIGNAL ;
    PORT
      LAYER M4 ;
        RECT  104.004 36.912 104.088 36.936 ;
    END
  END b[561]
  PIN b[562]
    DIRECTION OUTPUT ;
    USE SIGNAL ;
    PORT
      LAYER M4 ;
        RECT  104.004 37.008 104.088 37.032 ;
    END
  END b[562]
  PIN b[563]
    DIRECTION OUTPUT ;
    USE SIGNAL ;
    PORT
      LAYER M4 ;
        RECT  104.004 37.104 104.088 37.128 ;
    END
  END b[563]
  PIN b[564]
    DIRECTION OUTPUT ;
    USE SIGNAL ;
    PORT
      LAYER M4 ;
        RECT  104.004 37.2 104.088 37.224 ;
    END
  END b[564]
  PIN b[565]
    DIRECTION OUTPUT ;
    USE SIGNAL ;
    PORT
      LAYER M4 ;
        RECT  104.004 37.296 104.088 37.32 ;
    END
  END b[565]
  PIN b[566]
    DIRECTION OUTPUT ;
    USE SIGNAL ;
    PORT
      LAYER M4 ;
        RECT  104.004 37.392 104.088 37.416 ;
    END
  END b[566]
  PIN b[567]
    DIRECTION OUTPUT ;
    USE SIGNAL ;
    PORT
      LAYER M4 ;
        RECT  104.004 37.488 104.088 37.512 ;
    END
  END b[567]
  PIN b[568]
    DIRECTION OUTPUT ;
    USE SIGNAL ;
    PORT
      LAYER M4 ;
        RECT  104.004 37.584 104.088 37.608 ;
    END
  END b[568]
  PIN b[569]
    DIRECTION OUTPUT ;
    USE SIGNAL ;
    PORT
      LAYER M4 ;
        RECT  104.004 37.68 104.088 37.704 ;
    END
  END b[569]
  PIN b[56]
    DIRECTION OUTPUT ;
    USE SIGNAL ;
    PORT
      LAYER M4 ;
        RECT  104.004 50.64 104.088 50.664 ;
    END
  END b[56]
  PIN b[570]
    DIRECTION OUTPUT ;
    USE SIGNAL ;
    PORT
      LAYER M4 ;
        RECT  104.004 37.776 104.088 37.8 ;
    END
  END b[570]
  PIN b[571]
    DIRECTION OUTPUT ;
    USE SIGNAL ;
    PORT
      LAYER M4 ;
        RECT  104.004 37.872 104.088 37.896 ;
    END
  END b[571]
  PIN b[572]
    DIRECTION OUTPUT ;
    USE SIGNAL ;
    PORT
      LAYER M4 ;
        RECT  104.004 37.968 104.088 37.992 ;
    END
  END b[572]
  PIN b[573]
    DIRECTION OUTPUT ;
    USE SIGNAL ;
    PORT
      LAYER M4 ;
        RECT  104.004 38.064 104.088 38.088 ;
    END
  END b[573]
  PIN b[574]
    DIRECTION OUTPUT ;
    USE SIGNAL ;
    PORT
      LAYER M4 ;
        RECT  104.004 38.16 104.088 38.184 ;
    END
  END b[574]
  PIN b[575]
    DIRECTION OUTPUT ;
    USE SIGNAL ;
    PORT
      LAYER M4 ;
        RECT  104.004 38.256 104.088 38.28 ;
    END
  END b[575]
  PIN b[576]
    DIRECTION OUTPUT ;
    USE SIGNAL ;
    PORT
      LAYER M4 ;
        RECT  104.004 77.52 104.088 77.544 ;
    END
  END b[576]
  PIN b[577]
    DIRECTION OUTPUT ;
    USE SIGNAL ;
    PORT
      LAYER M4 ;
        RECT  104.004 77.616 104.088 77.64 ;
    END
  END b[577]
  PIN b[578]
    DIRECTION OUTPUT ;
    USE SIGNAL ;
    PORT
      LAYER M4 ;
        RECT  104.004 77.712 104.088 77.736 ;
    END
  END b[578]
  PIN b[579]
    DIRECTION OUTPUT ;
    USE SIGNAL ;
    PORT
      LAYER M4 ;
        RECT  104.004 77.808 104.088 77.832 ;
    END
  END b[579]
  PIN b[57]
    DIRECTION OUTPUT ;
    USE SIGNAL ;
    PORT
      LAYER M4 ;
        RECT  104.004 50.736 104.088 50.76 ;
    END
  END b[57]
  PIN b[580]
    DIRECTION OUTPUT ;
    USE SIGNAL ;
    PORT
      LAYER M4 ;
        RECT  104.004 77.904 104.088 77.928 ;
    END
  END b[580]
  PIN b[581]
    DIRECTION OUTPUT ;
    USE SIGNAL ;
    PORT
      LAYER M4 ;
        RECT  104.004 78 104.088 78.024 ;
    END
  END b[581]
  PIN b[582]
    DIRECTION OUTPUT ;
    USE SIGNAL ;
    PORT
      LAYER M4 ;
        RECT  104.004 78.096 104.088 78.12 ;
    END
  END b[582]
  PIN b[583]
    DIRECTION OUTPUT ;
    USE SIGNAL ;
    PORT
      LAYER M4 ;
        RECT  104.004 78.192 104.088 78.216 ;
    END
  END b[583]
  PIN b[584]
    DIRECTION OUTPUT ;
    USE SIGNAL ;
    PORT
      LAYER M4 ;
        RECT  104.004 78.288 104.088 78.312 ;
    END
  END b[584]
  PIN b[585]
    DIRECTION OUTPUT ;
    USE SIGNAL ;
    PORT
      LAYER M4 ;
        RECT  104.004 78.384 104.088 78.408 ;
    END
  END b[585]
  PIN b[586]
    DIRECTION OUTPUT ;
    USE SIGNAL ;
    PORT
      LAYER M4 ;
        RECT  104.004 78.48 104.088 78.504 ;
    END
  END b[586]
  PIN b[587]
    DIRECTION OUTPUT ;
    USE SIGNAL ;
    PORT
      LAYER M4 ;
        RECT  104.004 78.576 104.088 78.6 ;
    END
  END b[587]
  PIN b[588]
    DIRECTION OUTPUT ;
    USE SIGNAL ;
    PORT
      LAYER M4 ;
        RECT  104.004 78.672 104.088 78.696 ;
    END
  END b[588]
  PIN b[589]
    DIRECTION OUTPUT ;
    USE SIGNAL ;
    PORT
      LAYER M4 ;
        RECT  104.004 78.768 104.088 78.792 ;
    END
  END b[589]
  PIN b[58]
    DIRECTION OUTPUT ;
    USE SIGNAL ;
    PORT
      LAYER M4 ;
        RECT  104.004 50.832 104.088 50.856 ;
    END
  END b[58]
  PIN b[590]
    DIRECTION OUTPUT ;
    USE SIGNAL ;
    PORT
      LAYER M4 ;
        RECT  104.004 78.864 104.088 78.888 ;
    END
  END b[590]
  PIN b[591]
    DIRECTION OUTPUT ;
    USE SIGNAL ;
    PORT
      LAYER M4 ;
        RECT  104.004 78.96 104.088 78.984 ;
    END
  END b[591]
  PIN b[592]
    DIRECTION OUTPUT ;
    USE SIGNAL ;
    PORT
      LAYER M4 ;
        RECT  104.004 79.056 104.088 79.08 ;
    END
  END b[592]
  PIN b[593]
    DIRECTION OUTPUT ;
    USE SIGNAL ;
    PORT
      LAYER M4 ;
        RECT  104.004 79.152 104.088 79.176 ;
    END
  END b[593]
  PIN b[594]
    DIRECTION OUTPUT ;
    USE SIGNAL ;
    PORT
      LAYER M4 ;
        RECT  104.004 79.248 104.088 79.272 ;
    END
  END b[594]
  PIN b[595]
    DIRECTION OUTPUT ;
    USE SIGNAL ;
    PORT
      LAYER M4 ;
        RECT  104.004 79.344 104.088 79.368 ;
    END
  END b[595]
  PIN b[596]
    DIRECTION OUTPUT ;
    USE SIGNAL ;
    PORT
      LAYER M4 ;
        RECT  104.004 79.44 104.088 79.464 ;
    END
  END b[596]
  PIN b[597]
    DIRECTION OUTPUT ;
    USE SIGNAL ;
    PORT
      LAYER M4 ;
        RECT  104.004 79.536 104.088 79.56 ;
    END
  END b[597]
  PIN b[598]
    DIRECTION OUTPUT ;
    USE SIGNAL ;
    PORT
      LAYER M4 ;
        RECT  104.004 79.632 104.088 79.656 ;
    END
  END b[598]
  PIN b[599]
    DIRECTION OUTPUT ;
    USE SIGNAL ;
    PORT
      LAYER M4 ;
        RECT  104.004 79.728 104.088 79.752 ;
    END
  END b[599]
  PIN b[59]
    DIRECTION OUTPUT ;
    USE SIGNAL ;
    PORT
      LAYER M4 ;
        RECT  104.004 50.928 104.088 50.952 ;
    END
  END b[59]
  PIN b[5]
    DIRECTION OUTPUT ;
    USE SIGNAL ;
    PORT
      LAYER M4 ;
        RECT  104.004 42.672 104.088 42.696 ;
    END
  END b[5]
  PIN b[60]
    DIRECTION OUTPUT ;
    USE SIGNAL ;
    PORT
      LAYER M4 ;
        RECT  104.004 51.024 104.088 51.048 ;
    END
  END b[60]
  PIN b[61]
    DIRECTION OUTPUT ;
    USE SIGNAL ;
    PORT
      LAYER M4 ;
        RECT  104.004 51.12 104.088 51.144 ;
    END
  END b[61]
  PIN b[62]
    DIRECTION OUTPUT ;
    USE SIGNAL ;
    PORT
      LAYER M4 ;
        RECT  104.004 51.216 104.088 51.24 ;
    END
  END b[62]
  PIN b[63]
    DIRECTION OUTPUT ;
    USE SIGNAL ;
    PORT
      LAYER M4 ;
        RECT  104.004 51.312 104.088 51.336 ;
    END
  END b[63]
  PIN b[64]
    DIRECTION OUTPUT ;
    USE SIGNAL ;
    PORT
      LAYER M4 ;
        RECT  104.004 39.12 104.088 39.144 ;
    END
  END b[64]
  PIN b[65]
    DIRECTION OUTPUT ;
    USE SIGNAL ;
    PORT
      LAYER M4 ;
        RECT  104.004 39.216 104.088 39.24 ;
    END
  END b[65]
  PIN b[66]
    DIRECTION OUTPUT ;
    USE SIGNAL ;
    PORT
      LAYER M4 ;
        RECT  104.004 39.312 104.088 39.336 ;
    END
  END b[66]
  PIN b[67]
    DIRECTION OUTPUT ;
    USE SIGNAL ;
    PORT
      LAYER M4 ;
        RECT  104.004 39.408 104.088 39.432 ;
    END
  END b[67]
  PIN b[68]
    DIRECTION OUTPUT ;
    USE SIGNAL ;
    PORT
      LAYER M4 ;
        RECT  104.004 39.504 104.088 39.528 ;
    END
  END b[68]
  PIN b[69]
    DIRECTION OUTPUT ;
    USE SIGNAL ;
    PORT
      LAYER M4 ;
        RECT  104.004 39.6 104.088 39.624 ;
    END
  END b[69]
  PIN b[6]
    DIRECTION OUTPUT ;
    USE SIGNAL ;
    PORT
      LAYER M4 ;
        RECT  104.004 42.768 104.088 42.792 ;
    END
  END b[6]
  PIN b[70]
    DIRECTION OUTPUT ;
    USE SIGNAL ;
    PORT
      LAYER M4 ;
        RECT  104.004 39.696 104.088 39.72 ;
    END
  END b[70]
  PIN b[71]
    DIRECTION OUTPUT ;
    USE SIGNAL ;
    PORT
      LAYER M4 ;
        RECT  104.004 39.792 104.088 39.816 ;
    END
  END b[71]
  PIN b[72]
    DIRECTION OUTPUT ;
    USE SIGNAL ;
    PORT
      LAYER M4 ;
        RECT  104.004 39.888 104.088 39.912 ;
    END
  END b[72]
  PIN b[73]
    DIRECTION OUTPUT ;
    USE SIGNAL ;
    PORT
      LAYER M4 ;
        RECT  104.004 39.984 104.088 40.008 ;
    END
  END b[73]
  PIN b[74]
    DIRECTION OUTPUT ;
    USE SIGNAL ;
    PORT
      LAYER M4 ;
        RECT  104.004 40.08 104.088 40.104 ;
    END
  END b[74]
  PIN b[75]
    DIRECTION OUTPUT ;
    USE SIGNAL ;
    PORT
      LAYER M4 ;
        RECT  104.004 40.176 104.088 40.2 ;
    END
  END b[75]
  PIN b[76]
    DIRECTION OUTPUT ;
    USE SIGNAL ;
    PORT
      LAYER M4 ;
        RECT  104.004 40.272 104.088 40.296 ;
    END
  END b[76]
  PIN b[77]
    DIRECTION OUTPUT ;
    USE SIGNAL ;
    PORT
      LAYER M4 ;
        RECT  104.004 40.368 104.088 40.392 ;
    END
  END b[77]
  PIN b[78]
    DIRECTION OUTPUT ;
    USE SIGNAL ;
    PORT
      LAYER M4 ;
        RECT  104.004 40.464 104.088 40.488 ;
    END
  END b[78]
  PIN b[79]
    DIRECTION OUTPUT ;
    USE SIGNAL ;
    PORT
      LAYER M4 ;
        RECT  104.004 40.56 104.088 40.584 ;
    END
  END b[79]
  PIN b[7]
    DIRECTION OUTPUT ;
    USE SIGNAL ;
    PORT
      LAYER M4 ;
        RECT  104.004 42.864 104.088 42.888 ;
    END
  END b[7]
  PIN b[80]
    DIRECTION OUTPUT ;
    USE SIGNAL ;
    PORT
      LAYER M4 ;
        RECT  104.004 40.656 104.088 40.68 ;
    END
  END b[80]
  PIN b[81]
    DIRECTION OUTPUT ;
    USE SIGNAL ;
    PORT
      LAYER M4 ;
        RECT  104.004 40.752 104.088 40.776 ;
    END
  END b[81]
  PIN b[82]
    DIRECTION OUTPUT ;
    USE SIGNAL ;
    PORT
      LAYER M4 ;
        RECT  104.004 40.848 104.088 40.872 ;
    END
  END b[82]
  PIN b[83]
    DIRECTION OUTPUT ;
    USE SIGNAL ;
    PORT
      LAYER M4 ;
        RECT  104.004 40.944 104.088 40.968 ;
    END
  END b[83]
  PIN b[84]
    DIRECTION OUTPUT ;
    USE SIGNAL ;
    PORT
      LAYER M4 ;
        RECT  104.004 41.04 104.088 41.064 ;
    END
  END b[84]
  PIN b[85]
    DIRECTION OUTPUT ;
    USE SIGNAL ;
    PORT
      LAYER M4 ;
        RECT  104.004 41.136 104.088 41.16 ;
    END
  END b[85]
  PIN b[86]
    DIRECTION OUTPUT ;
    USE SIGNAL ;
    PORT
      LAYER M4 ;
        RECT  104.004 41.232 104.088 41.256 ;
    END
  END b[86]
  PIN b[87]
    DIRECTION OUTPUT ;
    USE SIGNAL ;
    PORT
      LAYER M4 ;
        RECT  104.004 41.328 104.088 41.352 ;
    END
  END b[87]
  PIN b[88]
    DIRECTION OUTPUT ;
    USE SIGNAL ;
    PORT
      LAYER M4 ;
        RECT  104.004 41.424 104.088 41.448 ;
    END
  END b[88]
  PIN b[89]
    DIRECTION OUTPUT ;
    USE SIGNAL ;
    PORT
      LAYER M4 ;
        RECT  104.004 41.52 104.088 41.544 ;
    END
  END b[89]
  PIN b[8]
    DIRECTION OUTPUT ;
    USE SIGNAL ;
    PORT
      LAYER M4 ;
        RECT  104.004 42.96 104.088 42.984 ;
    END
  END b[8]
  PIN b[90]
    DIRECTION OUTPUT ;
    USE SIGNAL ;
    PORT
      LAYER M4 ;
        RECT  104.004 41.616 104.088 41.64 ;
    END
  END b[90]
  PIN b[91]
    DIRECTION OUTPUT ;
    USE SIGNAL ;
    PORT
      LAYER M4 ;
        RECT  104.004 41.712 104.088 41.736 ;
    END
  END b[91]
  PIN b[92]
    DIRECTION OUTPUT ;
    USE SIGNAL ;
    PORT
      LAYER M4 ;
        RECT  104.004 41.808 104.088 41.832 ;
    END
  END b[92]
  PIN b[93]
    DIRECTION OUTPUT ;
    USE SIGNAL ;
    PORT
      LAYER M4 ;
        RECT  104.004 41.904 104.088 41.928 ;
    END
  END b[93]
  PIN b[94]
    DIRECTION OUTPUT ;
    USE SIGNAL ;
    PORT
      LAYER M4 ;
        RECT  104.004 42 104.088 42.024 ;
    END
  END b[94]
  PIN b[95]
    DIRECTION OUTPUT ;
    USE SIGNAL ;
    PORT
      LAYER M4 ;
        RECT  104.004 42.096 104.088 42.12 ;
    END
  END b[95]
  PIN b[96]
    DIRECTION OUTPUT ;
    USE SIGNAL ;
    PORT
      LAYER M4 ;
        RECT  104.004 45.264 104.088 45.288 ;
    END
  END b[96]
  PIN b[97]
    DIRECTION OUTPUT ;
    USE SIGNAL ;
    PORT
      LAYER M4 ;
        RECT  104.004 45.36 104.088 45.384 ;
    END
  END b[97]
  PIN b[98]
    DIRECTION OUTPUT ;
    USE SIGNAL ;
    PORT
      LAYER M4 ;
        RECT  104.004 45.456 104.088 45.48 ;
    END
  END b[98]
  PIN b[99]
    DIRECTION OUTPUT ;
    USE SIGNAL ;
    PORT
      LAYER M4 ;
        RECT  104.004 45.552 104.088 45.576 ;
    END
  END b[99]
  PIN b[9]
    DIRECTION OUTPUT ;
    USE SIGNAL ;
    PORT
      LAYER M4 ;
        RECT  104.004 43.056 104.088 43.08 ;
    END
  END b[9]
  PIN ck_o
    DIRECTION OUTPUT ;
    USE SIGNAL ;
    PORT
      LAYER M4 ;
        RECT  0 52.752 0.084 52.776 ;
    END
  END ck_o
  PIN ckf
    DIRECTION INPUT ;
    USE SIGNAL ;
    PORT
      LAYER M4 ;
        RECT  0 52.848 0.084 52.872 ;
    END
  END ckf
  PIN ea
    DIRECTION INPUT ;
    USE SIGNAL ;
    PORT
      LAYER M5 ;
        RECT  45.744 105.732 45.768 105.816 ;
    END
  END ea
  PIN eb
    DIRECTION OUTPUT ;
    USE SIGNAL ;
    PORT
      LAYER M4 ;
        RECT  104.004 79.824 104.088 79.848 ;
    END
  END eb
  PIN VDD
    DIRECTION INOUT ;
    USE POWER ;
    PORT
      LAYER M5 ;
        RECT  99.792 2.151 99.912 103.433 ;
        RECT  97.092 2.151 97.212 103.433 ;
        RECT  94.392 2.151 94.512 103.433 ;
        RECT  91.692 2.151 91.812 103.433 ;
        RECT  88.992 2.151 89.112 103.433 ;
        RECT  86.292 2.151 86.412 103.433 ;
        RECT  83.592 2.151 83.712 103.433 ;
        RECT  80.892 2.151 81.012 103.433 ;
        RECT  78.192 2.151 78.312 103.433 ;
        RECT  75.492 2.151 75.612 103.433 ;
        RECT  72.792 2.151 72.912 103.433 ;
        RECT  70.092 2.151 70.212 103.433 ;
        RECT  67.392 2.151 67.512 103.433 ;
        RECT  64.692 2.151 64.812 103.433 ;
        RECT  61.992 2.151 62.112 103.433 ;
        RECT  59.292 2.151 59.412 103.433 ;
        RECT  56.592 2.151 56.712 103.433 ;
        RECT  53.892 2.151 54.012 103.433 ;
        RECT  51.192 2.151 51.312 103.433 ;
        RECT  48.492 2.151 48.612 103.433 ;
        RECT  45.792 2.151 45.912 103.433 ;
        RECT  43.092 2.151 43.212 103.433 ;
        RECT  40.392 2.151 40.512 103.433 ;
        RECT  37.692 2.151 37.812 103.433 ;
        RECT  34.992 2.151 35.112 103.433 ;
        RECT  32.292 2.151 32.412 103.433 ;
        RECT  29.592 2.151 29.712 103.433 ;
        RECT  26.892 2.151 27.012 103.433 ;
        RECT  24.192 2.151 24.312 103.433 ;
        RECT  21.492 2.151 21.612 103.433 ;
        RECT  18.792 2.151 18.912 103.433 ;
        RECT  16.092 2.151 16.212 103.433 ;
        RECT  13.392 2.151 13.512 103.433 ;
        RECT  10.692 2.151 10.812 103.433 ;
        RECT  7.992 2.151 8.112 103.433 ;
        RECT  5.292 2.151 5.412 103.433 ;
        RECT  2.592 2.151 2.712 103.433 ;
    END
  END VDD
  PIN VSS
    DIRECTION INOUT ;
    USE GROUND ;
    PORT
      LAYER M5 ;
        RECT  99.6 2.137 99.72 103.419 ;
        RECT  96.9 2.137 97.02 103.419 ;
        RECT  94.2 2.137 94.32 103.419 ;
        RECT  91.5 2.137 91.62 103.419 ;
        RECT  88.8 2.137 88.92 103.419 ;
        RECT  86.1 2.137 86.22 103.419 ;
        RECT  83.4 2.137 83.52 103.419 ;
        RECT  80.7 2.137 80.82 103.419 ;
        RECT  78 2.137 78.12 103.419 ;
        RECT  75.3 2.137 75.42 103.419 ;
        RECT  72.6 2.137 72.72 103.419 ;
        RECT  69.9 2.137 70.02 103.419 ;
        RECT  67.2 2.137 67.32 103.419 ;
        RECT  64.5 2.137 64.62 103.419 ;
        RECT  61.8 2.137 61.92 103.419 ;
        RECT  59.1 2.137 59.22 103.419 ;
        RECT  56.4 2.137 56.52 103.419 ;
        RECT  53.7 2.137 53.82 103.419 ;
        RECT  51 2.137 51.12 103.419 ;
        RECT  48.3 2.137 48.42 103.419 ;
        RECT  45.6 2.137 45.72 103.419 ;
        RECT  42.9 2.137 43.02 103.419 ;
        RECT  40.2 2.137 40.32 103.419 ;
        RECT  37.5 2.137 37.62 103.419 ;
        RECT  34.8 2.137 34.92 103.419 ;
        RECT  32.1 2.137 32.22 103.419 ;
        RECT  29.4 2.137 29.52 103.419 ;
        RECT  26.7 2.137 26.82 103.419 ;
        RECT  24 2.137 24.12 103.419 ;
        RECT  21.3 2.137 21.42 103.419 ;
        RECT  18.6 2.137 18.72 103.419 ;
        RECT  15.9 2.137 16.02 103.419 ;
        RECT  13.2 2.137 13.32 103.419 ;
        RECT  10.5 2.137 10.62 103.419 ;
        RECT  7.8 2.137 7.92 103.419 ;
        RECT  5.1 2.137 5.22 103.419 ;
        RECT  2.4 2.137 2.52 103.419 ;
    END
  END VSS
  OBS
    LAYER RVTN ;
     RECT  2.16 2.16 101.898 2.295 ;
     RECT  2.16 2.565 101.898 2.835 ;
     RECT  2.16 3.105 101.898 3.375 ;
     RECT  2.16 3.645 101.898 3.915 ;
     RECT  2.16 4.185 101.898 4.455 ;
     RECT  2.16 4.725 101.898 4.995 ;
     RECT  2.16 5.265 101.898 5.535 ;
     RECT  2.16 5.805 101.898 6.075 ;
     RECT  2.16 6.345 101.898 6.615 ;
     RECT  2.16 6.885 101.898 7.155 ;
     RECT  2.16 7.425 101.898 7.695 ;
     RECT  2.16 7.965 101.898 8.235 ;
     RECT  2.16 8.505 101.898 8.775 ;
     RECT  2.16 9.045 101.898 9.315 ;
     RECT  2.16 9.585 101.898 9.855 ;
     RECT  2.16 10.125 101.898 10.395 ;
     RECT  2.16 10.665 101.898 10.935 ;
     RECT  2.16 11.205 101.898 11.475 ;
     RECT  2.16 11.745 101.898 12.015 ;
     RECT  2.16 12.285 101.898 12.555 ;
     RECT  2.16 12.825 101.898 13.095 ;
     RECT  2.16 13.365 101.898 13.635 ;
     RECT  2.16 13.905 101.898 14.175 ;
     RECT  2.16 14.445 101.898 14.715 ;
     RECT  2.16 14.985 101.898 15.255 ;
     RECT  2.16 15.525 101.898 15.795 ;
     RECT  2.16 16.065 101.898 16.335 ;
     RECT  2.16 16.605 101.898 16.875 ;
     RECT  2.16 17.145 101.898 17.415 ;
     RECT  2.16 17.685 101.898 17.955 ;
     RECT  2.16 18.225 101.898 18.495 ;
     RECT  2.16 18.765 101.898 19.035 ;
     RECT  2.16 19.305 101.898 19.575 ;
     RECT  2.16 19.845 101.898 20.115 ;
     RECT  2.16 20.385 101.898 20.655 ;
     RECT  2.16 20.925 101.898 21.195 ;
     RECT  2.16 21.465 101.898 21.735 ;
     RECT  2.16 22.005 101.898 22.275 ;
     RECT  2.16 22.545 101.898 22.815 ;
     RECT  2.16 23.085 101.898 23.355 ;
     RECT  2.16 23.625 101.898 23.895 ;
     RECT  2.16 24.165 101.898 24.435 ;
     RECT  2.16 24.705 101.898 24.975 ;
     RECT  2.16 25.245 101.898 25.515 ;
     RECT  2.16 25.785 101.898 26.055 ;
     RECT  2.16 26.325 101.898 26.595 ;
     RECT  2.16 26.865 101.898 27.135 ;
     RECT  2.16 27.405 101.898 27.675 ;
     RECT  2.16 27.945 101.898 28.215 ;
     RECT  2.16 28.485 101.898 28.755 ;
     RECT  2.16 29.025 101.898 29.295 ;
     RECT  2.16 29.565 101.898 29.835 ;
     RECT  2.16 30.105 101.898 30.375 ;
     RECT  2.16 30.645 101.898 30.915 ;
     RECT  2.16 31.185 101.898 31.455 ;
     RECT  2.16 31.725 101.898 31.995 ;
     RECT  2.16 32.265 101.898 32.535 ;
     RECT  2.16 32.805 101.898 33.075 ;
     RECT  2.16 33.345 101.898 33.615 ;
     RECT  2.16 33.885 101.898 34.155 ;
     RECT  2.16 34.425 101.898 34.695 ;
     RECT  2.16 34.965 101.898 35.235 ;
     RECT  2.16 35.505 101.898 35.775 ;
     RECT  2.16 36.045 101.898 36.315 ;
     RECT  2.16 36.585 101.898 36.855 ;
     RECT  2.16 37.125 101.898 37.395 ;
     RECT  2.16 37.665 101.898 37.935 ;
     RECT  2.16 38.205 101.898 38.475 ;
     RECT  2.16 38.745 101.898 39.015 ;
     RECT  2.16 39.285 101.898 39.555 ;
     RECT  2.16 39.825 101.898 40.095 ;
     RECT  2.16 40.365 101.898 40.635 ;
     RECT  2.16 40.905 101.898 41.175 ;
     RECT  2.16 41.445 101.898 41.715 ;
     RECT  2.16 41.985 101.898 42.255 ;
     RECT  2.16 42.525 101.898 42.795 ;
     RECT  2.16 43.065 101.898 43.335 ;
     RECT  2.16 43.605 101.898 43.875 ;
     RECT  2.16 44.145 101.898 44.415 ;
     RECT  2.16 44.685 101.898 44.955 ;
     RECT  2.16 45.225 101.898 45.495 ;
     RECT  2.16 45.765 101.898 46.035 ;
     RECT  2.16 46.305 101.898 46.575 ;
     RECT  2.16 46.845 101.898 47.115 ;
     RECT  2.16 47.385 101.898 47.655 ;
     RECT  2.16 47.925 101.898 48.195 ;
     RECT  2.16 48.465 101.898 48.735 ;
     RECT  2.16 49.005 101.898 49.275 ;
     RECT  2.16 49.545 101.898 49.815 ;
     RECT  2.16 50.085 101.898 50.355 ;
     RECT  2.16 50.625 101.898 50.895 ;
     RECT  2.16 51.165 101.898 51.435 ;
     RECT  2.16 51.705 101.898 51.975 ;
     RECT  2.16 52.245 101.898 52.515 ;
     RECT  2.16 52.785 101.898 53.055 ;
     RECT  2.16 53.325 101.898 53.595 ;
     RECT  2.16 53.865 101.898 54.135 ;
     RECT  2.16 54.405 101.898 54.675 ;
     RECT  2.16 54.945 101.898 55.215 ;
     RECT  2.16 55.485 101.898 55.755 ;
     RECT  2.16 56.025 101.898 56.295 ;
     RECT  2.16 56.565 101.898 56.835 ;
     RECT  2.16 57.105 101.898 57.375 ;
     RECT  2.16 57.645 101.898 57.915 ;
     RECT  2.16 58.185 101.898 58.455 ;
     RECT  2.16 58.725 101.898 58.995 ;
     RECT  2.16 59.265 101.898 59.535 ;
     RECT  2.16 59.805 101.898 60.075 ;
     RECT  2.16 60.345 101.898 60.615 ;
     RECT  2.16 60.885 101.898 61.155 ;
     RECT  2.16 61.425 101.898 61.695 ;
     RECT  2.16 61.965 101.898 62.235 ;
     RECT  2.16 62.505 101.898 62.775 ;
     RECT  2.16 63.045 101.898 63.315 ;
     RECT  2.16 63.585 101.898 63.855 ;
     RECT  2.16 64.125 101.898 64.395 ;
     RECT  2.16 64.665 101.898 64.935 ;
     RECT  2.16 65.205 101.898 65.475 ;
     RECT  2.16 65.745 101.898 66.015 ;
     RECT  2.16 66.285 101.898 66.555 ;
     RECT  2.16 66.825 101.898 67.095 ;
     RECT  2.16 67.365 101.898 67.635 ;
     RECT  2.16 67.905 101.898 68.175 ;
     RECT  2.16 68.445 101.898 68.715 ;
     RECT  2.16 68.985 101.898 69.255 ;
     RECT  2.16 69.525 101.898 69.795 ;
     RECT  2.16 70.065 101.898 70.335 ;
     RECT  2.16 70.605 101.898 70.875 ;
     RECT  2.16 71.145 101.898 71.415 ;
     RECT  2.16 71.685 101.898 71.955 ;
     RECT  2.16 72.225 101.898 72.495 ;
     RECT  2.16 72.765 101.898 73.035 ;
     RECT  2.16 73.305 101.898 73.575 ;
     RECT  2.16 73.845 101.898 74.115 ;
     RECT  2.16 74.385 101.898 74.655 ;
     RECT  2.16 74.925 101.898 75.195 ;
     RECT  2.16 75.465 101.898 75.735 ;
     RECT  2.16 76.005 101.898 76.275 ;
     RECT  2.16 76.545 101.898 76.815 ;
     RECT  2.16 77.085 101.898 77.355 ;
     RECT  2.16 77.625 101.898 77.895 ;
     RECT  2.16 78.165 101.898 78.435 ;
     RECT  2.16 78.705 101.898 78.975 ;
     RECT  2.16 79.245 101.898 79.515 ;
     RECT  2.16 79.785 101.898 80.055 ;
     RECT  2.16 80.325 101.898 80.595 ;
     RECT  2.16 80.865 101.898 81.135 ;
     RECT  2.16 81.405 101.898 81.675 ;
     RECT  2.16 81.945 101.898 82.215 ;
     RECT  2.16 82.485 101.898 82.755 ;
     RECT  2.16 83.025 101.898 83.295 ;
     RECT  2.16 83.565 101.898 83.835 ;
     RECT  2.16 84.105 101.898 84.375 ;
     RECT  2.16 84.645 101.898 84.915 ;
     RECT  2.16 85.185 101.898 85.455 ;
     RECT  2.16 85.725 101.898 85.995 ;
     RECT  2.16 86.265 101.898 86.535 ;
     RECT  2.16 86.805 101.898 87.075 ;
     RECT  2.16 87.345 101.898 87.615 ;
     RECT  2.16 87.885 101.898 88.155 ;
     RECT  2.16 88.425 101.898 88.695 ;
     RECT  2.16 88.965 101.898 89.235 ;
     RECT  2.16 89.505 101.898 89.775 ;
     RECT  2.16 90.045 101.898 90.315 ;
     RECT  2.16 90.585 101.898 90.855 ;
     RECT  2.16 91.125 101.898 91.395 ;
     RECT  2.16 91.665 101.898 91.935 ;
     RECT  2.16 92.205 101.898 92.475 ;
     RECT  2.16 92.745 101.898 93.015 ;
     RECT  2.16 93.285 101.898 93.555 ;
     RECT  2.16 93.825 101.898 94.095 ;
     RECT  2.16 94.365 101.898 94.635 ;
     RECT  2.16 94.905 101.898 95.175 ;
     RECT  2.16 95.445 101.898 95.715 ;
     RECT  2.16 95.985 101.898 96.255 ;
     RECT  2.16 96.525 101.898 96.795 ;
     RECT  2.16 97.065 101.898 97.335 ;
     RECT  2.16 97.605 101.898 97.875 ;
     RECT  2.16 98.145 101.898 98.415 ;
     RECT  2.16 98.685 101.898 98.955 ;
     RECT  2.16 99.225 101.898 99.495 ;
     RECT  2.16 99.765 101.898 100.035 ;
     RECT  2.16 100.305 101.898 100.575 ;
     RECT  2.16 100.845 101.898 101.115 ;
     RECT  2.16 101.385 101.898 101.655 ;
     RECT  2.16 101.925 101.898 102.195 ;
     RECT  2.16 102.465 101.898 102.735 ;
     RECT  2.16 103.005 101.898 103.275 ;
    LAYER RVTP ;
     RECT  2.16 2.295 101.898 2.565 ;
     RECT  2.16 2.835 101.898 3.105 ;
     RECT  2.16 3.375 101.898 3.645 ;
     RECT  2.16 3.915 101.898 4.185 ;
     RECT  2.16 4.455 101.898 4.725 ;
     RECT  2.16 4.995 101.898 5.265 ;
     RECT  2.16 5.535 101.898 5.805 ;
     RECT  2.16 6.075 101.898 6.345 ;
     RECT  2.16 6.615 101.898 6.885 ;
     RECT  2.16 7.155 101.898 7.425 ;
     RECT  2.16 7.695 101.898 7.965 ;
     RECT  2.16 8.235 101.898 8.505 ;
     RECT  2.16 8.775 101.898 9.045 ;
     RECT  2.16 9.315 101.898 9.585 ;
     RECT  2.16 9.855 101.898 10.125 ;
     RECT  2.16 10.395 101.898 10.665 ;
     RECT  2.16 10.935 101.898 11.205 ;
     RECT  2.16 11.475 101.898 11.745 ;
     RECT  2.16 12.015 101.898 12.285 ;
     RECT  2.16 12.555 101.898 12.825 ;
     RECT  2.16 13.095 101.898 13.365 ;
     RECT  2.16 13.635 101.898 13.905 ;
     RECT  2.16 14.175 101.898 14.445 ;
     RECT  2.16 14.715 101.898 14.985 ;
     RECT  2.16 15.255 101.898 15.525 ;
     RECT  2.16 15.795 101.898 16.065 ;
     RECT  2.16 16.335 101.898 16.605 ;
     RECT  2.16 16.875 101.898 17.145 ;
     RECT  2.16 17.415 101.898 17.685 ;
     RECT  2.16 17.955 101.898 18.225 ;
     RECT  2.16 18.495 101.898 18.765 ;
     RECT  2.16 19.035 101.898 19.305 ;
     RECT  2.16 19.575 101.898 19.845 ;
     RECT  2.16 20.115 101.898 20.385 ;
     RECT  2.16 20.655 101.898 20.925 ;
     RECT  2.16 21.195 101.898 21.465 ;
     RECT  2.16 21.735 101.898 22.005 ;
     RECT  2.16 22.275 101.898 22.545 ;
     RECT  2.16 22.815 101.898 23.085 ;
     RECT  2.16 23.355 101.898 23.625 ;
     RECT  2.16 23.895 101.898 24.165 ;
     RECT  2.16 24.435 101.898 24.705 ;
     RECT  2.16 24.975 101.898 25.245 ;
     RECT  2.16 25.515 101.898 25.785 ;
     RECT  2.16 26.055 101.898 26.325 ;
     RECT  2.16 26.595 101.898 26.865 ;
     RECT  2.16 27.135 101.898 27.405 ;
     RECT  2.16 27.675 101.898 27.945 ;
     RECT  2.16 28.215 101.898 28.485 ;
     RECT  2.16 28.755 101.898 29.025 ;
     RECT  2.16 29.295 101.898 29.565 ;
     RECT  2.16 29.835 101.898 30.105 ;
     RECT  2.16 30.375 101.898 30.645 ;
     RECT  2.16 30.915 101.898 31.185 ;
     RECT  2.16 31.455 101.898 31.725 ;
     RECT  2.16 31.995 101.898 32.265 ;
     RECT  2.16 32.535 101.898 32.805 ;
     RECT  2.16 33.075 101.898 33.345 ;
     RECT  2.16 33.615 101.898 33.885 ;
     RECT  2.16 34.155 101.898 34.425 ;
     RECT  2.16 34.695 101.898 34.965 ;
     RECT  2.16 35.235 101.898 35.505 ;
     RECT  2.16 35.775 101.898 36.045 ;
     RECT  2.16 36.315 101.898 36.585 ;
     RECT  2.16 36.855 101.898 37.125 ;
     RECT  2.16 37.395 101.898 37.665 ;
     RECT  2.16 37.935 101.898 38.205 ;
     RECT  2.16 38.475 101.898 38.745 ;
     RECT  2.16 39.015 101.898 39.285 ;
     RECT  2.16 39.555 101.898 39.825 ;
     RECT  2.16 40.095 101.898 40.365 ;
     RECT  2.16 40.635 101.898 40.905 ;
     RECT  2.16 41.175 101.898 41.445 ;
     RECT  2.16 41.715 101.898 41.985 ;
     RECT  2.16 42.255 101.898 42.525 ;
     RECT  2.16 42.795 101.898 43.065 ;
     RECT  2.16 43.335 101.898 43.605 ;
     RECT  2.16 43.875 101.898 44.145 ;
     RECT  2.16 44.415 101.898 44.685 ;
     RECT  2.16 44.955 101.898 45.225 ;
     RECT  2.16 45.495 101.898 45.765 ;
     RECT  2.16 46.035 101.898 46.305 ;
     RECT  2.16 46.575 101.898 46.845 ;
     RECT  2.16 47.115 101.898 47.385 ;
     RECT  2.16 47.655 101.898 47.925 ;
     RECT  2.16 48.195 101.898 48.465 ;
     RECT  2.16 48.735 101.898 49.005 ;
     RECT  2.16 49.275 101.898 49.545 ;
     RECT  2.16 49.815 101.898 50.085 ;
     RECT  2.16 50.355 101.898 50.625 ;
     RECT  2.16 50.895 101.898 51.165 ;
     RECT  2.16 51.435 101.898 51.705 ;
     RECT  2.16 51.975 101.898 52.245 ;
     RECT  2.16 52.515 101.898 52.785 ;
     RECT  2.16 53.055 101.898 53.325 ;
     RECT  2.16 53.595 101.898 53.865 ;
     RECT  2.16 54.135 101.898 54.405 ;
     RECT  2.16 54.675 101.898 54.945 ;
     RECT  2.16 55.215 101.898 55.485 ;
     RECT  2.16 55.755 101.898 56.025 ;
     RECT  2.16 56.295 101.898 56.565 ;
     RECT  2.16 56.835 101.898 57.105 ;
     RECT  2.16 57.375 101.898 57.645 ;
     RECT  2.16 57.915 101.898 58.185 ;
     RECT  2.16 58.455 101.898 58.725 ;
     RECT  2.16 58.995 101.898 59.265 ;
     RECT  2.16 59.535 101.898 59.805 ;
     RECT  2.16 60.075 101.898 60.345 ;
     RECT  2.16 60.615 101.898 60.885 ;
     RECT  2.16 61.155 101.898 61.425 ;
     RECT  2.16 61.695 101.898 61.965 ;
     RECT  2.16 62.235 101.898 62.505 ;
     RECT  2.16 62.775 101.898 63.045 ;
     RECT  2.16 63.315 101.898 63.585 ;
     RECT  2.16 63.855 101.898 64.125 ;
     RECT  2.16 64.395 101.898 64.665 ;
     RECT  2.16 64.935 101.898 65.205 ;
     RECT  2.16 65.475 101.898 65.745 ;
     RECT  2.16 66.015 101.898 66.285 ;
     RECT  2.16 66.555 101.898 66.825 ;
     RECT  2.16 67.095 101.898 67.365 ;
     RECT  2.16 67.635 101.898 67.905 ;
     RECT  2.16 68.175 101.898 68.445 ;
     RECT  2.16 68.715 101.898 68.985 ;
     RECT  2.16 69.255 101.898 69.525 ;
     RECT  2.16 69.795 101.898 70.065 ;
     RECT  2.16 70.335 101.898 70.605 ;
     RECT  2.16 70.875 101.898 71.145 ;
     RECT  2.16 71.415 101.898 71.685 ;
     RECT  2.16 71.955 101.898 72.225 ;
     RECT  2.16 72.495 101.898 72.765 ;
     RECT  2.16 73.035 101.898 73.305 ;
     RECT  2.16 73.575 101.898 73.845 ;
     RECT  2.16 74.115 101.898 74.385 ;
     RECT  2.16 74.655 101.898 74.925 ;
     RECT  2.16 75.195 101.898 75.465 ;
     RECT  2.16 75.735 101.898 76.005 ;
     RECT  2.16 76.275 101.898 76.545 ;
     RECT  2.16 76.815 101.898 77.085 ;
     RECT  2.16 77.355 101.898 77.625 ;
     RECT  2.16 77.895 101.898 78.165 ;
     RECT  2.16 78.435 101.898 78.705 ;
     RECT  2.16 78.975 101.898 79.245 ;
     RECT  2.16 79.515 101.898 79.785 ;
     RECT  2.16 80.055 101.898 80.325 ;
     RECT  2.16 80.595 101.898 80.865 ;
     RECT  2.16 81.135 101.898 81.405 ;
     RECT  2.16 81.675 101.898 81.945 ;
     RECT  2.16 82.215 101.898 82.485 ;
     RECT  2.16 82.755 101.898 83.025 ;
     RECT  2.16 83.295 101.898 83.565 ;
     RECT  2.16 83.835 101.898 84.105 ;
     RECT  2.16 84.375 101.898 84.645 ;
     RECT  2.16 84.915 101.898 85.185 ;
     RECT  2.16 85.455 101.898 85.725 ;
     RECT  2.16 85.995 101.898 86.265 ;
     RECT  2.16 86.535 101.898 86.805 ;
     RECT  2.16 87.075 101.898 87.345 ;
     RECT  2.16 87.615 101.898 87.885 ;
     RECT  2.16 88.155 101.898 88.425 ;
     RECT  2.16 88.695 101.898 88.965 ;
     RECT  2.16 89.235 101.898 89.505 ;
     RECT  2.16 89.775 101.898 90.045 ;
     RECT  2.16 90.315 101.898 90.585 ;
     RECT  2.16 90.855 101.898 91.125 ;
     RECT  2.16 91.395 101.898 91.665 ;
     RECT  2.16 91.935 101.898 92.205 ;
     RECT  2.16 92.475 101.898 92.745 ;
     RECT  2.16 93.015 101.898 93.285 ;
     RECT  2.16 93.555 101.898 93.825 ;
     RECT  2.16 94.095 101.898 94.365 ;
     RECT  2.16 94.635 101.898 94.905 ;
     RECT  2.16 95.175 101.898 95.445 ;
     RECT  2.16 95.715 101.898 95.985 ;
     RECT  2.16 96.255 101.898 96.525 ;
     RECT  2.16 96.795 101.898 97.065 ;
     RECT  2.16 97.335 101.898 97.605 ;
     RECT  2.16 97.875 101.898 98.145 ;
     RECT  2.16 98.415 101.898 98.685 ;
     RECT  2.16 98.955 101.898 99.225 ;
     RECT  2.16 99.495 101.898 99.765 ;
     RECT  2.16 100.035 101.898 100.305 ;
     RECT  2.16 100.575 101.898 100.845 ;
     RECT  2.16 101.115 101.898 101.385 ;
     RECT  2.16 101.655 101.898 101.925 ;
     RECT  2.16 102.195 101.898 102.465 ;
     RECT  2.16 102.735 101.898 103.005 ;
     RECT  2.16 103.275 101.898 103.41 ;
    LAYER M1 ;
     RECT  2.16 2.151 101.898 103.419 ;
    LAYER M2 ;
     RECT  2.16 2.151 31.243 103.419 ;
     RECT  31.963 105.606 31.999 105.624 ;
     RECT  31.999 105.606 32.035 105.696 ;
     RECT  32.035 105.606 32.387 105.768 ;
     RECT  31.243 2.151 33.115 103.734 ;
     RECT  32.387 105.678 33.223 105.768 ;
     RECT  33.223 105.516 33.439 105.768 ;
     RECT  33.439 104.796 33.467 105.768 ;
     RECT  33.467 104.796 33.611 104.886 ;
     RECT  33.115 2.151 34.187 103.842 ;
     RECT  34.339 104.904 34.375 104.922 ;
     RECT  33.467 105.678 34.375 105.768 ;
     RECT  34.375 104.904 34.727 105.768 ;
     RECT  34.727 105.516 35.195 105.768 ;
     RECT  36.139 104.796 36.283 104.814 ;
     RECT  35.195 105.561 36.283 105.768 ;
     RECT  36.283 104.796 36.419 105.768 ;
     RECT  34.187 2.151 36.491 103.734 ;
     RECT  36.419 104.868 36.923 105.768 ;
     RECT  36.491 2.151 37.139 103.644 ;
     RECT  37.687 104.706 37.831 104.724 ;
     RECT  36.923 105.516 37.831 105.768 ;
     RECT  37.831 104.706 37.859 105.768 ;
     RECT  37.859 104.796 38.003 105.768 ;
     RECT  38.003 104.868 38.075 105.768 ;
     RECT  38.839 104.796 38.911 104.814 ;
     RECT  38.075 105.561 38.911 105.768 ;
     RECT  38.911 104.796 39.227 105.768 ;
     RECT  39.227 104.868 39.299 105.768 ;
     RECT  37.139 2.151 39.307 103.608 ;
     RECT  39.307 2.151 39.919 103.644 ;
     RECT  39.919 2.151 40.019 103.734 ;
     RECT  40.019 2.151 40.631 103.644 ;
     RECT  39.299 105.516 40.855 105.768 ;
     RECT  40.855 104.796 41.027 105.768 ;
     RECT  40.631 2.151 42.295 103.608 ;
     RECT  41.027 104.868 42.295 105.768 ;
     RECT  42.295 2.151 43.259 105.768 ;
     RECT  43.259 2.151 43.511 104.418 ;
     RECT  43.259 105.561 44.563 105.768 ;
     RECT  43.511 2.151 45.311 103.734 ;
     RECT  44.563 104.868 45.391 105.768 ;
     RECT  45.391 104.796 45.491 105.768 ;
     RECT  45.491 105.516 45.635 105.768 ;
     RECT  45.635 105.606 45.779 105.768 ;
     RECT  45.779 105.678 46.831 105.768 ;
     RECT  46.831 105.561 47.479 105.768 ;
     RECT  47.479 105.516 47.911 105.768 ;
     RECT  47.911 104.868 48.983 105.768 ;
     RECT  48.983 104.868 49.063 104.886 ;
     RECT  49.063 104.796 49.711 104.886 ;
     RECT  48.983 105.75 49.711 105.768 ;
     RECT  49.711 104.796 49.783 105.768 ;
     RECT  49.783 104.751 49.919 105.768 ;
     RECT  45.311 2.151 50.675 103.572 ;
     RECT  50.675 2.151 50.963 103.464 ;
     RECT  49.919 104.796 51.179 105.768 ;
     RECT  51.179 105.444 51.503 105.768 ;
     RECT  50.963 2.151 51.727 103.419 ;
     RECT  51.503 105.561 52.331 105.768 ;
     RECT  52.807 104.868 53.095 104.886 ;
     RECT  52.331 105.75 53.095 105.768 ;
     RECT  51.727 2.151 53.347 103.464 ;
     RECT  53.347 2.151 53.527 103.608 ;
     RECT  53.527 2.151 53.887 104.04 ;
     RECT  53.095 104.868 54.491 105.768 ;
     RECT  53.887 2.151 55.291 104.076 ;
     RECT  54.491 105.444 55.291 105.768 ;
     RECT  55.291 2.151 55.427 105.768 ;
     RECT  55.427 104.868 55.571 105.768 ;
     RECT  55.571 105.372 56.111 105.768 ;
     RECT  56.111 105.372 56.363 105.696 ;
     RECT  56.363 105.444 56.399 105.696 ;
     RECT  56.399 105.561 56.839 105.696 ;
     RECT  56.839 105.561 57.011 105.768 ;
     RECT  57.011 105.678 57.335 105.768 ;
     RECT  55.427 2.151 57.703 104.076 ;
     RECT  57.703 2.151 57.775 104.814 ;
     RECT  57.775 2.151 57.947 105.462 ;
     RECT  57.947 105.444 58.055 105.462 ;
     RECT  58.135 105.561 58.819 105.768 ;
     RECT  58.819 105.561 58.855 105.804 ;
     RECT  58.855 105.408 59.027 105.804 ;
     RECT  59.027 105.606 59.135 105.804 ;
     RECT  57.947 2.151 59.431 104.076 ;
     RECT  59.431 2.151 59.567 104.85 ;
     RECT  59.567 104.832 59.863 104.85 ;
     RECT  59.135 105.606 59.863 105.768 ;
     RECT  59.863 104.832 60.251 105.768 ;
     RECT  60.251 105.642 60.287 105.768 ;
     RECT  60.251 104.832 60.323 104.85 ;
     RECT  60.287 105.714 60.359 105.768 ;
     RECT  60.359 105.75 60.431 105.768 ;
     RECT  59.567 2.151 62.735 104.076 ;
     RECT  62.735 2.151 63.131 104.04 ;
     RECT  63.131 2.151 63.203 103.959 ;
     RECT  64.111 104.868 64.283 104.886 ;
     RECT  63.203 2.151 66.487 103.734 ;
     RECT  66.487 2.151 66.623 104.229 ;
     RECT  66.623 2.151 67.163 103.734 ;
     RECT  67.163 2.151 67.559 103.689 ;
     RECT  67.559 2.151 69.071 103.608 ;
     RECT  69.071 2.151 69.575 103.572 ;
     RECT  69.575 2.151 101.898 103.419 ;
     RECT  101.898 29.34 101.903 32.184 ;
     RECT  101.898 20.556 102.011 21.384 ;
     RECT  101.898 40.806 102.011 57.708 ;
     RECT  101.898 71.352 102.011 79.974 ;
     RECT  101.898 58.464 102.047 58.644 ;
     RECT  101.903 32.166 102.227 32.184 ;
     RECT  101.898 24.336 102.263 25.434 ;
     RECT  101.903 29.34 102.263 31.104 ;
     RECT  101.898 85.086 102.299 85.104 ;
     RECT  101.898 35.946 102.515 37.044 ;
     RECT  101.898 22.176 102.551 22.464 ;
     RECT  102.263 24.336 102.551 25.164 ;
     RECT  102.515 36.216 102.551 37.044 ;
     RECT  101.898 59.436 102.551 70.254 ;
     RECT  102.551 36.216 102.587 36.234 ;
     RECT  102.011 40.806 102.587 55.512 ;
     RECT  102.551 59.436 102.587 68.976 ;
     RECT  102.551 69.876 102.587 70.254 ;
     RECT  102.011 71.352 102.587 74.34 ;
     RECT  102.551 22.176 102.623 22.374 ;
     RECT  102.551 24.336 102.623 24.354 ;
     RECT  102.587 40.806 102.623 53.784 ;
     RECT  102.587 54.72 102.623 55.512 ;
     RECT  102.011 56.304 102.623 57.708 ;
     RECT  102.587 59.508 102.623 59.598 ;
     RECT  102.587 60.426 102.623 62.298 ;
     RECT  102.587 65.25 102.623 68.976 ;
     RECT  102.587 70.236 102.623 70.254 ;
     RECT  102.587 71.388 102.623 74.34 ;
     RECT  102.623 22.356 102.659 22.374 ;
     RECT  102.623 46.008 102.659 53.784 ;
     RECT  102.623 54.72 102.659 55.404 ;
     RECT  102.623 61.398 102.659 62.298 ;
     RECT  102.623 66.834 102.659 68.976 ;
     RECT  102.623 71.388 102.659 72.792 ;
     RECT  102.011 75.51 102.659 76.194 ;
     RECT  102.659 46.008 102.695 51.084 ;
     RECT  102.659 75.906 102.695 76.068 ;
     RECT  102.263 29.376 102.839 31.104 ;
     RECT  102.623 45.036 102.875 45.144 ;
     RECT  102.695 46.008 102.911 50.148 ;
     RECT  102.623 41.616 102.947 44.136 ;
     RECT  102.911 47.286 102.983 50.148 ;
     RECT  102.947 41.616 103.091 43.794 ;
     RECT  101.898 38.106 103.127 39.654 ;
     RECT  101.898 33.786 103.163 33.804 ;
     RECT  102.011 20.556 103.199 20.844 ;
     RECT  102.551 25.146 103.199 25.164 ;
     RECT  101.898 26.496 103.199 26.514 ;
     RECT  102.839 29.376 103.199 31.014 ;
     RECT  103.127 38.52 103.199 39.654 ;
     RECT  103.091 41.616 103.199 42.588 ;
     RECT  103.091 43.776 103.199 43.794 ;
     RECT  102.875 45.036 103.199 45.054 ;
     RECT  102.911 46.008 103.199 46.494 ;
     RECT  102.983 47.394 103.199 50.148 ;
     RECT  102.695 51.066 103.199 51.084 ;
     RECT  102.659 52.83 103.199 53.784 ;
     RECT  102.659 54.72 103.199 55.242 ;
     RECT  102.623 56.466 103.199 57.708 ;
     RECT  102.047 58.626 103.199 58.644 ;
     RECT  102.623 60.426 103.199 60.534 ;
     RECT  102.659 61.398 103.199 61.416 ;
     RECT  102.659 62.28 103.199 62.298 ;
     RECT  102.587 63.486 103.199 64.458 ;
     RECT  102.623 65.25 103.199 66.078 ;
     RECT  102.659 68.112 103.199 68.976 ;
     RECT  102.659 72.126 103.199 72.792 ;
     RECT  102.623 73.62 103.199 74.304 ;
     RECT  102.011 77.094 103.199 79.974 ;
     RECT  103.199 29.376 103.235 30.024 ;
     RECT  103.199 41.688 103.235 41.904 ;
     RECT  103.199 47.862 103.235 48.294 ;
     RECT  103.199 49.86 103.235 49.878 ;
     RECT  103.199 53.766 103.235 53.784 ;
     RECT  103.199 55.224 103.235 55.242 ;
     RECT  103.199 56.466 103.235 56.862 ;
     RECT  103.199 64.332 103.235 64.35 ;
     RECT  103.199 66.06 103.235 66.078 ;
     RECT  103.199 68.76 103.235 68.778 ;
     RECT  103.199 72.126 103.235 72.558 ;
     RECT  103.199 73.782 103.235 73.8 ;
     RECT  103.199 77.976 103.235 77.994 ;
     RECT  103.199 79.686 103.235 79.974 ;
     RECT  103.235 29.376 103.271 29.754 ;
     RECT  103.199 46.08 103.271 46.494 ;
     RECT  103.235 47.934 103.271 48.186 ;
     RECT  102.659 66.834 103.271 67.284 ;
     RECT  103.235 79.686 103.271 79.704 ;
     RECT  103.235 41.724 103.307 41.904 ;
     RECT  103.783 26.568 103.819 26.739 ;
     RECT  103.199 38.52 103.847 39.204 ;
     RECT  103.271 29.376 103.883 29.394 ;
     RECT  103.199 30.996 103.883 31.014 ;
     RECT  103.847 39.186 103.883 39.204 ;
     RECT  102.551 37.026 103.919 37.044 ;
     RECT  103.235 56.466 103.919 56.754 ;
     RECT  102.623 40.806 103.955 40.824 ;
     RECT  103.919 56.466 103.955 56.484 ;
     RECT  103.891 51.678 103.963 51.696 ;
     RECT  103.819 26.568 103.991 26.784 ;
     RECT  103.891 42.651 103.991 42.822 ;
     RECT  103.891 46.548 103.991 46.719 ;
     RECT  103.963 51.678 103.991 51.768 ;
     RECT  103.891 22.824 104.027 22.842 ;
     RECT  103.307 41.886 104.027 41.904 ;
     RECT  103.991 42.651 104.027 42.75 ;
     RECT  103.991 26.64 104.063 26.658 ;
     RECT  104.027 42.732 104.063 42.75 ;
     RECT  103.963 43.731 104.063 43.749 ;
     RECT  103.991 46.548 104.063 46.674 ;
     RECT  103.271 47.934 104.063 48.069 ;
     RECT  103.991 51.75 104.063 51.768 ;
     RECT  103.963 55.026 104.063 55.674 ;
     RECT  103.963 57.312 104.063 57.33 ;
     RECT  103.963 58.356 104.063 58.374 ;
     RECT  103.963 59.706 104.063 59.994 ;
     RECT  103.963 62.046 104.063 62.334 ;
     RECT  103.963 65.331 104.063 65.349 ;
     RECT  103.963 66.366 104.063 66.384 ;
     RECT  103.963 67.986 104.063 68.004 ;
     RECT  103.963 71.316 104.063 71.334 ;
     RECT  103.963 72.702 104.063 72.72 ;
     RECT  103.963 77.67 104.063 77.688 ;
    LAYER M3 ;
     RECT  2.415 2.143 2.505 2.413 ;
     RECT  5.115 2.143 5.205 2.413 ;
     RECT  7.815 2.143 7.905 2.413 ;
     RECT  10.515 2.143 10.605 2.413 ;
     RECT  13.215 2.143 13.305 2.413 ;
     RECT  15.915 2.143 16.005 2.413 ;
     RECT  18.615 2.143 18.705 2.413 ;
     RECT  21.315 2.143 21.405 2.413 ;
     RECT  24.015 2.143 24.105 2.413 ;
     RECT  26.715 2.143 26.805 2.413 ;
     RECT  29.415 2.143 29.505 2.413 ;
     RECT  32.115 2.143 32.205 2.413 ;
     RECT  34.815 2.143 34.905 2.413 ;
     RECT  37.515 2.143 37.605 2.413 ;
     RECT  40.215 2.143 40.305 2.413 ;
     RECT  42.915 2.143 43.005 2.413 ;
     RECT  45.615 2.143 45.705 2.413 ;
     RECT  48.315 2.143 48.405 2.413 ;
     RECT  51.015 2.143 51.105 2.413 ;
     RECT  53.715 2.143 53.805 2.413 ;
     RECT  56.415 2.143 56.505 2.413 ;
     RECT  59.115 2.143 59.205 2.413 ;
     RECT  61.815 2.143 61.905 2.413 ;
     RECT  64.515 2.143 64.605 2.413 ;
     RECT  67.215 2.143 67.305 2.413 ;
     RECT  69.915 2.143 70.005 2.413 ;
     RECT  72.615 2.143 72.705 2.413 ;
     RECT  75.315 2.143 75.405 2.413 ;
     RECT  78.015 2.143 78.105 2.413 ;
     RECT  80.715 2.143 80.805 2.413 ;
     RECT  83.415 2.143 83.505 2.413 ;
     RECT  86.115 2.143 86.205 2.413 ;
     RECT  88.815 2.143 88.905 2.413 ;
     RECT  91.515 2.143 91.605 2.413 ;
     RECT  94.215 2.143 94.305 2.413 ;
     RECT  96.915 2.143 97.005 2.413 ;
     RECT  99.615 2.143 99.705 2.413 ;
     RECT  101.16 19.915 101.178 20.011 ;
     RECT  103.176 20.203 103.194 20.299 ;
     RECT  102.924 20.299 103.194 20.779 ;
     RECT  103.932 20.107 103.95 20.779 ;
     RECT  102.924 20.779 103.95 20.849 ;
     RECT  101.16 20.011 101.898 20.875 ;
     RECT  99.615 2.413 99.897 20.971 ;
     RECT  100.908 20.875 101.898 20.971 ;
     RECT  99.615 20.971 101.898 21.163 ;
     RECT  99.615 21.163 102.006 21.259 ;
     RECT  102.924 20.849 103.086 21.259 ;
     RECT  96.915 2.413 97.197 21.403 ;
     RECT  98.604 21.397 98.622 21.533 ;
     RECT  103.896 20.849 103.95 21.547 ;
     RECT  80.715 2.413 80.997 22.171 ;
     RECT  92.808 22.171 92.826 22.343 ;
     RECT  61.815 2.413 62.097 22.351 ;
     RECT  61.815 22.351 62.694 22.469 ;
     RECT  40.215 2.413 40.497 22.477 ;
     RECT  75.315 2.413 75.597 22.477 ;
     RECT  76.86 20.587 76.878 22.477 ;
     RECT  103.896 21.547 103.986 22.808 ;
     RECT  99.615 21.259 103.086 23.371 ;
     RECT  99.615 23.371 103.122 24.331 ;
     RECT  68.256 22.207 68.274 24.367 ;
     RECT  99.504 24.331 103.122 24.368 ;
     RECT  99.615 24.368 103.122 24.427 ;
     RECT  103.896 22.808 104.022 24.427 ;
     RECT  53.715 2.413 53.997 24.619 ;
     RECT  99.615 24.427 104.022 25.195 ;
     RECT  99.576 25.195 104.022 25.243 ;
     RECT  68.256 24.367 68.67 25.285 ;
     RECT  94.215 2.413 94.497 25.291 ;
     RECT  68.256 25.285 68.958 25.321 ;
     RECT  69.915 2.413 70.197 25.321 ;
     RECT  72.615 2.413 72.897 25.447 ;
     RECT  96.624 21.403 97.197 25.447 ;
     RECT  98.928 25.243 104.022 25.579 ;
     RECT  39.456 24.907 39.474 25.717 ;
     RECT  86.115 2.413 86.397 25.723 ;
     RECT  87.156 21.397 87.174 25.723 ;
     RECT  94.215 25.291 95.166 25.745 ;
     RECT  61.815 22.469 62.097 25.819 ;
     RECT  68.256 25.321 70.197 25.819 ;
     RECT  70.956 25.753 70.974 25.819 ;
     RECT  78.015 2.413 78.297 25.819 ;
     RECT  61.815 25.819 62.514 25.963 ;
     RECT  78.015 25.819 78.678 25.963 ;
     RECT  59.115 2.413 59.397 26.059 ;
     RECT  90.648 25.819 90.666 26.093 ;
     RECT  60.12 26.347 60.138 26.587 ;
     RECT  78.015 25.963 78.786 26.621 ;
     RECT  98.424 25.579 104.022 26.635 ;
     RECT  53.715 24.619 54.414 26.827 ;
     RECT  55.656 26.635 55.674 26.827 ;
     RECT  75.315 22.477 76.878 26.827 ;
     RECT  57.492 23.035 57.51 27.067 ;
     RECT  58.392 26.059 59.397 27.067 ;
     RECT  61.815 25.963 62.802 27.115 ;
     RECT  48.315 2.413 48.597 27.163 ;
     RECT  56.415 2.413 56.697 27.163 ;
     RECT  57.492 27.067 59.397 27.163 ;
     RECT  80.064 22.171 80.997 27.301 ;
     RECT  91.515 2.413 91.797 27.301 ;
     RECT  91.515 27.301 91.89 27.341 ;
     RECT  74.232 20.857 74.25 27.451 ;
     RECT  75.204 26.827 76.878 27.451 ;
     RECT  94.215 25.745 94.518 27.451 ;
     RECT  53.715 26.827 55.674 27.595 ;
     RECT  56.415 27.163 59.397 27.595 ;
     RECT  68.256 25.819 70.974 27.691 ;
     RECT  90.648 27.451 90.666 27.773 ;
     RECT  94.215 27.451 94.59 27.773 ;
     RECT  80.064 27.301 81.09 27.779 ;
     RECT  74.232 27.451 76.878 27.917 ;
     RECT  82.656 27.739 82.674 27.917 ;
     RECT  75.204 27.917 76.878 28.459 ;
     RECT  94.215 27.773 94.497 28.507 ;
     RECT  78.015 26.621 78.678 28.651 ;
     RECT  68.256 27.691 71.226 28.781 ;
     RECT  78.015 28.651 78.786 28.781 ;
     RECT  86.115 25.723 87.174 28.781 ;
     RECT  94.215 28.507 94.518 28.781 ;
     RECT  42.915 2.413 43.197 28.939 ;
     RECT  53.715 27.595 59.397 29.335 ;
     RECT  34.815 2.413 35.097 29.497 ;
     RECT  42.915 28.939 43.614 29.533 ;
     RECT  70.956 28.781 71.226 29.561 ;
     RECT  86.115 28.781 86.397 29.569 ;
     RECT  67.215 2.413 67.497 29.767 ;
     RECT  68.256 28.781 70.197 29.767 ;
     RECT  41.544 26.587 41.562 29.911 ;
     RECT  42.372 29.533 43.614 29.911 ;
     RECT  75.204 28.459 77.238 30.073 ;
     RECT  98.424 26.635 104.058 30.091 ;
     RECT  96.012 25.447 97.197 30.145 ;
     RECT  98.388 30.091 104.058 30.145 ;
     RECT  74.232 27.917 74.25 30.451 ;
     RECT  75.06 30.073 77.238 30.451 ;
     RECT  78.015 28.781 78.297 30.451 ;
     RECT  74.232 30.451 78.75 30.569 ;
     RECT  61.815 27.115 63.018 30.577 ;
     RECT  78.015 30.569 78.75 30.677 ;
     RECT  65.988 30.577 66.006 30.685 ;
     RECT  65.916 30.685 66.006 30.713 ;
     RECT  34.524 29.497 35.097 30.847 ;
     RECT  96.012 30.145 104.058 30.859 ;
     RECT  83.415 2.413 83.697 30.955 ;
     RECT  60.12 26.587 60.822 31.147 ;
     RECT  61.815 30.577 63.558 31.147 ;
     RECT  67.215 29.767 70.197 31.147 ;
     RECT  70.956 29.561 70.974 31.147 ;
     RECT  85.752 29.569 86.397 31.147 ;
     RECT  87.156 28.781 87.174 31.147 ;
     RECT  34.524 30.847 35.622 31.153 ;
     RECT  72.615 25.447 73.242 31.153 ;
     RECT  51.015 2.413 51.297 31.225 ;
     RECT  52.128 28.747 52.146 31.225 ;
     RECT  95.724 30.859 104.058 31.379 ;
     RECT  78.015 30.677 78.678 31.483 ;
     RECT  82.908 30.955 83.697 31.483 ;
     RECT  80.064 27.779 80.997 31.495 ;
     RECT  94.215 28.781 94.497 31.627 ;
     RECT  67.215 31.147 70.974 31.657 ;
     RECT  85.752 31.147 87.174 31.661 ;
     RECT  78.015 31.483 78.714 31.757 ;
     RECT  82.656 31.483 83.697 31.757 ;
     RECT  67.215 31.657 71.514 31.805 ;
     RECT  78.015 31.757 78.39 31.805 ;
     RECT  90.648 31.627 90.666 31.805 ;
     RECT  94.215 31.627 94.59 31.805 ;
     RECT  70.956 31.805 71.514 32.197 ;
     RECT  64.515 2.413 64.797 32.431 ;
     RECT  67.215 31.805 70.197 32.431 ;
     RECT  75.06 30.569 77.238 32.431 ;
     RECT  78.015 31.805 78.297 32.431 ;
     RECT  88.815 2.413 89.097 32.431 ;
     RECT  91.515 27.341 91.797 32.431 ;
     RECT  60.12 31.147 63.558 32.443 ;
     RECT  64.404 32.431 64.797 32.477 ;
     RECT  67.104 32.431 70.197 32.477 ;
     RECT  75.06 32.431 78.297 32.477 ;
     RECT  91.404 32.431 91.797 32.477 ;
     RECT  51.015 31.225 52.146 32.587 ;
     RECT  79.632 31.495 80.997 32.731 ;
     RECT  51.015 32.587 52.182 32.779 ;
     RECT  53.316 29.335 59.397 32.779 ;
     RECT  67.215 32.477 70.197 32.827 ;
     RECT  70.956 32.197 71.55 32.827 ;
     RECT  78.015 32.477 78.297 32.827 ;
     RECT  85.752 31.661 86.397 32.875 ;
     RECT  87.156 31.661 87.174 32.875 ;
     RECT  78.015 32.827 78.75 33.005 ;
     RECT  90.648 32.827 90.666 33.005 ;
     RECT  65.916 30.713 65.934 33.007 ;
     RECT  88.704 32.431 89.097 33.008 ;
     RECT  67.215 32.827 71.55 33.053 ;
     RECT  78.015 33.005 78.678 33.053 ;
     RECT  85.752 32.875 87.174 33.053 ;
     RECT  60.12 32.443 63.594 33.307 ;
     RECT  64.515 32.477 64.797 33.307 ;
     RECT  67.215 33.053 70.197 33.787 ;
     RECT  70.956 33.053 71.55 33.787 ;
     RECT  78.015 33.053 78.297 33.787 ;
     RECT  85.752 33.053 86.397 33.787 ;
     RECT  87.156 33.053 87.174 33.787 ;
     RECT  94.215 31.805 94.497 33.787 ;
     RECT  90.648 33.787 90.666 33.917 ;
     RECT  74.232 30.569 74.25 34.219 ;
     RECT  75.06 32.477 77.238 34.219 ;
     RECT  79.488 32.731 80.997 34.219 ;
     RECT  81.756 33.853 81.774 34.219 ;
     RECT  82.908 31.757 83.697 34.219 ;
     RECT  79.488 34.219 81.774 34.259 ;
     RECT  90.72 34.219 90.738 34.493 ;
     RECT  94.215 33.787 94.59 34.493 ;
     RECT  65.916 33.007 66.438 34.603 ;
     RECT  67.215 33.787 71.55 34.603 ;
     RECT  78.015 33.787 78.678 34.603 ;
     RECT  79.488 34.259 80.997 34.603 ;
     RECT  85.752 33.787 87.174 34.627 ;
     RECT  45.615 2.413 45.897 34.699 ;
     RECT  46.764 34.459 46.782 34.733 ;
     RECT  78.015 34.603 80.997 34.733 ;
     RECT  94.215 34.493 94.518 34.763 ;
     RECT  65.916 34.603 71.55 34.781 ;
     RECT  74.232 34.219 77.238 34.781 ;
     RECT  82.656 34.219 83.697 34.781 ;
     RECT  67.215 34.781 71.55 35.167 ;
     RECT  72.615 31.153 73.278 35.167 ;
     RECT  47.628 27.163 48.597 35.179 ;
     RECT  47.052 35.179 48.597 35.275 ;
     RECT  49.86 34.699 49.878 35.275 ;
     RECT  82.764 34.781 83.697 35.419 ;
     RECT  82.764 35.419 84.078 35.515 ;
     RECT  94.215 34.763 94.497 35.515 ;
     RECT  88.815 33.008 89.097 35.563 ;
     RECT  88.704 35.563 89.097 35.609 ;
     RECT  82.656 35.515 84.078 35.741 ;
     RECT  47.052 35.275 49.878 35.803 ;
     RECT  94.215 35.515 94.626 35.837 ;
     RECT  74.232 34.781 74.25 36.091 ;
     RECT  75.06 34.781 77.238 36.091 ;
     RECT  47.052 35.803 49.95 36.283 ;
     RECT  51.015 32.779 59.397 36.283 ;
     RECT  60.12 33.307 64.797 36.283 ;
     RECT  47.052 36.283 64.797 36.413 ;
     RECT  74.232 36.091 77.238 36.413 ;
     RECT  90.648 35.563 90.666 36.413 ;
     RECT  94.215 35.837 94.59 36.413 ;
     RECT  78.015 34.733 78.678 36.763 ;
     RECT  79.488 34.733 80.997 36.763 ;
     RECT  41.544 29.911 43.614 36.907 ;
     RECT  37.515 2.413 37.797 37.057 ;
     RECT  65.916 34.781 66.438 37.387 ;
     RECT  94.215 36.413 94.518 37.421 ;
     RECT  78.015 36.763 80.997 37.469 ;
     RECT  85.176 34.627 87.174 37.469 ;
     RECT  90.648 37.339 90.666 37.469 ;
     RECT  47.052 36.413 59.397 37.579 ;
     RECT  78.015 37.469 78.354 37.613 ;
     RECT  47.016 37.579 59.397 37.915 ;
     RECT  60.12 36.413 64.797 37.915 ;
     RECT  45.468 34.699 45.897 37.963 ;
     RECT  79.488 37.469 80.997 38.101 ;
     RECT  81.756 34.259 81.774 38.101 ;
     RECT  91.515 32.477 91.797 38.101 ;
     RECT  46.764 37.915 64.797 38.107 ;
     RECT  46.62 38.107 64.797 38.141 ;
     RECT  67.215 35.167 73.278 38.141 ;
     RECT  79.488 38.101 81.774 38.141 ;
     RECT  91.515 38.101 91.89 38.141 ;
     RECT  94.215 37.421 94.497 38.407 ;
     RECT  45.396 37.963 45.897 38.443 ;
     RECT  88.815 35.609 89.097 38.641 ;
     RECT  75.06 36.413 77.238 38.669 ;
     RECT  96.012 31.379 104.058 39.209 ;
     RECT  67.215 38.141 70.197 39.451 ;
     RECT  70.956 38.141 73.278 39.451 ;
     RECT  78.015 37.613 78.297 39.451 ;
     RECT  85.176 37.469 86.397 39.451 ;
     RECT  87.156 37.469 87.174 39.451 ;
     RECT  44.928 38.443 45.897 39.595 ;
     RECT  41.544 36.907 43.974 39.631 ;
     RECT  44.856 39.595 45.897 39.631 ;
     RECT  65.808 37.387 66.438 39.631 ;
     RECT  96.012 39.209 103.194 39.659 ;
     RECT  82.908 35.741 84.078 39.883 ;
     RECT  74.232 36.413 74.25 39.901 ;
     RECT  75.06 38.669 76.878 39.901 ;
     RECT  74.232 39.901 76.878 40.061 ;
     RECT  60.12 38.141 64.797 40.261 ;
     RECT  79.488 38.141 80.997 40.261 ;
     RECT  81.756 38.141 81.774 40.261 ;
     RECT  65.808 39.631 66.474 40.267 ;
     RECT  67.215 39.451 73.278 40.267 ;
     RECT  78.015 39.451 78.678 40.267 ;
     RECT  79.488 40.261 81.774 40.267 ;
     RECT  60.12 40.261 64.89 40.301 ;
     RECT  78.015 40.267 81.774 40.301 ;
     RECT  78.015 40.301 80.997 40.397 ;
     RECT  85.176 39.451 87.174 40.433 ;
     RECT  65.808 40.267 73.278 40.445 ;
     RECT  78.015 40.397 78.39 40.445 ;
     RECT  82.656 39.883 84.078 40.445 ;
     RECT  85.176 40.433 86.418 40.445 ;
     RECT  90.648 39.883 90.666 40.445 ;
     RECT  103.932 39.209 104.058 40.829 ;
     RECT  96.012 39.659 103.086 41.227 ;
     RECT  96.012 41.227 103.194 41.323 ;
     RECT  82.908 40.445 84.078 41.419 ;
     RECT  85.176 40.445 86.397 41.419 ;
     RECT  87.156 40.433 87.174 41.419 ;
     RECT  85.176 41.419 87.174 41.549 ;
     RECT  46.62 38.141 59.397 41.647 ;
     RECT  60.12 40.301 64.797 41.647 ;
     RECT  96.012 41.323 103.23 41.719 ;
     RECT  103.968 40.829 104.058 41.719 ;
     RECT  41.544 39.631 45.897 41.755 ;
     RECT  46.62 41.647 64.797 41.755 ;
     RECT  82.62 41.419 84.078 41.819 ;
     RECT  96.012 41.719 104.058 41.837 ;
     RECT  65.808 40.445 66.474 41.917 ;
     RECT  37.515 37.057 38.466 41.947 ;
     RECT  39.42 25.717 39.474 41.947 ;
     RECT  65.772 41.917 66.474 42.179 ;
     RECT  94.215 38.407 94.914 42.331 ;
     RECT  67.215 40.445 70.197 42.493 ;
     RECT  70.956 40.445 73.278 42.493 ;
     RECT  75.06 40.061 76.878 42.493 ;
     RECT  93.492 42.331 94.914 42.509 ;
     RECT  37.515 41.947 39.474 42.557 ;
     RECT  96.012 41.837 103.194 42.646 ;
     RECT  103.968 41.837 104.058 42.646 ;
     RECT  94.032 42.509 94.914 42.755 ;
     RECT  96.012 42.646 104.058 42.755 ;
     RECT  96.012 42.755 103.986 42.797 ;
     RECT  103.896 42.797 103.986 42.827 ;
     RECT  40.215 22.477 40.734 43.069 ;
     RECT  41.544 41.755 64.797 43.069 ;
     RECT  103.896 42.827 103.95 43.72 ;
     RECT  103.896 43.72 103.986 43.726 ;
     RECT  96.012 42.797 103.086 43.771 ;
     RECT  103.896 43.726 104.058 43.771 ;
     RECT  96.012 43.771 104.058 43.805 ;
     RECT  96.012 43.805 103.95 43.853 ;
     RECT  82.908 41.819 84.078 44.177 ;
     RECT  87.156 41.549 87.174 44.383 ;
     RECT  88.056 38.137 88.074 44.383 ;
     RECT  96.012 43.853 102.978 44.875 ;
     RECT  103.896 43.853 103.95 44.875 ;
     RECT  65.808 42.179 66.474 45.157 ;
     RECT  67.215 42.493 73.278 45.157 ;
     RECT  65.808 45.157 73.278 45.257 ;
     RECT  96.012 44.875 103.95 46.507 ;
     RECT  96.012 46.507 103.986 46.543 ;
     RECT  40.215 43.069 64.797 46.679 ;
     RECT  96.012 46.543 104.058 46.724 ;
     RECT  94.215 42.755 94.914 47.317 ;
     RECT  96.012 46.724 103.194 47.687 ;
     RECT  65.808 45.257 66.474 47.723 ;
     RECT  33.228 47.155 33.246 47.821 ;
     RECT  103.14 47.687 103.194 47.851 ;
     RECT  103.14 47.851 103.23 47.929 ;
     RECT  103.968 46.724 104.058 47.929 ;
     RECT  103.14 47.929 104.058 48.074 ;
     RECT  92.592 40.027 92.61 48.139 ;
     RECT  91.515 38.141 91.797 48.235 ;
     RECT  92.592 48.139 92.898 48.235 ;
     RECT  37.515 42.557 38.466 48.397 ;
     RECT  39.42 42.557 39.474 48.397 ;
     RECT  91.515 48.235 92.898 48.413 ;
     RECT  92.592 48.413 92.898 48.461 ;
     RECT  103.14 48.074 103.986 48.461 ;
     RECT  96.012 47.687 102.402 48.811 ;
     RECT  103.14 48.461 103.194 48.811 ;
     RECT  33.228 47.821 33.57 48.937 ;
     RECT  40.215 46.679 59.634 49.003 ;
     RECT  60.372 46.679 64.797 49.003 ;
     RECT  96.012 48.811 103.194 49.109 ;
     RECT  103.176 49.109 103.194 49.771 ;
     RECT  103.932 48.461 103.986 49.771 ;
     RECT  103.176 49.771 103.986 49.883 ;
     RECT  32.115 2.413 32.397 49.891 ;
     RECT  33.192 48.937 33.57 49.891 ;
     RECT  96.012 49.109 102.402 50.059 ;
     RECT  103.176 49.883 103.194 50.059 ;
     RECT  34.524 31.153 35.838 50.125 ;
     RECT  96.012 50.059 103.194 50.153 ;
     RECT  78.015 40.445 78.297 50.155 ;
     RECT  85.176 41.549 86.397 50.155 ;
     RECT  87.156 44.383 88.074 50.155 ;
     RECT  32.115 49.891 33.57 50.323 ;
     RECT  34.524 50.125 35.91 50.323 ;
     RECT  78.015 50.155 78.678 50.333 ;
     RECT  85.176 50.155 88.074 50.333 ;
     RECT  37.515 48.397 39.474 50.359 ;
     RECT  65.808 47.723 66.438 50.423 ;
     RECT  65.916 50.423 66.438 50.665 ;
     RECT  67.215 45.257 73.278 50.665 ;
     RECT  96.012 50.153 102.69 51.019 ;
     RECT  96.012 51.019 103.194 51.089 ;
     RECT  96.012 51.089 102.654 51.115 ;
     RECT  32.115 50.323 35.91 51.511 ;
     RECT  36.792 50.359 39.474 51.511 ;
     RECT  95.724 51.115 102.654 51.629 ;
     RECT  103.932 49.883 103.986 51.673 ;
     RECT  103.896 51.673 103.986 51.736 ;
     RECT  32.115 51.511 39.474 51.745 ;
     RECT  40.215 49.003 64.797 51.745 ;
     RECT  103.896 51.736 104.058 51.773 ;
     RECT  103.896 51.773 103.986 51.821 ;
     RECT  74.232 40.061 74.25 52.285 ;
     RECT  75.06 42.493 77.238 52.285 ;
     RECT  74.232 52.285 77.238 52.439 ;
     RECT  2.415 2.413 2.697 52.681 ;
     RECT  2.412 52.681 2.697 52.781 ;
     RECT  96.012 51.629 102.654 52.825 ;
     RECT  103.896 51.821 103.95 52.825 ;
     RECT  79.488 40.397 80.997 52.889 ;
     RECT  96.012 52.825 103.95 53.393 ;
     RECT  103.176 53.393 103.95 53.519 ;
     RECT  32.115 51.745 64.797 54.059 ;
     RECT  103.212 53.519 103.95 54.283 ;
     RECT  96.012 53.393 102.366 54.379 ;
     RECT  95.688 54.379 102.366 54.472 ;
     RECT  103.176 54.283 103.95 54.472 ;
     RECT  95.688 54.472 103.95 54.509 ;
     RECT  65.916 50.665 73.278 54.607 ;
     RECT  47.628 54.059 64.797 54.869 ;
     RECT  93.744 47.317 94.914 54.955 ;
     RECT  95.688 54.509 102.366 54.955 ;
     RECT  93.744 54.955 102.366 54.977 ;
     RECT  32.115 54.059 46.89 54.989 ;
     RECT  103.176 54.509 103.95 55.003 ;
     RECT  93.744 54.977 95.166 55.049 ;
     RECT  96.012 54.977 102.366 55.243 ;
     RECT  103.176 55.003 104.058 55.243 ;
     RECT  96.012 55.243 104.058 55.247 ;
     RECT  65.556 54.607 73.278 55.373 ;
     RECT  103.896 55.247 104.058 55.709 ;
     RECT  48.315 54.869 64.797 55.757 ;
     RECT  96.012 55.247 102.654 56.011 ;
     RECT  103.896 55.709 103.95 56.011 ;
     RECT  58.284 55.757 64.797 56.065 ;
     RECT  48.315 55.757 57.546 56.191 ;
     RECT  96.012 56.011 103.95 56.327 ;
     RECT  103.176 56.327 103.95 56.489 ;
     RECT  96.012 56.327 102.366 56.491 ;
     RECT  32.115 54.989 44.442 56.533 ;
     RECT  45.252 54.989 46.89 56.533 ;
     RECT  103.176 56.489 103.914 56.759 ;
     RECT  48.204 56.191 57.546 56.765 ;
     RECT  95.724 56.491 102.366 56.779 ;
     RECT  48.315 56.765 57.546 56.813 ;
     RECT  103.176 56.759 103.23 56.867 ;
     RECT  95.688 56.779 102.366 57.064 ;
     RECT  58.284 56.065 64.854 57.109 ;
     RECT  65.916 55.373 73.278 57.109 ;
     RECT  93.744 55.049 94.914 57.301 ;
     RECT  95.652 57.064 102.366 57.301 ;
     RECT  103.968 57.259 103.986 57.307 ;
     RECT  103.968 57.307 104.058 57.335 ;
     RECT  93.744 57.301 102.366 57.341 ;
     RECT  104.04 57.335 104.058 57.344 ;
     RECT  95.652 57.341 102.366 57.479 ;
     RECT  96.012 57.479 102.366 57.569 ;
     RECT  103.176 56.867 103.194 57.713 ;
     RECT  79.632 52.889 80.997 57.749 ;
     RECT  85.176 50.333 86.397 58.145 ;
     RECT  103.968 58.315 103.986 58.351 ;
     RECT  103.968 58.351 104.058 58.379 ;
     RECT  104.04 58.379 104.058 58.397 ;
     RECT  103.176 58.621 103.194 58.733 ;
     RECT  96.012 57.569 102.294 59.275 ;
     RECT  103.968 59.659 103.986 59.701 ;
     RECT  96.012 59.275 102.618 59.801 ;
     RECT  93.744 57.341 94.914 59.873 ;
     RECT  48.315 56.813 57.042 59.885 ;
     RECT  87.156 50.333 88.074 59.999 ;
     RECT  103.968 59.701 104.058 59.999 ;
     RECT  104.04 59.999 104.058 60.029 ;
     RECT  82.908 44.177 83.697 60.043 ;
     RECT  85.176 58.145 85.23 60.071 ;
     RECT  82.656 60.043 83.697 60.115 ;
     RECT  82.656 60.115 83.898 60.143 ;
     RECT  103.176 60.331 103.194 60.557 ;
     RECT  48.315 59.885 55.422 60.691 ;
     RECT  96.012 59.801 102.294 60.715 ;
     RECT  96.012 60.715 102.618 61.387 ;
     RECT  48.024 60.691 55.422 61.897 ;
     RECT  56.16 59.885 57.042 61.897 ;
     RECT  48.024 61.897 57.042 61.963 ;
     RECT  48.024 61.963 57.078 62.011 ;
     RECT  104.04 62.011 104.058 62.041 ;
     RECT  82.908 60.143 83.898 62.131 ;
     RECT  82.656 62.131 83.898 62.231 ;
     RECT  78.015 50.333 78.297 62.239 ;
     RECT  78.015 62.239 78.678 62.339 ;
     RECT  103.968 62.041 104.058 62.339 ;
     RECT  103.968 62.339 103.986 62.381 ;
     RECT  48.024 62.011 57.402 62.429 ;
     RECT  50.544 62.429 57.402 62.437 ;
     RECT  50.544 62.437 57.51 62.671 ;
     RECT  58.284 57.109 73.278 62.671 ;
     RECT  91.515 48.413 91.797 63.019 ;
     RECT  92.592 48.461 92.61 63.019 ;
     RECT  91.515 63.019 92.61 63.149 ;
     RECT  96.012 61.387 103.194 63.617 ;
     RECT  78.015 62.339 78.297 63.625 ;
     RECT  50.544 62.671 73.278 63.779 ;
     RECT  78.015 63.625 78.822 63.779 ;
     RECT  103.176 63.617 103.194 63.979 ;
     RECT  75.06 52.439 77.238 64.193 ;
     RECT  103.176 63.979 103.23 64.355 ;
     RECT  103.176 64.355 103.194 64.357 ;
     RECT  50.544 63.779 73.242 64.685 ;
     RECT  96.012 63.617 102.294 64.747 ;
     RECT  103.14 64.357 103.194 64.747 ;
     RECT  48.024 62.429 49.554 64.859 ;
     RECT  96.012 64.747 103.194 65.003 ;
     RECT  92.592 63.149 92.61 65.273 ;
     RECT  96.012 65.003 102.294 65.273 ;
     RECT  96.012 65.273 101.466 65.309 ;
     RECT  104.04 65.275 104.058 65.32 ;
     RECT  103.968 65.32 104.058 65.354 ;
     RECT  103.968 65.354 103.986 65.357 ;
     RECT  103.176 65.003 103.194 65.704 ;
     RECT  88.056 59.999 88.074 65.777 ;
     RECT  94.215 59.873 94.914 65.813 ;
     RECT  102.276 65.273 102.294 65.983 ;
     RECT  103.176 65.704 103.23 65.983 ;
     RECT  96.012 65.309 101.286 66.091 ;
     RECT  93.456 65.947 93.474 66.245 ;
     RECT  96.012 66.091 101.466 66.331 ;
     RECT  102.276 65.983 103.23 66.353 ;
     RECT  104.04 66.331 104.058 66.361 ;
     RECT  103.968 66.361 104.058 66.389 ;
     RECT  103.968 66.389 103.986 66.413 ;
     RECT  95.724 66.331 101.466 66.475 ;
     RECT  86.115 58.145 86.397 66.523 ;
     RECT  87.156 59.999 87.174 66.523 ;
     RECT  95.724 66.475 101.502 66.551 ;
     RECT  86.115 66.523 87.174 66.653 ;
     RECT  90.648 66.523 90.666 66.653 ;
     RECT  94.215 65.813 94.59 66.653 ;
     RECT  82.908 62.231 83.898 66.721 ;
     RECT  82.908 66.721 84.042 66.821 ;
     RECT  103.176 66.353 103.23 66.829 ;
     RECT  85.176 60.071 85.194 66.865 ;
     RECT  86.115 66.653 86.397 66.865 ;
     RECT  50.544 64.685 52.47 67.085 ;
     RECT  85.176 66.865 86.397 67.091 ;
     RECT  96.012 66.551 101.502 67.199 ;
     RECT  102.276 66.353 102.294 67.243 ;
     RECT  103.176 66.829 103.266 67.243 ;
     RECT  102.276 67.243 103.266 67.289 ;
     RECT  96.012 67.199 101.466 67.819 ;
     RECT  88.815 38.641 89.766 67.901 ;
     RECT  95.724 67.819 101.466 67.973 ;
     RECT  104.04 67.963 104.058 67.981 ;
     RECT  103.968 67.981 104.058 68.009 ;
     RECT  103.968 68.009 103.986 68.045 ;
     RECT  84.888 67.909 84.906 68.071 ;
     RECT  84.816 68.071 84.906 68.099 ;
     RECT  102.276 67.289 102.654 68.101 ;
     RECT  96.012 67.973 101.466 68.171 ;
     RECT  81.756 40.301 81.774 68.251 ;
     RECT  82.908 66.821 83.898 68.251 ;
     RECT  81.756 68.251 83.898 68.369 ;
     RECT  32.115 56.533 46.89 68.683 ;
     RECT  102.276 68.101 103.194 68.747 ;
     RECT  103.176 68.747 103.194 68.755 ;
     RECT  103.176 68.755 103.23 68.813 ;
     RECT  103.176 68.813 103.194 68.981 ;
     RECT  81.756 68.369 82.134 69.179 ;
     RECT  80.064 57.749 80.997 69.259 ;
     RECT  96.012 68.171 101.286 69.259 ;
     RECT  80.064 69.259 81.378 69.331 ;
     RECT  96.012 69.259 101.466 69.331 ;
     RECT  102.276 68.747 102.294 69.331 ;
     RECT  79.488 69.331 81.378 69.359 ;
     RECT  96.012 69.331 102.294 69.389 ;
     RECT  102.276 69.389 102.294 69.547 ;
     RECT  102.276 69.547 102.582 70.219 ;
     RECT  102.276 70.219 102.618 70.259 ;
     RECT  32.115 68.683 46.962 70.915 ;
     RECT  48.315 64.859 49.554 71.077 ;
     RECT  32.115 70.915 47.394 71.083 ;
     RECT  48.315 71.077 49.698 71.083 ;
     RECT  96.012 69.389 101.466 71.105 ;
     RECT  102.276 70.259 102.294 71.179 ;
     RECT  103.968 71.275 103.986 71.311 ;
     RECT  103.968 71.311 104.058 71.339 ;
     RECT  104.04 71.339 104.058 71.357 ;
     RECT  32.115 71.083 49.698 71.851 ;
     RECT  50.544 67.085 52.326 71.851 ;
     RECT  102.276 71.179 102.654 71.851 ;
     RECT  74.232 52.439 74.25 71.959 ;
     RECT  75.06 64.193 76.878 71.959 ;
     RECT  32.115 71.851 52.326 72.031 ;
     RECT  53.208 64.685 73.242 72.031 ;
     RECT  102.276 71.851 103.194 72.121 ;
     RECT  32.115 72.031 73.242 72.149 ;
     RECT  74.232 71.959 76.878 72.149 ;
     RECT  47.952 72.149 73.242 72.221 ;
     RECT  102.276 72.121 103.23 72.329 ;
     RECT  96.012 71.105 101.286 72.331 ;
     RECT  96.012 72.331 101.466 72.419 ;
     RECT  103.176 72.329 103.23 72.563 ;
     RECT  85.788 67.091 86.397 72.667 ;
     RECT  87.156 66.653 87.174 72.667 ;
     RECT  94.215 66.653 94.497 72.667 ;
     RECT  104.04 72.667 104.058 72.697 ;
     RECT  103.968 72.697 104.058 72.725 ;
     RECT  103.968 72.725 103.986 72.749 ;
     RECT  85.788 72.667 87.174 72.797 ;
     RECT  90.648 72.667 90.666 72.797 ;
     RECT  94.215 72.667 94.59 72.797 ;
     RECT  102.276 72.329 102.294 73.099 ;
     RECT  103.176 72.563 103.194 73.099 ;
     RECT  32.115 72.149 47.214 73.111 ;
     RECT  47.952 72.221 70.938 73.111 ;
     RECT  96.012 72.419 101.286 73.229 ;
     RECT  102.276 73.099 103.194 73.579 ;
     RECT  101.268 73.229 101.286 73.675 ;
     RECT  102.276 73.579 103.23 73.805 ;
     RECT  102.276 73.805 103.194 74.309 ;
     RECT  102.276 74.309 102.618 74.381 ;
     RECT  101.268 73.675 101.466 74.539 ;
     RECT  102.276 74.381 102.294 74.539 ;
     RECT  96.012 73.229 100.494 75.211 ;
     RECT  101.268 74.539 102.294 75.211 ;
     RECT  96.012 75.211 102.294 75.263 ;
     RECT  96.012 75.263 101.466 75.299 ;
     RECT  102.276 75.263 102.294 75.307 ;
     RECT  102.276 75.307 102.618 75.403 ;
     RECT  102.276 75.403 102.654 75.787 ;
     RECT  101.268 75.299 101.466 76.075 ;
     RECT  102.276 75.787 102.69 76.075 ;
     RECT  101.268 76.075 102.69 76.199 ;
     RECT  101.268 76.199 102.294 76.469 ;
     RECT  94.215 72.797 94.497 76.555 ;
     RECT  94.215 76.555 94.626 76.775 ;
     RECT  104.04 77.656 104.058 77.665 ;
     RECT  103.968 77.665 104.058 77.693 ;
     RECT  103.968 77.693 103.986 77.741 ;
     RECT  103.176 76.459 103.194 77.803 ;
     RECT  32.115 73.111 70.938 77.819 ;
     RECT  103.176 77.803 103.23 77.899 ;
     RECT  103.14 77.899 103.23 77.999 ;
     RECT  101.268 76.469 101.286 78.187 ;
     RECT  102.276 76.469 102.294 78.187 ;
     RECT  101.268 78.187 102.294 78.413 ;
     RECT  102.276 78.413 102.294 78.475 ;
     RECT  103.14 77.999 103.194 78.475 ;
     RECT  101.268 78.413 101.502 78.605 ;
     RECT  74.232 72.149 74.25 78.629 ;
     RECT  85.788 72.797 86.397 79.003 ;
     RECT  87.156 72.797 87.174 79.003 ;
     RECT  94.215 76.775 94.497 79.003 ;
     RECT  85.788 79.003 87.174 79.181 ;
     RECT  90.648 79.003 90.666 79.181 ;
     RECT  102.276 78.475 103.194 79.205 ;
     RECT  96.012 75.299 100.494 79.243 ;
     RECT  94.215 79.003 94.59 79.321 ;
     RECT  95.724 79.243 100.494 79.321 ;
     RECT  101.268 78.605 101.286 79.339 ;
     RECT  94.215 79.321 100.494 79.469 ;
     RECT  95.724 79.469 100.494 79.511 ;
     RECT  96.012 79.511 100.494 79.591 ;
     RECT  101.268 79.339 101.466 79.591 ;
     RECT  102.276 79.205 102.294 79.591 ;
     RECT  72.072 72.221 73.242 79.619 ;
     RECT  96.012 79.591 102.294 79.661 ;
     RECT  103.176 79.205 103.194 79.681 ;
     RECT  103.176 79.681 103.266 79.817 ;
     RECT  103.212 79.817 103.266 79.853 ;
     RECT  103.212 79.853 103.23 79.979 ;
     RECT  96.012 79.661 101.286 80.249 ;
     RECT  82.908 68.369 83.898 80.663 ;
     RECT  32.115 77.819 70.83 80.669 ;
     RECT  75.06 72.149 76.878 81.059 ;
     RECT  75.06 81.059 76.662 81.211 ;
     RECT  101.268 80.249 101.286 82.949 ;
     RECT  53.064 80.669 70.83 82.957 ;
     RECT  78.015 63.779 78.714 84.721 ;
     RECT  102.276 79.661 102.294 85.109 ;
     RECT  74.916 81.211 76.662 85.621 ;
     RECT  74.376 85.621 76.662 85.649 ;
     RECT  32.115 80.669 52.326 85.801 ;
     RECT  85.788 79.181 86.397 86.333 ;
     RECT  96.012 80.249 100.494 88.349 ;
     RECT  88.056 88.591 88.074 88.637 ;
     RECT  98.316 88.349 100.494 91.589 ;
     RECT  32.076 85.801 52.326 91.597 ;
     RECT  53.064 82.957 70.974 91.597 ;
     RECT  32.076 91.597 70.974 91.661 ;
     RECT  96.012 88.349 97.197 92.669 ;
     RECT  32.076 91.661 52.326 93.019 ;
     RECT  53.064 91.661 70.974 93.019 ;
     RECT  83.415 80.663 83.898 95.501 ;
     RECT  79.488 69.359 80.997 96.029 ;
     RECT  98.316 91.589 100.026 98.915 ;
     RECT  84.816 68.099 84.834 99.491 ;
     RECT  76.644 85.649 76.662 100.067 ;
     RECT  92.808 98.311 92.826 100.111 ;
     RECT  98.892 98.915 100.026 100.139 ;
     RECT  92.808 100.111 92.898 100.229 ;
     RECT  79.488 96.029 79.506 100.349 ;
     RECT  74.376 85.649 75.597 100.499 ;
     RECT  74.376 100.499 74.394 100.571 ;
     RECT  77.796 84.721 78.714 100.589 ;
     RECT  77.796 100.589 78.297 100.637 ;
     RECT  32.076 93.019 70.974 100.741 ;
     RECT  31.932 100.741 70.974 100.877 ;
     RECT  93.168 101.083 93.186 101.309 ;
     RECT  99.432 100.139 100.026 101.309 ;
     RECT  82.116 69.179 82.134 101.405 ;
     RECT  31.932 100.877 70.362 101.417 ;
     RECT  31.932 101.417 70.197 101.579 ;
     RECT  99.615 101.309 100.026 101.579 ;
     RECT  84.924 99.547 84.942 101.731 ;
     RECT  31.932 101.579 68.13 102.001 ;
     RECT  84.924 101.731 85.302 102.029 ;
     RECT  31.896 102.001 68.13 102.127 ;
     RECT  31.356 102.127 68.13 102.299 ;
     RECT  31.356 102.299 68.094 102.389 ;
     RECT  84.924 102.029 84.942 102.389 ;
     RECT  87.156 79.181 87.174 102.389 ;
     RECT  69.012 101.579 70.197 102.569 ;
     RECT  31.356 102.389 67.698 102.631 ;
     RECT  96.588 92.669 97.197 102.659 ;
     RECT  31.212 102.631 67.698 102.929 ;
     RECT  2.415 52.781 2.697 103.157 ;
     RECT  5.115 2.413 5.397 103.157 ;
     RECT  7.815 2.413 8.097 103.157 ;
     RECT  10.515 2.413 10.797 103.157 ;
     RECT  13.215 2.413 13.497 103.157 ;
     RECT  15.915 2.413 16.197 103.157 ;
     RECT  18.615 2.413 18.897 103.157 ;
     RECT  21.315 2.413 21.597 103.157 ;
     RECT  24.015 2.413 24.297 103.157 ;
     RECT  26.715 2.413 26.997 103.157 ;
     RECT  29.415 2.413 29.697 103.157 ;
     RECT  75.315 100.499 75.597 103.157 ;
     RECT  78.015 100.637 78.297 103.157 ;
     RECT  80.715 96.029 80.997 103.157 ;
     RECT  83.415 95.501 83.697 103.157 ;
     RECT  86.115 86.333 86.397 103.157 ;
     RECT  88.815 67.901 89.097 103.157 ;
     RECT  91.515 63.149 91.797 103.157 ;
     RECT  94.215 79.469 94.497 103.157 ;
     RECT  96.915 102.659 97.197 103.157 ;
     RECT  99.615 101.579 99.897 103.157 ;
     RECT  72.072 79.619 72.897 103.379 ;
     RECT  2.607 103.157 2.697 103.427 ;
     RECT  5.307 103.157 5.397 103.427 ;
     RECT  8.007 103.157 8.097 103.427 ;
     RECT  10.707 103.157 10.797 103.427 ;
     RECT  13.407 103.157 13.497 103.427 ;
     RECT  16.107 103.157 16.197 103.427 ;
     RECT  18.807 103.157 18.897 103.427 ;
     RECT  21.507 103.157 21.597 103.427 ;
     RECT  24.207 103.157 24.297 103.427 ;
     RECT  26.907 103.157 26.997 103.427 ;
     RECT  29.607 103.157 29.697 103.427 ;
     RECT  69.048 102.569 70.197 103.427 ;
     RECT  72.807 103.379 72.897 103.427 ;
     RECT  75.507 103.157 75.597 103.427 ;
     RECT  78.207 103.157 78.297 103.427 ;
     RECT  80.907 103.157 80.997 103.427 ;
     RECT  83.607 103.157 83.697 103.427 ;
     RECT  86.307 103.157 86.397 103.427 ;
     RECT  89.007 103.157 89.097 103.427 ;
     RECT  91.707 103.157 91.797 103.427 ;
     RECT  94.407 103.157 94.497 103.427 ;
     RECT  97.107 103.157 97.197 103.427 ;
     RECT  99.807 103.157 99.897 103.427 ;
     RECT  31.248 102.929 67.698 103.541 ;
     RECT  31.248 103.541 67.59 103.577 ;
     RECT  69.048 103.427 69.57 103.577 ;
     RECT  31.248 103.577 64.278 103.613 ;
     RECT  69.048 103.577 69.066 103.613 ;
     RECT  31.248 103.613 61.578 103.661 ;
     RECT  31.248 103.661 61.398 103.739 ;
     RECT  65.052 103.577 67.59 103.739 ;
     RECT  31.968 103.739 61.398 103.811 ;
     RECT  65.232 103.739 67.59 104.045 ;
     RECT  62.316 103.613 64.278 104.093 ;
     RECT  65.232 104.045 67.266 104.717 ;
     RECT  61.164 103.811 61.398 104.827 ;
     RECT  62.316 104.093 62.694 104.827 ;
     RECT  63.612 104.093 64.278 104.827 ;
     RECT  65.232 104.717 66.834 104.861 ;
     RECT  31.968 103.811 60.426 104.971 ;
     RECT  61.164 104.827 62.694 104.971 ;
     RECT  31.968 104.971 62.694 105.101 ;
     RECT  66.384 104.861 66.834 105.389 ;
     RECT  61.164 105.101 62.694 105.437 ;
     RECT  66.492 105.389 66.834 105.437 ;
     RECT  61.884 105.437 62.694 105.533 ;
     RECT  31.968 105.101 60.426 105.629 ;
     RECT  63.612 104.827 64.386 105.629 ;
     RECT  63.864 105.629 64.386 105.677 ;
     RECT  32.004 105.629 60.426 105.701 ;
     RECT  61.884 105.533 61.902 105.725 ;
     RECT  65.232 104.861 65.25 105.725 ;
     RECT  32.04 105.701 60.426 105.773 ;
     RECT  62.748 105.547 62.766 105.773 ;
     RECT  66.816 105.437 66.834 105.773 ;
     RECT  32.148 105.773 60.318 105.804 ;
     RECT  58.824 105.804 59.13 105.809 ;
    LAYER M4 ;
     RECT  0.06 52.752 0.227 52.872 ;
     RECT  0.227 52.752 2.408 52.776 ;
     RECT  0.181 89.52 2.408 89.544 ;
     RECT  2.408 2.148 2.512 103.152 ;
     RECT  2.512 2.418 2.6 103.152 ;
     RECT  2.6 2.418 2.704 103.422 ;
     RECT  2.704 52.704 5.108 52.728 ;
     RECT  2.704 89.52 5.108 89.544 ;
     RECT  5.108 2.148 5.212 103.152 ;
     RECT  5.212 2.418 5.3 103.152 ;
     RECT  5.3 2.418 5.404 103.422 ;
     RECT  5.404 52.704 7.808 52.728 ;
     RECT  5.404 89.52 7.808 89.544 ;
     RECT  7.808 2.148 7.912 103.152 ;
     RECT  7.912 2.418 8 103.152 ;
     RECT  8 2.418 8.104 103.422 ;
     RECT  8.104 52.704 10.508 52.728 ;
     RECT  8.104 89.52 10.508 89.544 ;
     RECT  10.508 2.148 10.612 103.152 ;
     RECT  10.612 2.418 10.7 103.152 ;
     RECT  10.7 2.418 10.804 103.422 ;
     RECT  10.804 52.704 13.208 52.728 ;
     RECT  10.804 89.52 13.208 89.544 ;
     RECT  13.208 2.148 13.312 103.152 ;
     RECT  13.312 2.418 13.4 103.152 ;
     RECT  13.4 2.418 13.504 103.422 ;
     RECT  13.504 52.704 15.908 52.728 ;
     RECT  13.504 89.52 15.908 89.544 ;
     RECT  15.908 2.148 16.012 103.152 ;
     RECT  16.012 2.418 16.1 103.152 ;
     RECT  16.1 2.418 16.204 103.422 ;
     RECT  16.204 52.704 18.608 52.728 ;
     RECT  16.204 89.52 18.608 89.544 ;
     RECT  18.608 2.148 18.712 103.152 ;
     RECT  18.712 2.418 18.8 103.152 ;
     RECT  18.8 2.418 18.904 103.422 ;
     RECT  18.904 52.704 21.308 52.728 ;
     RECT  18.904 89.52 21.308 89.544 ;
     RECT  21.308 2.148 21.412 103.152 ;
     RECT  21.412 2.418 21.5 103.152 ;
     RECT  21.5 2.418 21.604 103.422 ;
     RECT  21.604 52.704 24.008 52.728 ;
     RECT  21.604 89.52 24.008 89.544 ;
     RECT  24.008 2.148 24.112 103.152 ;
     RECT  24.112 2.418 24.2 103.152 ;
     RECT  24.2 2.418 24.304 103.422 ;
     RECT  24.304 52.704 26.708 52.728 ;
     RECT  24.304 89.52 26.708 89.544 ;
     RECT  26.708 2.148 26.812 103.152 ;
     RECT  26.812 2.418 26.9 103.152 ;
     RECT  26.9 2.418 27.004 103.422 ;
     RECT  27.004 52.704 29.408 52.728 ;
     RECT  27.004 89.52 29.408 89.544 ;
     RECT  29.408 2.148 29.512 103.152 ;
     RECT  29.512 2.418 29.6 103.152 ;
     RECT  29.6 2.418 29.704 103.422 ;
     RECT  29.704 52.704 32.108 52.728 ;
     RECT  29.704 89.52 32.108 89.544 ;
     RECT  32.108 2.148 32.137 103.152 ;
     RECT  32.137 2.148 32.212 103.464 ;
     RECT  32.212 2.418 32.249 103.464 ;
     RECT  32.249 2.418 32.404 103.422 ;
     RECT  32.404 101.712 33.217 103.422 ;
     RECT  33.217 101.712 33.473 103.704 ;
     RECT  32.404 99.168 33.505 100.344 ;
     RECT  33.473 101.712 33.505 103.272 ;
     RECT  33.505 99.168 33.509 103.272 ;
     RECT  33.253 105.744 33.545 105.768 ;
     RECT  33.509 99.168 33.653 103.128 ;
     RECT  34.261 54.384 34.309 54.408 ;
     RECT  32.404 52.704 34.405 52.728 ;
     RECT  34.165 51.168 34.501 51.192 ;
     RECT  34.309 54.384 34.549 54.984 ;
     RECT  34.405 52.176 34.645 52.728 ;
     RECT  33.653 99.168 34.693 102.696 ;
     RECT  34.405 105.6 34.769 105.624 ;
     RECT  34.693 48.72 34.808 48.744 ;
     RECT  34.501 51.12 34.808 51.192 ;
     RECT  34.645 52.176 34.808 53.016 ;
     RECT  34.549 54.384 34.808 55.56 ;
     RECT  34.117 60.096 34.808 60.12 ;
     RECT  32.404 67.104 34.808 67.128 ;
     RECT  33.493 74.928 34.808 74.952 ;
     RECT  34.357 77.136 34.808 77.16 ;
     RECT  34.597 82.944 34.808 82.968 ;
     RECT  32.404 86.304 34.808 86.328 ;
     RECT  32.404 89.52 34.808 89.544 ;
     RECT  34.021 90.864 34.808 90.888 ;
     RECT  34.333 97.488 34.808 97.512 ;
     RECT  34.693 99.168 34.808 103.224 ;
     RECT  34.808 2.148 34.912 103.224 ;
     RECT  34.912 2.418 35 103.224 ;
     RECT  35 2.418 35.104 103.422 ;
     RECT  35.104 50.736 35.363 55.56 ;
     RECT  35.053 105.744 35.705 105.768 ;
     RECT  35.104 62.64 36.073 62.664 ;
     RECT  35.363 51.12 36.181 55.56 ;
     RECT  35.104 60.096 36.277 61.176 ;
     RECT  35.104 41.376 36.565 42.024 ;
     RECT  35.104 77.136 36.613 77.16 ;
     RECT  36.613 77.136 36.661 77.352 ;
     RECT  35.104 67.104 36.709 67.128 ;
     RECT  36.181 51.12 36.757 56.04 ;
     RECT  35.104 89.52 36.901 89.544 ;
     RECT  35.104 90.864 36.901 90.888 ;
     RECT  36.805 57.312 37.285 57.336 ;
     RECT  36.757 51.12 37.381 56.328 ;
     RECT  36.565 41.376 37.508 42.552 ;
     RECT  35.104 48.72 37.508 48.744 ;
     RECT  37.381 50.832 37.508 56.328 ;
     RECT  37.285 57.312 37.508 57.384 ;
     RECT  36.277 60.096 37.508 61.464 ;
     RECT  36.229 62.448 37.508 62.472 ;
     RECT  36.709 67.056 37.508 67.128 ;
     RECT  35.104 71.616 37.508 71.64 ;
     RECT  35.104 74.928 37.508 74.952 ;
     RECT  36.661 77.136 37.508 77.928 ;
     RECT  36.421 80.64 37.508 80.664 ;
     RECT  35.104 82.416 37.508 82.968 ;
     RECT  36.853 84.384 37.508 84.408 ;
     RECT  35.104 86.304 37.508 86.328 ;
     RECT  36.901 89.52 37.508 90.888 ;
     RECT  35.104 97.872 37.508 103.32 ;
     RECT  37.508 2.148 37.537 103.32 ;
     RECT  37.537 2.148 37.612 103.368 ;
     RECT  37.612 2.418 37.7 103.368 ;
     RECT  37.7 2.418 37.804 103.422 ;
     RECT  37.804 82.032 38.305 82.44 ;
     RECT  37.804 86.304 38.387 87.24 ;
     RECT  37.804 67.008 38.801 67.272 ;
     RECT  37.804 71.616 38.869 71.64 ;
     RECT  37.804 74.928 39.013 74.952 ;
     RECT  37.804 60.096 39.053 61.464 ;
     RECT  38.965 63.84 39.089 63.864 ;
     RECT  38.801 67.056 39.109 67.272 ;
     RECT  39.013 74.352 39.157 74.952 ;
     RECT  39.053 60.096 39.205 61.368 ;
     RECT  37.804 68.928 39.301 68.952 ;
     RECT  37.321 105.744 39.491 105.768 ;
     RECT  37.804 41.376 39.541 42.552 ;
     RECT  37.804 57.312 39.589 57.384 ;
     RECT  37.804 58.368 39.589 58.488 ;
     RECT  37.804 97.872 39.661 103.32 ;
     RECT  37.804 90.864 39.685 90.888 ;
     RECT  38.869 71.232 39.733 71.64 ;
     RECT  37.804 50.832 40.021 56.328 ;
     RECT  39.589 57.312 40.021 58.488 ;
     RECT  39.661 97.536 40.069 103.32 ;
     RECT  39.541 41.184 40.208 42.552 ;
     RECT  37.804 48.72 40.208 48.744 ;
     RECT  40.021 50.832 40.208 58.488 ;
     RECT  39.205 59.52 40.208 61.368 ;
     RECT  37.804 62.448 40.208 62.472 ;
     RECT  39.109 67.056 40.208 67.656 ;
     RECT  39.301 68.928 40.208 69.576 ;
     RECT  39.733 70.848 40.208 71.64 ;
     RECT  39.157 73.488 40.208 74.952 ;
     RECT  37.804 77.136 40.208 77.928 ;
     RECT  37.804 80.64 40.208 80.664 ;
     RECT  38.305 82.416 40.208 82.44 ;
     RECT  37.804 85.2 40.208 85.224 ;
     RECT  38.387 86.304 40.208 86.328 ;
     RECT  39.493 88.32 40.208 88.344 ;
     RECT  37.804 89.52 40.208 89.544 ;
     RECT  39.685 90.864 40.208 91.656 ;
     RECT  37.804 95.472 40.208 96.024 ;
     RECT  40.069 97.536 40.208 103.368 ;
     RECT  40.208 2.148 40.312 103.368 ;
     RECT  40.312 2.418 40.4 103.368 ;
     RECT  40.4 2.418 40.504 103.422 ;
     RECT  40.504 95.472 40.525 103.422 ;
     RECT  40.504 62.448 40.601 62.472 ;
     RECT  40.525 95.472 41.389 103.512 ;
     RECT  40.504 59.52 41.557 61.368 ;
     RECT  40.504 79.2 41.573 79.224 ;
     RECT  40.504 49.776 41.609 49.8 ;
     RECT  40.504 41.184 41.701 42.552 ;
     RECT  41.389 95.472 41.753 103.752 ;
     RECT  41.509 105.744 42.181 105.768 ;
     RECT  40.504 73.776 42.517 75.528 ;
     RECT  40.504 77.136 42.517 77.928 ;
     RECT  41.753 95.472 42.661 103.512 ;
     RECT  42.181 105.648 42.757 105.768 ;
     RECT  41.533 26.592 42.908 26.616 ;
     RECT  41.701 41.184 42.908 43.032 ;
     RECT  40.504 48.72 42.908 48.744 ;
     RECT  41.797 49.824 42.908 49.848 ;
     RECT  40.504 50.832 42.908 57.336 ;
     RECT  40.504 58.464 42.908 58.488 ;
     RECT  41.557 59.52 42.908 61.992 ;
     RECT  40.504 67.056 42.908 67.656 ;
     RECT  40.504 68.928 42.908 68.952 ;
     RECT  40.504 70.848 42.908 71.64 ;
     RECT  42.565 72.72 42.908 72.744 ;
     RECT  42.517 73.776 42.908 77.928 ;
     RECT  42.793 79.44 42.908 79.464 ;
     RECT  40.504 80.64 42.908 82.44 ;
     RECT  40.504 84.912 42.908 85.224 ;
     RECT  40.504 86.304 42.908 86.328 ;
     RECT  42.469 87.552 42.908 87.576 ;
     RECT  40.504 89.52 42.908 89.544 ;
     RECT  40.504 90.864 42.908 91.656 ;
     RECT  42.085 92.88 42.908 92.904 ;
     RECT  42.661 94.608 42.908 103.512 ;
     RECT  42.908 2.148 43.009 103.512 ;
     RECT  43.009 2.148 43.012 103.752 ;
     RECT  43.012 2.418 43.204 103.752 ;
     RECT  43.204 94.8 43.333 103.752 ;
     RECT  43.333 94.8 43.429 104.424 ;
     RECT  43.429 94.8 43.525 104.568 ;
     RECT  42.757 105.6 43.525 105.768 ;
     RECT  43.204 67.056 43.661 67.656 ;
     RECT  43.204 84.912 43.661 85.224 ;
     RECT  43.204 49.824 43.715 57.336 ;
     RECT  43.204 77.136 43.841 78.072 ;
     RECT  43.204 82.416 43.913 82.44 ;
     RECT  43.525 94.8 43.955 105.768 ;
     RECT  43.715 50.832 44.345 57.336 ;
     RECT  43.204 79.2 44.345 79.224 ;
     RECT  43.204 59.52 44.381 61.992 ;
     RECT  43.955 94.8 44.444 103.512 ;
     RECT  43.715 49.824 44.453 49.848 ;
     RECT  44.444 94.608 44.629 103.512 ;
     RECT  44.629 94.56 45.013 103.512 ;
     RECT  44.345 50.832 45.133 56.856 ;
     RECT  43.955 104.832 45.317 105.768 ;
     RECT  45.013 94.56 45.445 103.56 ;
     RECT  45.445 94.032 45.529 103.56 ;
     RECT  43.204 26.592 45.608 26.616 ;
     RECT  43.204 28.944 45.608 28.968 ;
     RECT  45.457 34.704 45.608 34.728 ;
     RECT  43.204 36.912 45.608 36.936 ;
     RECT  45.385 37.968 45.608 37.992 ;
     RECT  43.204 41.184 45.608 43.032 ;
     RECT  44.917 47.616 45.608 47.64 ;
     RECT  43.204 48.72 45.608 48.744 ;
     RECT  45.133 50.736 45.608 56.856 ;
     RECT  43.204 58.464 45.608 58.488 ;
     RECT  44.381 59.52 45.608 60.12 ;
     RECT  44.381 61.104 45.608 61.992 ;
     RECT  43.661 67.104 45.608 67.656 ;
     RECT  43.204 70.848 45.608 71.64 ;
     RECT  43.204 72.72 45.608 72.744 ;
     RECT  43.204 73.776 45.608 76.056 ;
     RECT  43.841 77.136 45.608 77.928 ;
     RECT  43.204 80.64 45.608 80.664 ;
     RECT  43.661 85.2 45.608 85.224 ;
     RECT  43.204 86.304 45.608 86.328 ;
     RECT  43.204 87.552 45.608 87.576 ;
     RECT  43.204 89.52 45.608 89.544 ;
     RECT  43.204 90.864 45.608 91.656 ;
     RECT  45.529 93.504 45.608 103.56 ;
     RECT  45.608 2.148 45.712 103.56 ;
     RECT  45.317 104.832 45.746 105.72 ;
     RECT  45.712 2.418 45.779 103.56 ;
     RECT  45.779 2.418 45.904 103.512 ;
     RECT  45.904 70.608 45.965 71.64 ;
     RECT  45.904 87.552 46.073 87.576 ;
     RECT  45.904 77.136 46.115 79.176 ;
     RECT  45.904 55.2 46.145 56.808 ;
     RECT  45.904 73.776 46.289 76.056 ;
     RECT  46.289 74.352 46.721 76.056 ;
     RECT  45.904 47.616 46.757 47.64 ;
     RECT  45.904 50.832 46.757 53.832 ;
     RECT  45.904 93.504 46.757 103.512 ;
     RECT  45.904 37.92 46.793 38.136 ;
     RECT  45.904 41.088 46.793 43.032 ;
     RECT  46.757 50.832 46.793 52.536 ;
     RECT  45.904 58.224 46.793 58.392 ;
     RECT  45.904 59.52 46.793 61.368 ;
     RECT  45.904 67.008 46.793 67.656 ;
     RECT  45.904 90.864 46.793 91.752 ;
     RECT  45.904 82.08 46.828 82.104 ;
     RECT  46.115 77.328 46.865 79.176 ;
     RECT  45.746 104.88 46.897 105.72 ;
     RECT  45.904 36.912 47.005 36.936 ;
     RECT  46.793 37.92 47.005 37.992 ;
     RECT  46.757 94.608 47.005 103.512 ;
     RECT  45.904 34.464 47.041 34.728 ;
     RECT  46.897 104.88 47.045 105.768 ;
     RECT  46.721 75.984 47.081 76.056 ;
     RECT  45.904 88.896 47.081 89.544 ;
     RECT  47.045 104.88 47.113 105.624 ;
     RECT  45.904 85.2 47.117 85.224 ;
     RECT  47.005 94.608 47.123 103.752 ;
     RECT  45.965 70.608 47.153 71.304 ;
     RECT  47.081 76.032 47.225 76.056 ;
     RECT  45.904 26.592 47.617 26.616 ;
     RECT  47.113 104.832 47.795 105.624 ;
     RECT  47.005 36.912 47.797 37.992 ;
     RECT  47.797 36.864 47.833 37.992 ;
     RECT  46.865 77.328 47.852 79.032 ;
     RECT  45.904 80.304 47.852 80.664 ;
     RECT  46.757 93.504 48.037 93.528 ;
     RECT  47.123 94.608 48.037 103.512 ;
     RECT  47.795 105.312 48.133 105.624 ;
     RECT  45.904 72.72 48.181 72.792 ;
     RECT  47.617 26.592 48.308 27.192 ;
     RECT  45.904 28.944 48.308 28.968 ;
     RECT  47.725 32.208 48.308 32.232 ;
     RECT  47.761 33.36 48.308 33.384 ;
     RECT  47.041 34.464 48.308 35.208 ;
     RECT  47.833 36.24 48.308 37.992 ;
     RECT  46.793 41.184 48.308 43.032 ;
     RECT  45.904 48.72 48.308 48.936 ;
     RECT  46.793 50.832 48.308 52.296 ;
     RECT  46.757 53.808 48.308 53.832 ;
     RECT  46.145 55.248 48.308 56.808 ;
     RECT  46.793 58.224 48.308 58.248 ;
     RECT  46.793 59.52 48.308 60.12 ;
     RECT  46.793 61.104 48.308 61.368 ;
     RECT  46.793 67.104 48.308 67.656 ;
     RECT  47.153 70.608 48.308 71.112 ;
     RECT  48.181 72.144 48.308 72.792 ;
     RECT  46.721 74.352 48.308 74.952 ;
     RECT  47.852 77.328 48.308 80.664 ;
     RECT  45.904 86.304 48.308 86.328 ;
     RECT  47.081 89.52 48.308 89.544 ;
     RECT  46.793 90.864 48.308 91.656 ;
     RECT  48.037 93.504 48.308 103.512 ;
     RECT  48.308 2.148 48.412 103.512 ;
     RECT  48.412 2.418 48.445 103.512 ;
     RECT  48.445 2.418 48.604 104.328 ;
     RECT  48.133 105.312 48.661 105.672 ;
     RECT  48.604 77.328 48.755 79.272 ;
     RECT  48.604 72.144 48.881 72.792 ;
     RECT  48.604 94.608 48.899 104.328 ;
     RECT  48.899 94.992 48.901 104.328 ;
     RECT  48.661 105.312 48.901 105.72 ;
     RECT  48.604 50.832 48.989 50.856 ;
     RECT  48.604 55.248 49.025 56.808 ;
     RECT  48.881 72.72 49.025 72.792 ;
     RECT  48.604 89.52 49.241 91.656 ;
     RECT  48.604 58.224 49.313 58.248 ;
     RECT  48.604 82.032 49.313 82.056 ;
     RECT  49.241 90.048 49.493 91.656 ;
     RECT  49.493 90.576 49.571 91.656 ;
     RECT  48.604 93.024 49.571 93.528 ;
     RECT  48.604 39.312 49.597 39.624 ;
     RECT  48.901 94.992 49.715 105.72 ;
     RECT  48.604 51.984 49.745 52.296 ;
     RECT  49.597 39.312 49.777 40.056 ;
     RECT  48.604 41.184 49.777 43.032 ;
     RECT  48.604 59.52 49.889 60.12 ;
     RECT  49.715 104.832 49.889 105.72 ;
     RECT  48.755 77.328 50.005 79.032 ;
     RECT  48.604 74.928 50.197 74.952 ;
     RECT  49.889 105.504 50.497 105.72 ;
     RECT  49.025 55.536 50.533 56.808 ;
     RECT  49.889 59.52 50.581 59.544 ;
     RECT  49.715 94.992 50.723 103.752 ;
     RECT  48.604 26.592 51.008 27.192 ;
     RECT  48.604 28.944 51.008 28.968 ;
     RECT  48.604 32.208 51.008 32.232 ;
     RECT  48.604 33.36 51.008 33.384 ;
     RECT  48.604 34.464 51.008 37.992 ;
     RECT  49.777 39.312 51.008 43.032 ;
     RECT  50.725 49.008 51.008 49.032 ;
     RECT  49.745 51.984 51.008 52.008 ;
     RECT  50.533 54.672 51.008 56.808 ;
     RECT  50.581 59.28 51.008 59.544 ;
     RECT  48.604 61.104 51.008 61.368 ;
     RECT  48.604 64.656 51.008 64.68 ;
     RECT  48.604 67.104 51.008 67.656 ;
     RECT  48.604 70.608 51.008 71.112 ;
     RECT  49.025 72.768 51.008 72.792 ;
     RECT  50.197 74.112 51.008 74.952 ;
     RECT  50.005 76.368 51.008 79.032 ;
     RECT  48.604 80.304 51.008 80.664 ;
     RECT  48.604 86.304 51.008 86.328 ;
     RECT  49.571 90.864 51.008 91.656 ;
     RECT  49.571 93.024 51.008 93.048 ;
     RECT  50.723 94.992 51.008 103.56 ;
     RECT  50.497 105.504 51.109 105.768 ;
     RECT  51.008 2.148 51.112 103.56 ;
     RECT  51.112 2.418 51.304 103.56 ;
     RECT  51.304 94.56 51.365 103.56 ;
     RECT  51.304 41.952 51.509 41.976 ;
     RECT  51.304 55.536 51.689 55.56 ;
     RECT  51.304 72.768 51.833 72.888 ;
     RECT  51.304 74.928 51.869 75.288 ;
     RECT  51.365 94.56 51.875 103.512 ;
     RECT  51.304 46.176 52.316 46.2 ;
     RECT  52.316 46.128 52.403 46.2 ;
     RECT  51.304 67.104 52.441 67.656 ;
     RECT  51.875 94.608 52.477 103.512 ;
     RECT  51.109 104.544 52.477 105.768 ;
     RECT  51.304 80.304 52.733 80.664 ;
     RECT  53.053 46.272 53.125 46.296 ;
     RECT  53.125 46.272 53.173 46.632 ;
     RECT  51.304 86.304 53.269 86.328 ;
     RECT  52.441 67.056 53.305 67.656 ;
     RECT  51.304 68.64 53.305 68.664 ;
     RECT  51.304 93.024 53.305 93.048 ;
     RECT  52.477 94.608 53.305 105.768 ;
     RECT  51.304 32.208 53.341 33.384 ;
     RECT  51.304 34.464 53.341 37.992 ;
     RECT  53.173 46.272 53.377 47.4 ;
     RECT  51.304 64.656 53.377 64.68 ;
     RECT  53.017 56.592 53.557 56.616 ;
     RECT  51.304 26.592 53.708 27.192 ;
     RECT  51.304 28.752 53.708 28.968 ;
     RECT  53.341 32.208 53.708 37.992 ;
     RECT  51.304 39.312 53.708 40.92 ;
     RECT  53.377 46.272 53.708 47.88 ;
     RECT  51.304 49.008 53.708 49.032 ;
     RECT  53.557 56.256 53.708 56.616 ;
     RECT  51.304 61.104 53.708 61.176 ;
     RECT  51.304 62.544 53.708 63.096 ;
     RECT  53.377 64.08 53.708 64.68 ;
     RECT  53.305 67.056 53.708 68.664 ;
     RECT  51.304 70.608 53.708 71.112 ;
     RECT  51.833 72.768 53.708 72.792 ;
     RECT  51.869 74.928 53.708 74.952 ;
     RECT  51.304 77.328 53.708 79.032 ;
     RECT  52.733 80.304 53.708 80.328 ;
     RECT  52.453 83.76 53.708 83.784 ;
     RECT  53.269 85.728 53.708 86.328 ;
     RECT  51.304 90.864 53.708 91.656 ;
     RECT  53.305 93.024 53.708 105.768 ;
     RECT  53.708 2.148 53.812 105.768 ;
     RECT  53.812 2.418 54.004 105.768 ;
     RECT  54.004 76.608 54.209 80.328 ;
     RECT  54.004 62.544 54.713 63.096 ;
     RECT  54.004 61.056 54.749 61.176 ;
     RECT  54.004 67.008 54.749 68.664 ;
     RECT  54.004 72.672 54.749 72.792 ;
     RECT  54.209 76.608 54.749 79.176 ;
     RECT  54.004 55.392 54.857 56.904 ;
     RECT  54.004 53.04 54.947 53.064 ;
     RECT  54.004 83.808 54.997 83.832 ;
     RECT  54.004 85.728 55.033 86.328 ;
     RECT  54.004 39.312 55.141 40.92 ;
     RECT  54.004 45.696 55.145 48.504 ;
     RECT  54.857 55.824 55.145 56.904 ;
     RECT  54.713 62.544 55.145 62.568 ;
     RECT  54.997 83.568 55.283 83.832 ;
     RECT  54.004 64.08 55.285 64.104 ;
     RECT  55.145 46.272 55.381 48.504 ;
     RECT  54.749 61.104 55.397 61.176 ;
     RECT  54.004 32.208 55.681 38.184 ;
     RECT  54.749 67.056 55.861 68.664 ;
     RECT  55.285 64.08 55.897 64.44 ;
     RECT  55.045 65.568 55.897 65.592 ;
     RECT  55.861 51.744 56.185 51.768 ;
     RECT  55.357 53.088 56.185 53.112 ;
     RECT  55.717 62.208 56.257 62.232 ;
     RECT  55.897 64.08 56.329 65.592 ;
     RECT  55.381 46.272 56.365 49.032 ;
     RECT  55.861 54.384 56.365 54.408 ;
     RECT  55.145 56.016 56.365 56.904 ;
     RECT  54.004 70.608 56.365 71.112 ;
     RECT  55.397 61.152 56.401 61.176 ;
     RECT  56.257 62.208 56.401 62.28 ;
     RECT  54.004 24.624 56.408 24.648 ;
     RECT  54.004 26.592 56.408 28.968 ;
     RECT  55.681 31.728 56.408 38.184 ;
     RECT  55.141 39.216 56.408 40.92 ;
     RECT  56.365 46.224 56.408 49.032 ;
     RECT  55.813 50.16 56.408 50.184 ;
     RECT  56.185 51.744 56.408 53.112 ;
     RECT  56.365 54.384 56.408 56.904 ;
     RECT  55.429 59.856 56.408 59.88 ;
     RECT  56.401 61.152 56.408 62.28 ;
     RECT  56.329 63.264 56.408 65.592 ;
     RECT  55.861 66.672 56.408 68.664 ;
     RECT  56.365 70.608 56.408 71.4 ;
     RECT  54.749 72.768 56.408 72.792 ;
     RECT  54.004 74.928 56.408 74.952 ;
     RECT  54.749 76.752 56.408 79.032 ;
     RECT  54.209 80.304 56.408 80.328 ;
     RECT  55.283 83.568 56.408 83.592 ;
     RECT  55.033 84.96 56.408 86.328 ;
     RECT  54.004 89.184 56.408 89.208 ;
     RECT  54.004 90.864 56.408 90.888 ;
     RECT  54.004 92.688 56.408 105.768 ;
     RECT  56.408 2.148 56.512 105.768 ;
     RECT  56.512 2.418 56.704 105.768 ;
     RECT  56.704 84.96 56.819 86.328 ;
     RECT  56.704 76.752 56.963 79.032 ;
     RECT  56.704 63.264 56.981 64.632 ;
     RECT  56.963 77.04 57.251 79.032 ;
     RECT  56.704 70.08 57.305 71.4 ;
     RECT  56.704 92.688 57.413 105.768 ;
     RECT  57.305 70.608 57.683 71.4 ;
     RECT  56.704 47.664 57.769 48.168 ;
     RECT  57.769 47.664 57.923 49.032 ;
     RECT  56.704 51.168 58.093 56.904 ;
     RECT  56.704 26.592 58.381 29.064 ;
     RECT  56.704 46.224 58.489 46.584 ;
     RECT  57.923 47.664 58.489 48.792 ;
     RECT  58.453 58.224 58.705 58.248 ;
     RECT  56.704 74.928 58.705 74.952 ;
     RECT  58.453 76.272 58.705 76.296 ;
     RECT  57.251 77.328 58.705 79.032 ;
     RECT  58.093 50.928 58.777 56.904 ;
     RECT  56.704 90.864 58.957 90.888 ;
     RECT  57.413 93.744 59.069 105.768 ;
     RECT  56.704 23.04 59.108 23.064 ;
     RECT  56.704 24.624 59.108 24.648 ;
     RECT  58.381 26.064 59.108 29.064 ;
     RECT  56.704 31.728 59.108 38.184 ;
     RECT  56.704 39.216 59.108 40.92 ;
     RECT  58.741 41.904 59.108 41.928 ;
     RECT  58.489 46.224 59.108 48.792 ;
     RECT  58.777 50.304 59.108 56.904 ;
     RECT  58.705 57.888 59.108 58.248 ;
     RECT  56.704 60.096 59.108 60.12 ;
     RECT  56.704 61.152 59.108 62.28 ;
     RECT  56.981 64.08 59.108 64.632 ;
     RECT  56.704 67.056 59.108 68.664 ;
     RECT  57.683 70.608 59.108 71.112 ;
     RECT  56.704 72.768 59.108 72.792 ;
     RECT  58.705 74.928 59.108 79.032 ;
     RECT  56.704 80.304 59.108 80.328 ;
     RECT  56.704 83.568 59.108 83.592 ;
     RECT  56.819 85.728 59.108 86.328 ;
     RECT  56.704 89.184 59.108 89.208 ;
     RECT  58.957 90.864 59.108 91.368 ;
     RECT  57.413 92.688 59.108 92.712 ;
     RECT  59.069 93.744 59.108 105.672 ;
     RECT  59.108 2.148 59.212 105.672 ;
     RECT  59.212 2.418 59.404 105.672 ;
     RECT  59.404 57.888 59.555 58.248 ;
     RECT  59.404 77.664 59.573 79.032 ;
     RECT  59.404 74.928 59.699 76.536 ;
     RECT  59.404 83.568 59.717 83.592 ;
     RECT  59.404 41.904 59.891 44.472 ;
     RECT  59.404 93.744 60.109 105.672 ;
     RECT  59.699 76.512 60.131 76.536 ;
     RECT  59.891 43.104 60.221 44.472 ;
     RECT  60.109 93.744 60.257 105.768 ;
     RECT  59.404 92.688 60.421 92.712 ;
     RECT  60.257 93.744 60.421 105.672 ;
     RECT  60.421 92.688 60.563 105.672 ;
     RECT  59.404 72.768 60.613 72.792 ;
     RECT  59.404 63.504 60.659 64.632 ;
     RECT  59.404 46.224 60.757 46.584 ;
     RECT  59.404 47.664 60.757 52.248 ;
     RECT  60.221 43.344 60.865 44.472 ;
     RECT  59.404 67.056 61.153 68.664 ;
     RECT  59.404 31.488 61.225 38.184 ;
     RECT  61.153 66.672 61.621 68.664 ;
     RECT  60.563 93.744 61.765 105.672 ;
     RECT  60.865 43.344 61.801 44.904 ;
     RECT  60.757 46.224 61.801 52.248 ;
     RECT  59.404 23.04 61.808 23.352 ;
     RECT  59.404 24.624 61.808 24.648 ;
     RECT  59.404 26.064 61.808 29.064 ;
     RECT  61.225 31.152 61.808 38.184 ;
     RECT  59.404 39.216 61.808 40.92 ;
     RECT  59.891 41.904 61.808 42.12 ;
     RECT  61.801 43.344 61.808 52.248 ;
     RECT  59.404 53.28 61.808 56.904 ;
     RECT  59.555 58.128 61.808 58.248 ;
     RECT  59.404 60.096 61.808 60.12 ;
     RECT  59.404 61.152 61.808 62.28 ;
     RECT  60.659 63.504 61.808 64.104 ;
     RECT  61.621 66.672 61.808 68.856 ;
     RECT  59.404 70.608 61.808 71.112 ;
     RECT  60.613 72.144 61.808 72.792 ;
     RECT  59.699 74.928 61.808 74.952 ;
     RECT  59.573 77.952 61.808 79.032 ;
     RECT  59.404 80.304 61.808 80.328 ;
     RECT  61.405 84.624 61.808 84.648 ;
     RECT  59.404 85.728 61.808 86.328 ;
     RECT  59.404 89.184 61.808 89.208 ;
     RECT  59.404 90.864 61.808 91.368 ;
     RECT  60.563 92.688 61.808 92.712 ;
     RECT  61.765 93.744 61.808 105.72 ;
     RECT  61.808 2.148 61.912 105.72 ;
     RECT  61.912 2.418 62.104 105.72 ;
     RECT  62.104 93.744 62.243 96.024 ;
     RECT  62.104 58.224 62.309 58.776 ;
     RECT  62.104 60.096 62.705 64.248 ;
     RECT  62.104 97.296 62.737 105.72 ;
     RECT  62.104 77.952 62.777 79.176 ;
     RECT  62.737 97.296 62.813 105.768 ;
     RECT  62.104 43.536 62.849 52.248 ;
     RECT  62.309 58.656 62.915 58.776 ;
     RECT  62.705 60.096 62.915 64.104 ;
     RECT  62.104 74.64 62.963 74.76 ;
     RECT  62.104 82.608 62.963 82.728 ;
     RECT  62.104 86.304 62.963 86.664 ;
     RECT  62.104 90.576 62.963 90.888 ;
     RECT  62.915 63.504 63.299 64.104 ;
     RECT  62.813 97.536 63.497 105.768 ;
     RECT  62.104 66.528 64.165 71.112 ;
     RECT  62.104 72.144 64.165 72.792 ;
     RECT  62.104 23.04 64.508 23.352 ;
     RECT  62.104 24.624 64.508 24.648 ;
     RECT  62.104 25.824 64.508 29.064 ;
     RECT  62.104 31.152 64.508 40.92 ;
     RECT  62.104 41.904 64.508 42.024 ;
     RECT  62.849 43.536 64.508 46.584 ;
     RECT  62.849 47.664 64.508 52.248 ;
     RECT  62.104 53.28 64.508 56.904 ;
     RECT  62.915 58.656 64.508 58.68 ;
     RECT  62.915 60.096 64.508 62.28 ;
     RECT  63.299 63.504 64.508 63.528 ;
     RECT  64.165 66.528 64.508 72.792 ;
     RECT  62.777 77.952 64.508 79.032 ;
     RECT  62.104 80.304 64.508 80.328 ;
     RECT  62.104 84.624 64.508 84.648 ;
     RECT  62.963 86.304 64.508 86.328 ;
     RECT  62.104 89.184 64.508 89.208 ;
     RECT  62.963 90.864 64.508 90.888 ;
     RECT  62.104 92.688 64.508 92.712 ;
     RECT  62.243 93.792 64.508 96.024 ;
     RECT  63.497 97.632 64.508 105.768 ;
     RECT  64.508 2.148 64.612 105.768 ;
     RECT  64.612 2.418 64.804 105.768 ;
     RECT  64.804 49.008 64.979 52.248 ;
     RECT  64.804 58.656 65.123 58.68 ;
     RECT  64.804 66.528 65.189 72.792 ;
     RECT  64.804 86.304 65.189 86.808 ;
     RECT  64.804 94.464 65.189 96.936 ;
     RECT  65.189 94.656 65.297 96.936 ;
     RECT  64.804 64.416 65.315 64.44 ;
     RECT  65.297 94.656 65.318 96.024 ;
     RECT  64.804 82.656 65.363 82.68 ;
     RECT  64.804 90.576 65.363 90.888 ;
     RECT  65.318 94.704 65.363 96.024 ;
     RECT  64.804 65.52 65.449 65.544 ;
     RECT  65.363 90.672 65.507 90.888 ;
     RECT  65.363 94.752 65.513 96.024 ;
     RECT  64.979 49.008 65.603 52.2 ;
     RECT  64.804 53.28 65.651 56.904 ;
     RECT  65.603 50.304 65.699 52.2 ;
     RECT  64.804 98.352 65.891 105.768 ;
     RECT  64.804 84.624 65.987 84.648 ;
     RECT  65.891 98.928 66.521 105.768 ;
     RECT  64.804 60.096 66.769 60.12 ;
     RECT  66.521 105.744 66.845 105.768 ;
     RECT  64.804 23.04 67.208 23.352 ;
     RECT  64.804 24.624 67.208 24.648 ;
     RECT  64.804 25.824 67.208 29.064 ;
     RECT  64.804 31.152 67.208 40.92 ;
     RECT  64.804 41.904 67.208 42.024 ;
     RECT  64.804 43.536 67.208 46.584 ;
     RECT  64.804 47.664 67.208 47.88 ;
     RECT  65.603 49.008 67.208 49.32 ;
     RECT  65.699 50.304 67.208 51.768 ;
     RECT  65.651 53.28 67.208 53.304 ;
     RECT  65.651 54.384 67.208 56.904 ;
     RECT  66.769 59.616 67.208 60.12 ;
     RECT  64.804 61.968 67.208 62.28 ;
     RECT  65.189 66.528 67.208 67.128 ;
     RECT  65.189 68.4 67.208 71.112 ;
     RECT  65.189 72.768 67.208 72.792 ;
     RECT  64.804 77.952 67.208 79.032 ;
     RECT  64.804 80.304 67.208 80.328 ;
     RECT  65.189 86.304 67.208 86.328 ;
     RECT  64.804 89.184 67.208 89.208 ;
     RECT  65.507 90.864 67.208 90.888 ;
     RECT  64.804 92.688 67.208 92.712 ;
     RECT  65.513 95.472 67.208 96.024 ;
     RECT  66.521 98.928 67.208 104.712 ;
     RECT  67.208 2.148 67.277 104.712 ;
     RECT  67.277 2.148 67.312 104.04 ;
     RECT  67.312 2.418 67.504 104.04 ;
     RECT  67.504 104.016 67.601 104.04 ;
     RECT  67.504 50.304 67.619 51.768 ;
     RECT  67.504 55.536 67.667 56.904 ;
     RECT  67.504 92.688 67.781 92.712 ;
     RECT  67.504 44.688 67.859 46.584 ;
     RECT  67.504 47.664 67.997 47.88 ;
     RECT  67.504 69.36 68.147 69.384 ;
     RECT  67.504 61.488 68.357 62.28 ;
     RECT  67.504 99.456 68.393 102.984 ;
     RECT  67.859 44.688 68.435 44.904 ;
     RECT  67.504 70.608 69.068 71.112 ;
     RECT  67.504 72.768 69.068 72.792 ;
     RECT  67.504 23.04 69.908 23.352 ;
     RECT  67.504 24.624 69.908 24.648 ;
     RECT  67.504 25.824 69.908 29.064 ;
     RECT  67.504 31.152 69.908 40.92 ;
     RECT  67.504 41.904 69.908 42.024 ;
     RECT  67.504 43.536 69.908 43.56 ;
     RECT  68.435 44.688 69.908 44.856 ;
     RECT  67.859 46.224 69.908 46.584 ;
     RECT  67.997 47.664 69.908 47.688 ;
     RECT  67.504 49.008 69.908 49.32 ;
     RECT  67.619 50.304 69.908 50.328 ;
     RECT  67.619 51.648 69.908 51.768 ;
     RECT  67.667 56.304 69.908 56.904 ;
     RECT  69.205 60.576 69.908 60.6 ;
     RECT  68.357 61.968 69.908 62.28 ;
     RECT  67.504 66.528 69.908 66.552 ;
     RECT  69.068 70.608 69.908 72.792 ;
     RECT  67.504 77.952 69.908 79.032 ;
     RECT  67.504 80.304 69.908 80.328 ;
     RECT  67.504 86.304 69.908 86.328 ;
     RECT  68.917 88.704 69.908 88.728 ;
     RECT  67.504 90.864 69.908 90.888 ;
     RECT  67.504 95.472 69.908 96.024 ;
     RECT  68.393 99.552 69.908 102.984 ;
     RECT  69.908 2.148 70.012 103.152 ;
     RECT  70.012 2.418 70.1 103.152 ;
     RECT  70.1 2.418 70.204 103.422 ;
     RECT  70.204 59.52 70.265 60.6 ;
     RECT  70.265 59.52 70.697 60.504 ;
     RECT  70.204 49.008 70.733 50.328 ;
     RECT  70.204 66.528 70.733 66.648 ;
     RECT  70.204 72.672 70.733 72.792 ;
     RECT  70.204 77.952 70.733 79.176 ;
     RECT  70.204 88.608 70.733 88.728 ;
     RECT  70.204 90.864 70.841 90.888 ;
     RECT  70.697 60.48 70.913 60.504 ;
     RECT  70.204 23.04 72.608 23.352 ;
     RECT  70.204 24.624 72.608 24.648 ;
     RECT  70.204 25.824 72.608 29.064 ;
     RECT  70.204 31.152 72.608 40.92 ;
     RECT  70.204 41.904 72.608 42.024 ;
     RECT  70.204 46.224 72.608 46.584 ;
     RECT  70.204 47.664 72.608 47.688 ;
     RECT  70.733 49.008 72.608 49.32 ;
     RECT  70.733 50.304 72.608 50.328 ;
     RECT  70.204 51.648 72.608 51.768 ;
     RECT  70.204 56.304 72.608 56.904 ;
     RECT  70.204 61.968 72.608 62.28 ;
     RECT  70.733 66.528 72.608 66.552 ;
     RECT  70.204 70.608 72.608 71.112 ;
     RECT  70.733 72.768 72.608 72.792 ;
     RECT  70.733 77.952 72.608 79.032 ;
     RECT  70.204 80.304 72.608 80.328 ;
     RECT  70.204 86.304 72.608 86.328 ;
     RECT  70.733 88.704 72.608 88.728 ;
     RECT  70.204 95.472 72.608 96.024 ;
     RECT  70.204 99.552 72.608 101.4 ;
     RECT  72.608 2.148 72.712 103.152 ;
     RECT  72.712 2.418 72.8 103.152 ;
     RECT  72.8 2.418 72.904 103.422 ;
     RECT  72.904 23.04 75.308 23.352 ;
     RECT  72.904 24.624 75.308 24.648 ;
     RECT  72.904 25.824 75.308 29.064 ;
     RECT  72.904 31.152 75.308 40.92 ;
     RECT  72.904 41.904 75.308 42.024 ;
     RECT  72.904 46.224 75.308 46.584 ;
     RECT  72.904 47.664 75.308 47.688 ;
     RECT  72.904 49.008 75.308 49.32 ;
     RECT  72.904 50.304 75.308 50.328 ;
     RECT  72.904 51.648 75.308 51.768 ;
     RECT  72.904 56.304 75.308 56.904 ;
     RECT  72.904 61.968 75.308 62.28 ;
     RECT  72.904 66.528 75.308 66.552 ;
     RECT  72.904 70.608 75.308 71.112 ;
     RECT  72.904 72.768 75.308 72.792 ;
     RECT  72.904 77.952 75.308 79.032 ;
     RECT  72.904 80.304 75.308 80.328 ;
     RECT  72.904 86.304 75.308 86.328 ;
     RECT  72.904 88.704 75.308 88.728 ;
     RECT  72.904 95.472 75.308 96.024 ;
     RECT  72.904 99.552 75.308 101.4 ;
     RECT  75.308 2.148 75.412 103.152 ;
     RECT  75.412 2.418 75.5 103.152 ;
     RECT  75.5 2.418 75.604 103.422 ;
     RECT  75.604 23.04 78.008 23.352 ;
     RECT  75.604 24.624 78.008 24.648 ;
     RECT  75.604 25.824 78.008 29.064 ;
     RECT  75.604 31.152 78.008 40.92 ;
     RECT  75.604 41.904 78.008 42.024 ;
     RECT  75.604 46.224 78.008 46.584 ;
     RECT  75.604 47.664 78.008 47.688 ;
     RECT  75.604 49.008 78.008 49.32 ;
     RECT  75.604 50.304 78.008 50.328 ;
     RECT  75.604 51.648 78.008 51.768 ;
     RECT  75.604 56.304 78.008 56.904 ;
     RECT  75.604 61.968 78.008 62.28 ;
     RECT  75.604 66.528 78.008 66.552 ;
     RECT  75.604 70.608 78.008 71.112 ;
     RECT  75.604 72.768 78.008 72.792 ;
     RECT  75.604 77.952 78.008 79.032 ;
     RECT  75.604 80.304 78.008 80.328 ;
     RECT  75.604 86.304 78.008 86.328 ;
     RECT  75.604 88.704 78.008 88.728 ;
     RECT  75.604 95.472 78.008 96.024 ;
     RECT  75.604 99.552 78.008 101.4 ;
     RECT  78.008 2.148 78.112 103.152 ;
     RECT  78.112 2.418 78.2 103.152 ;
     RECT  78.2 2.418 78.304 103.422 ;
     RECT  78.304 49.008 78.689 50.328 ;
     RECT  78.304 66.528 78.689 66.648 ;
     RECT  78.304 72.672 78.689 72.792 ;
     RECT  78.304 77.952 78.689 79.176 ;
     RECT  78.304 88.608 78.689 88.728 ;
     RECT  78.304 99.552 78.725 101.4 ;
     RECT  78.725 99.552 79.517 100.344 ;
     RECT  78.304 23.04 80.708 23.352 ;
     RECT  78.304 24.624 80.708 24.648 ;
     RECT  78.304 25.824 80.708 29.064 ;
     RECT  78.304 31.152 80.708 40.92 ;
     RECT  78.304 41.904 80.708 42.024 ;
     RECT  78.304 46.224 80.708 46.584 ;
     RECT  78.304 47.664 80.708 47.688 ;
     RECT  78.689 49.008 80.708 49.32 ;
     RECT  78.689 50.304 80.708 50.328 ;
     RECT  78.304 51.648 80.708 51.768 ;
     RECT  78.304 56.304 80.708 56.904 ;
     RECT  78.304 61.968 80.708 62.28 ;
     RECT  78.689 66.528 80.708 66.552 ;
     RECT  78.304 70.608 80.708 71.112 ;
     RECT  78.689 72.768 80.708 72.792 ;
     RECT  78.689 77.952 80.708 79.032 ;
     RECT  78.304 80.304 80.708 80.328 ;
     RECT  78.304 86.304 80.708 86.328 ;
     RECT  78.689 88.704 80.708 88.728 ;
     RECT  78.304 95.472 80.708 96.024 ;
     RECT  79.517 99.552 80.708 99.576 ;
     RECT  78.725 101.376 80.708 101.4 ;
     RECT  80.708 2.148 80.812 103.152 ;
     RECT  80.812 2.418 80.9 103.152 ;
     RECT  80.9 2.418 81.004 103.422 ;
     RECT  81.004 101.376 82.145 101.4 ;
     RECT  81.004 31.152 82.609 40.92 ;
     RECT  81.004 41.904 82.609 42.024 ;
     RECT  81.004 23.04 83.408 23.352 ;
     RECT  81.004 24.624 83.408 24.648 ;
     RECT  81.004 25.824 83.408 29.064 ;
     RECT  82.609 31.152 83.408 42.024 ;
     RECT  81.004 46.224 83.408 46.584 ;
     RECT  81.004 47.664 83.408 47.688 ;
     RECT  81.004 49.008 83.408 49.32 ;
     RECT  81.004 50.304 83.408 50.328 ;
     RECT  81.004 51.648 83.408 51.768 ;
     RECT  81.004 56.304 83.408 56.904 ;
     RECT  81.004 61.968 83.408 62.28 ;
     RECT  81.004 66.528 83.408 66.552 ;
     RECT  81.004 70.608 83.408 71.112 ;
     RECT  81.004 72.768 83.408 72.792 ;
     RECT  81.004 77.952 83.408 79.032 ;
     RECT  81.004 80.304 83.408 80.328 ;
     RECT  81.004 86.304 83.408 86.328 ;
     RECT  81.004 88.704 83.408 88.728 ;
     RECT  81.004 95.472 83.408 95.496 ;
     RECT  81.004 99.552 83.408 99.576 ;
     RECT  83.408 2.148 83.512 103.152 ;
     RECT  83.512 2.418 83.6 103.152 ;
     RECT  83.6 2.418 83.704 103.422 ;
     RECT  83.704 95.472 83.909 95.496 ;
     RECT  83.704 99.552 84.953 99.576 ;
     RECT  83.704 23.04 86.108 23.352 ;
     RECT  83.704 24.624 86.108 24.648 ;
     RECT  83.704 25.824 86.108 29.064 ;
     RECT  83.704 31.152 86.108 42.024 ;
     RECT  83.704 46.224 86.108 46.584 ;
     RECT  83.704 47.664 86.108 47.688 ;
     RECT  83.704 49.008 86.108 49.32 ;
     RECT  83.704 50.304 86.108 50.328 ;
     RECT  83.704 51.648 86.108 51.768 ;
     RECT  83.704 56.304 86.108 56.904 ;
     RECT  83.704 61.968 86.108 62.28 ;
     RECT  83.704 66.528 86.108 66.552 ;
     RECT  83.704 70.608 86.108 71.112 ;
     RECT  83.704 72.768 86.108 72.792 ;
     RECT  83.704 77.952 86.108 79.032 ;
     RECT  83.704 80.304 86.108 80.328 ;
     RECT  83.704 86.304 86.108 86.328 ;
     RECT  83.704 88.704 86.108 88.728 ;
     RECT  86.108 2.148 86.212 103.152 ;
     RECT  86.212 2.418 86.3 103.152 ;
     RECT  86.3 2.418 86.404 103.422 ;
     RECT  86.404 66.528 86.501 66.648 ;
     RECT  86.404 72.672 86.501 72.792 ;
     RECT  86.404 49.008 86.681 50.328 ;
     RECT  86.404 23.04 88.808 23.352 ;
     RECT  86.404 24.624 88.808 24.648 ;
     RECT  86.404 25.728 88.808 29.064 ;
     RECT  86.404 31.152 88.808 42.024 ;
     RECT  86.404 46.224 88.808 46.584 ;
     RECT  86.404 47.664 88.808 47.688 ;
     RECT  86.681 49.008 88.808 49.32 ;
     RECT  86.681 50.304 88.808 50.328 ;
     RECT  86.404 51.648 88.808 51.768 ;
     RECT  86.404 56.304 88.808 56.904 ;
     RECT  86.404 61.968 88.808 62.28 ;
     RECT  86.501 66.624 88.808 66.648 ;
     RECT  86.404 70.608 88.808 71.112 ;
     RECT  86.501 72.672 88.808 72.696 ;
     RECT  86.404 77.952 88.808 79.176 ;
     RECT  86.404 80.304 88.808 80.328 ;
     RECT  86.404 88.608 88.808 88.632 ;
     RECT  88.808 2.148 88.912 103.152 ;
     RECT  88.912 2.418 89 103.152 ;
     RECT  89 2.418 89.104 103.422 ;
     RECT  89.104 66.624 90.637 66.648 ;
     RECT  89.104 72.672 90.637 72.696 ;
     RECT  89.104 23.04 91.508 23.352 ;
     RECT  89.104 24.624 91.508 24.648 ;
     RECT  89.104 25.728 91.508 29.064 ;
     RECT  89.104 31.152 91.508 42.024 ;
     RECT  89.104 46.224 91.508 46.584 ;
     RECT  89.104 47.664 91.508 47.688 ;
     RECT  89.104 49.008 91.508 49.32 ;
     RECT  89.104 50.304 91.508 50.328 ;
     RECT  89.104 51.648 91.508 51.768 ;
     RECT  89.104 53.52 91.508 53.544 ;
     RECT  89.104 56.304 91.508 56.904 ;
     RECT  89.104 61.968 91.508 62.28 ;
     RECT  90.637 66.528 91.508 66.648 ;
     RECT  89.104 70.608 91.508 71.112 ;
     RECT  90.637 72.672 91.508 72.792 ;
     RECT  89.104 77.952 91.508 79.176 ;
     RECT  89.104 80.304 91.508 80.328 ;
     RECT  91.508 2.148 91.612 103.152 ;
     RECT  91.612 2.418 91.7 103.152 ;
     RECT  91.7 2.418 91.804 103.422 ;
     RECT  91.804 66.528 93.445 66.552 ;
     RECT  91.804 31.152 93.481 42.024 ;
     RECT  93.481 31.152 94.021 42.504 ;
     RECT  91.804 50.304 94.057 50.328 ;
     RECT  91.804 23.04 94.208 23.352 ;
     RECT  91.804 24.624 94.208 24.648 ;
     RECT  91.804 25.728 94.208 29.064 ;
     RECT  94.021 31.152 94.208 42.744 ;
     RECT  91.804 46.224 94.208 46.584 ;
     RECT  91.804 47.664 94.208 49.32 ;
     RECT  94.057 50.304 94.208 50.568 ;
     RECT  91.804 51.648 94.208 51.768 ;
     RECT  91.804 53.52 94.208 53.544 ;
     RECT  91.804 56.304 94.208 56.904 ;
     RECT  91.804 61.968 94.208 63.096 ;
     RECT  93.445 65.952 94.208 66.552 ;
     RECT  91.804 70.608 94.208 71.112 ;
     RECT  91.804 72.768 94.208 72.792 ;
     RECT  91.804 77.952 94.208 79.032 ;
     RECT  91.804 80.304 94.208 80.328 ;
     RECT  94.208 2.148 94.312 103.152 ;
     RECT  94.312 2.418 94.4 103.152 ;
     RECT  94.4 2.418 94.504 103.422 ;
     RECT  94.504 72.672 94.601 72.792 ;
     RECT  94.504 53.52 95.677 53.544 ;
     RECT  94.504 54.96 95.677 54.984 ;
     RECT  94.504 31.248 95.713 42.744 ;
     RECT  94.504 47.664 95.713 50.568 ;
     RECT  94.504 51.648 95.713 51.768 ;
     RECT  95.713 30.864 96.289 42.744 ;
     RECT  94.504 46.224 96.289 46.584 ;
     RECT  94.504 61.968 96.289 63.24 ;
     RECT  94.504 70.608 96.289 71.112 ;
     RECT  94.504 24.624 96.649 29.064 ;
     RECT  94.504 59.184 96.829 59.256 ;
     RECT  96.289 30.864 96.865 43.56 ;
     RECT  96.289 45.456 96.901 46.584 ;
     RECT  95.713 47.664 96.901 51.768 ;
     RECT  96.613 21.408 96.908 21.432 ;
     RECT  94.504 23.04 96.908 23.352 ;
     RECT  96.649 24.432 96.908 29.064 ;
     RECT  96.865 30.864 96.908 44.088 ;
     RECT  96.901 45.456 96.908 51.768 ;
     RECT  95.677 53.52 96.908 54.984 ;
     RECT  94.504 56.304 96.908 57.336 ;
     RECT  96.829 59.184 96.908 60.024 ;
     RECT  96.289 61.104 96.908 63.24 ;
     RECT  94.504 65.28 96.908 66.648 ;
     RECT  95.713 67.824 96.908 67.848 ;
     RECT  96.289 70.272 96.908 71.112 ;
     RECT  94.601 72.672 96.908 72.696 ;
     RECT  96.289 73.872 96.908 73.896 ;
     RECT  94.504 76.56 96.908 76.584 ;
     RECT  94.504 77.952 96.908 80.328 ;
     RECT  96.908 2.148 97.012 103.152 ;
     RECT  97.012 2.418 97.1 103.152 ;
     RECT  97.1 2.418 97.204 103.422 ;
     RECT  97.204 30.384 98.377 52.488 ;
     RECT  97.204 65.28 98.521 66.648 ;
     RECT  97.204 58.368 98.557 63.24 ;
     RECT  98.521 64.848 98.557 66.648 ;
     RECT  97.204 77.952 98.557 80.328 ;
     RECT  98.377 30.096 98.593 52.488 ;
     RECT  97.204 53.52 98.593 57.336 ;
     RECT  97.204 67.824 99.133 68.232 ;
     RECT  97.204 69.744 99.565 73.896 ;
     RECT  97.204 21.408 99.608 21.432 ;
     RECT  97.204 23.04 99.608 23.352 ;
     RECT  97.204 24.336 99.608 29.064 ;
     RECT  98.593 30.096 99.608 57.336 ;
     RECT  98.557 58.368 99.608 66.648 ;
     RECT  99.133 67.632 99.608 68.232 ;
     RECT  99.565 69.744 99.608 74.184 ;
     RECT  97.204 76.56 99.608 76.584 ;
     RECT  98.557 77.664 99.608 80.328 ;
     RECT  99.608 2.148 99.712 103.152 ;
     RECT  99.712 2.418 99.8 103.152 ;
     RECT  99.8 2.418 99.904 103.422 ;
     RECT  99.904 20.976 99.962 21.432 ;
     RECT  99.962 20.976 100.897 21.384 ;
     RECT  100.897 20.88 101.149 21.384 ;
     RECT  99.904 22.608 101.185 29.064 ;
     RECT  101.185 22.512 101.221 29.064 ;
     RECT  99.904 30.096 101.221 57.336 ;
     RECT  99.904 58.368 101.437 75.24 ;
     RECT  99.904 76.272 101.437 76.68 ;
     RECT  101.149 19.92 101.473 21.384 ;
     RECT  101.221 22.512 101.473 57.336 ;
     RECT  99.904 77.664 101.977 79.464 ;
     RECT  101.473 19.92 103.165 57.384 ;
     RECT  101.437 58.368 103.165 76.68 ;
     RECT  101.977 77.664 103.165 79.656 ;
     RECT  103.165 19.92 103.201 79.656 ;
     RECT  103.201 19.92 103.237 79.752 ;
     RECT  103.237 19.92 104.028 79.848 ;
     RECT  104.028 42.72 104.033 42.744 ;
     RECT  104.028 43.776 104.069 43.8 ;
     RECT  104.028 46.56 104.069 46.584 ;
     RECT  104.028 48 104.069 48.024 ;
     RECT  104.028 51.744 104.069 51.768 ;
     RECT  104.028 55.008 104.069 55.704 ;
     RECT  104.028 57.312 104.069 57.336 ;
     RECT  104.028 58.368 104.069 58.392 ;
     RECT  104.028 59.712 104.069 60.024 ;
     RECT  104.028 62.016 104.069 62.328 ;
     RECT  104.028 65.28 104.069 65.304 ;
     RECT  104.028 66.336 104.069 66.36 ;
     RECT  104.028 67.968 104.069 67.992 ;
     RECT  104.028 71.328 104.069 71.352 ;
     RECT  104.028 72.672 104.069 72.696 ;
     RECT  104.028 77.664 104.069 77.688 ;
    LAYER M5 ;
     RECT  2.4 2.137 2.52 2.151 ;
     RECT  5.1 2.137 5.22 2.151 ;
     RECT  7.8 2.137 7.92 2.151 ;
     RECT  10.5 2.137 10.62 2.151 ;
     RECT  13.2 2.137 13.32 2.151 ;
     RECT  15.9 2.137 16.02 2.151 ;
     RECT  18.6 2.137 18.72 2.151 ;
     RECT  21.3 2.137 21.42 2.151 ;
     RECT  24 2.137 24.12 2.151 ;
     RECT  26.7 2.137 26.82 2.151 ;
     RECT  29.4 2.137 29.52 2.151 ;
     RECT  32.1 2.137 32.22 2.151 ;
     RECT  34.8 2.137 34.92 2.151 ;
     RECT  37.5 2.137 37.62 2.151 ;
     RECT  40.2 2.137 40.32 2.151 ;
     RECT  42.9 2.137 43.02 2.151 ;
     RECT  45.6 2.137 45.72 2.151 ;
     RECT  48.3 2.137 48.42 2.151 ;
     RECT  51 2.137 51.12 2.151 ;
     RECT  53.7 2.137 53.82 2.151 ;
     RECT  56.4 2.137 56.52 2.151 ;
     RECT  59.1 2.137 59.22 2.151 ;
     RECT  61.8 2.137 61.92 2.151 ;
     RECT  64.5 2.137 64.62 2.151 ;
     RECT  67.2 2.137 67.32 2.151 ;
     RECT  69.9 2.137 70.02 2.151 ;
     RECT  72.6 2.137 72.72 2.151 ;
     RECT  75.3 2.137 75.42 2.151 ;
     RECT  78 2.137 78.12 2.151 ;
     RECT  80.7 2.137 80.82 2.151 ;
     RECT  83.4 2.137 83.52 2.151 ;
     RECT  86.1 2.137 86.22 2.151 ;
     RECT  88.8 2.137 88.92 2.151 ;
     RECT  91.5 2.137 91.62 2.151 ;
     RECT  94.2 2.137 94.32 2.151 ;
     RECT  96.9 2.137 97.02 2.151 ;
     RECT  99.6 2.137 99.72 2.151 ;
     RECT  102.288 25.189 102.312 25.237 ;
     RECT  102.288 25.237 102.408 25.523 ;
     RECT  69.9 2.151 70.212 26.293 ;
     RECT  78 2.151 78.312 26.293 ;
     RECT  86.1 2.151 86.412 26.293 ;
     RECT  69.9 26.293 70.728 26.627 ;
     RECT  78 26.293 78.696 26.627 ;
     RECT  86.1 26.293 86.664 26.627 ;
     RECT  69.9 26.627 70.212 27.685 ;
     RECT  69.9 27.685 70.392 27.923 ;
     RECT  69.9 27.923 70.212 31.477 ;
     RECT  69.9 31.477 70.392 31.763 ;
     RECT  69.9 31.763 70.212 34.357 ;
     RECT  53.7 2.151 54.012 34.453 ;
     RECT  69.9 34.357 70.392 34.453 ;
     RECT  86.1 26.627 86.412 34.453 ;
     RECT  91.5 2.151 91.812 34.453 ;
     RECT  78 26.627 78.312 34.549 ;
     RECT  53.7 34.453 54.744 34.739 ;
     RECT  69.9 34.453 70.728 34.739 ;
     RECT  78 34.549 78.696 34.739 ;
     RECT  86.1 34.453 86.664 34.739 ;
     RECT  90.624 34.453 91.812 34.787 ;
     RECT  78 34.739 78.312 37.141 ;
     RECT  86.1 34.739 86.412 37.141 ;
     RECT  86.1 37.141 86.712 37.427 ;
     RECT  78 37.141 78.456 37.619 ;
     RECT  78 37.619 78.312 40.021 ;
     RECT  78 40.021 78.648 40.163 ;
     RECT  61.8 2.151 62.112 40.261 ;
     RECT  61.8 40.261 62.232 40.403 ;
     RECT  40.2 2.151 40.512 41.173 ;
     RECT  34.8 2.151 35.112 41.365 ;
     RECT  42.9 2.151 43.212 41.413 ;
     RECT  45.6 2.151 45.912 41.749 ;
     RECT  39.552 41.173 40.512 41.893 ;
     RECT  34.8 41.365 35.208 41.989 ;
     RECT  61.8 40.403 62.112 41.989 ;
     RECT  37.5 2.151 37.812 42.037 ;
     RECT  39.552 41.893 41.016 42.037 ;
     RECT  49.728 41.269 49.752 42.085 ;
     RECT  51 2.151 51.312 42.085 ;
     RECT  34.8 41.989 35.88 42.517 ;
     RECT  37.5 42.037 41.016 42.517 ;
     RECT  59.1 2.151 59.412 42.709 ;
     RECT  34.8 42.517 41.016 42.997 ;
     RECT  42.384 41.413 43.212 42.997 ;
     RECT  69.9 34.739 70.212 43.525 ;
     RECT  59.1 42.709 59.88 43.717 ;
     RECT  61.344 41.989 62.112 43.717 ;
     RECT  59.1 43.717 62.112 43.813 ;
     RECT  67.2 2.151 67.512 44.149 ;
     RECT  66.768 44.149 67.512 44.869 ;
     RECT  68.976 43.525 70.212 44.869 ;
     RECT  59.1 43.813 62.28 44.965 ;
     RECT  49.728 42.085 51.312 46.165 ;
     RECT  52.368 46.117 52.392 46.165 ;
     RECT  66.768 44.869 70.212 46.213 ;
     RECT  49.728 46.165 52.392 46.597 ;
     RECT  53.7 34.739 54.012 46.597 ;
     RECT  59.1 44.965 62.52 47.845 ;
     RECT  64.5 2.151 64.812 48.133 ;
     RECT  56.4 2.151 56.712 48.421 ;
     RECT  55.584 48.421 56.712 48.469 ;
     RECT  59.1 47.845 62.808 48.469 ;
     RECT  34.8 42.997 43.212 48.709 ;
     RECT  44.688 41.749 45.912 48.901 ;
     RECT  63.888 48.133 64.812 48.901 ;
     RECT  55.488 48.469 56.712 48.997 ;
     RECT  58.128 48.469 62.808 48.997 ;
     RECT  63.84 48.901 64.812 49.237 ;
     RECT  63.84 49.237 65.016 49.813 ;
     RECT  66.144 46.213 70.212 49.813 ;
     RECT  34.704 48.709 43.212 50.101 ;
     RECT  63.84 49.813 70.212 50.771 ;
     RECT  34.704 50.101 43.704 51.109 ;
     RECT  34.512 51.109 43.704 51.157 ;
     RECT  48.3 2.151 48.612 51.781 ;
     RECT  34.176 51.157 43.704 52.405 ;
     RECT  44.688 48.901 46.392 52.405 ;
     RECT  55.392 48.997 56.712 52.405 ;
     RECT  57.888 48.997 62.808 52.405 ;
     RECT  49.728 46.597 54.012 53.029 ;
     RECT  55.392 52.405 62.808 53.029 ;
     RECT  49.728 53.029 62.808 54.709 ;
     RECT  34.176 52.405 46.392 56.773 ;
     RECT  47.568 51.781 48.612 56.773 ;
     RECT  49.728 54.709 62.904 58.645 ;
     RECT  63.888 50.771 70.212 58.645 ;
     RECT  34.176 56.773 48.612 60.085 ;
     RECT  34.128 60.085 48.612 64.645 ;
     RECT  49.728 58.645 70.212 64.645 ;
     RECT  34.128 64.645 70.212 66.517 ;
     RECT  34.128 66.517 70.344 66.659 ;
     RECT  32.1 2.151 32.412 67.093 ;
     RECT  34.128 66.659 70.212 67.093 ;
     RECT  32.1 67.093 70.212 72.661 ;
     RECT  32.1 72.661 70.344 72.803 ;
     RECT  32.1 72.803 70.212 78.997 ;
     RECT  32.1 78.997 70.344 79.187 ;
     RECT  0.192 52.837 0.216 89.555 ;
     RECT  32.1 79.187 70.212 102.083 ;
     RECT  33.504 102.083 67.896 102.419 ;
     RECT  34.656 102.419 67.896 102.467 ;
     RECT  33.504 102.419 33.528 102.659 ;
     RECT  34.704 102.467 67.896 102.755 ;
     RECT  34.8 102.755 67.896 102.803 ;
     RECT  68.976 102.083 70.212 102.995 ;
     RECT  36.864 102.803 67.512 103.091 ;
     RECT  36.864 103.091 41.784 103.187 ;
     RECT  36.864 103.187 41.544 103.235 ;
     RECT  42.768 103.091 67.512 103.283 ;
     RECT  34.8 102.803 35.88 103.331 ;
     RECT  2.4 2.151 2.712 103.419 ;
     RECT  5.1 2.151 5.412 103.419 ;
     RECT  7.8 2.151 8.112 103.419 ;
     RECT  10.5 2.151 10.812 103.419 ;
     RECT  13.2 2.151 13.512 103.419 ;
     RECT  15.9 2.151 16.212 103.419 ;
     RECT  18.6 2.151 18.912 103.419 ;
     RECT  21.3 2.151 21.612 103.419 ;
     RECT  24 2.151 24.312 103.419 ;
     RECT  26.7 2.151 27.012 103.419 ;
     RECT  29.4 2.151 29.712 103.419 ;
     RECT  32.1 102.083 32.412 103.419 ;
     RECT  34.8 103.331 35.112 103.419 ;
     RECT  37.5 103.235 38.232 103.419 ;
     RECT  42.9 103.283 65.16 103.419 ;
     RECT  69.9 102.995 70.212 103.419 ;
     RECT  72.6 2.151 72.912 103.419 ;
     RECT  75.3 2.151 75.612 103.419 ;
     RECT  78 40.163 78.312 103.419 ;
     RECT  80.7 2.151 81.012 103.419 ;
     RECT  83.4 2.151 83.712 103.419 ;
     RECT  86.1 37.427 86.412 103.419 ;
     RECT  88.8 2.151 89.112 103.419 ;
     RECT  91.5 34.787 91.812 103.419 ;
     RECT  94.2 2.151 94.512 103.419 ;
     RECT  96.9 2.151 97.212 103.419 ;
     RECT  99.6 2.151 99.912 103.419 ;
     RECT  2.592 103.419 2.712 103.433 ;
     RECT  5.292 103.419 5.412 103.433 ;
     RECT  7.992 103.419 8.112 103.433 ;
     RECT  10.692 103.419 10.812 103.433 ;
     RECT  13.392 103.419 13.512 103.433 ;
     RECT  16.092 103.419 16.212 103.433 ;
     RECT  18.792 103.419 18.912 103.433 ;
     RECT  21.492 103.419 21.612 103.433 ;
     RECT  24.192 103.419 24.312 103.433 ;
     RECT  26.892 103.419 27.012 103.433 ;
     RECT  29.592 103.419 29.712 103.433 ;
     RECT  32.292 103.419 32.412 103.433 ;
     RECT  34.992 103.419 35.112 103.433 ;
     RECT  37.692 103.419 38.232 103.433 ;
     RECT  39.456 103.235 40.512 103.433 ;
     RECT  43.092 103.419 65.16 103.433 ;
     RECT  66.72 103.283 67.512 103.433 ;
     RECT  70.092 103.419 70.212 103.433 ;
     RECT  72.792 103.419 72.912 103.433 ;
     RECT  75.492 103.419 75.612 103.433 ;
     RECT  78.192 103.419 78.312 103.433 ;
     RECT  80.892 103.419 81.012 103.433 ;
     RECT  83.592 103.419 83.712 103.433 ;
     RECT  86.292 103.419 86.412 103.433 ;
     RECT  88.992 103.419 89.112 103.433 ;
     RECT  91.692 103.419 91.812 103.433 ;
     RECT  94.392 103.419 94.512 103.433 ;
     RECT  97.092 103.419 97.212 103.433 ;
     RECT  99.792 103.419 99.912 103.433 ;
     RECT  43.296 103.433 65.16 103.763 ;
     RECT  43.44 103.763 65.16 103.811 ;
     RECT  66.72 103.433 66.744 104.339 ;
     RECT  43.44 103.811 64.968 105.744 ;
     RECT  38.208 103.433 38.232 105.779 ;
     RECT  39.456 103.433 39.48 105.779 ;
     RECT  41.52 103.235 41.544 105.779 ;
  END
END qfd_rlyh_600_NE_104x106
END LIBRARY
